VERSION 5.8 ;
BUSBITCHARS "[]" ;
DIVIDERCHAR "/" ;
UNITS
    DATABASE MICRONS 1000 ;
END UNITS

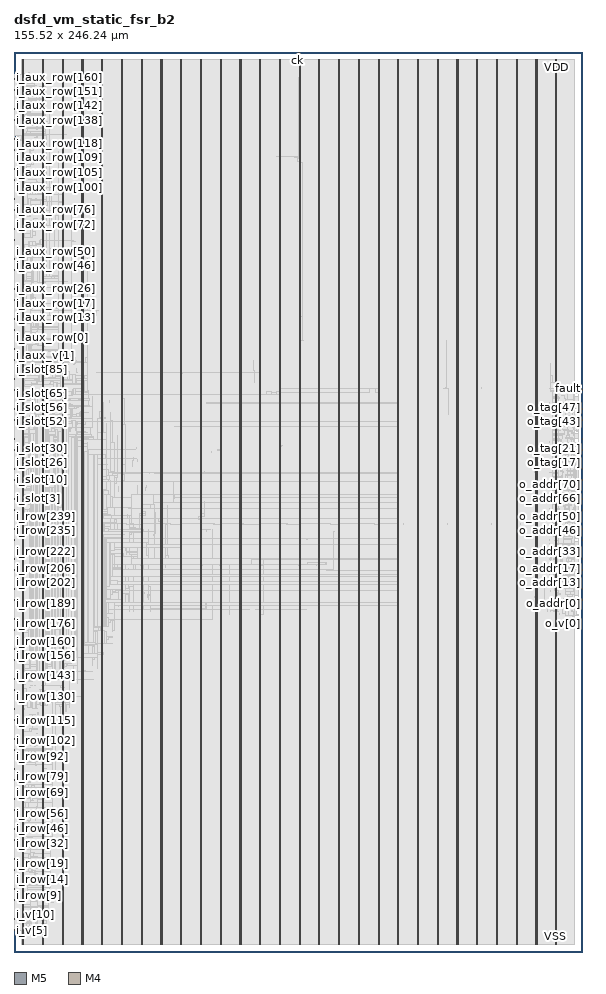
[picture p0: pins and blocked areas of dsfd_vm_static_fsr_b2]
MACRO dsfd_vm_static_fsr_b2
  FOREIGN dsfd_vm_static_fsr_b2 0 0 ;
  CLASS BLOCK ;
  SIZE 155.52 BY 246.24 ;
  PIN ck
    DIRECTION INPUT ;
    USE SIGNAL ;
    PORT
      LAYER M5 ;
        RECT  77.52 246.156 77.544 246.24 ;
    END
  END ck
  PIN fault
    DIRECTION OUTPUT ;
    USE SIGNAL ;
    PORT
      LAYER M4 ;
        RECT  155.436 154.176 155.52 154.2 ;
    END
  END fault
  PIN i_aux_row[0]
    DIRECTION INPUT ;
    USE SIGNAL ;
    PORT
      LAYER M4 ;
        RECT  0 168 0.084 168.024 ;
    END
  END i_aux_row[0]
  PIN i_aux_row[100]
    DIRECTION INPUT ;
    USE SIGNAL ;
    PORT
      LAYER M4 ;
        RECT  0 211.2 0.084 211.224 ;
    END
  END i_aux_row[100]
  PIN i_aux_row[101]
    DIRECTION INPUT ;
    USE SIGNAL ;
    PORT
      LAYER M4 ;
        RECT  0 211.632 0.084 211.656 ;
    END
  END i_aux_row[101]
  PIN i_aux_row[102]
    DIRECTION INPUT ;
    USE SIGNAL ;
    PORT
      LAYER M4 ;
        RECT  0 212.064 0.084 212.088 ;
    END
  END i_aux_row[102]
  PIN i_aux_row[103]
    DIRECTION INPUT ;
    USE SIGNAL ;
    PORT
      LAYER M4 ;
        RECT  0 212.496 0.084 212.52 ;
    END
  END i_aux_row[103]
  PIN i_aux_row[104]
    DIRECTION INPUT ;
    USE SIGNAL ;
    PORT
      LAYER M4 ;
        RECT  0 212.928 0.084 212.952 ;
    END
  END i_aux_row[104]
  PIN i_aux_row[105]
    DIRECTION INPUT ;
    USE SIGNAL ;
    PORT
      LAYER M4 ;
        RECT  0 213.36 0.084 213.384 ;
    END
  END i_aux_row[105]
  PIN i_aux_row[106]
    DIRECTION INPUT ;
    USE SIGNAL ;
    PORT
      LAYER M4 ;
        RECT  0 213.792 0.084 213.816 ;
    END
  END i_aux_row[106]
  PIN i_aux_row[107]
    DIRECTION INPUT ;
    USE SIGNAL ;
    PORT
      LAYER M4 ;
        RECT  0 214.224 0.084 214.248 ;
    END
  END i_aux_row[107]
  PIN i_aux_row[108]
    DIRECTION INPUT ;
    USE SIGNAL ;
    PORT
      LAYER M4 ;
        RECT  0 214.656 0.084 214.68 ;
    END
  END i_aux_row[108]
  PIN i_aux_row[109]
    DIRECTION INPUT ;
    USE SIGNAL ;
    PORT
      LAYER M4 ;
        RECT  0 215.088 0.084 215.112 ;
    END
  END i_aux_row[109]
  PIN i_aux_row[10]
    DIRECTION INPUT ;
    USE SIGNAL ;
    PORT
      LAYER M4 ;
        RECT  0 172.32 0.084 172.344 ;
    END
  END i_aux_row[10]
  PIN i_aux_row[110]
    DIRECTION INPUT ;
    USE SIGNAL ;
    PORT
      LAYER M4 ;
        RECT  0 215.52 0.084 215.544 ;
    END
  END i_aux_row[110]
  PIN i_aux_row[111]
    DIRECTION INPUT ;
    USE SIGNAL ;
    PORT
      LAYER M4 ;
        RECT  0 215.952 0.084 215.976 ;
    END
  END i_aux_row[111]
  PIN i_aux_row[112]
    DIRECTION INPUT ;
    USE SIGNAL ;
    PORT
      LAYER M4 ;
        RECT  0 216.384 0.084 216.408 ;
    END
  END i_aux_row[112]
  PIN i_aux_row[113]
    DIRECTION INPUT ;
    USE SIGNAL ;
    PORT
      LAYER M4 ;
        RECT  0 216.816 0.084 216.84 ;
    END
  END i_aux_row[113]
  PIN i_aux_row[114]
    DIRECTION INPUT ;
    USE SIGNAL ;
    PORT
      LAYER M4 ;
        RECT  0 217.248 0.084 217.272 ;
    END
  END i_aux_row[114]
  PIN i_aux_row[115]
    DIRECTION INPUT ;
    USE SIGNAL ;
    PORT
      LAYER M4 ;
        RECT  0 217.68 0.084 217.704 ;
    END
  END i_aux_row[115]
  PIN i_aux_row[116]
    DIRECTION INPUT ;
    USE SIGNAL ;
    PORT
      LAYER M4 ;
        RECT  0 218.112 0.084 218.136 ;
    END
  END i_aux_row[116]
  PIN i_aux_row[117]
    DIRECTION INPUT ;
    USE SIGNAL ;
    PORT
      LAYER M4 ;
        RECT  0 218.544 0.084 218.568 ;
    END
  END i_aux_row[117]
  PIN i_aux_row[118]
    DIRECTION INPUT ;
    USE SIGNAL ;
    PORT
      LAYER M4 ;
        RECT  0 218.976 0.084 219 ;
    END
  END i_aux_row[118]
  PIN i_aux_row[119]
    DIRECTION INPUT ;
    USE SIGNAL ;
    PORT
      LAYER M4 ;
        RECT  0 219.408 0.084 219.432 ;
    END
  END i_aux_row[119]
  PIN i_aux_row[11]
    DIRECTION INPUT ;
    USE SIGNAL ;
    PORT
      LAYER M4 ;
        RECT  0 172.752 0.084 172.776 ;
    END
  END i_aux_row[11]
  PIN i_aux_row[120]
    DIRECTION INPUT ;
    USE SIGNAL ;
    PORT
      LAYER M4 ;
        RECT  0 219.84 0.084 219.864 ;
    END
  END i_aux_row[120]
  PIN i_aux_row[121]
    DIRECTION INPUT ;
    USE SIGNAL ;
    PORT
      LAYER M4 ;
        RECT  0 220.272 0.084 220.296 ;
    END
  END i_aux_row[121]
  PIN i_aux_row[122]
    DIRECTION INPUT ;
    USE SIGNAL ;
    PORT
      LAYER M4 ;
        RECT  0 220.704 0.084 220.728 ;
    END
  END i_aux_row[122]
  PIN i_aux_row[123]
    DIRECTION INPUT ;
    USE SIGNAL ;
    PORT
      LAYER M4 ;
        RECT  0 221.136 0.084 221.16 ;
    END
  END i_aux_row[123]
  PIN i_aux_row[124]
    DIRECTION INPUT ;
    USE SIGNAL ;
    PORT
      LAYER M4 ;
        RECT  0 221.568 0.084 221.592 ;
    END
  END i_aux_row[124]
  PIN i_aux_row[125]
    DIRECTION INPUT ;
    USE SIGNAL ;
    PORT
      LAYER M4 ;
        RECT  0 222 0.084 222.024 ;
    END
  END i_aux_row[125]
  PIN i_aux_row[126]
    DIRECTION INPUT ;
    USE SIGNAL ;
    PORT
      LAYER M4 ;
        RECT  0 222.432 0.084 222.456 ;
    END
  END i_aux_row[126]
  PIN i_aux_row[127]
    DIRECTION INPUT ;
    USE SIGNAL ;
    PORT
      LAYER M4 ;
        RECT  0 222.864 0.084 222.888 ;
    END
  END i_aux_row[127]
  PIN i_aux_row[128]
    DIRECTION INPUT ;
    USE SIGNAL ;
    PORT
      LAYER M4 ;
        RECT  0 223.296 0.084 223.32 ;
    END
  END i_aux_row[128]
  PIN i_aux_row[129]
    DIRECTION INPUT ;
    USE SIGNAL ;
    PORT
      LAYER M4 ;
        RECT  0 223.728 0.084 223.752 ;
    END
  END i_aux_row[129]
  PIN i_aux_row[12]
    DIRECTION INPUT ;
    USE SIGNAL ;
    PORT
      LAYER M4 ;
        RECT  0 173.184 0.084 173.208 ;
    END
  END i_aux_row[12]
  PIN i_aux_row[130]
    DIRECTION INPUT ;
    USE SIGNAL ;
    PORT
      LAYER M4 ;
        RECT  0 224.16 0.084 224.184 ;
    END
  END i_aux_row[130]
  PIN i_aux_row[131]
    DIRECTION INPUT ;
    USE SIGNAL ;
    PORT
      LAYER M4 ;
        RECT  0 224.592 0.084 224.616 ;
    END
  END i_aux_row[131]
  PIN i_aux_row[132]
    DIRECTION INPUT ;
    USE SIGNAL ;
    PORT
      LAYER M4 ;
        RECT  0 225.024 0.084 225.048 ;
    END
  END i_aux_row[132]
  PIN i_aux_row[133]
    DIRECTION INPUT ;
    USE SIGNAL ;
    PORT
      LAYER M4 ;
        RECT  0 225.456 0.084 225.48 ;
    END
  END i_aux_row[133]
  PIN i_aux_row[134]
    DIRECTION INPUT ;
    USE SIGNAL ;
    PORT
      LAYER M4 ;
        RECT  0 225.888 0.084 225.912 ;
    END
  END i_aux_row[134]
  PIN i_aux_row[135]
    DIRECTION INPUT ;
    USE SIGNAL ;
    PORT
      LAYER M4 ;
        RECT  0 226.32 0.084 226.344 ;
    END
  END i_aux_row[135]
  PIN i_aux_row[136]
    DIRECTION INPUT ;
    USE SIGNAL ;
    PORT
      LAYER M4 ;
        RECT  0 226.752 0.084 226.776 ;
    END
  END i_aux_row[136]
  PIN i_aux_row[137]
    DIRECTION INPUT ;
    USE SIGNAL ;
    PORT
      LAYER M4 ;
        RECT  0 227.184 0.084 227.208 ;
    END
  END i_aux_row[137]
  PIN i_aux_row[138]
    DIRECTION INPUT ;
    USE SIGNAL ;
    PORT
      LAYER M4 ;
        RECT  0 227.616 0.084 227.64 ;
    END
  END i_aux_row[138]
  PIN i_aux_row[139]
    DIRECTION INPUT ;
    USE SIGNAL ;
    PORT
      LAYER M4 ;
        RECT  0 228.048 0.084 228.072 ;
    END
  END i_aux_row[139]
  PIN i_aux_row[13]
    DIRECTION INPUT ;
    USE SIGNAL ;
    PORT
      LAYER M4 ;
        RECT  0 173.616 0.084 173.64 ;
    END
  END i_aux_row[13]
  PIN i_aux_row[140]
    DIRECTION INPUT ;
    USE SIGNAL ;
    PORT
      LAYER M4 ;
        RECT  0 228.48 0.084 228.504 ;
    END
  END i_aux_row[140]
  PIN i_aux_row[141]
    DIRECTION INPUT ;
    USE SIGNAL ;
    PORT
      LAYER M4 ;
        RECT  0 228.912 0.084 228.936 ;
    END
  END i_aux_row[141]
  PIN i_aux_row[142]
    DIRECTION INPUT ;
    USE SIGNAL ;
    PORT
      LAYER M4 ;
        RECT  0 229.344 0.084 229.368 ;
    END
  END i_aux_row[142]
  PIN i_aux_row[143]
    DIRECTION INPUT ;
    USE SIGNAL ;
    PORT
      LAYER M4 ;
        RECT  0 229.776 0.084 229.8 ;
    END
  END i_aux_row[143]
  PIN i_aux_row[144]
    DIRECTION INPUT ;
    USE SIGNAL ;
    PORT
      LAYER M4 ;
        RECT  0 230.208 0.084 230.232 ;
    END
  END i_aux_row[144]
  PIN i_aux_row[145]
    DIRECTION INPUT ;
    USE SIGNAL ;
    PORT
      LAYER M4 ;
        RECT  0 230.64 0.084 230.664 ;
    END
  END i_aux_row[145]
  PIN i_aux_row[146]
    DIRECTION INPUT ;
    USE SIGNAL ;
    PORT
      LAYER M4 ;
        RECT  0 231.072 0.084 231.096 ;
    END
  END i_aux_row[146]
  PIN i_aux_row[147]
    DIRECTION INPUT ;
    USE SIGNAL ;
    PORT
      LAYER M4 ;
        RECT  0 231.504 0.084 231.528 ;
    END
  END i_aux_row[147]
  PIN i_aux_row[148]
    DIRECTION INPUT ;
    USE SIGNAL ;
    PORT
      LAYER M4 ;
        RECT  0 231.936 0.084 231.96 ;
    END
  END i_aux_row[148]
  PIN i_aux_row[149]
    DIRECTION INPUT ;
    USE SIGNAL ;
    PORT
      LAYER M4 ;
        RECT  0 232.368 0.084 232.392 ;
    END
  END i_aux_row[149]
  PIN i_aux_row[14]
    DIRECTION INPUT ;
    USE SIGNAL ;
    PORT
      LAYER M4 ;
        RECT  0 174.048 0.084 174.072 ;
    END
  END i_aux_row[14]
  PIN i_aux_row[150]
    DIRECTION INPUT ;
    USE SIGNAL ;
    PORT
      LAYER M4 ;
        RECT  0 232.8 0.084 232.824 ;
    END
  END i_aux_row[150]
  PIN i_aux_row[151]
    DIRECTION INPUT ;
    USE SIGNAL ;
    PORT
      LAYER M4 ;
        RECT  0 233.232 0.084 233.256 ;
    END
  END i_aux_row[151]
  PIN i_aux_row[152]
    DIRECTION INPUT ;
    USE SIGNAL ;
    PORT
      LAYER M4 ;
        RECT  0 233.664 0.084 233.688 ;
    END
  END i_aux_row[152]
  PIN i_aux_row[153]
    DIRECTION INPUT ;
    USE SIGNAL ;
    PORT
      LAYER M4 ;
        RECT  0 234.096 0.084 234.12 ;
    END
  END i_aux_row[153]
  PIN i_aux_row[154]
    DIRECTION INPUT ;
    USE SIGNAL ;
    PORT
      LAYER M4 ;
        RECT  0 234.528 0.084 234.552 ;
    END
  END i_aux_row[154]
  PIN i_aux_row[155]
    DIRECTION INPUT ;
    USE SIGNAL ;
    PORT
      LAYER M4 ;
        RECT  0 234.96 0.084 234.984 ;
    END
  END i_aux_row[155]
  PIN i_aux_row[156]
    DIRECTION INPUT ;
    USE SIGNAL ;
    PORT
      LAYER M4 ;
        RECT  0 235.392 0.084 235.416 ;
    END
  END i_aux_row[156]
  PIN i_aux_row[157]
    DIRECTION INPUT ;
    USE SIGNAL ;
    PORT
      LAYER M4 ;
        RECT  0 235.824 0.084 235.848 ;
    END
  END i_aux_row[157]
  PIN i_aux_row[158]
    DIRECTION INPUT ;
    USE SIGNAL ;
    PORT
      LAYER M4 ;
        RECT  0 236.256 0.084 236.28 ;
    END
  END i_aux_row[158]
  PIN i_aux_row[159]
    DIRECTION INPUT ;
    USE SIGNAL ;
    PORT
      LAYER M4 ;
        RECT  0 236.688 0.084 236.712 ;
    END
  END i_aux_row[159]
  PIN i_aux_row[15]
    DIRECTION INPUT ;
    USE SIGNAL ;
    PORT
      LAYER M4 ;
        RECT  0 174.48 0.084 174.504 ;
    END
  END i_aux_row[15]
  PIN i_aux_row[160]
    DIRECTION INPUT ;
    USE SIGNAL ;
    PORT
      LAYER M4 ;
        RECT  0 237.12 0.084 237.144 ;
    END
  END i_aux_row[160]
  PIN i_aux_row[161]
    DIRECTION INPUT ;
    USE SIGNAL ;
    PORT
      LAYER M4 ;
        RECT  0 237.552 0.084 237.576 ;
    END
  END i_aux_row[161]
  PIN i_aux_row[162]
    DIRECTION INPUT ;
    USE SIGNAL ;
    PORT
      LAYER M4 ;
        RECT  0 237.984 0.084 238.008 ;
    END
  END i_aux_row[162]
  PIN i_aux_row[163]
    DIRECTION INPUT ;
    USE SIGNAL ;
    PORT
      LAYER M4 ;
        RECT  0 238.416 0.084 238.44 ;
    END
  END i_aux_row[163]
  PIN i_aux_row[164]
    DIRECTION INPUT ;
    USE SIGNAL ;
    PORT
      LAYER M4 ;
        RECT  0 238.848 0.084 238.872 ;
    END
  END i_aux_row[164]
  PIN i_aux_row[165]
    DIRECTION INPUT ;
    USE SIGNAL ;
    PORT
      LAYER M4 ;
        RECT  0 239.28 0.084 239.304 ;
    END
  END i_aux_row[165]
  PIN i_aux_row[166]
    DIRECTION INPUT ;
    USE SIGNAL ;
    PORT
      LAYER M4 ;
        RECT  0 239.712 0.084 239.736 ;
    END
  END i_aux_row[166]
  PIN i_aux_row[167]
    DIRECTION INPUT ;
    USE SIGNAL ;
    PORT
      LAYER M4 ;
        RECT  0 240.144 0.084 240.168 ;
    END
  END i_aux_row[167]
  PIN i_aux_row[16]
    DIRECTION INPUT ;
    USE SIGNAL ;
    PORT
      LAYER M4 ;
        RECT  0 174.912 0.084 174.936 ;
    END
  END i_aux_row[16]
  PIN i_aux_row[17]
    DIRECTION INPUT ;
    USE SIGNAL ;
    PORT
      LAYER M4 ;
        RECT  0 175.344 0.084 175.368 ;
    END
  END i_aux_row[17]
  PIN i_aux_row[18]
    DIRECTION INPUT ;
    USE SIGNAL ;
    PORT
      LAYER M4 ;
        RECT  0 175.776 0.084 175.8 ;
    END
  END i_aux_row[18]
  PIN i_aux_row[19]
    DIRECTION INPUT ;
    USE SIGNAL ;
    PORT
      LAYER M4 ;
        RECT  0 176.208 0.084 176.232 ;
    END
  END i_aux_row[19]
  PIN i_aux_row[1]
    DIRECTION INPUT ;
    USE SIGNAL ;
    PORT
      LAYER M4 ;
        RECT  0 168.432 0.084 168.456 ;
    END
  END i_aux_row[1]
  PIN i_aux_row[20]
    DIRECTION INPUT ;
    USE SIGNAL ;
    PORT
      LAYER M4 ;
        RECT  0 176.64 0.084 176.664 ;
    END
  END i_aux_row[20]
  PIN i_aux_row[21]
    DIRECTION INPUT ;
    USE SIGNAL ;
    PORT
      LAYER M4 ;
        RECT  0 177.072 0.084 177.096 ;
    END
  END i_aux_row[21]
  PIN i_aux_row[22]
    DIRECTION INPUT ;
    USE SIGNAL ;
    PORT
      LAYER M4 ;
        RECT  0 177.504 0.084 177.528 ;
    END
  END i_aux_row[22]
  PIN i_aux_row[23]
    DIRECTION INPUT ;
    USE SIGNAL ;
    PORT
      LAYER M4 ;
        RECT  0 177.936 0.084 177.96 ;
    END
  END i_aux_row[23]
  PIN i_aux_row[24]
    DIRECTION INPUT ;
    USE SIGNAL ;
    PORT
      LAYER M4 ;
        RECT  0 178.368 0.084 178.392 ;
    END
  END i_aux_row[24]
  PIN i_aux_row[25]
    DIRECTION INPUT ;
    USE SIGNAL ;
    PORT
      LAYER M4 ;
        RECT  0 178.8 0.084 178.824 ;
    END
  END i_aux_row[25]
  PIN i_aux_row[26]
    DIRECTION INPUT ;
    USE SIGNAL ;
    PORT
      LAYER M4 ;
        RECT  0 179.232 0.084 179.256 ;
    END
  END i_aux_row[26]
  PIN i_aux_row[27]
    DIRECTION INPUT ;
    USE SIGNAL ;
    PORT
      LAYER M4 ;
        RECT  0 179.664 0.084 179.688 ;
    END
  END i_aux_row[27]
  PIN i_aux_row[28]
    DIRECTION INPUT ;
    USE SIGNAL ;
    PORT
      LAYER M4 ;
        RECT  0 180.096 0.084 180.12 ;
    END
  END i_aux_row[28]
  PIN i_aux_row[29]
    DIRECTION INPUT ;
    USE SIGNAL ;
    PORT
      LAYER M4 ;
        RECT  0 180.528 0.084 180.552 ;
    END
  END i_aux_row[29]
  PIN i_aux_row[2]
    DIRECTION INPUT ;
    USE SIGNAL ;
    PORT
      LAYER M4 ;
        RECT  0 168.864 0.084 168.888 ;
    END
  END i_aux_row[2]
  PIN i_aux_row[30]
    DIRECTION INPUT ;
    USE SIGNAL ;
    PORT
      LAYER M4 ;
        RECT  0 180.96 0.084 180.984 ;
    END
  END i_aux_row[30]
  PIN i_aux_row[31]
    DIRECTION INPUT ;
    USE SIGNAL ;
    PORT
      LAYER M4 ;
        RECT  0 181.392 0.084 181.416 ;
    END
  END i_aux_row[31]
  PIN i_aux_row[32]
    DIRECTION INPUT ;
    USE SIGNAL ;
    PORT
      LAYER M4 ;
        RECT  0 181.824 0.084 181.848 ;
    END
  END i_aux_row[32]
  PIN i_aux_row[33]
    DIRECTION INPUT ;
    USE SIGNAL ;
    PORT
      LAYER M4 ;
        RECT  0 182.256 0.084 182.28 ;
    END
  END i_aux_row[33]
  PIN i_aux_row[34]
    DIRECTION INPUT ;
    USE SIGNAL ;
    PORT
      LAYER M4 ;
        RECT  0 182.688 0.084 182.712 ;
    END
  END i_aux_row[34]
  PIN i_aux_row[35]
    DIRECTION INPUT ;
    USE SIGNAL ;
    PORT
      LAYER M4 ;
        RECT  0 183.12 0.084 183.144 ;
    END
  END i_aux_row[35]
  PIN i_aux_row[36]
    DIRECTION INPUT ;
    USE SIGNAL ;
    PORT
      LAYER M4 ;
        RECT  0 183.552 0.084 183.576 ;
    END
  END i_aux_row[36]
  PIN i_aux_row[37]
    DIRECTION INPUT ;
    USE SIGNAL ;
    PORT
      LAYER M4 ;
        RECT  0 183.984 0.084 184.008 ;
    END
  END i_aux_row[37]
  PIN i_aux_row[38]
    DIRECTION INPUT ;
    USE SIGNAL ;
    PORT
      LAYER M4 ;
        RECT  0 184.416 0.084 184.44 ;
    END
  END i_aux_row[38]
  PIN i_aux_row[39]
    DIRECTION INPUT ;
    USE SIGNAL ;
    PORT
      LAYER M4 ;
        RECT  0 184.848 0.084 184.872 ;
    END
  END i_aux_row[39]
  PIN i_aux_row[3]
    DIRECTION INPUT ;
    USE SIGNAL ;
    PORT
      LAYER M4 ;
        RECT  0 169.296 0.084 169.32 ;
    END
  END i_aux_row[3]
  PIN i_aux_row[40]
    DIRECTION INPUT ;
    USE SIGNAL ;
    PORT
      LAYER M4 ;
        RECT  0 185.28 0.084 185.304 ;
    END
  END i_aux_row[40]
  PIN i_aux_row[41]
    DIRECTION INPUT ;
    USE SIGNAL ;
    PORT
      LAYER M4 ;
        RECT  0 185.712 0.084 185.736 ;
    END
  END i_aux_row[41]
  PIN i_aux_row[42]
    DIRECTION INPUT ;
    USE SIGNAL ;
    PORT
      LAYER M4 ;
        RECT  0 186.144 0.084 186.168 ;
    END
  END i_aux_row[42]
  PIN i_aux_row[43]
    DIRECTION INPUT ;
    USE SIGNAL ;
    PORT
      LAYER M4 ;
        RECT  0 186.576 0.084 186.6 ;
    END
  END i_aux_row[43]
  PIN i_aux_row[44]
    DIRECTION INPUT ;
    USE SIGNAL ;
    PORT
      LAYER M4 ;
        RECT  0 187.008 0.084 187.032 ;
    END
  END i_aux_row[44]
  PIN i_aux_row[45]
    DIRECTION INPUT ;
    USE SIGNAL ;
    PORT
      LAYER M4 ;
        RECT  0 187.44 0.084 187.464 ;
    END
  END i_aux_row[45]
  PIN i_aux_row[46]
    DIRECTION INPUT ;
    USE SIGNAL ;
    PORT
      LAYER M4 ;
        RECT  0 187.872 0.084 187.896 ;
    END
  END i_aux_row[46]
  PIN i_aux_row[47]
    DIRECTION INPUT ;
    USE SIGNAL ;
    PORT
      LAYER M4 ;
        RECT  0 188.304 0.084 188.328 ;
    END
  END i_aux_row[47]
  PIN i_aux_row[48]
    DIRECTION INPUT ;
    USE SIGNAL ;
    PORT
      LAYER M4 ;
        RECT  0 188.736 0.084 188.76 ;
    END
  END i_aux_row[48]
  PIN i_aux_row[49]
    DIRECTION INPUT ;
    USE SIGNAL ;
    PORT
      LAYER M4 ;
        RECT  0 189.168 0.084 189.192 ;
    END
  END i_aux_row[49]
  PIN i_aux_row[4]
    DIRECTION INPUT ;
    USE SIGNAL ;
    PORT
      LAYER M4 ;
        RECT  0 169.728 0.084 169.752 ;
    END
  END i_aux_row[4]
  PIN i_aux_row[50]
    DIRECTION INPUT ;
    USE SIGNAL ;
    PORT
      LAYER M4 ;
        RECT  0 189.6 0.084 189.624 ;
    END
  END i_aux_row[50]
  PIN i_aux_row[51]
    DIRECTION INPUT ;
    USE SIGNAL ;
    PORT
      LAYER M4 ;
        RECT  0 190.032 0.084 190.056 ;
    END
  END i_aux_row[51]
  PIN i_aux_row[52]
    DIRECTION INPUT ;
    USE SIGNAL ;
    PORT
      LAYER M4 ;
        RECT  0 190.464 0.084 190.488 ;
    END
  END i_aux_row[52]
  PIN i_aux_row[53]
    DIRECTION INPUT ;
    USE SIGNAL ;
    PORT
      LAYER M4 ;
        RECT  0 190.896 0.084 190.92 ;
    END
  END i_aux_row[53]
  PIN i_aux_row[54]
    DIRECTION INPUT ;
    USE SIGNAL ;
    PORT
      LAYER M4 ;
        RECT  0 191.328 0.084 191.352 ;
    END
  END i_aux_row[54]
  PIN i_aux_row[55]
    DIRECTION INPUT ;
    USE SIGNAL ;
    PORT
      LAYER M4 ;
        RECT  0 191.76 0.084 191.784 ;
    END
  END i_aux_row[55]
  PIN i_aux_row[56]
    DIRECTION INPUT ;
    USE SIGNAL ;
    PORT
      LAYER M4 ;
        RECT  0 192.192 0.084 192.216 ;
    END
  END i_aux_row[56]
  PIN i_aux_row[57]
    DIRECTION INPUT ;
    USE SIGNAL ;
    PORT
      LAYER M4 ;
        RECT  0 192.624 0.084 192.648 ;
    END
  END i_aux_row[57]
  PIN i_aux_row[58]
    DIRECTION INPUT ;
    USE SIGNAL ;
    PORT
      LAYER M4 ;
        RECT  0 193.056 0.084 193.08 ;
    END
  END i_aux_row[58]
  PIN i_aux_row[59]
    DIRECTION INPUT ;
    USE SIGNAL ;
    PORT
      LAYER M4 ;
        RECT  0 193.488 0.084 193.512 ;
    END
  END i_aux_row[59]
  PIN i_aux_row[5]
    DIRECTION INPUT ;
    USE SIGNAL ;
    PORT
      LAYER M4 ;
        RECT  0 170.16 0.084 170.184 ;
    END
  END i_aux_row[5]
  PIN i_aux_row[60]
    DIRECTION INPUT ;
    USE SIGNAL ;
    PORT
      LAYER M4 ;
        RECT  0 193.92 0.084 193.944 ;
    END
  END i_aux_row[60]
  PIN i_aux_row[61]
    DIRECTION INPUT ;
    USE SIGNAL ;
    PORT
      LAYER M4 ;
        RECT  0 194.352 0.084 194.376 ;
    END
  END i_aux_row[61]
  PIN i_aux_row[62]
    DIRECTION INPUT ;
    USE SIGNAL ;
    PORT
      LAYER M4 ;
        RECT  0 194.784 0.084 194.808 ;
    END
  END i_aux_row[62]
  PIN i_aux_row[63]
    DIRECTION INPUT ;
    USE SIGNAL ;
    PORT
      LAYER M4 ;
        RECT  0 195.216 0.084 195.24 ;
    END
  END i_aux_row[63]
  PIN i_aux_row[64]
    DIRECTION INPUT ;
    USE SIGNAL ;
    PORT
      LAYER M4 ;
        RECT  0 195.648 0.084 195.672 ;
    END
  END i_aux_row[64]
  PIN i_aux_row[65]
    DIRECTION INPUT ;
    USE SIGNAL ;
    PORT
      LAYER M4 ;
        RECT  0 196.08 0.084 196.104 ;
    END
  END i_aux_row[65]
  PIN i_aux_row[66]
    DIRECTION INPUT ;
    USE SIGNAL ;
    PORT
      LAYER M4 ;
        RECT  0 196.512 0.084 196.536 ;
    END
  END i_aux_row[66]
  PIN i_aux_row[67]
    DIRECTION INPUT ;
    USE SIGNAL ;
    PORT
      LAYER M4 ;
        RECT  0 196.944 0.084 196.968 ;
    END
  END i_aux_row[67]
  PIN i_aux_row[68]
    DIRECTION INPUT ;
    USE SIGNAL ;
    PORT
      LAYER M4 ;
        RECT  0 197.376 0.084 197.4 ;
    END
  END i_aux_row[68]
  PIN i_aux_row[69]
    DIRECTION INPUT ;
    USE SIGNAL ;
    PORT
      LAYER M4 ;
        RECT  0 197.808 0.084 197.832 ;
    END
  END i_aux_row[69]
  PIN i_aux_row[6]
    DIRECTION INPUT ;
    USE SIGNAL ;
    PORT
      LAYER M4 ;
        RECT  0 170.592 0.084 170.616 ;
    END
  END i_aux_row[6]
  PIN i_aux_row[70]
    DIRECTION INPUT ;
    USE SIGNAL ;
    PORT
      LAYER M4 ;
        RECT  0 198.24 0.084 198.264 ;
    END
  END i_aux_row[70]
  PIN i_aux_row[71]
    DIRECTION INPUT ;
    USE SIGNAL ;
    PORT
      LAYER M4 ;
        RECT  0 198.672 0.084 198.696 ;
    END
  END i_aux_row[71]
  PIN i_aux_row[72]
    DIRECTION INPUT ;
    USE SIGNAL ;
    PORT
      LAYER M4 ;
        RECT  0 199.104 0.084 199.128 ;
    END
  END i_aux_row[72]
  PIN i_aux_row[73]
    DIRECTION INPUT ;
    USE SIGNAL ;
    PORT
      LAYER M4 ;
        RECT  0 199.536 0.084 199.56 ;
    END
  END i_aux_row[73]
  PIN i_aux_row[74]
    DIRECTION INPUT ;
    USE SIGNAL ;
    PORT
      LAYER M4 ;
        RECT  0 199.968 0.084 199.992 ;
    END
  END i_aux_row[74]
  PIN i_aux_row[75]
    DIRECTION INPUT ;
    USE SIGNAL ;
    PORT
      LAYER M4 ;
        RECT  0 200.4 0.084 200.424 ;
    END
  END i_aux_row[75]
  PIN i_aux_row[76]
    DIRECTION INPUT ;
    USE SIGNAL ;
    PORT
      LAYER M4 ;
        RECT  0 200.832 0.084 200.856 ;
    END
  END i_aux_row[76]
  PIN i_aux_row[77]
    DIRECTION INPUT ;
    USE SIGNAL ;
    PORT
      LAYER M4 ;
        RECT  0 201.264 0.084 201.288 ;
    END
  END i_aux_row[77]
  PIN i_aux_row[78]
    DIRECTION INPUT ;
    USE SIGNAL ;
    PORT
      LAYER M4 ;
        RECT  0 201.696 0.084 201.72 ;
    END
  END i_aux_row[78]
  PIN i_aux_row[79]
    DIRECTION INPUT ;
    USE SIGNAL ;
    PORT
      LAYER M4 ;
        RECT  0 202.128 0.084 202.152 ;
    END
  END i_aux_row[79]
  PIN i_aux_row[7]
    DIRECTION INPUT ;
    USE SIGNAL ;
    PORT
      LAYER M4 ;
        RECT  0 171.024 0.084 171.048 ;
    END
  END i_aux_row[7]
  PIN i_aux_row[80]
    DIRECTION INPUT ;
    USE SIGNAL ;
    PORT
      LAYER M4 ;
        RECT  0 202.56 0.084 202.584 ;
    END
  END i_aux_row[80]
  PIN i_aux_row[81]
    DIRECTION INPUT ;
    USE SIGNAL ;
    PORT
      LAYER M4 ;
        RECT  0 202.992 0.084 203.016 ;
    END
  END i_aux_row[81]
  PIN i_aux_row[82]
    DIRECTION INPUT ;
    USE SIGNAL ;
    PORT
      LAYER M4 ;
        RECT  0 203.424 0.084 203.448 ;
    END
  END i_aux_row[82]
  PIN i_aux_row[83]
    DIRECTION INPUT ;
    USE SIGNAL ;
    PORT
      LAYER M4 ;
        RECT  0 203.856 0.084 203.88 ;
    END
  END i_aux_row[83]
  PIN i_aux_row[84]
    DIRECTION INPUT ;
    USE SIGNAL ;
    PORT
      LAYER M4 ;
        RECT  0 204.288 0.084 204.312 ;
    END
  END i_aux_row[84]
  PIN i_aux_row[85]
    DIRECTION INPUT ;
    USE SIGNAL ;
    PORT
      LAYER M4 ;
        RECT  0 204.72 0.084 204.744 ;
    END
  END i_aux_row[85]
  PIN i_aux_row[86]
    DIRECTION INPUT ;
    USE SIGNAL ;
    PORT
      LAYER M4 ;
        RECT  0 205.152 0.084 205.176 ;
    END
  END i_aux_row[86]
  PIN i_aux_row[87]
    DIRECTION INPUT ;
    USE SIGNAL ;
    PORT
      LAYER M4 ;
        RECT  0 205.584 0.084 205.608 ;
    END
  END i_aux_row[87]
  PIN i_aux_row[88]
    DIRECTION INPUT ;
    USE SIGNAL ;
    PORT
      LAYER M4 ;
        RECT  0 206.016 0.084 206.04 ;
    END
  END i_aux_row[88]
  PIN i_aux_row[89]
    DIRECTION INPUT ;
    USE SIGNAL ;
    PORT
      LAYER M4 ;
        RECT  0 206.448 0.084 206.472 ;
    END
  END i_aux_row[89]
  PIN i_aux_row[8]
    DIRECTION INPUT ;
    USE SIGNAL ;
    PORT
      LAYER M4 ;
        RECT  0 171.456 0.084 171.48 ;
    END
  END i_aux_row[8]
  PIN i_aux_row[90]
    DIRECTION INPUT ;
    USE SIGNAL ;
    PORT
      LAYER M4 ;
        RECT  0 206.88 0.084 206.904 ;
    END
  END i_aux_row[90]
  PIN i_aux_row[91]
    DIRECTION INPUT ;
    USE SIGNAL ;
    PORT
      LAYER M4 ;
        RECT  0 207.312 0.084 207.336 ;
    END
  END i_aux_row[91]
  PIN i_aux_row[92]
    DIRECTION INPUT ;
    USE SIGNAL ;
    PORT
      LAYER M4 ;
        RECT  0 207.744 0.084 207.768 ;
    END
  END i_aux_row[92]
  PIN i_aux_row[93]
    DIRECTION INPUT ;
    USE SIGNAL ;
    PORT
      LAYER M4 ;
        RECT  0 208.176 0.084 208.2 ;
    END
  END i_aux_row[93]
  PIN i_aux_row[94]
    DIRECTION INPUT ;
    USE SIGNAL ;
    PORT
      LAYER M4 ;
        RECT  0 208.608 0.084 208.632 ;
    END
  END i_aux_row[94]
  PIN i_aux_row[95]
    DIRECTION INPUT ;
    USE SIGNAL ;
    PORT
      LAYER M4 ;
        RECT  0 209.04 0.084 209.064 ;
    END
  END i_aux_row[95]
  PIN i_aux_row[96]
    DIRECTION INPUT ;
    USE SIGNAL ;
    PORT
      LAYER M4 ;
        RECT  0 209.472 0.084 209.496 ;
    END
  END i_aux_row[96]
  PIN i_aux_row[97]
    DIRECTION INPUT ;
    USE SIGNAL ;
    PORT
      LAYER M4 ;
        RECT  0 209.904 0.084 209.928 ;
    END
  END i_aux_row[97]
  PIN i_aux_row[98]
    DIRECTION INPUT ;
    USE SIGNAL ;
    PORT
      LAYER M4 ;
        RECT  0 210.336 0.084 210.36 ;
    END
  END i_aux_row[98]
  PIN i_aux_row[99]
    DIRECTION INPUT ;
    USE SIGNAL ;
    PORT
      LAYER M4 ;
        RECT  0 210.768 0.084 210.792 ;
    END
  END i_aux_row[99]
  PIN i_aux_row[9]
    DIRECTION INPUT ;
    USE SIGNAL ;
    PORT
      LAYER M4 ;
        RECT  0 171.888 0.084 171.912 ;
    END
  END i_aux_row[9]
  PIN i_aux_v[0]
    DIRECTION INPUT ;
    USE SIGNAL ;
    PORT
      LAYER M4 ;
        RECT  0 162.816 0.084 162.84 ;
    END
  END i_aux_v[0]
  PIN i_aux_v[10]
    DIRECTION INPUT ;
    USE SIGNAL ;
    PORT
      LAYER M4 ;
        RECT  0 167.136 0.084 167.16 ;
    END
  END i_aux_v[10]
  PIN i_aux_v[11]
    DIRECTION INPUT ;
    USE SIGNAL ;
    PORT
      LAYER M4 ;
        RECT  0 167.568 0.084 167.592 ;
    END
  END i_aux_v[11]
  PIN i_aux_v[1]
    DIRECTION INPUT ;
    USE SIGNAL ;
    PORT
      LAYER M4 ;
        RECT  0 163.248 0.084 163.272 ;
    END
  END i_aux_v[1]
  PIN i_aux_v[2]
    DIRECTION INPUT ;
    USE SIGNAL ;
    PORT
      LAYER M4 ;
        RECT  0 163.68 0.084 163.704 ;
    END
  END i_aux_v[2]
  PIN i_aux_v[3]
    DIRECTION INPUT ;
    USE SIGNAL ;
    PORT
      LAYER M4 ;
        RECT  0 164.112 0.084 164.136 ;
    END
  END i_aux_v[3]
  PIN i_aux_v[4]
    DIRECTION INPUT ;
    USE SIGNAL ;
    PORT
      LAYER M4 ;
        RECT  0 164.544 0.084 164.568 ;
    END
  END i_aux_v[4]
  PIN i_aux_v[5]
    DIRECTION INPUT ;
    USE SIGNAL ;
    PORT
      LAYER M4 ;
        RECT  0 164.976 0.084 165 ;
    END
  END i_aux_v[5]
  PIN i_aux_v[6]
    DIRECTION INPUT ;
    USE SIGNAL ;
    PORT
      LAYER M4 ;
        RECT  0 165.408 0.084 165.432 ;
    END
  END i_aux_v[6]
  PIN i_aux_v[7]
    DIRECTION INPUT ;
    USE SIGNAL ;
    PORT
      LAYER M4 ;
        RECT  0 165.84 0.084 165.864 ;
    END
  END i_aux_v[7]
  PIN i_aux_v[8]
    DIRECTION INPUT ;
    USE SIGNAL ;
    PORT
      LAYER M4 ;
        RECT  0 166.272 0.084 166.296 ;
    END
  END i_aux_v[8]
  PIN i_aux_v[9]
    DIRECTION INPUT ;
    USE SIGNAL ;
    PORT
      LAYER M4 ;
        RECT  0 166.704 0.084 166.728 ;
    END
  END i_aux_v[9]
  PIN i_group[0]
    DIRECTION INPUT ;
    USE SIGNAL ;
    PORT
      LAYER M4 ;
        RECT  0 161.52 0.084 161.544 ;
    END
  END i_group[0]
  PIN i_group[1]
    DIRECTION INPUT ;
    USE SIGNAL ;
    PORT
      LAYER M4 ;
        RECT  0 161.952 0.084 161.976 ;
    END
  END i_group[1]
  PIN i_group[2]
    DIRECTION INPUT ;
    USE SIGNAL ;
    PORT
      LAYER M4 ;
        RECT  0 162.384 0.084 162.408 ;
    END
  END i_group[2]
  PIN i_row[0]
    DIRECTION INPUT ;
    USE SIGNAL ;
    PORT
      LAYER M4 ;
        RECT  0 13.776 0.084 13.8 ;
    END
  END i_row[0]
  PIN i_row[100]
    DIRECTION INPUT ;
    USE SIGNAL ;
    PORT
      LAYER M4 ;
        RECT  0 56.976 0.084 57 ;
    END
  END i_row[100]
  PIN i_row[101]
    DIRECTION INPUT ;
    USE SIGNAL ;
    PORT
      LAYER M4 ;
        RECT  0 57.408 0.084 57.432 ;
    END
  END i_row[101]
  PIN i_row[102]
    DIRECTION INPUT ;
    USE SIGNAL ;
    PORT
      LAYER M4 ;
        RECT  0 57.84 0.084 57.864 ;
    END
  END i_row[102]
  PIN i_row[103]
    DIRECTION INPUT ;
    USE SIGNAL ;
    PORT
      LAYER M4 ;
        RECT  0 58.272 0.084 58.296 ;
    END
  END i_row[103]
  PIN i_row[104]
    DIRECTION INPUT ;
    USE SIGNAL ;
    PORT
      LAYER M4 ;
        RECT  0 58.704 0.084 58.728 ;
    END
  END i_row[104]
  PIN i_row[105]
    DIRECTION INPUT ;
    USE SIGNAL ;
    PORT
      LAYER M4 ;
        RECT  0 59.136 0.084 59.16 ;
    END
  END i_row[105]
  PIN i_row[106]
    DIRECTION INPUT ;
    USE SIGNAL ;
    PORT
      LAYER M4 ;
        RECT  0 59.568 0.084 59.592 ;
    END
  END i_row[106]
  PIN i_row[107]
    DIRECTION INPUT ;
    USE SIGNAL ;
    PORT
      LAYER M4 ;
        RECT  0 60 0.084 60.024 ;
    END
  END i_row[107]
  PIN i_row[108]
    DIRECTION INPUT ;
    USE SIGNAL ;
    PORT
      LAYER M4 ;
        RECT  0 60.432 0.084 60.456 ;
    END
  END i_row[108]
  PIN i_row[109]
    DIRECTION INPUT ;
    USE SIGNAL ;
    PORT
      LAYER M4 ;
        RECT  0 60.864 0.084 60.888 ;
    END
  END i_row[109]
  PIN i_row[10]
    DIRECTION INPUT ;
    USE SIGNAL ;
    PORT
      LAYER M4 ;
        RECT  0 18.096 0.084 18.12 ;
    END
  END i_row[10]
  PIN i_row[110]
    DIRECTION INPUT ;
    USE SIGNAL ;
    PORT
      LAYER M4 ;
        RECT  0 61.296 0.084 61.32 ;
    END
  END i_row[110]
  PIN i_row[111]
    DIRECTION INPUT ;
    USE SIGNAL ;
    PORT
      LAYER M4 ;
        RECT  0 61.728 0.084 61.752 ;
    END
  END i_row[111]
  PIN i_row[112]
    DIRECTION INPUT ;
    USE SIGNAL ;
    PORT
      LAYER M4 ;
        RECT  0 62.16 0.084 62.184 ;
    END
  END i_row[112]
  PIN i_row[113]
    DIRECTION INPUT ;
    USE SIGNAL ;
    PORT
      LAYER M4 ;
        RECT  0 62.592 0.084 62.616 ;
    END
  END i_row[113]
  PIN i_row[114]
    DIRECTION INPUT ;
    USE SIGNAL ;
    PORT
      LAYER M4 ;
        RECT  0 63.024 0.084 63.048 ;
    END
  END i_row[114]
  PIN i_row[115]
    DIRECTION INPUT ;
    USE SIGNAL ;
    PORT
      LAYER M4 ;
        RECT  0 63.456 0.084 63.48 ;
    END
  END i_row[115]
  PIN i_row[116]
    DIRECTION INPUT ;
    USE SIGNAL ;
    PORT
      LAYER M4 ;
        RECT  0 63.888 0.084 63.912 ;
    END
  END i_row[116]
  PIN i_row[117]
    DIRECTION INPUT ;
    USE SIGNAL ;
    PORT
      LAYER M4 ;
        RECT  0 64.32 0.084 64.344 ;
    END
  END i_row[117]
  PIN i_row[118]
    DIRECTION INPUT ;
    USE SIGNAL ;
    PORT
      LAYER M4 ;
        RECT  0 64.752 0.084 64.776 ;
    END
  END i_row[118]
  PIN i_row[119]
    DIRECTION INPUT ;
    USE SIGNAL ;
    PORT
      LAYER M4 ;
        RECT  0 65.184 0.084 65.208 ;
    END
  END i_row[119]
  PIN i_row[11]
    DIRECTION INPUT ;
    USE SIGNAL ;
    PORT
      LAYER M4 ;
        RECT  0 18.528 0.084 18.552 ;
    END
  END i_row[11]
  PIN i_row[120]
    DIRECTION INPUT ;
    USE SIGNAL ;
    PORT
      LAYER M4 ;
        RECT  0 65.616 0.084 65.64 ;
    END
  END i_row[120]
  PIN i_row[121]
    DIRECTION INPUT ;
    USE SIGNAL ;
    PORT
      LAYER M4 ;
        RECT  0 66.048 0.084 66.072 ;
    END
  END i_row[121]
  PIN i_row[122]
    DIRECTION INPUT ;
    USE SIGNAL ;
    PORT
      LAYER M4 ;
        RECT  0 66.48 0.084 66.504 ;
    END
  END i_row[122]
  PIN i_row[123]
    DIRECTION INPUT ;
    USE SIGNAL ;
    PORT
      LAYER M4 ;
        RECT  0 66.912 0.084 66.936 ;
    END
  END i_row[123]
  PIN i_row[124]
    DIRECTION INPUT ;
    USE SIGNAL ;
    PORT
      LAYER M4 ;
        RECT  0 67.344 0.084 67.368 ;
    END
  END i_row[124]
  PIN i_row[125]
    DIRECTION INPUT ;
    USE SIGNAL ;
    PORT
      LAYER M4 ;
        RECT  0 67.776 0.084 67.8 ;
    END
  END i_row[125]
  PIN i_row[126]
    DIRECTION INPUT ;
    USE SIGNAL ;
    PORT
      LAYER M4 ;
        RECT  0 68.208 0.084 68.232 ;
    END
  END i_row[126]
  PIN i_row[127]
    DIRECTION INPUT ;
    USE SIGNAL ;
    PORT
      LAYER M4 ;
        RECT  0 68.64 0.084 68.664 ;
    END
  END i_row[127]
  PIN i_row[128]
    DIRECTION INPUT ;
    USE SIGNAL ;
    PORT
      LAYER M4 ;
        RECT  0 69.072 0.084 69.096 ;
    END
  END i_row[128]
  PIN i_row[129]
    DIRECTION INPUT ;
    USE SIGNAL ;
    PORT
      LAYER M4 ;
        RECT  0 69.504 0.084 69.528 ;
    END
  END i_row[129]
  PIN i_row[12]
    DIRECTION INPUT ;
    USE SIGNAL ;
    PORT
      LAYER M4 ;
        RECT  0 18.96 0.084 18.984 ;
    END
  END i_row[12]
  PIN i_row[130]
    DIRECTION INPUT ;
    USE SIGNAL ;
    PORT
      LAYER M4 ;
        RECT  0 69.936 0.084 69.96 ;
    END
  END i_row[130]
  PIN i_row[131]
    DIRECTION INPUT ;
    USE SIGNAL ;
    PORT
      LAYER M4 ;
        RECT  0 70.368 0.084 70.392 ;
    END
  END i_row[131]
  PIN i_row[132]
    DIRECTION INPUT ;
    USE SIGNAL ;
    PORT
      LAYER M4 ;
        RECT  0 70.8 0.084 70.824 ;
    END
  END i_row[132]
  PIN i_row[133]
    DIRECTION INPUT ;
    USE SIGNAL ;
    PORT
      LAYER M4 ;
        RECT  0 71.232 0.084 71.256 ;
    END
  END i_row[133]
  PIN i_row[134]
    DIRECTION INPUT ;
    USE SIGNAL ;
    PORT
      LAYER M4 ;
        RECT  0 71.664 0.084 71.688 ;
    END
  END i_row[134]
  PIN i_row[135]
    DIRECTION INPUT ;
    USE SIGNAL ;
    PORT
      LAYER M4 ;
        RECT  0 72.096 0.084 72.12 ;
    END
  END i_row[135]
  PIN i_row[136]
    DIRECTION INPUT ;
    USE SIGNAL ;
    PORT
      LAYER M4 ;
        RECT  0 72.528 0.084 72.552 ;
    END
  END i_row[136]
  PIN i_row[137]
    DIRECTION INPUT ;
    USE SIGNAL ;
    PORT
      LAYER M4 ;
        RECT  0 72.96 0.084 72.984 ;
    END
  END i_row[137]
  PIN i_row[138]
    DIRECTION INPUT ;
    USE SIGNAL ;
    PORT
      LAYER M4 ;
        RECT  0 73.392 0.084 73.416 ;
    END
  END i_row[138]
  PIN i_row[139]
    DIRECTION INPUT ;
    USE SIGNAL ;
    PORT
      LAYER M4 ;
        RECT  0 73.824 0.084 73.848 ;
    END
  END i_row[139]
  PIN i_row[13]
    DIRECTION INPUT ;
    USE SIGNAL ;
    PORT
      LAYER M4 ;
        RECT  0 19.392 0.084 19.416 ;
    END
  END i_row[13]
  PIN i_row[140]
    DIRECTION INPUT ;
    USE SIGNAL ;
    PORT
      LAYER M4 ;
        RECT  0 74.256 0.084 74.28 ;
    END
  END i_row[140]
  PIN i_row[141]
    DIRECTION INPUT ;
    USE SIGNAL ;
    PORT
      LAYER M4 ;
        RECT  0 74.688 0.084 74.712 ;
    END
  END i_row[141]
  PIN i_row[142]
    DIRECTION INPUT ;
    USE SIGNAL ;
    PORT
      LAYER M4 ;
        RECT  0 75.12 0.084 75.144 ;
    END
  END i_row[142]
  PIN i_row[143]
    DIRECTION INPUT ;
    USE SIGNAL ;
    PORT
      LAYER M4 ;
        RECT  0 75.552 0.084 75.576 ;
    END
  END i_row[143]
  PIN i_row[144]
    DIRECTION INPUT ;
    USE SIGNAL ;
    PORT
      LAYER M4 ;
        RECT  0 75.984 0.084 76.008 ;
    END
  END i_row[144]
  PIN i_row[145]
    DIRECTION INPUT ;
    USE SIGNAL ;
    PORT
      LAYER M4 ;
        RECT  0 76.416 0.084 76.44 ;
    END
  END i_row[145]
  PIN i_row[146]
    DIRECTION INPUT ;
    USE SIGNAL ;
    PORT
      LAYER M4 ;
        RECT  0 76.848 0.084 76.872 ;
    END
  END i_row[146]
  PIN i_row[147]
    DIRECTION INPUT ;
    USE SIGNAL ;
    PORT
      LAYER M4 ;
        RECT  0 77.28 0.084 77.304 ;
    END
  END i_row[147]
  PIN i_row[148]
    DIRECTION INPUT ;
    USE SIGNAL ;
    PORT
      LAYER M4 ;
        RECT  0 77.712 0.084 77.736 ;
    END
  END i_row[148]
  PIN i_row[149]
    DIRECTION INPUT ;
    USE SIGNAL ;
    PORT
      LAYER M4 ;
        RECT  0 78.144 0.084 78.168 ;
    END
  END i_row[149]
  PIN i_row[14]
    DIRECTION INPUT ;
    USE SIGNAL ;
    PORT
      LAYER M4 ;
        RECT  0 19.824 0.084 19.848 ;
    END
  END i_row[14]
  PIN i_row[150]
    DIRECTION INPUT ;
    USE SIGNAL ;
    PORT
      LAYER M4 ;
        RECT  0 78.576 0.084 78.6 ;
    END
  END i_row[150]
  PIN i_row[151]
    DIRECTION INPUT ;
    USE SIGNAL ;
    PORT
      LAYER M4 ;
        RECT  0 79.008 0.084 79.032 ;
    END
  END i_row[151]
  PIN i_row[152]
    DIRECTION INPUT ;
    USE SIGNAL ;
    PORT
      LAYER M4 ;
        RECT  0 79.44 0.084 79.464 ;
    END
  END i_row[152]
  PIN i_row[153]
    DIRECTION INPUT ;
    USE SIGNAL ;
    PORT
      LAYER M4 ;
        RECT  0 79.872 0.084 79.896 ;
    END
  END i_row[153]
  PIN i_row[154]
    DIRECTION INPUT ;
    USE SIGNAL ;
    PORT
      LAYER M4 ;
        RECT  0 80.304 0.084 80.328 ;
    END
  END i_row[154]
  PIN i_row[155]
    DIRECTION INPUT ;
    USE SIGNAL ;
    PORT
      LAYER M4 ;
        RECT  0 80.736 0.084 80.76 ;
    END
  END i_row[155]
  PIN i_row[156]
    DIRECTION INPUT ;
    USE SIGNAL ;
    PORT
      LAYER M4 ;
        RECT  0 81.168 0.084 81.192 ;
    END
  END i_row[156]
  PIN i_row[157]
    DIRECTION INPUT ;
    USE SIGNAL ;
    PORT
      LAYER M4 ;
        RECT  0 81.6 0.084 81.624 ;
    END
  END i_row[157]
  PIN i_row[158]
    DIRECTION INPUT ;
    USE SIGNAL ;
    PORT
      LAYER M4 ;
        RECT  0 82.032 0.084 82.056 ;
    END
  END i_row[158]
  PIN i_row[159]
    DIRECTION INPUT ;
    USE SIGNAL ;
    PORT
      LAYER M4 ;
        RECT  0 82.464 0.084 82.488 ;
    END
  END i_row[159]
  PIN i_row[15]
    DIRECTION INPUT ;
    USE SIGNAL ;
    PORT
      LAYER M4 ;
        RECT  0 20.256 0.084 20.28 ;
    END
  END i_row[15]
  PIN i_row[160]
    DIRECTION INPUT ;
    USE SIGNAL ;
    PORT
      LAYER M4 ;
        RECT  0 82.896 0.084 82.92 ;
    END
  END i_row[160]
  PIN i_row[161]
    DIRECTION INPUT ;
    USE SIGNAL ;
    PORT
      LAYER M4 ;
        RECT  0 83.328 0.084 83.352 ;
    END
  END i_row[161]
  PIN i_row[162]
    DIRECTION INPUT ;
    USE SIGNAL ;
    PORT
      LAYER M4 ;
        RECT  0 83.76 0.084 83.784 ;
    END
  END i_row[162]
  PIN i_row[163]
    DIRECTION INPUT ;
    USE SIGNAL ;
    PORT
      LAYER M4 ;
        RECT  0 84.192 0.084 84.216 ;
    END
  END i_row[163]
  PIN i_row[164]
    DIRECTION INPUT ;
    USE SIGNAL ;
    PORT
      LAYER M4 ;
        RECT  0 84.624 0.084 84.648 ;
    END
  END i_row[164]
  PIN i_row[165]
    DIRECTION INPUT ;
    USE SIGNAL ;
    PORT
      LAYER M4 ;
        RECT  0 85.056 0.084 85.08 ;
    END
  END i_row[165]
  PIN i_row[166]
    DIRECTION INPUT ;
    USE SIGNAL ;
    PORT
      LAYER M4 ;
        RECT  0 85.488 0.084 85.512 ;
    END
  END i_row[166]
  PIN i_row[167]
    DIRECTION INPUT ;
    USE SIGNAL ;
    PORT
      LAYER M4 ;
        RECT  0 85.92 0.084 85.944 ;
    END
  END i_row[167]
  PIN i_row[168]
    DIRECTION INPUT ;
    USE SIGNAL ;
    PORT
      LAYER M4 ;
        RECT  0 86.352 0.084 86.376 ;
    END
  END i_row[168]
  PIN i_row[169]
    DIRECTION INPUT ;
    USE SIGNAL ;
    PORT
      LAYER M4 ;
        RECT  0 86.784 0.084 86.808 ;
    END
  END i_row[169]
  PIN i_row[16]
    DIRECTION INPUT ;
    USE SIGNAL ;
    PORT
      LAYER M4 ;
        RECT  0 20.688 0.084 20.712 ;
    END
  END i_row[16]
  PIN i_row[170]
    DIRECTION INPUT ;
    USE SIGNAL ;
    PORT
      LAYER M4 ;
        RECT  0 87.216 0.084 87.24 ;
    END
  END i_row[170]
  PIN i_row[171]
    DIRECTION INPUT ;
    USE SIGNAL ;
    PORT
      LAYER M4 ;
        RECT  0 87.648 0.084 87.672 ;
    END
  END i_row[171]
  PIN i_row[172]
    DIRECTION INPUT ;
    USE SIGNAL ;
    PORT
      LAYER M4 ;
        RECT  0 88.08 0.084 88.104 ;
    END
  END i_row[172]
  PIN i_row[173]
    DIRECTION INPUT ;
    USE SIGNAL ;
    PORT
      LAYER M4 ;
        RECT  0 88.512 0.084 88.536 ;
    END
  END i_row[173]
  PIN i_row[174]
    DIRECTION INPUT ;
    USE SIGNAL ;
    PORT
      LAYER M4 ;
        RECT  0 88.944 0.084 88.968 ;
    END
  END i_row[174]
  PIN i_row[175]
    DIRECTION INPUT ;
    USE SIGNAL ;
    PORT
      LAYER M4 ;
        RECT  0 89.376 0.084 89.4 ;
    END
  END i_row[175]
  PIN i_row[176]
    DIRECTION INPUT ;
    USE SIGNAL ;
    PORT
      LAYER M4 ;
        RECT  0 89.808 0.084 89.832 ;
    END
  END i_row[176]
  PIN i_row[177]
    DIRECTION INPUT ;
    USE SIGNAL ;
    PORT
      LAYER M4 ;
        RECT  0 90.24 0.084 90.264 ;
    END
  END i_row[177]
  PIN i_row[178]
    DIRECTION INPUT ;
    USE SIGNAL ;
    PORT
      LAYER M4 ;
        RECT  0 90.672 0.084 90.696 ;
    END
  END i_row[178]
  PIN i_row[179]
    DIRECTION INPUT ;
    USE SIGNAL ;
    PORT
      LAYER M4 ;
        RECT  0 91.104 0.084 91.128 ;
    END
  END i_row[179]
  PIN i_row[17]
    DIRECTION INPUT ;
    USE SIGNAL ;
    PORT
      LAYER M4 ;
        RECT  0 21.12 0.084 21.144 ;
    END
  END i_row[17]
  PIN i_row[180]
    DIRECTION INPUT ;
    USE SIGNAL ;
    PORT
      LAYER M4 ;
        RECT  0 91.536 0.084 91.56 ;
    END
  END i_row[180]
  PIN i_row[181]
    DIRECTION INPUT ;
    USE SIGNAL ;
    PORT
      LAYER M4 ;
        RECT  0 91.968 0.084 91.992 ;
    END
  END i_row[181]
  PIN i_row[182]
    DIRECTION INPUT ;
    USE SIGNAL ;
    PORT
      LAYER M4 ;
        RECT  0 92.4 0.084 92.424 ;
    END
  END i_row[182]
  PIN i_row[183]
    DIRECTION INPUT ;
    USE SIGNAL ;
    PORT
      LAYER M4 ;
        RECT  0 92.832 0.084 92.856 ;
    END
  END i_row[183]
  PIN i_row[184]
    DIRECTION INPUT ;
    USE SIGNAL ;
    PORT
      LAYER M4 ;
        RECT  0 93.264 0.084 93.288 ;
    END
  END i_row[184]
  PIN i_row[185]
    DIRECTION INPUT ;
    USE SIGNAL ;
    PORT
      LAYER M4 ;
        RECT  0 93.696 0.084 93.72 ;
    END
  END i_row[185]
  PIN i_row[186]
    DIRECTION INPUT ;
    USE SIGNAL ;
    PORT
      LAYER M4 ;
        RECT  0 94.128 0.084 94.152 ;
    END
  END i_row[186]
  PIN i_row[187]
    DIRECTION INPUT ;
    USE SIGNAL ;
    PORT
      LAYER M4 ;
        RECT  0 94.56 0.084 94.584 ;
    END
  END i_row[187]
  PIN i_row[188]
    DIRECTION INPUT ;
    USE SIGNAL ;
    PORT
      LAYER M4 ;
        RECT  0 94.992 0.084 95.016 ;
    END
  END i_row[188]
  PIN i_row[189]
    DIRECTION INPUT ;
    USE SIGNAL ;
    PORT
      LAYER M4 ;
        RECT  0 95.424 0.084 95.448 ;
    END
  END i_row[189]
  PIN i_row[18]
    DIRECTION INPUT ;
    USE SIGNAL ;
    PORT
      LAYER M4 ;
        RECT  0 21.552 0.084 21.576 ;
    END
  END i_row[18]
  PIN i_row[190]
    DIRECTION INPUT ;
    USE SIGNAL ;
    PORT
      LAYER M4 ;
        RECT  0 95.856 0.084 95.88 ;
    END
  END i_row[190]
  PIN i_row[191]
    DIRECTION INPUT ;
    USE SIGNAL ;
    PORT
      LAYER M4 ;
        RECT  0 96.288 0.084 96.312 ;
    END
  END i_row[191]
  PIN i_row[192]
    DIRECTION INPUT ;
    USE SIGNAL ;
    PORT
      LAYER M4 ;
        RECT  0 96.72 0.084 96.744 ;
    END
  END i_row[192]
  PIN i_row[193]
    DIRECTION INPUT ;
    USE SIGNAL ;
    PORT
      LAYER M4 ;
        RECT  0 97.152 0.084 97.176 ;
    END
  END i_row[193]
  PIN i_row[194]
    DIRECTION INPUT ;
    USE SIGNAL ;
    PORT
      LAYER M4 ;
        RECT  0 97.584 0.084 97.608 ;
    END
  END i_row[194]
  PIN i_row[195]
    DIRECTION INPUT ;
    USE SIGNAL ;
    PORT
      LAYER M4 ;
        RECT  0 98.016 0.084 98.04 ;
    END
  END i_row[195]
  PIN i_row[196]
    DIRECTION INPUT ;
    USE SIGNAL ;
    PORT
      LAYER M4 ;
        RECT  0 98.448 0.084 98.472 ;
    END
  END i_row[196]
  PIN i_row[197]
    DIRECTION INPUT ;
    USE SIGNAL ;
    PORT
      LAYER M4 ;
        RECT  0 98.88 0.084 98.904 ;
    END
  END i_row[197]
  PIN i_row[198]
    DIRECTION INPUT ;
    USE SIGNAL ;
    PORT
      LAYER M4 ;
        RECT  0 99.312 0.084 99.336 ;
    END
  END i_row[198]
  PIN i_row[199]
    DIRECTION INPUT ;
    USE SIGNAL ;
    PORT
      LAYER M4 ;
        RECT  0 99.744 0.084 99.768 ;
    END
  END i_row[199]
  PIN i_row[19]
    DIRECTION INPUT ;
    USE SIGNAL ;
    PORT
      LAYER M4 ;
        RECT  0 21.984 0.084 22.008 ;
    END
  END i_row[19]
  PIN i_row[1]
    DIRECTION INPUT ;
    USE SIGNAL ;
    PORT
      LAYER M4 ;
        RECT  0 14.208 0.084 14.232 ;
    END
  END i_row[1]
  PIN i_row[200]
    DIRECTION INPUT ;
    USE SIGNAL ;
    PORT
      LAYER M4 ;
        RECT  0 100.176 0.084 100.2 ;
    END
  END i_row[200]
  PIN i_row[201]
    DIRECTION INPUT ;
    USE SIGNAL ;
    PORT
      LAYER M4 ;
        RECT  0 100.608 0.084 100.632 ;
    END
  END i_row[201]
  PIN i_row[202]
    DIRECTION INPUT ;
    USE SIGNAL ;
    PORT
      LAYER M4 ;
        RECT  0 101.04 0.084 101.064 ;
    END
  END i_row[202]
  PIN i_row[203]
    DIRECTION INPUT ;
    USE SIGNAL ;
    PORT
      LAYER M4 ;
        RECT  0 101.472 0.084 101.496 ;
    END
  END i_row[203]
  PIN i_row[204]
    DIRECTION INPUT ;
    USE SIGNAL ;
    PORT
      LAYER M4 ;
        RECT  0 101.904 0.084 101.928 ;
    END
  END i_row[204]
  PIN i_row[205]
    DIRECTION INPUT ;
    USE SIGNAL ;
    PORT
      LAYER M4 ;
        RECT  0 102.336 0.084 102.36 ;
    END
  END i_row[205]
  PIN i_row[206]
    DIRECTION INPUT ;
    USE SIGNAL ;
    PORT
      LAYER M4 ;
        RECT  0 102.768 0.084 102.792 ;
    END
  END i_row[206]
  PIN i_row[207]
    DIRECTION INPUT ;
    USE SIGNAL ;
    PORT
      LAYER M4 ;
        RECT  0 103.2 0.084 103.224 ;
    END
  END i_row[207]
  PIN i_row[208]
    DIRECTION INPUT ;
    USE SIGNAL ;
    PORT
      LAYER M4 ;
        RECT  0 103.632 0.084 103.656 ;
    END
  END i_row[208]
  PIN i_row[209]
    DIRECTION INPUT ;
    USE SIGNAL ;
    PORT
      LAYER M4 ;
        RECT  0 104.064 0.084 104.088 ;
    END
  END i_row[209]
  PIN i_row[20]
    DIRECTION INPUT ;
    USE SIGNAL ;
    PORT
      LAYER M4 ;
        RECT  0 22.416 0.084 22.44 ;
    END
  END i_row[20]
  PIN i_row[210]
    DIRECTION INPUT ;
    USE SIGNAL ;
    PORT
      LAYER M4 ;
        RECT  0 104.496 0.084 104.52 ;
    END
  END i_row[210]
  PIN i_row[211]
    DIRECTION INPUT ;
    USE SIGNAL ;
    PORT
      LAYER M4 ;
        RECT  0 104.928 0.084 104.952 ;
    END
  END i_row[211]
  PIN i_row[212]
    DIRECTION INPUT ;
    USE SIGNAL ;
    PORT
      LAYER M4 ;
        RECT  0 105.36 0.084 105.384 ;
    END
  END i_row[212]
  PIN i_row[213]
    DIRECTION INPUT ;
    USE SIGNAL ;
    PORT
      LAYER M4 ;
        RECT  0 105.792 0.084 105.816 ;
    END
  END i_row[213]
  PIN i_row[214]
    DIRECTION INPUT ;
    USE SIGNAL ;
    PORT
      LAYER M4 ;
        RECT  0 106.224 0.084 106.248 ;
    END
  END i_row[214]
  PIN i_row[215]
    DIRECTION INPUT ;
    USE SIGNAL ;
    PORT
      LAYER M4 ;
        RECT  0 106.656 0.084 106.68 ;
    END
  END i_row[215]
  PIN i_row[216]
    DIRECTION INPUT ;
    USE SIGNAL ;
    PORT
      LAYER M4 ;
        RECT  0 107.088 0.084 107.112 ;
    END
  END i_row[216]
  PIN i_row[217]
    DIRECTION INPUT ;
    USE SIGNAL ;
    PORT
      LAYER M4 ;
        RECT  0 107.52 0.084 107.544 ;
    END
  END i_row[217]
  PIN i_row[218]
    DIRECTION INPUT ;
    USE SIGNAL ;
    PORT
      LAYER M4 ;
        RECT  0 107.952 0.084 107.976 ;
    END
  END i_row[218]
  PIN i_row[219]
    DIRECTION INPUT ;
    USE SIGNAL ;
    PORT
      LAYER M4 ;
        RECT  0 108.384 0.084 108.408 ;
    END
  END i_row[219]
  PIN i_row[21]
    DIRECTION INPUT ;
    USE SIGNAL ;
    PORT
      LAYER M4 ;
        RECT  0 22.848 0.084 22.872 ;
    END
  END i_row[21]
  PIN i_row[220]
    DIRECTION INPUT ;
    USE SIGNAL ;
    PORT
      LAYER M4 ;
        RECT  0 108.816 0.084 108.84 ;
    END
  END i_row[220]
  PIN i_row[221]
    DIRECTION INPUT ;
    USE SIGNAL ;
    PORT
      LAYER M4 ;
        RECT  0 109.248 0.084 109.272 ;
    END
  END i_row[221]
  PIN i_row[222]
    DIRECTION INPUT ;
    USE SIGNAL ;
    PORT
      LAYER M4 ;
        RECT  0 109.68 0.084 109.704 ;
    END
  END i_row[222]
  PIN i_row[223]
    DIRECTION INPUT ;
    USE SIGNAL ;
    PORT
      LAYER M4 ;
        RECT  0 110.112 0.084 110.136 ;
    END
  END i_row[223]
  PIN i_row[224]
    DIRECTION INPUT ;
    USE SIGNAL ;
    PORT
      LAYER M4 ;
        RECT  0 110.544 0.084 110.568 ;
    END
  END i_row[224]
  PIN i_row[225]
    DIRECTION INPUT ;
    USE SIGNAL ;
    PORT
      LAYER M4 ;
        RECT  0 110.976 0.084 111 ;
    END
  END i_row[225]
  PIN i_row[226]
    DIRECTION INPUT ;
    USE SIGNAL ;
    PORT
      LAYER M4 ;
        RECT  0 111.408 0.084 111.432 ;
    END
  END i_row[226]
  PIN i_row[227]
    DIRECTION INPUT ;
    USE SIGNAL ;
    PORT
      LAYER M4 ;
        RECT  0 111.84 0.084 111.864 ;
    END
  END i_row[227]
  PIN i_row[228]
    DIRECTION INPUT ;
    USE SIGNAL ;
    PORT
      LAYER M4 ;
        RECT  0 112.272 0.084 112.296 ;
    END
  END i_row[228]
  PIN i_row[229]
    DIRECTION INPUT ;
    USE SIGNAL ;
    PORT
      LAYER M4 ;
        RECT  0 112.704 0.084 112.728 ;
    END
  END i_row[229]
  PIN i_row[22]
    DIRECTION INPUT ;
    USE SIGNAL ;
    PORT
      LAYER M4 ;
        RECT  0 23.28 0.084 23.304 ;
    END
  END i_row[22]
  PIN i_row[230]
    DIRECTION INPUT ;
    USE SIGNAL ;
    PORT
      LAYER M4 ;
        RECT  0 113.136 0.084 113.16 ;
    END
  END i_row[230]
  PIN i_row[231]
    DIRECTION INPUT ;
    USE SIGNAL ;
    PORT
      LAYER M4 ;
        RECT  0 113.568 0.084 113.592 ;
    END
  END i_row[231]
  PIN i_row[232]
    DIRECTION INPUT ;
    USE SIGNAL ;
    PORT
      LAYER M4 ;
        RECT  0 114 0.084 114.024 ;
    END
  END i_row[232]
  PIN i_row[233]
    DIRECTION INPUT ;
    USE SIGNAL ;
    PORT
      LAYER M4 ;
        RECT  0 114.432 0.084 114.456 ;
    END
  END i_row[233]
  PIN i_row[234]
    DIRECTION INPUT ;
    USE SIGNAL ;
    PORT
      LAYER M4 ;
        RECT  0 114.864 0.084 114.888 ;
    END
  END i_row[234]
  PIN i_row[235]
    DIRECTION INPUT ;
    USE SIGNAL ;
    PORT
      LAYER M4 ;
        RECT  0 115.296 0.084 115.32 ;
    END
  END i_row[235]
  PIN i_row[236]
    DIRECTION INPUT ;
    USE SIGNAL ;
    PORT
      LAYER M4 ;
        RECT  0 115.728 0.084 115.752 ;
    END
  END i_row[236]
  PIN i_row[237]
    DIRECTION INPUT ;
    USE SIGNAL ;
    PORT
      LAYER M4 ;
        RECT  0 116.16 0.084 116.184 ;
    END
  END i_row[237]
  PIN i_row[238]
    DIRECTION INPUT ;
    USE SIGNAL ;
    PORT
      LAYER M4 ;
        RECT  0 116.592 0.084 116.616 ;
    END
  END i_row[238]
  PIN i_row[239]
    DIRECTION INPUT ;
    USE SIGNAL ;
    PORT
      LAYER M4 ;
        RECT  0 117.024 0.084 117.048 ;
    END
  END i_row[239]
  PIN i_row[23]
    DIRECTION INPUT ;
    USE SIGNAL ;
    PORT
      LAYER M4 ;
        RECT  0 23.712 0.084 23.736 ;
    END
  END i_row[23]
  PIN i_row[240]
    DIRECTION INPUT ;
    USE SIGNAL ;
    PORT
      LAYER M4 ;
        RECT  0 117.456 0.084 117.48 ;
    END
  END i_row[240]
  PIN i_row[241]
    DIRECTION INPUT ;
    USE SIGNAL ;
    PORT
      LAYER M4 ;
        RECT  0 117.888 0.084 117.912 ;
    END
  END i_row[241]
  PIN i_row[242]
    DIRECTION INPUT ;
    USE SIGNAL ;
    PORT
      LAYER M4 ;
        RECT  0 118.32 0.084 118.344 ;
    END
  END i_row[242]
  PIN i_row[243]
    DIRECTION INPUT ;
    USE SIGNAL ;
    PORT
      LAYER M4 ;
        RECT  0 118.752 0.084 118.776 ;
    END
  END i_row[243]
  PIN i_row[244]
    DIRECTION INPUT ;
    USE SIGNAL ;
    PORT
      LAYER M4 ;
        RECT  0 119.184 0.084 119.208 ;
    END
  END i_row[244]
  PIN i_row[245]
    DIRECTION INPUT ;
    USE SIGNAL ;
    PORT
      LAYER M4 ;
        RECT  0 119.616 0.084 119.64 ;
    END
  END i_row[245]
  PIN i_row[246]
    DIRECTION INPUT ;
    USE SIGNAL ;
    PORT
      LAYER M4 ;
        RECT  0 120.048 0.084 120.072 ;
    END
  END i_row[246]
  PIN i_row[247]
    DIRECTION INPUT ;
    USE SIGNAL ;
    PORT
      LAYER M4 ;
        RECT  0 120.48 0.084 120.504 ;
    END
  END i_row[247]
  PIN i_row[248]
    DIRECTION INPUT ;
    USE SIGNAL ;
    PORT
      LAYER M4 ;
        RECT  0 120.912 0.084 120.936 ;
    END
  END i_row[248]
  PIN i_row[249]
    DIRECTION INPUT ;
    USE SIGNAL ;
    PORT
      LAYER M4 ;
        RECT  0 121.344 0.084 121.368 ;
    END
  END i_row[249]
  PIN i_row[24]
    DIRECTION INPUT ;
    USE SIGNAL ;
    PORT
      LAYER M4 ;
        RECT  0 24.144 0.084 24.168 ;
    END
  END i_row[24]
  PIN i_row[250]
    DIRECTION INPUT ;
    USE SIGNAL ;
    PORT
      LAYER M4 ;
        RECT  0 121.776 0.084 121.8 ;
    END
  END i_row[250]
  PIN i_row[251]
    DIRECTION INPUT ;
    USE SIGNAL ;
    PORT
      LAYER M4 ;
        RECT  0 122.208 0.084 122.232 ;
    END
  END i_row[251]
  PIN i_row[25]
    DIRECTION INPUT ;
    USE SIGNAL ;
    PORT
      LAYER M4 ;
        RECT  0 24.576 0.084 24.6 ;
    END
  END i_row[25]
  PIN i_row[26]
    DIRECTION INPUT ;
    USE SIGNAL ;
    PORT
      LAYER M4 ;
        RECT  0 25.008 0.084 25.032 ;
    END
  END i_row[26]
  PIN i_row[27]
    DIRECTION INPUT ;
    USE SIGNAL ;
    PORT
      LAYER M4 ;
        RECT  0 25.44 0.084 25.464 ;
    END
  END i_row[27]
  PIN i_row[28]
    DIRECTION INPUT ;
    USE SIGNAL ;
    PORT
      LAYER M4 ;
        RECT  0 25.872 0.084 25.896 ;
    END
  END i_row[28]
  PIN i_row[29]
    DIRECTION INPUT ;
    USE SIGNAL ;
    PORT
      LAYER M4 ;
        RECT  0 26.304 0.084 26.328 ;
    END
  END i_row[29]
  PIN i_row[2]
    DIRECTION INPUT ;
    USE SIGNAL ;
    PORT
      LAYER M4 ;
        RECT  0 14.64 0.084 14.664 ;
    END
  END i_row[2]
  PIN i_row[30]
    DIRECTION INPUT ;
    USE SIGNAL ;
    PORT
      LAYER M4 ;
        RECT  0 26.736 0.084 26.76 ;
    END
  END i_row[30]
  PIN i_row[31]
    DIRECTION INPUT ;
    USE SIGNAL ;
    PORT
      LAYER M4 ;
        RECT  0 27.168 0.084 27.192 ;
    END
  END i_row[31]
  PIN i_row[32]
    DIRECTION INPUT ;
    USE SIGNAL ;
    PORT
      LAYER M4 ;
        RECT  0 27.6 0.084 27.624 ;
    END
  END i_row[32]
  PIN i_row[33]
    DIRECTION INPUT ;
    USE SIGNAL ;
    PORT
      LAYER M4 ;
        RECT  0 28.032 0.084 28.056 ;
    END
  END i_row[33]
  PIN i_row[34]
    DIRECTION INPUT ;
    USE SIGNAL ;
    PORT
      LAYER M4 ;
        RECT  0 28.464 0.084 28.488 ;
    END
  END i_row[34]
  PIN i_row[35]
    DIRECTION INPUT ;
    USE SIGNAL ;
    PORT
      LAYER M4 ;
        RECT  0 28.896 0.084 28.92 ;
    END
  END i_row[35]
  PIN i_row[36]
    DIRECTION INPUT ;
    USE SIGNAL ;
    PORT
      LAYER M4 ;
        RECT  0 29.328 0.084 29.352 ;
    END
  END i_row[36]
  PIN i_row[37]
    DIRECTION INPUT ;
    USE SIGNAL ;
    PORT
      LAYER M4 ;
        RECT  0 29.76 0.084 29.784 ;
    END
  END i_row[37]
  PIN i_row[38]
    DIRECTION INPUT ;
    USE SIGNAL ;
    PORT
      LAYER M4 ;
        RECT  0 30.192 0.084 30.216 ;
    END
  END i_row[38]
  PIN i_row[39]
    DIRECTION INPUT ;
    USE SIGNAL ;
    PORT
      LAYER M4 ;
        RECT  0 30.624 0.084 30.648 ;
    END
  END i_row[39]
  PIN i_row[3]
    DIRECTION INPUT ;
    USE SIGNAL ;
    PORT
      LAYER M4 ;
        RECT  0 15.072 0.084 15.096 ;
    END
  END i_row[3]
  PIN i_row[40]
    DIRECTION INPUT ;
    USE SIGNAL ;
    PORT
      LAYER M4 ;
        RECT  0 31.056 0.084 31.08 ;
    END
  END i_row[40]
  PIN i_row[41]
    DIRECTION INPUT ;
    USE SIGNAL ;
    PORT
      LAYER M4 ;
        RECT  0 31.488 0.084 31.512 ;
    END
  END i_row[41]
  PIN i_row[42]
    DIRECTION INPUT ;
    USE SIGNAL ;
    PORT
      LAYER M4 ;
        RECT  0 31.92 0.084 31.944 ;
    END
  END i_row[42]
  PIN i_row[43]
    DIRECTION INPUT ;
    USE SIGNAL ;
    PORT
      LAYER M4 ;
        RECT  0 32.352 0.084 32.376 ;
    END
  END i_row[43]
  PIN i_row[44]
    DIRECTION INPUT ;
    USE SIGNAL ;
    PORT
      LAYER M4 ;
        RECT  0 32.784 0.084 32.808 ;
    END
  END i_row[44]
  PIN i_row[45]
    DIRECTION INPUT ;
    USE SIGNAL ;
    PORT
      LAYER M4 ;
        RECT  0 33.216 0.084 33.24 ;
    END
  END i_row[45]
  PIN i_row[46]
    DIRECTION INPUT ;
    USE SIGNAL ;
    PORT
      LAYER M4 ;
        RECT  0 33.648 0.084 33.672 ;
    END
  END i_row[46]
  PIN i_row[47]
    DIRECTION INPUT ;
    USE SIGNAL ;
    PORT
      LAYER M4 ;
        RECT  0 34.08 0.084 34.104 ;
    END
  END i_row[47]
  PIN i_row[48]
    DIRECTION INPUT ;
    USE SIGNAL ;
    PORT
      LAYER M4 ;
        RECT  0 34.512 0.084 34.536 ;
    END
  END i_row[48]
  PIN i_row[49]
    DIRECTION INPUT ;
    USE SIGNAL ;
    PORT
      LAYER M4 ;
        RECT  0 34.944 0.084 34.968 ;
    END
  END i_row[49]
  PIN i_row[4]
    DIRECTION INPUT ;
    USE SIGNAL ;
    PORT
      LAYER M4 ;
        RECT  0 15.504 0.084 15.528 ;
    END
  END i_row[4]
  PIN i_row[50]
    DIRECTION INPUT ;
    USE SIGNAL ;
    PORT
      LAYER M4 ;
        RECT  0 35.376 0.084 35.4 ;
    END
  END i_row[50]
  PIN i_row[51]
    DIRECTION INPUT ;
    USE SIGNAL ;
    PORT
      LAYER M4 ;
        RECT  0 35.808 0.084 35.832 ;
    END
  END i_row[51]
  PIN i_row[52]
    DIRECTION INPUT ;
    USE SIGNAL ;
    PORT
      LAYER M4 ;
        RECT  0 36.24 0.084 36.264 ;
    END
  END i_row[52]
  PIN i_row[53]
    DIRECTION INPUT ;
    USE SIGNAL ;
    PORT
      LAYER M4 ;
        RECT  0 36.672 0.084 36.696 ;
    END
  END i_row[53]
  PIN i_row[54]
    DIRECTION INPUT ;
    USE SIGNAL ;
    PORT
      LAYER M4 ;
        RECT  0 37.104 0.084 37.128 ;
    END
  END i_row[54]
  PIN i_row[55]
    DIRECTION INPUT ;
    USE SIGNAL ;
    PORT
      LAYER M4 ;
        RECT  0 37.536 0.084 37.56 ;
    END
  END i_row[55]
  PIN i_row[56]
    DIRECTION INPUT ;
    USE SIGNAL ;
    PORT
      LAYER M4 ;
        RECT  0 37.968 0.084 37.992 ;
    END
  END i_row[56]
  PIN i_row[57]
    DIRECTION INPUT ;
    USE SIGNAL ;
    PORT
      LAYER M4 ;
        RECT  0 38.4 0.084 38.424 ;
    END
  END i_row[57]
  PIN i_row[58]
    DIRECTION INPUT ;
    USE SIGNAL ;
    PORT
      LAYER M4 ;
        RECT  0 38.832 0.084 38.856 ;
    END
  END i_row[58]
  PIN i_row[59]
    DIRECTION INPUT ;
    USE SIGNAL ;
    PORT
      LAYER M4 ;
        RECT  0 39.264 0.084 39.288 ;
    END
  END i_row[59]
  PIN i_row[5]
    DIRECTION INPUT ;
    USE SIGNAL ;
    PORT
      LAYER M4 ;
        RECT  0 15.936 0.084 15.96 ;
    END
  END i_row[5]
  PIN i_row[60]
    DIRECTION INPUT ;
    USE SIGNAL ;
    PORT
      LAYER M4 ;
        RECT  0 39.696 0.084 39.72 ;
    END
  END i_row[60]
  PIN i_row[61]
    DIRECTION INPUT ;
    USE SIGNAL ;
    PORT
      LAYER M4 ;
        RECT  0 40.128 0.084 40.152 ;
    END
  END i_row[61]
  PIN i_row[62]
    DIRECTION INPUT ;
    USE SIGNAL ;
    PORT
      LAYER M4 ;
        RECT  0 40.56 0.084 40.584 ;
    END
  END i_row[62]
  PIN i_row[63]
    DIRECTION INPUT ;
    USE SIGNAL ;
    PORT
      LAYER M4 ;
        RECT  0 40.992 0.084 41.016 ;
    END
  END i_row[63]
  PIN i_row[64]
    DIRECTION INPUT ;
    USE SIGNAL ;
    PORT
      LAYER M4 ;
        RECT  0 41.424 0.084 41.448 ;
    END
  END i_row[64]
  PIN i_row[65]
    DIRECTION INPUT ;
    USE SIGNAL ;
    PORT
      LAYER M4 ;
        RECT  0 41.856 0.084 41.88 ;
    END
  END i_row[65]
  PIN i_row[66]
    DIRECTION INPUT ;
    USE SIGNAL ;
    PORT
      LAYER M4 ;
        RECT  0 42.288 0.084 42.312 ;
    END
  END i_row[66]
  PIN i_row[67]
    DIRECTION INPUT ;
    USE SIGNAL ;
    PORT
      LAYER M4 ;
        RECT  0 42.72 0.084 42.744 ;
    END
  END i_row[67]
  PIN i_row[68]
    DIRECTION INPUT ;
    USE SIGNAL ;
    PORT
      LAYER M4 ;
        RECT  0 43.152 0.084 43.176 ;
    END
  END i_row[68]
  PIN i_row[69]
    DIRECTION INPUT ;
    USE SIGNAL ;
    PORT
      LAYER M4 ;
        RECT  0 43.584 0.084 43.608 ;
    END
  END i_row[69]
  PIN i_row[6]
    DIRECTION INPUT ;
    USE SIGNAL ;
    PORT
      LAYER M4 ;
        RECT  0 16.368 0.084 16.392 ;
    END
  END i_row[6]
  PIN i_row[70]
    DIRECTION INPUT ;
    USE SIGNAL ;
    PORT
      LAYER M4 ;
        RECT  0 44.016 0.084 44.04 ;
    END
  END i_row[70]
  PIN i_row[71]
    DIRECTION INPUT ;
    USE SIGNAL ;
    PORT
      LAYER M4 ;
        RECT  0 44.448 0.084 44.472 ;
    END
  END i_row[71]
  PIN i_row[72]
    DIRECTION INPUT ;
    USE SIGNAL ;
    PORT
      LAYER M4 ;
        RECT  0 44.88 0.084 44.904 ;
    END
  END i_row[72]
  PIN i_row[73]
    DIRECTION INPUT ;
    USE SIGNAL ;
    PORT
      LAYER M4 ;
        RECT  0 45.312 0.084 45.336 ;
    END
  END i_row[73]
  PIN i_row[74]
    DIRECTION INPUT ;
    USE SIGNAL ;
    PORT
      LAYER M4 ;
        RECT  0 45.744 0.084 45.768 ;
    END
  END i_row[74]
  PIN i_row[75]
    DIRECTION INPUT ;
    USE SIGNAL ;
    PORT
      LAYER M4 ;
        RECT  0 46.176 0.084 46.2 ;
    END
  END i_row[75]
  PIN i_row[76]
    DIRECTION INPUT ;
    USE SIGNAL ;
    PORT
      LAYER M4 ;
        RECT  0 46.608 0.084 46.632 ;
    END
  END i_row[76]
  PIN i_row[77]
    DIRECTION INPUT ;
    USE SIGNAL ;
    PORT
      LAYER M4 ;
        RECT  0 47.04 0.084 47.064 ;
    END
  END i_row[77]
  PIN i_row[78]
    DIRECTION INPUT ;
    USE SIGNAL ;
    PORT
      LAYER M4 ;
        RECT  0 47.472 0.084 47.496 ;
    END
  END i_row[78]
  PIN i_row[79]
    DIRECTION INPUT ;
    USE SIGNAL ;
    PORT
      LAYER M4 ;
        RECT  0 47.904 0.084 47.928 ;
    END
  END i_row[79]
  PIN i_row[7]
    DIRECTION INPUT ;
    USE SIGNAL ;
    PORT
      LAYER M4 ;
        RECT  0 16.8 0.084 16.824 ;
    END
  END i_row[7]
  PIN i_row[80]
    DIRECTION INPUT ;
    USE SIGNAL ;
    PORT
      LAYER M4 ;
        RECT  0 48.336 0.084 48.36 ;
    END
  END i_row[80]
  PIN i_row[81]
    DIRECTION INPUT ;
    USE SIGNAL ;
    PORT
      LAYER M4 ;
        RECT  0 48.768 0.084 48.792 ;
    END
  END i_row[81]
  PIN i_row[82]
    DIRECTION INPUT ;
    USE SIGNAL ;
    PORT
      LAYER M4 ;
        RECT  0 49.2 0.084 49.224 ;
    END
  END i_row[82]
  PIN i_row[83]
    DIRECTION INPUT ;
    USE SIGNAL ;
    PORT
      LAYER M4 ;
        RECT  0 49.632 0.084 49.656 ;
    END
  END i_row[83]
  PIN i_row[84]
    DIRECTION INPUT ;
    USE SIGNAL ;
    PORT
      LAYER M4 ;
        RECT  0 50.064 0.084 50.088 ;
    END
  END i_row[84]
  PIN i_row[85]
    DIRECTION INPUT ;
    USE SIGNAL ;
    PORT
      LAYER M4 ;
        RECT  0 50.496 0.084 50.52 ;
    END
  END i_row[85]
  PIN i_row[86]
    DIRECTION INPUT ;
    USE SIGNAL ;
    PORT
      LAYER M4 ;
        RECT  0 50.928 0.084 50.952 ;
    END
  END i_row[86]
  PIN i_row[87]
    DIRECTION INPUT ;
    USE SIGNAL ;
    PORT
      LAYER M4 ;
        RECT  0 51.36 0.084 51.384 ;
    END
  END i_row[87]
  PIN i_row[88]
    DIRECTION INPUT ;
    USE SIGNAL ;
    PORT
      LAYER M4 ;
        RECT  0 51.792 0.084 51.816 ;
    END
  END i_row[88]
  PIN i_row[89]
    DIRECTION INPUT ;
    USE SIGNAL ;
    PORT
      LAYER M4 ;
        RECT  0 52.224 0.084 52.248 ;
    END
  END i_row[89]
  PIN i_row[8]
    DIRECTION INPUT ;
    USE SIGNAL ;
    PORT
      LAYER M4 ;
        RECT  0 17.232 0.084 17.256 ;
    END
  END i_row[8]
  PIN i_row[90]
    DIRECTION INPUT ;
    USE SIGNAL ;
    PORT
      LAYER M4 ;
        RECT  0 52.656 0.084 52.68 ;
    END
  END i_row[90]
  PIN i_row[91]
    DIRECTION INPUT ;
    USE SIGNAL ;
    PORT
      LAYER M4 ;
        RECT  0 53.088 0.084 53.112 ;
    END
  END i_row[91]
  PIN i_row[92]
    DIRECTION INPUT ;
    USE SIGNAL ;
    PORT
      LAYER M4 ;
        RECT  0 53.52 0.084 53.544 ;
    END
  END i_row[92]
  PIN i_row[93]
    DIRECTION INPUT ;
    USE SIGNAL ;
    PORT
      LAYER M4 ;
        RECT  0 53.952 0.084 53.976 ;
    END
  END i_row[93]
  PIN i_row[94]
    DIRECTION INPUT ;
    USE SIGNAL ;
    PORT
      LAYER M4 ;
        RECT  0 54.384 0.084 54.408 ;
    END
  END i_row[94]
  PIN i_row[95]
    DIRECTION INPUT ;
    USE SIGNAL ;
    PORT
      LAYER M4 ;
        RECT  0 54.816 0.084 54.84 ;
    END
  END i_row[95]
  PIN i_row[96]
    DIRECTION INPUT ;
    USE SIGNAL ;
    PORT
      LAYER M4 ;
        RECT  0 55.248 0.084 55.272 ;
    END
  END i_row[96]
  PIN i_row[97]
    DIRECTION INPUT ;
    USE SIGNAL ;
    PORT
      LAYER M4 ;
        RECT  0 55.68 0.084 55.704 ;
    END
  END i_row[97]
  PIN i_row[98]
    DIRECTION INPUT ;
    USE SIGNAL ;
    PORT
      LAYER M4 ;
        RECT  0 56.112 0.084 56.136 ;
    END
  END i_row[98]
  PIN i_row[99]
    DIRECTION INPUT ;
    USE SIGNAL ;
    PORT
      LAYER M4 ;
        RECT  0 56.544 0.084 56.568 ;
    END
  END i_row[99]
  PIN i_row[9]
    DIRECTION INPUT ;
    USE SIGNAL ;
    PORT
      LAYER M4 ;
        RECT  0 17.664 0.084 17.688 ;
    END
  END i_row[9]
  PIN i_slot[0]
    DIRECTION INPUT ;
    USE SIGNAL ;
    PORT
      LAYER M4 ;
        RECT  0 122.64 0.084 122.664 ;
    END
  END i_slot[0]
  PIN i_slot[10]
    DIRECTION INPUT ;
    USE SIGNAL ;
    PORT
      LAYER M4 ;
        RECT  0 126.96 0.084 126.984 ;
    END
  END i_slot[10]
  PIN i_slot[11]
    DIRECTION INPUT ;
    USE SIGNAL ;
    PORT
      LAYER M4 ;
        RECT  0 127.392 0.084 127.416 ;
    END
  END i_slot[11]
  PIN i_slot[12]
    DIRECTION INPUT ;
    USE SIGNAL ;
    PORT
      LAYER M4 ;
        RECT  0 127.824 0.084 127.848 ;
    END
  END i_slot[12]
  PIN i_slot[13]
    DIRECTION INPUT ;
    USE SIGNAL ;
    PORT
      LAYER M4 ;
        RECT  0 128.256 0.084 128.28 ;
    END
  END i_slot[13]
  PIN i_slot[14]
    DIRECTION INPUT ;
    USE SIGNAL ;
    PORT
      LAYER M4 ;
        RECT  0 128.688 0.084 128.712 ;
    END
  END i_slot[14]
  PIN i_slot[15]
    DIRECTION INPUT ;
    USE SIGNAL ;
    PORT
      LAYER M4 ;
        RECT  0 129.12 0.084 129.144 ;
    END
  END i_slot[15]
  PIN i_slot[16]
    DIRECTION INPUT ;
    USE SIGNAL ;
    PORT
      LAYER M4 ;
        RECT  0 129.552 0.084 129.576 ;
    END
  END i_slot[16]
  PIN i_slot[17]
    DIRECTION INPUT ;
    USE SIGNAL ;
    PORT
      LAYER M4 ;
        RECT  0 129.984 0.084 130.008 ;
    END
  END i_slot[17]
  PIN i_slot[18]
    DIRECTION INPUT ;
    USE SIGNAL ;
    PORT
      LAYER M4 ;
        RECT  0 130.416 0.084 130.44 ;
    END
  END i_slot[18]
  PIN i_slot[19]
    DIRECTION INPUT ;
    USE SIGNAL ;
    PORT
      LAYER M4 ;
        RECT  0 130.848 0.084 130.872 ;
    END
  END i_slot[19]
  PIN i_slot[1]
    DIRECTION INPUT ;
    USE SIGNAL ;
    PORT
      LAYER M4 ;
        RECT  0 123.072 0.084 123.096 ;
    END
  END i_slot[1]
  PIN i_slot[20]
    DIRECTION INPUT ;
    USE SIGNAL ;
    PORT
      LAYER M4 ;
        RECT  0 131.28 0.084 131.304 ;
    END
  END i_slot[20]
  PIN i_slot[21]
    DIRECTION INPUT ;
    USE SIGNAL ;
    PORT
      LAYER M4 ;
        RECT  0 131.712 0.084 131.736 ;
    END
  END i_slot[21]
  PIN i_slot[22]
    DIRECTION INPUT ;
    USE SIGNAL ;
    PORT
      LAYER M4 ;
        RECT  0 132.144 0.084 132.168 ;
    END
  END i_slot[22]
  PIN i_slot[23]
    DIRECTION INPUT ;
    USE SIGNAL ;
    PORT
      LAYER M4 ;
        RECT  0 132.576 0.084 132.6 ;
    END
  END i_slot[23]
  PIN i_slot[24]
    DIRECTION INPUT ;
    USE SIGNAL ;
    PORT
      LAYER M4 ;
        RECT  0 133.008 0.084 133.032 ;
    END
  END i_slot[24]
  PIN i_slot[25]
    DIRECTION INPUT ;
    USE SIGNAL ;
    PORT
      LAYER M4 ;
        RECT  0 133.44 0.084 133.464 ;
    END
  END i_slot[25]
  PIN i_slot[26]
    DIRECTION INPUT ;
    USE SIGNAL ;
    PORT
      LAYER M4 ;
        RECT  0 133.872 0.084 133.896 ;
    END
  END i_slot[26]
  PIN i_slot[27]
    DIRECTION INPUT ;
    USE SIGNAL ;
    PORT
      LAYER M4 ;
        RECT  0 134.304 0.084 134.328 ;
    END
  END i_slot[27]
  PIN i_slot[28]
    DIRECTION INPUT ;
    USE SIGNAL ;
    PORT
      LAYER M4 ;
        RECT  0 134.736 0.084 134.76 ;
    END
  END i_slot[28]
  PIN i_slot[29]
    DIRECTION INPUT ;
    USE SIGNAL ;
    PORT
      LAYER M4 ;
        RECT  0 135.168 0.084 135.192 ;
    END
  END i_slot[29]
  PIN i_slot[2]
    DIRECTION INPUT ;
    USE SIGNAL ;
    PORT
      LAYER M4 ;
        RECT  0 123.504 0.084 123.528 ;
    END
  END i_slot[2]
  PIN i_slot[30]
    DIRECTION INPUT ;
    USE SIGNAL ;
    PORT
      LAYER M4 ;
        RECT  0 135.6 0.084 135.624 ;
    END
  END i_slot[30]
  PIN i_slot[31]
    DIRECTION INPUT ;
    USE SIGNAL ;
    PORT
      LAYER M4 ;
        RECT  0 136.032 0.084 136.056 ;
    END
  END i_slot[31]
  PIN i_slot[32]
    DIRECTION INPUT ;
    USE SIGNAL ;
    PORT
      LAYER M4 ;
        RECT  0 136.464 0.084 136.488 ;
    END
  END i_slot[32]
  PIN i_slot[33]
    DIRECTION INPUT ;
    USE SIGNAL ;
    PORT
      LAYER M4 ;
        RECT  0 136.896 0.084 136.92 ;
    END
  END i_slot[33]
  PIN i_slot[34]
    DIRECTION INPUT ;
    USE SIGNAL ;
    PORT
      LAYER M4 ;
        RECT  0 137.328 0.084 137.352 ;
    END
  END i_slot[34]
  PIN i_slot[35]
    DIRECTION INPUT ;
    USE SIGNAL ;
    PORT
      LAYER M4 ;
        RECT  0 137.76 0.084 137.784 ;
    END
  END i_slot[35]
  PIN i_slot[36]
    DIRECTION INPUT ;
    USE SIGNAL ;
    PORT
      LAYER M4 ;
        RECT  0 138.192 0.084 138.216 ;
    END
  END i_slot[36]
  PIN i_slot[37]
    DIRECTION INPUT ;
    USE SIGNAL ;
    PORT
      LAYER M4 ;
        RECT  0 138.624 0.084 138.648 ;
    END
  END i_slot[37]
  PIN i_slot[38]
    DIRECTION INPUT ;
    USE SIGNAL ;
    PORT
      LAYER M4 ;
        RECT  0 139.056 0.084 139.08 ;
    END
  END i_slot[38]
  PIN i_slot[39]
    DIRECTION INPUT ;
    USE SIGNAL ;
    PORT
      LAYER M4 ;
        RECT  0 139.488 0.084 139.512 ;
    END
  END i_slot[39]
  PIN i_slot[3]
    DIRECTION INPUT ;
    USE SIGNAL ;
    PORT
      LAYER M4 ;
        RECT  0 123.936 0.084 123.96 ;
    END
  END i_slot[3]
  PIN i_slot[40]
    DIRECTION INPUT ;
    USE SIGNAL ;
    PORT
      LAYER M4 ;
        RECT  0 139.92 0.084 139.944 ;
    END
  END i_slot[40]
  PIN i_slot[41]
    DIRECTION INPUT ;
    USE SIGNAL ;
    PORT
      LAYER M4 ;
        RECT  0 140.352 0.084 140.376 ;
    END
  END i_slot[41]
  PIN i_slot[42]
    DIRECTION INPUT ;
    USE SIGNAL ;
    PORT
      LAYER M4 ;
        RECT  0 140.784 0.084 140.808 ;
    END
  END i_slot[42]
  PIN i_slot[43]
    DIRECTION INPUT ;
    USE SIGNAL ;
    PORT
      LAYER M4 ;
        RECT  0 141.216 0.084 141.24 ;
    END
  END i_slot[43]
  PIN i_slot[44]
    DIRECTION INPUT ;
    USE SIGNAL ;
    PORT
      LAYER M4 ;
        RECT  0 141.648 0.084 141.672 ;
    END
  END i_slot[44]
  PIN i_slot[45]
    DIRECTION INPUT ;
    USE SIGNAL ;
    PORT
      LAYER M4 ;
        RECT  0 142.08 0.084 142.104 ;
    END
  END i_slot[45]
  PIN i_slot[46]
    DIRECTION INPUT ;
    USE SIGNAL ;
    PORT
      LAYER M4 ;
        RECT  0 142.512 0.084 142.536 ;
    END
  END i_slot[46]
  PIN i_slot[47]
    DIRECTION INPUT ;
    USE SIGNAL ;
    PORT
      LAYER M4 ;
        RECT  0 142.944 0.084 142.968 ;
    END
  END i_slot[47]
  PIN i_slot[48]
    DIRECTION INPUT ;
    USE SIGNAL ;
    PORT
      LAYER M4 ;
        RECT  0 143.376 0.084 143.4 ;
    END
  END i_slot[48]
  PIN i_slot[49]
    DIRECTION INPUT ;
    USE SIGNAL ;
    PORT
      LAYER M4 ;
        RECT  0 143.808 0.084 143.832 ;
    END
  END i_slot[49]
  PIN i_slot[4]
    DIRECTION INPUT ;
    USE SIGNAL ;
    PORT
      LAYER M4 ;
        RECT  0 124.368 0.084 124.392 ;
    END
  END i_slot[4]
  PIN i_slot[50]
    DIRECTION INPUT ;
    USE SIGNAL ;
    PORT
      LAYER M4 ;
        RECT  0 144.24 0.084 144.264 ;
    END
  END i_slot[50]
  PIN i_slot[51]
    DIRECTION INPUT ;
    USE SIGNAL ;
    PORT
      LAYER M4 ;
        RECT  0 144.672 0.084 144.696 ;
    END
  END i_slot[51]
  PIN i_slot[52]
    DIRECTION INPUT ;
    USE SIGNAL ;
    PORT
      LAYER M4 ;
        RECT  0 145.104 0.084 145.128 ;
    END
  END i_slot[52]
  PIN i_slot[53]
    DIRECTION INPUT ;
    USE SIGNAL ;
    PORT
      LAYER M4 ;
        RECT  0 145.536 0.084 145.56 ;
    END
  END i_slot[53]
  PIN i_slot[54]
    DIRECTION INPUT ;
    USE SIGNAL ;
    PORT
      LAYER M4 ;
        RECT  0 145.968 0.084 145.992 ;
    END
  END i_slot[54]
  PIN i_slot[55]
    DIRECTION INPUT ;
    USE SIGNAL ;
    PORT
      LAYER M4 ;
        RECT  0 146.4 0.084 146.424 ;
    END
  END i_slot[55]
  PIN i_slot[56]
    DIRECTION INPUT ;
    USE SIGNAL ;
    PORT
      LAYER M4 ;
        RECT  0 146.832 0.084 146.856 ;
    END
  END i_slot[56]
  PIN i_slot[57]
    DIRECTION INPUT ;
    USE SIGNAL ;
    PORT
      LAYER M4 ;
        RECT  0 147.264 0.084 147.288 ;
    END
  END i_slot[57]
  PIN i_slot[58]
    DIRECTION INPUT ;
    USE SIGNAL ;
    PORT
      LAYER M4 ;
        RECT  0 147.696 0.084 147.72 ;
    END
  END i_slot[58]
  PIN i_slot[59]
    DIRECTION INPUT ;
    USE SIGNAL ;
    PORT
      LAYER M4 ;
        RECT  0 148.128 0.084 148.152 ;
    END
  END i_slot[59]
  PIN i_slot[5]
    DIRECTION INPUT ;
    USE SIGNAL ;
    PORT
      LAYER M4 ;
        RECT  0 124.8 0.084 124.824 ;
    END
  END i_slot[5]
  PIN i_slot[60]
    DIRECTION INPUT ;
    USE SIGNAL ;
    PORT
      LAYER M4 ;
        RECT  0 148.56 0.084 148.584 ;
    END
  END i_slot[60]
  PIN i_slot[61]
    DIRECTION INPUT ;
    USE SIGNAL ;
    PORT
      LAYER M4 ;
        RECT  0 148.992 0.084 149.016 ;
    END
  END i_slot[61]
  PIN i_slot[62]
    DIRECTION INPUT ;
    USE SIGNAL ;
    PORT
      LAYER M4 ;
        RECT  0 149.424 0.084 149.448 ;
    END
  END i_slot[62]
  PIN i_slot[63]
    DIRECTION INPUT ;
    USE SIGNAL ;
    PORT
      LAYER M4 ;
        RECT  0 149.856 0.084 149.88 ;
    END
  END i_slot[63]
  PIN i_slot[64]
    DIRECTION INPUT ;
    USE SIGNAL ;
    PORT
      LAYER M4 ;
        RECT  0 150.288 0.084 150.312 ;
    END
  END i_slot[64]
  PIN i_slot[65]
    DIRECTION INPUT ;
    USE SIGNAL ;
    PORT
      LAYER M4 ;
        RECT  0 150.72 0.084 150.744 ;
    END
  END i_slot[65]
  PIN i_slot[66]
    DIRECTION INPUT ;
    USE SIGNAL ;
    PORT
      LAYER M4 ;
        RECT  0 151.152 0.084 151.176 ;
    END
  END i_slot[66]
  PIN i_slot[67]
    DIRECTION INPUT ;
    USE SIGNAL ;
    PORT
      LAYER M4 ;
        RECT  0 151.584 0.084 151.608 ;
    END
  END i_slot[67]
  PIN i_slot[68]
    DIRECTION INPUT ;
    USE SIGNAL ;
    PORT
      LAYER M4 ;
        RECT  0 152.016 0.084 152.04 ;
    END
  END i_slot[68]
  PIN i_slot[69]
    DIRECTION INPUT ;
    USE SIGNAL ;
    PORT
      LAYER M4 ;
        RECT  0 152.448 0.084 152.472 ;
    END
  END i_slot[69]
  PIN i_slot[6]
    DIRECTION INPUT ;
    USE SIGNAL ;
    PORT
      LAYER M4 ;
        RECT  0 125.232 0.084 125.256 ;
    END
  END i_slot[6]
  PIN i_slot[70]
    DIRECTION INPUT ;
    USE SIGNAL ;
    PORT
      LAYER M4 ;
        RECT  0 152.88 0.084 152.904 ;
    END
  END i_slot[70]
  PIN i_slot[71]
    DIRECTION INPUT ;
    USE SIGNAL ;
    PORT
      LAYER M4 ;
        RECT  0 153.312 0.084 153.336 ;
    END
  END i_slot[71]
  PIN i_slot[72]
    DIRECTION INPUT ;
    USE SIGNAL ;
    PORT
      LAYER M4 ;
        RECT  0 153.744 0.084 153.768 ;
    END
  END i_slot[72]
  PIN i_slot[73]
    DIRECTION INPUT ;
    USE SIGNAL ;
    PORT
      LAYER M4 ;
        RECT  0 154.176 0.084 154.2 ;
    END
  END i_slot[73]
  PIN i_slot[74]
    DIRECTION INPUT ;
    USE SIGNAL ;
    PORT
      LAYER M4 ;
        RECT  0 154.608 0.084 154.632 ;
    END
  END i_slot[74]
  PIN i_slot[75]
    DIRECTION INPUT ;
    USE SIGNAL ;
    PORT
      LAYER M4 ;
        RECT  0 155.04 0.084 155.064 ;
    END
  END i_slot[75]
  PIN i_slot[76]
    DIRECTION INPUT ;
    USE SIGNAL ;
    PORT
      LAYER M4 ;
        RECT  0 155.472 0.084 155.496 ;
    END
  END i_slot[76]
  PIN i_slot[77]
    DIRECTION INPUT ;
    USE SIGNAL ;
    PORT
      LAYER M4 ;
        RECT  0 155.904 0.084 155.928 ;
    END
  END i_slot[77]
  PIN i_slot[78]
    DIRECTION INPUT ;
    USE SIGNAL ;
    PORT
      LAYER M4 ;
        RECT  0 156.336 0.084 156.36 ;
    END
  END i_slot[78]
  PIN i_slot[79]
    DIRECTION INPUT ;
    USE SIGNAL ;
    PORT
      LAYER M4 ;
        RECT  0 156.768 0.084 156.792 ;
    END
  END i_slot[79]
  PIN i_slot[7]
    DIRECTION INPUT ;
    USE SIGNAL ;
    PORT
      LAYER M4 ;
        RECT  0 125.664 0.084 125.688 ;
    END
  END i_slot[7]
  PIN i_slot[80]
    DIRECTION INPUT ;
    USE SIGNAL ;
    PORT
      LAYER M4 ;
        RECT  0 157.2 0.084 157.224 ;
    END
  END i_slot[80]
  PIN i_slot[81]
    DIRECTION INPUT ;
    USE SIGNAL ;
    PORT
      LAYER M4 ;
        RECT  0 157.632 0.084 157.656 ;
    END
  END i_slot[81]
  PIN i_slot[82]
    DIRECTION INPUT ;
    USE SIGNAL ;
    PORT
      LAYER M4 ;
        RECT  0 158.064 0.084 158.088 ;
    END
  END i_slot[82]
  PIN i_slot[83]
    DIRECTION INPUT ;
    USE SIGNAL ;
    PORT
      LAYER M4 ;
        RECT  0 158.496 0.084 158.52 ;
    END
  END i_slot[83]
  PIN i_slot[84]
    DIRECTION INPUT ;
    USE SIGNAL ;
    PORT
      LAYER M4 ;
        RECT  0 158.928 0.084 158.952 ;
    END
  END i_slot[84]
  PIN i_slot[85]
    DIRECTION INPUT ;
    USE SIGNAL ;
    PORT
      LAYER M4 ;
        RECT  0 159.36 0.084 159.384 ;
    END
  END i_slot[85]
  PIN i_slot[86]
    DIRECTION INPUT ;
    USE SIGNAL ;
    PORT
      LAYER M4 ;
        RECT  0 159.792 0.084 159.816 ;
    END
  END i_slot[86]
  PIN i_slot[87]
    DIRECTION INPUT ;
    USE SIGNAL ;
    PORT
      LAYER M4 ;
        RECT  0 160.224 0.084 160.248 ;
    END
  END i_slot[87]
  PIN i_slot[88]
    DIRECTION INPUT ;
    USE SIGNAL ;
    PORT
      LAYER M4 ;
        RECT  0 160.656 0.084 160.68 ;
    END
  END i_slot[88]
  PIN i_slot[89]
    DIRECTION INPUT ;
    USE SIGNAL ;
    PORT
      LAYER M4 ;
        RECT  0 161.088 0.084 161.112 ;
    END
  END i_slot[89]
  PIN i_slot[8]
    DIRECTION INPUT ;
    USE SIGNAL ;
    PORT
      LAYER M4 ;
        RECT  0 126.096 0.084 126.12 ;
    END
  END i_slot[8]
  PIN i_slot[9]
    DIRECTION INPUT ;
    USE SIGNAL ;
    PORT
      LAYER M4 ;
        RECT  0 126.528 0.084 126.552 ;
    END
  END i_slot[9]
  PIN i_v[0]
    DIRECTION INPUT ;
    USE SIGNAL ;
    PORT
      LAYER M4 ;
        RECT  0 6 0.084 6.024 ;
    END
  END i_v[0]
  PIN i_v[10]
    DIRECTION INPUT ;
    USE SIGNAL ;
    PORT
      LAYER M4 ;
        RECT  0 10.32 0.084 10.344 ;
    END
  END i_v[10]
  PIN i_v[11]
    DIRECTION INPUT ;
    USE SIGNAL ;
    PORT
      LAYER M4 ;
        RECT  0 10.752 0.084 10.776 ;
    END
  END i_v[11]
  PIN i_v[12]
    DIRECTION INPUT ;
    USE SIGNAL ;
    PORT
      LAYER M4 ;
        RECT  0 11.184 0.084 11.208 ;
    END
  END i_v[12]
  PIN i_v[13]
    DIRECTION INPUT ;
    USE SIGNAL ;
    PORT
      LAYER M4 ;
        RECT  0 11.616 0.084 11.64 ;
    END
  END i_v[13]
  PIN i_v[14]
    DIRECTION INPUT ;
    USE SIGNAL ;
    PORT
      LAYER M4 ;
        RECT  0 12.048 0.084 12.072 ;
    END
  END i_v[14]
  PIN i_v[15]
    DIRECTION INPUT ;
    USE SIGNAL ;
    PORT
      LAYER M4 ;
        RECT  0 12.48 0.084 12.504 ;
    END
  END i_v[15]
  PIN i_v[16]
    DIRECTION INPUT ;
    USE SIGNAL ;
    PORT
      LAYER M4 ;
        RECT  0 12.912 0.084 12.936 ;
    END
  END i_v[16]
  PIN i_v[17]
    DIRECTION INPUT ;
    USE SIGNAL ;
    PORT
      LAYER M4 ;
        RECT  0 13.344 0.084 13.368 ;
    END
  END i_v[17]
  PIN i_v[1]
    DIRECTION INPUT ;
    USE SIGNAL ;
    PORT
      LAYER M4 ;
        RECT  0 6.432 0.084 6.456 ;
    END
  END i_v[1]
  PIN i_v[2]
    DIRECTION INPUT ;
    USE SIGNAL ;
    PORT
      LAYER M4 ;
        RECT  0 6.864 0.084 6.888 ;
    END
  END i_v[2]
  PIN i_v[3]
    DIRECTION INPUT ;
    USE SIGNAL ;
    PORT
      LAYER M4 ;
        RECT  0 7.296 0.084 7.32 ;
    END
  END i_v[3]
  PIN i_v[4]
    DIRECTION INPUT ;
    USE SIGNAL ;
    PORT
      LAYER M4 ;
        RECT  0 7.728 0.084 7.752 ;
    END
  END i_v[4]
  PIN i_v[5]
    DIRECTION INPUT ;
    USE SIGNAL ;
    PORT
      LAYER M4 ;
        RECT  0 8.16 0.084 8.184 ;
    END
  END i_v[5]
  PIN i_v[6]
    DIRECTION INPUT ;
    USE SIGNAL ;
    PORT
      LAYER M4 ;
        RECT  0 8.592 0.084 8.616 ;
    END
  END i_v[6]
  PIN i_v[7]
    DIRECTION INPUT ;
    USE SIGNAL ;
    PORT
      LAYER M4 ;
        RECT  0 9.024 0.084 9.048 ;
    END
  END i_v[7]
  PIN i_v[8]
    DIRECTION INPUT ;
    USE SIGNAL ;
    PORT
      LAYER M4 ;
        RECT  0 9.456 0.084 9.48 ;
    END
  END i_v[8]
  PIN i_v[9]
    DIRECTION INPUT ;
    USE SIGNAL ;
    PORT
      LAYER M4 ;
        RECT  0 9.888 0.084 9.912 ;
    END
  END i_v[9]
  PIN o_addr[0]
    DIRECTION OUTPUT ;
    USE SIGNAL ;
    PORT
      LAYER M4 ;
        RECT  155.436 95.424 155.52 95.448 ;
    END
  END o_addr[0]
  PIN o_addr[10]
    DIRECTION OUTPUT ;
    USE SIGNAL ;
    PORT
      LAYER M4 ;
        RECT  155.436 99.744 155.52 99.768 ;
    END
  END o_addr[10]
  PIN o_addr[11]
    DIRECTION OUTPUT ;
    USE SIGNAL ;
    PORT
      LAYER M4 ;
        RECT  155.436 100.176 155.52 100.2 ;
    END
  END o_addr[11]
  PIN o_addr[12]
    DIRECTION OUTPUT ;
    USE SIGNAL ;
    PORT
      LAYER M4 ;
        RECT  155.436 100.608 155.52 100.632 ;
    END
  END o_addr[12]
  PIN o_addr[13]
    DIRECTION OUTPUT ;
    USE SIGNAL ;
    PORT
      LAYER M4 ;
        RECT  155.436 101.04 155.52 101.064 ;
    END
  END o_addr[13]
  PIN o_addr[14]
    DIRECTION OUTPUT ;
    USE SIGNAL ;
    PORT
      LAYER M4 ;
        RECT  155.436 101.472 155.52 101.496 ;
    END
  END o_addr[14]
  PIN o_addr[15]
    DIRECTION OUTPUT ;
    USE SIGNAL ;
    PORT
      LAYER M4 ;
        RECT  155.436 101.904 155.52 101.928 ;
    END
  END o_addr[15]
  PIN o_addr[16]
    DIRECTION OUTPUT ;
    USE SIGNAL ;
    PORT
      LAYER M4 ;
        RECT  155.436 102.336 155.52 102.36 ;
    END
  END o_addr[16]
  PIN o_addr[17]
    DIRECTION OUTPUT ;
    USE SIGNAL ;
    PORT
      LAYER M4 ;
        RECT  155.436 102.768 155.52 102.792 ;
    END
  END o_addr[17]
  PIN o_addr[18]
    DIRECTION OUTPUT ;
    USE SIGNAL ;
    PORT
      LAYER M4 ;
        RECT  155.436 103.2 155.52 103.224 ;
    END
  END o_addr[18]
  PIN o_addr[19]
    DIRECTION OUTPUT ;
    USE SIGNAL ;
    PORT
      LAYER M4 ;
        RECT  155.436 103.632 155.52 103.656 ;
    END
  END o_addr[19]
  PIN o_addr[1]
    DIRECTION OUTPUT ;
    USE SIGNAL ;
    PORT
      LAYER M4 ;
        RECT  155.436 95.856 155.52 95.88 ;
    END
  END o_addr[1]
  PIN o_addr[20]
    DIRECTION OUTPUT ;
    USE SIGNAL ;
    PORT
      LAYER M4 ;
        RECT  155.436 104.064 155.52 104.088 ;
    END
  END o_addr[20]
  PIN o_addr[21]
    DIRECTION OUTPUT ;
    USE SIGNAL ;
    PORT
      LAYER M4 ;
        RECT  155.436 104.496 155.52 104.52 ;
    END
  END o_addr[21]
  PIN o_addr[22]
    DIRECTION OUTPUT ;
    USE SIGNAL ;
    PORT
      LAYER M4 ;
        RECT  155.436 104.928 155.52 104.952 ;
    END
  END o_addr[22]
  PIN o_addr[23]
    DIRECTION OUTPUT ;
    USE SIGNAL ;
    PORT
      LAYER M4 ;
        RECT  155.436 105.36 155.52 105.384 ;
    END
  END o_addr[23]
  PIN o_addr[24]
    DIRECTION OUTPUT ;
    USE SIGNAL ;
    PORT
      LAYER M4 ;
        RECT  155.436 105.792 155.52 105.816 ;
    END
  END o_addr[24]
  PIN o_addr[25]
    DIRECTION OUTPUT ;
    USE SIGNAL ;
    PORT
      LAYER M4 ;
        RECT  155.436 106.224 155.52 106.248 ;
    END
  END o_addr[25]
  PIN o_addr[26]
    DIRECTION OUTPUT ;
    USE SIGNAL ;
    PORT
      LAYER M4 ;
        RECT  155.436 106.656 155.52 106.68 ;
    END
  END o_addr[26]
  PIN o_addr[27]
    DIRECTION OUTPUT ;
    USE SIGNAL ;
    PORT
      LAYER M4 ;
        RECT  155.436 107.088 155.52 107.112 ;
    END
  END o_addr[27]
  PIN o_addr[28]
    DIRECTION OUTPUT ;
    USE SIGNAL ;
    PORT
      LAYER M4 ;
        RECT  155.436 107.52 155.52 107.544 ;
    END
  END o_addr[28]
  PIN o_addr[29]
    DIRECTION OUTPUT ;
    USE SIGNAL ;
    PORT
      LAYER M4 ;
        RECT  155.436 107.952 155.52 107.976 ;
    END
  END o_addr[29]
  PIN o_addr[2]
    DIRECTION OUTPUT ;
    USE SIGNAL ;
    PORT
      LAYER M4 ;
        RECT  155.436 96.288 155.52 96.312 ;
    END
  END o_addr[2]
  PIN o_addr[30]
    DIRECTION OUTPUT ;
    USE SIGNAL ;
    PORT
      LAYER M4 ;
        RECT  155.436 108.384 155.52 108.408 ;
    END
  END o_addr[30]
  PIN o_addr[31]
    DIRECTION OUTPUT ;
    USE SIGNAL ;
    PORT
      LAYER M4 ;
        RECT  155.436 108.816 155.52 108.84 ;
    END
  END o_addr[31]
  PIN o_addr[32]
    DIRECTION OUTPUT ;
    USE SIGNAL ;
    PORT
      LAYER M4 ;
        RECT  155.436 109.248 155.52 109.272 ;
    END
  END o_addr[32]
  PIN o_addr[33]
    DIRECTION OUTPUT ;
    USE SIGNAL ;
    PORT
      LAYER M4 ;
        RECT  155.436 109.68 155.52 109.704 ;
    END
  END o_addr[33]
  PIN o_addr[34]
    DIRECTION OUTPUT ;
    USE SIGNAL ;
    PORT
      LAYER M4 ;
        RECT  155.436 110.112 155.52 110.136 ;
    END
  END o_addr[34]
  PIN o_addr[35]
    DIRECTION OUTPUT ;
    USE SIGNAL ;
    PORT
      LAYER M4 ;
        RECT  155.436 110.544 155.52 110.568 ;
    END
  END o_addr[35]
  PIN o_addr[36]
    DIRECTION OUTPUT ;
    USE SIGNAL ;
    PORT
      LAYER M4 ;
        RECT  155.436 110.976 155.52 111 ;
    END
  END o_addr[36]
  PIN o_addr[37]
    DIRECTION OUTPUT ;
    USE SIGNAL ;
    PORT
      LAYER M4 ;
        RECT  155.436 111.408 155.52 111.432 ;
    END
  END o_addr[37]
  PIN o_addr[38]
    DIRECTION OUTPUT ;
    USE SIGNAL ;
    PORT
      LAYER M4 ;
        RECT  155.436 111.84 155.52 111.864 ;
    END
  END o_addr[38]
  PIN o_addr[39]
    DIRECTION OUTPUT ;
    USE SIGNAL ;
    PORT
      LAYER M4 ;
        RECT  155.436 112.272 155.52 112.296 ;
    END
  END o_addr[39]
  PIN o_addr[3]
    DIRECTION OUTPUT ;
    USE SIGNAL ;
    PORT
      LAYER M4 ;
        RECT  155.436 96.72 155.52 96.744 ;
    END
  END o_addr[3]
  PIN o_addr[40]
    DIRECTION OUTPUT ;
    USE SIGNAL ;
    PORT
      LAYER M4 ;
        RECT  155.436 112.704 155.52 112.728 ;
    END
  END o_addr[40]
  PIN o_addr[41]
    DIRECTION OUTPUT ;
    USE SIGNAL ;
    PORT
      LAYER M4 ;
        RECT  155.436 113.136 155.52 113.16 ;
    END
  END o_addr[41]
  PIN o_addr[42]
    DIRECTION OUTPUT ;
    USE SIGNAL ;
    PORT
      LAYER M4 ;
        RECT  155.436 113.568 155.52 113.592 ;
    END
  END o_addr[42]
  PIN o_addr[43]
    DIRECTION OUTPUT ;
    USE SIGNAL ;
    PORT
      LAYER M4 ;
        RECT  155.436 114 155.52 114.024 ;
    END
  END o_addr[43]
  PIN o_addr[44]
    DIRECTION OUTPUT ;
    USE SIGNAL ;
    PORT
      LAYER M4 ;
        RECT  155.436 114.432 155.52 114.456 ;
    END
  END o_addr[44]
  PIN o_addr[45]
    DIRECTION OUTPUT ;
    USE SIGNAL ;
    PORT
      LAYER M4 ;
        RECT  155.436 114.864 155.52 114.888 ;
    END
  END o_addr[45]
  PIN o_addr[46]
    DIRECTION OUTPUT ;
    USE SIGNAL ;
    PORT
      LAYER M4 ;
        RECT  155.436 115.296 155.52 115.32 ;
    END
  END o_addr[46]
  PIN o_addr[47]
    DIRECTION OUTPUT ;
    USE SIGNAL ;
    PORT
      LAYER M4 ;
        RECT  155.436 115.728 155.52 115.752 ;
    END
  END o_addr[47]
  PIN o_addr[48]
    DIRECTION OUTPUT ;
    USE SIGNAL ;
    PORT
      LAYER M4 ;
        RECT  155.436 116.16 155.52 116.184 ;
    END
  END o_addr[48]
  PIN o_addr[49]
    DIRECTION OUTPUT ;
    USE SIGNAL ;
    PORT
      LAYER M4 ;
        RECT  155.436 116.592 155.52 116.616 ;
    END
  END o_addr[49]
  PIN o_addr[4]
    DIRECTION OUTPUT ;
    USE SIGNAL ;
    PORT
      LAYER M4 ;
        RECT  155.436 97.152 155.52 97.176 ;
    END
  END o_addr[4]
  PIN o_addr[50]
    DIRECTION OUTPUT ;
    USE SIGNAL ;
    PORT
      LAYER M4 ;
        RECT  155.436 117.024 155.52 117.048 ;
    END
  END o_addr[50]
  PIN o_addr[51]
    DIRECTION OUTPUT ;
    USE SIGNAL ;
    PORT
      LAYER M4 ;
        RECT  155.436 117.456 155.52 117.48 ;
    END
  END o_addr[51]
  PIN o_addr[52]
    DIRECTION OUTPUT ;
    USE SIGNAL ;
    PORT
      LAYER M4 ;
        RECT  155.436 117.888 155.52 117.912 ;
    END
  END o_addr[52]
  PIN o_addr[53]
    DIRECTION OUTPUT ;
    USE SIGNAL ;
    PORT
      LAYER M4 ;
        RECT  155.436 118.32 155.52 118.344 ;
    END
  END o_addr[53]
  PIN o_addr[54]
    DIRECTION OUTPUT ;
    USE SIGNAL ;
    PORT
      LAYER M4 ;
        RECT  155.436 118.752 155.52 118.776 ;
    END
  END o_addr[54]
  PIN o_addr[55]
    DIRECTION OUTPUT ;
    USE SIGNAL ;
    PORT
      LAYER M4 ;
        RECT  155.436 119.184 155.52 119.208 ;
    END
  END o_addr[55]
  PIN o_addr[56]
    DIRECTION OUTPUT ;
    USE SIGNAL ;
    PORT
      LAYER M4 ;
        RECT  155.436 119.616 155.52 119.64 ;
    END
  END o_addr[56]
  PIN o_addr[57]
    DIRECTION OUTPUT ;
    USE SIGNAL ;
    PORT
      LAYER M4 ;
        RECT  155.436 120.048 155.52 120.072 ;
    END
  END o_addr[57]
  PIN o_addr[58]
    DIRECTION OUTPUT ;
    USE SIGNAL ;
    PORT
      LAYER M4 ;
        RECT  155.436 120.48 155.52 120.504 ;
    END
  END o_addr[58]
  PIN o_addr[59]
    DIRECTION OUTPUT ;
    USE SIGNAL ;
    PORT
      LAYER M4 ;
        RECT  155.436 120.912 155.52 120.936 ;
    END
  END o_addr[59]
  PIN o_addr[5]
    DIRECTION OUTPUT ;
    USE SIGNAL ;
    PORT
      LAYER M4 ;
        RECT  155.436 97.584 155.52 97.608 ;
    END
  END o_addr[5]
  PIN o_addr[60]
    DIRECTION OUTPUT ;
    USE SIGNAL ;
    PORT
      LAYER M4 ;
        RECT  155.436 121.344 155.52 121.368 ;
    END
  END o_addr[60]
  PIN o_addr[61]
    DIRECTION OUTPUT ;
    USE SIGNAL ;
    PORT
      LAYER M4 ;
        RECT  155.436 121.776 155.52 121.8 ;
    END
  END o_addr[61]
  PIN o_addr[62]
    DIRECTION OUTPUT ;
    USE SIGNAL ;
    PORT
      LAYER M4 ;
        RECT  155.436 122.208 155.52 122.232 ;
    END
  END o_addr[62]
  PIN o_addr[63]
    DIRECTION OUTPUT ;
    USE SIGNAL ;
    PORT
      LAYER M4 ;
        RECT  155.436 122.64 155.52 122.664 ;
    END
  END o_addr[63]
  PIN o_addr[64]
    DIRECTION OUTPUT ;
    USE SIGNAL ;
    PORT
      LAYER M4 ;
        RECT  155.436 123.072 155.52 123.096 ;
    END
  END o_addr[64]
  PIN o_addr[65]
    DIRECTION OUTPUT ;
    USE SIGNAL ;
    PORT
      LAYER M4 ;
        RECT  155.436 123.504 155.52 123.528 ;
    END
  END o_addr[65]
  PIN o_addr[66]
    DIRECTION OUTPUT ;
    USE SIGNAL ;
    PORT
      LAYER M4 ;
        RECT  155.436 123.936 155.52 123.96 ;
    END
  END o_addr[66]
  PIN o_addr[67]
    DIRECTION OUTPUT ;
    USE SIGNAL ;
    PORT
      LAYER M4 ;
        RECT  155.436 124.368 155.52 124.392 ;
    END
  END o_addr[67]
  PIN o_addr[68]
    DIRECTION OUTPUT ;
    USE SIGNAL ;
    PORT
      LAYER M4 ;
        RECT  155.436 124.8 155.52 124.824 ;
    END
  END o_addr[68]
  PIN o_addr[69]
    DIRECTION OUTPUT ;
    USE SIGNAL ;
    PORT
      LAYER M4 ;
        RECT  155.436 125.232 155.52 125.256 ;
    END
  END o_addr[69]
  PIN o_addr[6]
    DIRECTION OUTPUT ;
    USE SIGNAL ;
    PORT
      LAYER M4 ;
        RECT  155.436 98.016 155.52 98.04 ;
    END
  END o_addr[6]
  PIN o_addr[70]
    DIRECTION OUTPUT ;
    USE SIGNAL ;
    PORT
      LAYER M4 ;
        RECT  155.436 125.664 155.52 125.688 ;
    END
  END o_addr[70]
  PIN o_addr[71]
    DIRECTION OUTPUT ;
    USE SIGNAL ;
    PORT
      LAYER M4 ;
        RECT  155.436 126.096 155.52 126.12 ;
    END
  END o_addr[71]
  PIN o_addr[7]
    DIRECTION OUTPUT ;
    USE SIGNAL ;
    PORT
      LAYER M4 ;
        RECT  155.436 98.448 155.52 98.472 ;
    END
  END o_addr[7]
  PIN o_addr[8]
    DIRECTION OUTPUT ;
    USE SIGNAL ;
    PORT
      LAYER M4 ;
        RECT  155.436 98.88 155.52 98.904 ;
    END
  END o_addr[8]
  PIN o_addr[9]
    DIRECTION OUTPUT ;
    USE SIGNAL ;
    PORT
      LAYER M4 ;
        RECT  155.436 99.312 155.52 99.336 ;
    END
  END o_addr[9]
  PIN o_tag[0]
    DIRECTION OUTPUT ;
    USE SIGNAL ;
    PORT
      LAYER M4 ;
        RECT  155.436 126.528 155.52 126.552 ;
    END
  END o_tag[0]
  PIN o_tag[10]
    DIRECTION OUTPUT ;
    USE SIGNAL ;
    PORT
      LAYER M4 ;
        RECT  155.436 130.848 155.52 130.872 ;
    END
  END o_tag[10]
  PIN o_tag[11]
    DIRECTION OUTPUT ;
    USE SIGNAL ;
    PORT
      LAYER M4 ;
        RECT  155.436 131.28 155.52 131.304 ;
    END
  END o_tag[11]
  PIN o_tag[12]
    DIRECTION OUTPUT ;
    USE SIGNAL ;
    PORT
      LAYER M4 ;
        RECT  155.436 131.712 155.52 131.736 ;
    END
  END o_tag[12]
  PIN o_tag[13]
    DIRECTION OUTPUT ;
    USE SIGNAL ;
    PORT
      LAYER M4 ;
        RECT  155.436 132.144 155.52 132.168 ;
    END
  END o_tag[13]
  PIN o_tag[14]
    DIRECTION OUTPUT ;
    USE SIGNAL ;
    PORT
      LAYER M4 ;
        RECT  155.436 132.576 155.52 132.6 ;
    END
  END o_tag[14]
  PIN o_tag[15]
    DIRECTION OUTPUT ;
    USE SIGNAL ;
    PORT
      LAYER M4 ;
        RECT  155.436 133.008 155.52 133.032 ;
    END
  END o_tag[15]
  PIN o_tag[16]
    DIRECTION OUTPUT ;
    USE SIGNAL ;
    PORT
      LAYER M4 ;
        RECT  155.436 133.44 155.52 133.464 ;
    END
  END o_tag[16]
  PIN o_tag[17]
    DIRECTION OUTPUT ;
    USE SIGNAL ;
    PORT
      LAYER M4 ;
        RECT  155.436 133.872 155.52 133.896 ;
    END
  END o_tag[17]
  PIN o_tag[18]
    DIRECTION OUTPUT ;
    USE SIGNAL ;
    PORT
      LAYER M4 ;
        RECT  155.436 134.304 155.52 134.328 ;
    END
  END o_tag[18]
  PIN o_tag[19]
    DIRECTION OUTPUT ;
    USE SIGNAL ;
    PORT
      LAYER M4 ;
        RECT  155.436 134.736 155.52 134.76 ;
    END
  END o_tag[19]
  PIN o_tag[1]
    DIRECTION OUTPUT ;
    USE SIGNAL ;
    PORT
      LAYER M4 ;
        RECT  155.436 126.96 155.52 126.984 ;
    END
  END o_tag[1]
  PIN o_tag[20]
    DIRECTION OUTPUT ;
    USE SIGNAL ;
    PORT
      LAYER M4 ;
        RECT  155.436 135.168 155.52 135.192 ;
    END
  END o_tag[20]
  PIN o_tag[21]
    DIRECTION OUTPUT ;
    USE SIGNAL ;
    PORT
      LAYER M4 ;
        RECT  155.436 135.6 155.52 135.624 ;
    END
  END o_tag[21]
  PIN o_tag[22]
    DIRECTION OUTPUT ;
    USE SIGNAL ;
    PORT
      LAYER M4 ;
        RECT  155.436 136.032 155.52 136.056 ;
    END
  END o_tag[22]
  PIN o_tag[23]
    DIRECTION OUTPUT ;
    USE SIGNAL ;
    PORT
      LAYER M4 ;
        RECT  155.436 136.464 155.52 136.488 ;
    END
  END o_tag[23]
  PIN o_tag[24]
    DIRECTION OUTPUT ;
    USE SIGNAL ;
    PORT
      LAYER M4 ;
        RECT  155.436 136.896 155.52 136.92 ;
    END
  END o_tag[24]
  PIN o_tag[25]
    DIRECTION OUTPUT ;
    USE SIGNAL ;
    PORT
      LAYER M4 ;
        RECT  155.436 137.328 155.52 137.352 ;
    END
  END o_tag[25]
  PIN o_tag[26]
    DIRECTION OUTPUT ;
    USE SIGNAL ;
    PORT
      LAYER M4 ;
        RECT  155.436 137.76 155.52 137.784 ;
    END
  END o_tag[26]
  PIN o_tag[27]
    DIRECTION OUTPUT ;
    USE SIGNAL ;
    PORT
      LAYER M4 ;
        RECT  155.436 138.192 155.52 138.216 ;
    END
  END o_tag[27]
  PIN o_tag[28]
    DIRECTION OUTPUT ;
    USE SIGNAL ;
    PORT
      LAYER M4 ;
        RECT  155.436 138.624 155.52 138.648 ;
    END
  END o_tag[28]
  PIN o_tag[29]
    DIRECTION OUTPUT ;
    USE SIGNAL ;
    PORT
      LAYER M4 ;
        RECT  155.436 139.056 155.52 139.08 ;
    END
  END o_tag[29]
  PIN o_tag[2]
    DIRECTION OUTPUT ;
    USE SIGNAL ;
    PORT
      LAYER M4 ;
        RECT  155.436 127.392 155.52 127.416 ;
    END
  END o_tag[2]
  PIN o_tag[30]
    DIRECTION OUTPUT ;
    USE SIGNAL ;
    PORT
      LAYER M4 ;
        RECT  155.436 139.488 155.52 139.512 ;
    END
  END o_tag[30]
  PIN o_tag[31]
    DIRECTION OUTPUT ;
    USE SIGNAL ;
    PORT
      LAYER M4 ;
        RECT  155.436 139.92 155.52 139.944 ;
    END
  END o_tag[31]
  PIN o_tag[32]
    DIRECTION OUTPUT ;
    USE SIGNAL ;
    PORT
      LAYER M4 ;
        RECT  155.436 140.352 155.52 140.376 ;
    END
  END o_tag[32]
  PIN o_tag[33]
    DIRECTION OUTPUT ;
    USE SIGNAL ;
    PORT
      LAYER M4 ;
        RECT  155.436 140.784 155.52 140.808 ;
    END
  END o_tag[33]
  PIN o_tag[34]
    DIRECTION OUTPUT ;
    USE SIGNAL ;
    PORT
      LAYER M4 ;
        RECT  155.436 141.216 155.52 141.24 ;
    END
  END o_tag[34]
  PIN o_tag[35]
    DIRECTION OUTPUT ;
    USE SIGNAL ;
    PORT
      LAYER M4 ;
        RECT  155.436 141.648 155.52 141.672 ;
    END
  END o_tag[35]
  PIN o_tag[36]
    DIRECTION OUTPUT ;
    USE SIGNAL ;
    PORT
      LAYER M4 ;
        RECT  155.436 142.08 155.52 142.104 ;
    END
  END o_tag[36]
  PIN o_tag[37]
    DIRECTION OUTPUT ;
    USE SIGNAL ;
    PORT
      LAYER M4 ;
        RECT  155.436 142.512 155.52 142.536 ;
    END
  END o_tag[37]
  PIN o_tag[38]
    DIRECTION OUTPUT ;
    USE SIGNAL ;
    PORT
      LAYER M4 ;
        RECT  155.436 142.944 155.52 142.968 ;
    END
  END o_tag[38]
  PIN o_tag[39]
    DIRECTION OUTPUT ;
    USE SIGNAL ;
    PORT
      LAYER M4 ;
        RECT  155.436 143.376 155.52 143.4 ;
    END
  END o_tag[39]
  PIN o_tag[3]
    DIRECTION OUTPUT ;
    USE SIGNAL ;
    PORT
      LAYER M4 ;
        RECT  155.436 127.824 155.52 127.848 ;
    END
  END o_tag[3]
  PIN o_tag[40]
    DIRECTION OUTPUT ;
    USE SIGNAL ;
    PORT
      LAYER M4 ;
        RECT  155.436 143.808 155.52 143.832 ;
    END
  END o_tag[40]
  PIN o_tag[41]
    DIRECTION OUTPUT ;
    USE SIGNAL ;
    PORT
      LAYER M4 ;
        RECT  155.436 144.24 155.52 144.264 ;
    END
  END o_tag[41]
  PIN o_tag[42]
    DIRECTION OUTPUT ;
    USE SIGNAL ;
    PORT
      LAYER M4 ;
        RECT  155.436 144.672 155.52 144.696 ;
    END
  END o_tag[42]
  PIN o_tag[43]
    DIRECTION OUTPUT ;
    USE SIGNAL ;
    PORT
      LAYER M4 ;
        RECT  155.436 145.104 155.52 145.128 ;
    END
  END o_tag[43]
  PIN o_tag[44]
    DIRECTION OUTPUT ;
    USE SIGNAL ;
    PORT
      LAYER M4 ;
        RECT  155.436 145.536 155.52 145.56 ;
    END
  END o_tag[44]
  PIN o_tag[45]
    DIRECTION OUTPUT ;
    USE SIGNAL ;
    PORT
      LAYER M4 ;
        RECT  155.436 145.968 155.52 145.992 ;
    END
  END o_tag[45]
  PIN o_tag[46]
    DIRECTION OUTPUT ;
    USE SIGNAL ;
    PORT
      LAYER M4 ;
        RECT  155.436 146.4 155.52 146.424 ;
    END
  END o_tag[46]
  PIN o_tag[47]
    DIRECTION OUTPUT ;
    USE SIGNAL ;
    PORT
      LAYER M4 ;
        RECT  155.436 146.832 155.52 146.856 ;
    END
  END o_tag[47]
  PIN o_tag[48]
    DIRECTION OUTPUT ;
    USE SIGNAL ;
    PORT
      LAYER M4 ;
        RECT  155.436 147.264 155.52 147.288 ;
    END
  END o_tag[48]
  PIN o_tag[49]
    DIRECTION OUTPUT ;
    USE SIGNAL ;
    PORT
      LAYER M4 ;
        RECT  155.436 147.696 155.52 147.72 ;
    END
  END o_tag[49]
  PIN o_tag[4]
    DIRECTION OUTPUT ;
    USE SIGNAL ;
    PORT
      LAYER M4 ;
        RECT  155.436 128.256 155.52 128.28 ;
    END
  END o_tag[4]
  PIN o_tag[50]
    DIRECTION OUTPUT ;
    USE SIGNAL ;
    PORT
      LAYER M4 ;
        RECT  155.436 148.128 155.52 148.152 ;
    END
  END o_tag[50]
  PIN o_tag[51]
    DIRECTION OUTPUT ;
    USE SIGNAL ;
    PORT
      LAYER M4 ;
        RECT  155.436 148.56 155.52 148.584 ;
    END
  END o_tag[51]
  PIN o_tag[52]
    DIRECTION OUTPUT ;
    USE SIGNAL ;
    PORT
      LAYER M4 ;
        RECT  155.436 148.992 155.52 149.016 ;
    END
  END o_tag[52]
  PIN o_tag[53]
    DIRECTION OUTPUT ;
    USE SIGNAL ;
    PORT
      LAYER M4 ;
        RECT  155.436 149.424 155.52 149.448 ;
    END
  END o_tag[53]
  PIN o_tag[54]
    DIRECTION OUTPUT ;
    USE SIGNAL ;
    PORT
      LAYER M4 ;
        RECT  155.436 149.856 155.52 149.88 ;
    END
  END o_tag[54]
  PIN o_tag[55]
    DIRECTION OUTPUT ;
    USE SIGNAL ;
    PORT
      LAYER M4 ;
        RECT  155.436 150.288 155.52 150.312 ;
    END
  END o_tag[55]
  PIN o_tag[56]
    DIRECTION OUTPUT ;
    USE SIGNAL ;
    PORT
      LAYER M4 ;
        RECT  155.436 150.72 155.52 150.744 ;
    END
  END o_tag[56]
  PIN o_tag[57]
    DIRECTION OUTPUT ;
    USE SIGNAL ;
    PORT
      LAYER M4 ;
        RECT  155.436 151.152 155.52 151.176 ;
    END
  END o_tag[57]
  PIN o_tag[58]
    DIRECTION OUTPUT ;
    USE SIGNAL ;
    PORT
      LAYER M4 ;
        RECT  155.436 151.584 155.52 151.608 ;
    END
  END o_tag[58]
  PIN o_tag[59]
    DIRECTION OUTPUT ;
    USE SIGNAL ;
    PORT
      LAYER M4 ;
        RECT  155.436 152.016 155.52 152.04 ;
    END
  END o_tag[59]
  PIN o_tag[5]
    DIRECTION OUTPUT ;
    USE SIGNAL ;
    PORT
      LAYER M4 ;
        RECT  155.436 128.688 155.52 128.712 ;
    END
  END o_tag[5]
  PIN o_tag[60]
    DIRECTION OUTPUT ;
    USE SIGNAL ;
    PORT
      LAYER M4 ;
        RECT  155.436 152.448 155.52 152.472 ;
    END
  END o_tag[60]
  PIN o_tag[61]
    DIRECTION OUTPUT ;
    USE SIGNAL ;
    PORT
      LAYER M4 ;
        RECT  155.436 152.88 155.52 152.904 ;
    END
  END o_tag[61]
  PIN o_tag[62]
    DIRECTION OUTPUT ;
    USE SIGNAL ;
    PORT
      LAYER M4 ;
        RECT  155.436 153.312 155.52 153.336 ;
    END
  END o_tag[62]
  PIN o_tag[63]
    DIRECTION OUTPUT ;
    USE SIGNAL ;
    PORT
      LAYER M4 ;
        RECT  155.436 153.744 155.52 153.768 ;
    END
  END o_tag[63]
  PIN o_tag[6]
    DIRECTION OUTPUT ;
    USE SIGNAL ;
    PORT
      LAYER M4 ;
        RECT  155.436 129.12 155.52 129.144 ;
    END
  END o_tag[6]
  PIN o_tag[7]
    DIRECTION OUTPUT ;
    USE SIGNAL ;
    PORT
      LAYER M4 ;
        RECT  155.436 129.552 155.52 129.576 ;
    END
  END o_tag[7]
  PIN o_tag[8]
    DIRECTION OUTPUT ;
    USE SIGNAL ;
    PORT
      LAYER M4 ;
        RECT  155.436 129.984 155.52 130.008 ;
    END
  END o_tag[8]
  PIN o_tag[9]
    DIRECTION OUTPUT ;
    USE SIGNAL ;
    PORT
      LAYER M4 ;
        RECT  155.436 130.416 155.52 130.44 ;
    END
  END o_tag[9]
  PIN o_v[0]
    DIRECTION OUTPUT ;
    USE SIGNAL ;
    PORT
      LAYER M4 ;
        RECT  155.436 91.968 155.52 91.992 ;
    END
  END o_v[0]
  PIN o_v[1]
    DIRECTION OUTPUT ;
    USE SIGNAL ;
    PORT
      LAYER M4 ;
        RECT  155.436 92.4 155.52 92.424 ;
    END
  END o_v[1]
  PIN o_v[2]
    DIRECTION OUTPUT ;
    USE SIGNAL ;
    PORT
      LAYER M4 ;
        RECT  155.436 92.832 155.52 92.856 ;
    END
  END o_v[2]
  PIN o_v[3]
    DIRECTION OUTPUT ;
    USE SIGNAL ;
    PORT
      LAYER M4 ;
        RECT  155.436 93.264 155.52 93.288 ;
    END
  END o_v[3]
  PIN o_v[4]
    DIRECTION OUTPUT ;
    USE SIGNAL ;
    PORT
      LAYER M4 ;
        RECT  155.436 93.696 155.52 93.72 ;
    END
  END o_v[4]
  PIN o_v[5]
    DIRECTION OUTPUT ;
    USE SIGNAL ;
    PORT
      LAYER M4 ;
        RECT  155.436 94.128 155.52 94.152 ;
    END
  END o_v[5]
  PIN o_v[6]
    DIRECTION OUTPUT ;
    USE SIGNAL ;
    PORT
      LAYER M4 ;
        RECT  155.436 94.56 155.52 94.584 ;
    END
  END o_v[6]
  PIN o_v[7]
    DIRECTION OUTPUT ;
    USE SIGNAL ;
    PORT
      LAYER M4 ;
        RECT  155.436 94.992 155.52 95.016 ;
    END
  END o_v[7]
  PIN rst_n
    DIRECTION INPUT ;
    USE SIGNAL ;
    PORT
      LAYER M5 ;
        RECT  77.952 246.156 77.976 246.24 ;
    END
  END rst_n
  PIN VDD
    DIRECTION INOUT ;
    USE POWER ;
    PORT
      LAYER M5 ;
        RECT  148.392 2.151 148.512 244.089 ;
        RECT  142.992 2.151 143.112 244.089 ;
        RECT  137.592 2.151 137.712 244.089 ;
        RECT  132.192 2.151 132.312 244.089 ;
        RECT  126.792 2.151 126.912 244.089 ;
        RECT  121.392 2.151 121.512 244.089 ;
        RECT  115.992 2.151 116.112 244.089 ;
        RECT  110.592 2.151 110.712 244.089 ;
        RECT  105.192 2.151 105.312 244.089 ;
        RECT  99.792 2.151 99.912 244.089 ;
        RECT  94.392 2.151 94.512 244.089 ;
        RECT  88.992 2.151 89.112 244.089 ;
        RECT  83.592 2.151 83.712 244.089 ;
        RECT  78.192 2.151 78.312 244.089 ;
        RECT  72.792 2.151 72.912 244.089 ;
        RECT  67.392 2.151 67.512 244.089 ;
        RECT  61.992 2.151 62.112 244.089 ;
        RECT  56.592 2.151 56.712 244.089 ;
        RECT  51.192 2.151 51.312 244.089 ;
        RECT  45.792 2.151 45.912 244.089 ;
        RECT  40.392 2.151 40.512 244.089 ;
        RECT  34.992 2.151 35.112 244.089 ;
        RECT  29.592 2.151 29.712 244.089 ;
        RECT  24.192 2.151 24.312 244.089 ;
        RECT  18.792 2.151 18.912 244.089 ;
        RECT  13.392 2.151 13.512 244.089 ;
        RECT  7.992 2.151 8.112 244.089 ;
        RECT  2.592 2.151 2.712 244.089 ;
    END
  END VDD
  PIN VSS
    DIRECTION INOUT ;
    USE GROUND ;
    PORT
      LAYER M5 ;
        RECT  148.2 2.137 148.32 244.103 ;
        RECT  142.8 2.137 142.92 244.103 ;
        RECT  137.4 2.137 137.52 244.103 ;
        RECT  132 2.137 132.12 244.103 ;
        RECT  126.6 2.137 126.72 244.103 ;
        RECT  121.2 2.137 121.32 244.103 ;
        RECT  115.8 2.137 115.92 244.103 ;
        RECT  110.4 2.137 110.52 244.103 ;
        RECT  105 2.137 105.12 244.103 ;
        RECT  99.6 2.137 99.72 244.103 ;
        RECT  94.2 2.137 94.32 244.103 ;
        RECT  88.8 2.137 88.92 244.103 ;
        RECT  83.4 2.137 83.52 244.103 ;
        RECT  78 2.137 78.12 244.103 ;
        RECT  72.6 2.137 72.72 244.103 ;
        RECT  67.2 2.137 67.32 244.103 ;
        RECT  61.8 2.137 61.92 244.103 ;
        RECT  56.4 2.137 56.52 244.103 ;
        RECT  51 2.137 51.12 244.103 ;
        RECT  45.6 2.137 45.72 244.103 ;
        RECT  40.2 2.137 40.32 244.103 ;
        RECT  34.8 2.137 34.92 244.103 ;
        RECT  29.4 2.137 29.52 244.103 ;
        RECT  24 2.137 24.12 244.103 ;
        RECT  18.6 2.137 18.72 244.103 ;
        RECT  13.2 2.137 13.32 244.103 ;
        RECT  7.8 2.137 7.92 244.103 ;
        RECT  2.4 2.137 2.52 244.103 ;
    END
  END VSS
  # OT_OBS_CLOSED layer=M5 d_um=1.536 added=87
  OBS
    LAYER RVTN ;
     RECT  2.16 2.16 153.36 2.295 ;
     RECT  2.16 2.565 153.36 2.835 ;
     RECT  2.16 3.105 153.36 3.375 ;
     RECT  2.16 3.645 153.36 3.915 ;
     RECT  2.16 4.185 153.36 4.455 ;
     RECT  2.16 4.725 153.36 4.995 ;
     RECT  2.16 5.265 153.36 5.535 ;
     RECT  2.16 5.805 153.36 6.075 ;
     RECT  2.16 6.345 153.36 6.615 ;
     RECT  2.16 6.885 153.36 7.155 ;
     RECT  2.16 7.425 153.36 7.695 ;
     RECT  2.16 7.965 153.36 8.235 ;
     RECT  2.16 8.505 153.36 8.775 ;
     RECT  2.16 9.045 153.36 9.315 ;
     RECT  2.16 9.585 153.36 9.855 ;
     RECT  2.16 10.125 153.36 10.395 ;
     RECT  2.16 10.665 153.36 10.935 ;
     RECT  2.16 11.205 153.36 11.475 ;
     RECT  2.16 11.745 153.36 12.015 ;
     RECT  2.16 12.285 153.36 12.555 ;
     RECT  2.16 12.825 153.36 13.095 ;
     RECT  2.16 13.365 153.36 13.635 ;
     RECT  2.16 13.905 153.36 14.175 ;
     RECT  2.16 14.445 153.36 14.715 ;
     RECT  2.16 14.985 153.36 15.255 ;
     RECT  2.16 15.525 153.36 15.795 ;
     RECT  2.16 16.065 153.36 16.335 ;
     RECT  2.16 16.605 153.36 16.875 ;
     RECT  2.16 17.145 153.36 17.415 ;
     RECT  2.16 17.685 153.36 17.955 ;
     RECT  2.16 18.225 153.36 18.495 ;
     RECT  2.16 18.765 153.36 19.035 ;
     RECT  2.16 19.305 153.36 19.575 ;
     RECT  2.16 19.845 153.36 20.115 ;
     RECT  2.16 20.385 153.36 20.655 ;
     RECT  2.16 20.925 153.36 21.195 ;
     RECT  2.16 21.465 153.36 21.735 ;
     RECT  2.16 22.005 153.36 22.275 ;
     RECT  2.16 22.545 153.36 22.815 ;
     RECT  2.16 23.085 153.36 23.355 ;
     RECT  2.16 23.625 153.36 23.895 ;
     RECT  2.16 24.165 153.36 24.435 ;
     RECT  2.16 24.705 153.36 24.975 ;
     RECT  2.16 25.245 153.36 25.515 ;
     RECT  2.16 25.785 153.36 26.055 ;
     RECT  2.16 26.325 153.36 26.595 ;
     RECT  2.16 26.865 153.36 27.135 ;
     RECT  2.16 27.405 153.36 27.675 ;
     RECT  2.16 27.945 153.36 28.215 ;
     RECT  2.16 28.485 153.36 28.755 ;
     RECT  2.16 29.025 153.36 29.295 ;
     RECT  2.16 29.565 153.36 29.835 ;
     RECT  2.16 30.105 153.36 30.375 ;
     RECT  2.16 30.645 153.36 30.915 ;
     RECT  2.16 31.185 153.36 31.455 ;
     RECT  2.16 31.725 153.36 31.995 ;
     RECT  2.16 32.265 153.36 32.535 ;
     RECT  2.16 32.805 153.36 33.075 ;
     RECT  2.16 33.345 153.36 33.615 ;
     RECT  2.16 33.885 153.36 34.155 ;
     RECT  2.16 34.425 153.36 34.695 ;
     RECT  2.16 34.965 153.36 35.235 ;
     RECT  2.16 35.505 153.36 35.775 ;
     RECT  2.16 36.045 153.36 36.315 ;
     RECT  2.16 36.585 153.36 36.855 ;
     RECT  2.16 37.125 153.36 37.395 ;
     RECT  2.16 37.665 153.36 37.935 ;
     RECT  2.16 38.205 153.36 38.475 ;
     RECT  2.16 38.745 153.36 39.015 ;
     RECT  2.16 39.285 153.36 39.555 ;
     RECT  2.16 39.825 153.36 40.095 ;
     RECT  2.16 40.365 153.36 40.635 ;
     RECT  2.16 40.905 153.36 41.175 ;
     RECT  2.16 41.445 153.36 41.715 ;
     RECT  2.16 41.985 153.36 42.255 ;
     RECT  2.16 42.525 153.36 42.795 ;
     RECT  2.16 43.065 153.36 43.335 ;
     RECT  2.16 43.605 153.36 43.875 ;
     RECT  2.16 44.145 153.36 44.415 ;
     RECT  2.16 44.685 153.36 44.955 ;
     RECT  2.16 45.225 153.36 45.495 ;
     RECT  2.16 45.765 153.36 46.035 ;
     RECT  2.16 46.305 153.36 46.575 ;
     RECT  2.16 46.845 153.36 47.115 ;
     RECT  2.16 47.385 153.36 47.655 ;
     RECT  2.16 47.925 153.36 48.195 ;
     RECT  2.16 48.465 153.36 48.735 ;
     RECT  2.16 49.005 153.36 49.275 ;
     RECT  2.16 49.545 153.36 49.815 ;
     RECT  2.16 50.085 153.36 50.355 ;
     RECT  2.16 50.625 153.36 50.895 ;
     RECT  2.16 51.165 153.36 51.435 ;
     RECT  2.16 51.705 153.36 51.975 ;
     RECT  2.16 52.245 153.36 52.515 ;
     RECT  2.16 52.785 153.36 53.055 ;
     RECT  2.16 53.325 153.36 53.595 ;
     RECT  2.16 53.865 153.36 54.135 ;
     RECT  2.16 54.405 153.36 54.675 ;
     RECT  2.16 54.945 153.36 55.215 ;
     RECT  2.16 55.485 153.36 55.755 ;
     RECT  2.16 56.025 153.36 56.295 ;
     RECT  2.16 56.565 153.36 56.835 ;
     RECT  2.16 57.105 153.36 57.375 ;
     RECT  2.16 57.645 153.36 57.915 ;
     RECT  2.16 58.185 153.36 58.455 ;
     RECT  2.16 58.725 153.36 58.995 ;
     RECT  2.16 59.265 153.36 59.535 ;
     RECT  2.16 59.805 153.36 60.075 ;
     RECT  2.16 60.345 153.36 60.615 ;
     RECT  2.16 60.885 153.36 61.155 ;
     RECT  2.16 61.425 153.36 61.695 ;
     RECT  2.16 61.965 153.36 62.235 ;
     RECT  2.16 62.505 153.36 62.775 ;
     RECT  2.16 63.045 153.36 63.315 ;
     RECT  2.16 63.585 153.36 63.855 ;
     RECT  2.16 64.125 153.36 64.395 ;
     RECT  2.16 64.665 153.36 64.935 ;
     RECT  2.16 65.205 153.36 65.475 ;
     RECT  2.16 65.745 153.36 66.015 ;
     RECT  2.16 66.285 153.36 66.555 ;
     RECT  2.16 66.825 153.36 67.095 ;
     RECT  2.16 67.365 153.36 67.635 ;
     RECT  2.16 67.905 153.36 68.175 ;
     RECT  2.16 68.445 153.36 68.715 ;
     RECT  2.16 68.985 153.36 69.255 ;
     RECT  2.16 69.525 153.36 69.795 ;
     RECT  2.16 70.065 153.36 70.335 ;
     RECT  2.16 70.605 153.36 70.875 ;
     RECT  2.16 71.145 153.36 71.415 ;
     RECT  2.16 71.685 153.36 71.955 ;
     RECT  2.16 72.225 153.36 72.495 ;
     RECT  2.16 72.765 153.36 73.035 ;
     RECT  2.16 73.305 153.36 73.575 ;
     RECT  2.16 73.845 153.36 74.115 ;
     RECT  2.16 74.385 153.36 74.655 ;
     RECT  2.16 74.925 153.36 75.195 ;
     RECT  2.16 75.465 153.36 75.735 ;
     RECT  2.16 76.005 153.36 76.275 ;
     RECT  2.16 76.545 153.36 76.815 ;
     RECT  2.16 77.085 153.36 77.355 ;
     RECT  2.16 77.625 153.36 77.895 ;
     RECT  2.16 78.165 153.36 78.435 ;
     RECT  2.16 78.705 153.36 78.975 ;
     RECT  2.16 79.245 153.36 79.515 ;
     RECT  2.16 79.785 153.36 80.055 ;
     RECT  2.16 80.325 153.36 80.595 ;
     RECT  2.16 80.865 153.36 81.135 ;
     RECT  2.16 81.405 153.36 81.675 ;
     RECT  2.16 81.945 153.36 82.215 ;
     RECT  2.16 82.485 153.36 82.755 ;
     RECT  2.16 83.025 153.36 83.295 ;
     RECT  2.16 83.565 153.36 83.835 ;
     RECT  2.16 84.105 153.36 84.375 ;
     RECT  2.16 84.645 153.36 84.915 ;
     RECT  2.16 85.185 153.36 85.455 ;
     RECT  2.16 85.725 153.36 85.995 ;
     RECT  2.16 86.265 153.36 86.535 ;
     RECT  2.16 86.805 153.36 87.075 ;
     RECT  2.16 87.345 153.36 87.615 ;
     RECT  2.16 87.885 153.36 88.155 ;
     RECT  2.16 88.425 153.36 88.695 ;
     RECT  2.16 88.965 153.36 89.235 ;
     RECT  2.16 89.505 153.36 89.775 ;
     RECT  2.16 90.045 153.36 90.315 ;
     RECT  2.16 90.585 153.36 90.855 ;
     RECT  2.16 91.125 153.36 91.395 ;
     RECT  2.16 91.665 153.36 91.935 ;
     RECT  2.16 92.205 153.36 92.475 ;
     RECT  2.16 92.745 153.36 93.015 ;
     RECT  2.16 93.285 153.36 93.555 ;
     RECT  2.16 93.825 153.36 94.095 ;
     RECT  2.16 94.365 153.36 94.635 ;
     RECT  2.16 94.905 153.36 95.175 ;
     RECT  2.16 95.445 153.36 95.715 ;
     RECT  2.16 95.985 153.36 96.255 ;
     RECT  2.16 96.525 153.36 96.795 ;
     RECT  2.16 97.065 153.36 97.335 ;
     RECT  2.16 97.605 153.36 97.875 ;
     RECT  2.16 98.145 153.36 98.415 ;
     RECT  2.16 98.685 153.36 98.955 ;
     RECT  2.16 99.225 153.36 99.495 ;
     RECT  2.16 99.765 153.36 100.035 ;
     RECT  2.16 100.305 153.36 100.575 ;
     RECT  2.16 100.845 153.36 101.115 ;
     RECT  2.16 101.385 153.36 101.655 ;
     RECT  2.16 101.925 153.36 102.195 ;
     RECT  2.16 102.465 153.36 102.735 ;
     RECT  2.16 103.005 153.36 103.275 ;
     RECT  2.16 103.545 153.36 103.815 ;
     RECT  2.16 104.085 153.36 104.355 ;
     RECT  2.16 104.625 153.36 104.895 ;
     RECT  2.16 105.165 153.36 105.435 ;
     RECT  2.16 105.705 153.36 105.975 ;
     RECT  2.16 106.245 153.36 106.515 ;
     RECT  2.16 106.785 153.36 107.055 ;
     RECT  2.16 107.325 153.36 107.595 ;
     RECT  2.16 107.865 153.36 108.135 ;
     RECT  2.16 108.405 153.36 108.675 ;
     RECT  2.16 108.945 153.36 109.215 ;
     RECT  2.16 109.485 153.36 109.755 ;
     RECT  2.16 110.025 153.36 110.295 ;
     RECT  2.16 110.565 153.36 110.835 ;
     RECT  2.16 111.105 153.36 111.375 ;
     RECT  2.16 111.645 153.36 111.915 ;
     RECT  2.16 112.185 153.36 112.455 ;
     RECT  2.16 112.725 153.36 112.995 ;
     RECT  2.16 113.265 153.36 113.535 ;
     RECT  2.16 113.805 153.36 114.075 ;
     RECT  2.16 114.345 153.36 114.615 ;
     RECT  2.16 114.885 153.36 115.155 ;
     RECT  2.16 115.425 153.36 115.695 ;
     RECT  2.16 115.965 153.36 116.235 ;
     RECT  2.16 116.505 153.36 116.775 ;
     RECT  2.16 117.045 153.36 117.315 ;
     RECT  2.16 117.585 153.36 117.855 ;
     RECT  2.16 118.125 153.36 118.395 ;
     RECT  2.16 118.665 153.36 118.935 ;
     RECT  2.16 119.205 153.36 119.475 ;
     RECT  2.16 119.745 153.36 120.015 ;
     RECT  2.16 120.285 153.36 120.555 ;
     RECT  2.16 120.825 153.36 121.095 ;
     RECT  2.16 121.365 153.36 121.635 ;
     RECT  2.16 121.905 153.36 122.175 ;
     RECT  2.16 122.445 153.36 122.715 ;
     RECT  2.16 122.985 153.36 123.255 ;
     RECT  2.16 123.525 153.36 123.795 ;
     RECT  2.16 124.065 153.36 124.335 ;
     RECT  2.16 124.605 153.36 124.875 ;
     RECT  2.16 125.145 153.36 125.415 ;
     RECT  2.16 125.685 153.36 125.955 ;
     RECT  2.16 126.225 153.36 126.495 ;
     RECT  2.16 126.765 153.36 127.035 ;
     RECT  2.16 127.305 153.36 127.575 ;
     RECT  2.16 127.845 153.36 128.115 ;
     RECT  2.16 128.385 153.36 128.655 ;
     RECT  2.16 128.925 153.36 129.195 ;
     RECT  2.16 129.465 153.36 129.735 ;
     RECT  2.16 130.005 153.36 130.275 ;
     RECT  2.16 130.545 153.36 130.815 ;
     RECT  2.16 131.085 153.36 131.355 ;
     RECT  2.16 131.625 153.36 131.895 ;
     RECT  2.16 132.165 153.36 132.435 ;
     RECT  2.16 132.705 153.36 132.975 ;
     RECT  2.16 133.245 153.36 133.515 ;
     RECT  2.16 133.785 153.36 134.055 ;
     RECT  2.16 134.325 153.36 134.595 ;
     RECT  2.16 134.865 153.36 135.135 ;
     RECT  2.16 135.405 153.36 135.675 ;
     RECT  2.16 135.945 153.36 136.215 ;
     RECT  2.16 136.485 153.36 136.755 ;
     RECT  2.16 137.025 153.36 137.295 ;
     RECT  2.16 137.565 153.36 137.835 ;
     RECT  2.16 138.105 153.36 138.375 ;
     RECT  2.16 138.645 153.36 138.915 ;
     RECT  2.16 139.185 153.36 139.455 ;
     RECT  2.16 139.725 153.36 139.995 ;
     RECT  2.16 140.265 153.36 140.535 ;
     RECT  2.16 140.805 153.36 141.075 ;
     RECT  2.16 141.345 153.36 141.615 ;
     RECT  2.16 141.885 153.36 142.155 ;
     RECT  2.16 142.425 153.36 142.695 ;
     RECT  2.16 142.965 153.36 143.235 ;
     RECT  2.16 143.505 153.36 143.775 ;
     RECT  2.16 144.045 153.36 144.315 ;
     RECT  2.16 144.585 153.36 144.855 ;
     RECT  2.16 145.125 153.36 145.395 ;
     RECT  2.16 145.665 153.36 145.935 ;
     RECT  2.16 146.205 153.36 146.475 ;
     RECT  2.16 146.745 153.36 147.015 ;
     RECT  2.16 147.285 153.36 147.555 ;
     RECT  2.16 147.825 153.36 148.095 ;
     RECT  2.16 148.365 153.36 148.635 ;
     RECT  2.16 148.905 153.36 149.175 ;
     RECT  2.16 149.445 153.36 149.715 ;
     RECT  2.16 149.985 153.36 150.255 ;
     RECT  2.16 150.525 153.36 150.795 ;
     RECT  2.16 151.065 153.36 151.335 ;
     RECT  2.16 151.605 153.36 151.875 ;
     RECT  2.16 152.145 153.36 152.415 ;
     RECT  2.16 152.685 153.36 152.955 ;
     RECT  2.16 153.225 153.36 153.495 ;
     RECT  2.16 153.765 153.36 154.035 ;
     RECT  2.16 154.305 153.36 154.575 ;
     RECT  2.16 154.845 153.36 155.115 ;
     RECT  2.16 155.385 153.36 155.655 ;
     RECT  2.16 155.925 153.36 156.195 ;
     RECT  2.16 156.465 153.36 156.735 ;
     RECT  2.16 157.005 153.36 157.275 ;
     RECT  2.16 157.545 153.36 157.815 ;
     RECT  2.16 158.085 153.36 158.355 ;
     RECT  2.16 158.625 153.36 158.895 ;
     RECT  2.16 159.165 153.36 159.435 ;
     RECT  2.16 159.705 153.36 159.975 ;
     RECT  2.16 160.245 153.36 160.515 ;
     RECT  2.16 160.785 153.36 161.055 ;
     RECT  2.16 161.325 153.36 161.595 ;
     RECT  2.16 161.865 153.36 162.135 ;
     RECT  2.16 162.405 153.36 162.675 ;
     RECT  2.16 162.945 153.36 163.215 ;
     RECT  2.16 163.485 153.36 163.755 ;
     RECT  2.16 164.025 153.36 164.295 ;
     RECT  2.16 164.565 153.36 164.835 ;
     RECT  2.16 165.105 153.36 165.375 ;
     RECT  2.16 165.645 153.36 165.915 ;
     RECT  2.16 166.185 153.36 166.455 ;
     RECT  2.16 166.725 153.36 166.995 ;
     RECT  2.16 167.265 153.36 167.535 ;
     RECT  2.16 167.805 153.36 168.075 ;
     RECT  2.16 168.345 153.36 168.615 ;
     RECT  2.16 168.885 153.36 169.155 ;
     RECT  2.16 169.425 153.36 169.695 ;
     RECT  2.16 169.965 153.36 170.235 ;
     RECT  2.16 170.505 153.36 170.775 ;
     RECT  2.16 171.045 153.36 171.315 ;
     RECT  2.16 171.585 153.36 171.855 ;
     RECT  2.16 172.125 153.36 172.395 ;
     RECT  2.16 172.665 153.36 172.935 ;
     RECT  2.16 173.205 153.36 173.475 ;
     RECT  2.16 173.745 153.36 174.015 ;
     RECT  2.16 174.285 153.36 174.555 ;
     RECT  2.16 174.825 153.36 175.095 ;
     RECT  2.16 175.365 153.36 175.635 ;
     RECT  2.16 175.905 153.36 176.175 ;
     RECT  2.16 176.445 153.36 176.715 ;
     RECT  2.16 176.985 153.36 177.255 ;
     RECT  2.16 177.525 153.36 177.795 ;
     RECT  2.16 178.065 153.36 178.335 ;
     RECT  2.16 178.605 153.36 178.875 ;
     RECT  2.16 179.145 153.36 179.415 ;
     RECT  2.16 179.685 153.36 179.955 ;
     RECT  2.16 180.225 153.36 180.495 ;
     RECT  2.16 180.765 153.36 181.035 ;
     RECT  2.16 181.305 153.36 181.575 ;
     RECT  2.16 181.845 153.36 182.115 ;
     RECT  2.16 182.385 153.36 182.655 ;
     RECT  2.16 182.925 153.36 183.195 ;
     RECT  2.16 183.465 153.36 183.735 ;
     RECT  2.16 184.005 153.36 184.275 ;
     RECT  2.16 184.545 153.36 184.815 ;
     RECT  2.16 185.085 153.36 185.355 ;
     RECT  2.16 185.625 153.36 185.895 ;
     RECT  2.16 186.165 153.36 186.435 ;
     RECT  2.16 186.705 153.36 186.975 ;
     RECT  2.16 187.245 153.36 187.515 ;
     RECT  2.16 187.785 153.36 188.055 ;
     RECT  2.16 188.325 153.36 188.595 ;
     RECT  2.16 188.865 153.36 189.135 ;
     RECT  2.16 189.405 153.36 189.675 ;
     RECT  2.16 189.945 153.36 190.215 ;
     RECT  2.16 190.485 153.36 190.755 ;
     RECT  2.16 191.025 153.36 191.295 ;
     RECT  2.16 191.565 153.36 191.835 ;
     RECT  2.16 192.105 153.36 192.375 ;
     RECT  2.16 192.645 153.36 192.915 ;
     RECT  2.16 193.185 153.36 193.455 ;
     RECT  2.16 193.725 153.36 193.995 ;
     RECT  2.16 194.265 153.36 194.535 ;
     RECT  2.16 194.805 153.36 195.075 ;
     RECT  2.16 195.345 153.36 195.615 ;
     RECT  2.16 195.885 153.36 196.155 ;
     RECT  2.16 196.425 153.36 196.695 ;
     RECT  2.16 196.965 153.36 197.235 ;
     RECT  2.16 197.505 153.36 197.775 ;
     RECT  2.16 198.045 153.36 198.315 ;
     RECT  2.16 198.585 153.36 198.855 ;
     RECT  2.16 199.125 153.36 199.395 ;
     RECT  2.16 199.665 153.36 199.935 ;
     RECT  2.16 200.205 153.36 200.475 ;
     RECT  2.16 200.745 153.36 201.015 ;
     RECT  2.16 201.285 153.36 201.555 ;
     RECT  2.16 201.825 153.36 202.095 ;
     RECT  2.16 202.365 153.36 202.635 ;
     RECT  2.16 202.905 153.36 203.175 ;
     RECT  2.16 203.445 153.36 203.715 ;
     RECT  2.16 203.985 153.36 204.255 ;
     RECT  2.16 204.525 153.36 204.795 ;
     RECT  2.16 205.065 153.36 205.335 ;
     RECT  2.16 205.605 153.36 205.875 ;
     RECT  2.16 206.145 153.36 206.415 ;
     RECT  2.16 206.685 153.36 206.955 ;
     RECT  2.16 207.225 153.36 207.495 ;
     RECT  2.16 207.765 153.36 208.035 ;
     RECT  2.16 208.305 153.36 208.575 ;
     RECT  2.16 208.845 153.36 209.115 ;
     RECT  2.16 209.385 153.36 209.655 ;
     RECT  2.16 209.925 153.36 210.195 ;
     RECT  2.16 210.465 153.36 210.735 ;
     RECT  2.16 211.005 153.36 211.275 ;
     RECT  2.16 211.545 153.36 211.815 ;
     RECT  2.16 212.085 153.36 212.355 ;
     RECT  2.16 212.625 153.36 212.895 ;
     RECT  2.16 213.165 153.36 213.435 ;
     RECT  2.16 213.705 153.36 213.975 ;
     RECT  2.16 214.245 153.36 214.515 ;
     RECT  2.16 214.785 153.36 215.055 ;
     RECT  2.16 215.325 153.36 215.595 ;
     RECT  2.16 215.865 153.36 216.135 ;
     RECT  2.16 216.405 153.36 216.675 ;
     RECT  2.16 216.945 153.36 217.215 ;
     RECT  2.16 217.485 153.36 217.755 ;
     RECT  2.16 218.025 153.36 218.295 ;
     RECT  2.16 218.565 153.36 218.835 ;
     RECT  2.16 219.105 153.36 219.375 ;
     RECT  2.16 219.645 153.36 219.915 ;
     RECT  2.16 220.185 153.36 220.455 ;
     RECT  2.16 220.725 153.36 220.995 ;
     RECT  2.16 221.265 153.36 221.535 ;
     RECT  2.16 221.805 153.36 222.075 ;
     RECT  2.16 222.345 153.36 222.615 ;
     RECT  2.16 222.885 153.36 223.155 ;
     RECT  2.16 223.425 153.36 223.695 ;
     RECT  2.16 223.965 153.36 224.235 ;
     RECT  2.16 224.505 153.36 224.775 ;
     RECT  2.16 225.045 153.36 225.315 ;
     RECT  2.16 225.585 153.36 225.855 ;
     RECT  2.16 226.125 153.36 226.395 ;
     RECT  2.16 226.665 153.36 226.935 ;
     RECT  2.16 227.205 153.36 227.475 ;
     RECT  2.16 227.745 153.36 228.015 ;
     RECT  2.16 228.285 153.36 228.555 ;
     RECT  2.16 228.825 153.36 229.095 ;
     RECT  2.16 229.365 153.36 229.635 ;
     RECT  2.16 229.905 153.36 230.175 ;
     RECT  2.16 230.445 153.36 230.715 ;
     RECT  2.16 230.985 153.36 231.255 ;
     RECT  2.16 231.525 153.36 231.795 ;
     RECT  2.16 232.065 153.36 232.335 ;
     RECT  2.16 232.605 153.36 232.875 ;
     RECT  2.16 233.145 153.36 233.415 ;
     RECT  2.16 233.685 153.36 233.955 ;
     RECT  2.16 234.225 153.36 234.495 ;
     RECT  2.16 234.765 153.36 235.035 ;
     RECT  2.16 235.305 153.36 235.575 ;
     RECT  2.16 235.845 153.36 236.115 ;
     RECT  2.16 236.385 153.36 236.655 ;
     RECT  2.16 236.925 153.36 237.195 ;
     RECT  2.16 237.465 153.36 237.735 ;
     RECT  2.16 238.005 153.36 238.275 ;
     RECT  2.16 238.545 153.36 238.815 ;
     RECT  2.16 239.085 153.36 239.355 ;
     RECT  2.16 239.625 153.36 239.895 ;
     RECT  2.16 240.165 153.36 240.435 ;
     RECT  2.16 240.705 153.36 240.975 ;
     RECT  2.16 241.245 153.36 241.515 ;
     RECT  2.16 241.785 153.36 242.055 ;
     RECT  2.16 242.325 153.36 242.595 ;
     RECT  2.16 242.865 153.36 243.135 ;
     RECT  2.16 243.405 153.36 243.675 ;
     RECT  2.16 243.945 153.36 244.08 ;
    LAYER RVTP ;
     RECT  2.16 2.295 153.36 2.565 ;
     RECT  2.16 2.835 153.36 3.105 ;
     RECT  2.16 3.375 153.36 3.645 ;
     RECT  2.16 3.915 153.36 4.185 ;
     RECT  2.16 4.455 153.36 4.725 ;
     RECT  2.16 4.995 153.36 5.265 ;
     RECT  2.16 5.535 153.36 5.805 ;
     RECT  2.16 6.075 153.36 6.345 ;
     RECT  2.16 6.615 153.36 6.885 ;
     RECT  2.16 7.155 153.36 7.425 ;
     RECT  2.16 7.695 153.36 7.965 ;
     RECT  2.16 8.235 153.36 8.505 ;
     RECT  2.16 8.775 153.36 9.045 ;
     RECT  2.16 9.315 153.36 9.585 ;
     RECT  2.16 9.855 153.36 10.125 ;
     RECT  2.16 10.395 153.36 10.665 ;
     RECT  2.16 10.935 153.36 11.205 ;
     RECT  2.16 11.475 153.36 11.745 ;
     RECT  2.16 12.015 153.36 12.285 ;
     RECT  2.16 12.555 153.36 12.825 ;
     RECT  2.16 13.095 153.36 13.365 ;
     RECT  2.16 13.635 153.36 13.905 ;
     RECT  2.16 14.175 153.36 14.445 ;
     RECT  2.16 14.715 153.36 14.985 ;
     RECT  2.16 15.255 153.36 15.525 ;
     RECT  2.16 15.795 153.36 16.065 ;
     RECT  2.16 16.335 153.36 16.605 ;
     RECT  2.16 16.875 153.36 17.145 ;
     RECT  2.16 17.415 153.36 17.685 ;
     RECT  2.16 17.955 153.36 18.225 ;
     RECT  2.16 18.495 153.36 18.765 ;
     RECT  2.16 19.035 153.36 19.305 ;
     RECT  2.16 19.575 153.36 19.845 ;
     RECT  2.16 20.115 153.36 20.385 ;
     RECT  2.16 20.655 153.36 20.925 ;
     RECT  2.16 21.195 153.36 21.465 ;
     RECT  2.16 21.735 153.36 22.005 ;
     RECT  2.16 22.275 153.36 22.545 ;
     RECT  2.16 22.815 153.36 23.085 ;
     RECT  2.16 23.355 153.36 23.625 ;
     RECT  2.16 23.895 153.36 24.165 ;
     RECT  2.16 24.435 153.36 24.705 ;
     RECT  2.16 24.975 153.36 25.245 ;
     RECT  2.16 25.515 153.36 25.785 ;
     RECT  2.16 26.055 153.36 26.325 ;
     RECT  2.16 26.595 153.36 26.865 ;
     RECT  2.16 27.135 153.36 27.405 ;
     RECT  2.16 27.675 153.36 27.945 ;
     RECT  2.16 28.215 153.36 28.485 ;
     RECT  2.16 28.755 153.36 29.025 ;
     RECT  2.16 29.295 153.36 29.565 ;
     RECT  2.16 29.835 153.36 30.105 ;
     RECT  2.16 30.375 153.36 30.645 ;
     RECT  2.16 30.915 153.36 31.185 ;
     RECT  2.16 31.455 153.36 31.725 ;
     RECT  2.16 31.995 153.36 32.265 ;
     RECT  2.16 32.535 153.36 32.805 ;
     RECT  2.16 33.075 153.36 33.345 ;
     RECT  2.16 33.615 153.36 33.885 ;
     RECT  2.16 34.155 153.36 34.425 ;
     RECT  2.16 34.695 153.36 34.965 ;
     RECT  2.16 35.235 153.36 35.505 ;
     RECT  2.16 35.775 153.36 36.045 ;
     RECT  2.16 36.315 153.36 36.585 ;
     RECT  2.16 36.855 153.36 37.125 ;
     RECT  2.16 37.395 153.36 37.665 ;
     RECT  2.16 37.935 153.36 38.205 ;
     RECT  2.16 38.475 153.36 38.745 ;
     RECT  2.16 39.015 153.36 39.285 ;
     RECT  2.16 39.555 153.36 39.825 ;
     RECT  2.16 40.095 153.36 40.365 ;
     RECT  2.16 40.635 153.36 40.905 ;
     RECT  2.16 41.175 153.36 41.445 ;
     RECT  2.16 41.715 153.36 41.985 ;
     RECT  2.16 42.255 153.36 42.525 ;
     RECT  2.16 42.795 153.36 43.065 ;
     RECT  2.16 43.335 153.36 43.605 ;
     RECT  2.16 43.875 153.36 44.145 ;
     RECT  2.16 44.415 153.36 44.685 ;
     RECT  2.16 44.955 153.36 45.225 ;
     RECT  2.16 45.495 153.36 45.765 ;
     RECT  2.16 46.035 153.36 46.305 ;
     RECT  2.16 46.575 153.36 46.845 ;
     RECT  2.16 47.115 153.36 47.385 ;
     RECT  2.16 47.655 153.36 47.925 ;
     RECT  2.16 48.195 153.36 48.465 ;
     RECT  2.16 48.735 153.36 49.005 ;
     RECT  2.16 49.275 153.36 49.545 ;
     RECT  2.16 49.815 153.36 50.085 ;
     RECT  2.16 50.355 153.36 50.625 ;
     RECT  2.16 50.895 153.36 51.165 ;
     RECT  2.16 51.435 153.36 51.705 ;
     RECT  2.16 51.975 153.36 52.245 ;
     RECT  2.16 52.515 153.36 52.785 ;
     RECT  2.16 53.055 153.36 53.325 ;
     RECT  2.16 53.595 153.36 53.865 ;
     RECT  2.16 54.135 153.36 54.405 ;
     RECT  2.16 54.675 153.36 54.945 ;
     RECT  2.16 55.215 153.36 55.485 ;
     RECT  2.16 55.755 153.36 56.025 ;
     RECT  2.16 56.295 153.36 56.565 ;
     RECT  2.16 56.835 153.36 57.105 ;
     RECT  2.16 57.375 153.36 57.645 ;
     RECT  2.16 57.915 153.36 58.185 ;
     RECT  2.16 58.455 153.36 58.725 ;
     RECT  2.16 58.995 153.36 59.265 ;
     RECT  2.16 59.535 153.36 59.805 ;
     RECT  2.16 60.075 153.36 60.345 ;
     RECT  2.16 60.615 153.36 60.885 ;
     RECT  2.16 61.155 153.36 61.425 ;
     RECT  2.16 61.695 153.36 61.965 ;
     RECT  2.16 62.235 153.36 62.505 ;
     RECT  2.16 62.775 153.36 63.045 ;
     RECT  2.16 63.315 153.36 63.585 ;
     RECT  2.16 63.855 153.36 64.125 ;
     RECT  2.16 64.395 153.36 64.665 ;
     RECT  2.16 64.935 153.36 65.205 ;
     RECT  2.16 65.475 153.36 65.745 ;
     RECT  2.16 66.015 153.36 66.285 ;
     RECT  2.16 66.555 153.36 66.825 ;
     RECT  2.16 67.095 153.36 67.365 ;
     RECT  2.16 67.635 153.36 67.905 ;
     RECT  2.16 68.175 153.36 68.445 ;
     RECT  2.16 68.715 153.36 68.985 ;
     RECT  2.16 69.255 153.36 69.525 ;
     RECT  2.16 69.795 153.36 70.065 ;
     RECT  2.16 70.335 153.36 70.605 ;
     RECT  2.16 70.875 153.36 71.145 ;
     RECT  2.16 71.415 153.36 71.685 ;
     RECT  2.16 71.955 153.36 72.225 ;
     RECT  2.16 72.495 153.36 72.765 ;
     RECT  2.16 73.035 153.36 73.305 ;
     RECT  2.16 73.575 153.36 73.845 ;
     RECT  2.16 74.115 153.36 74.385 ;
     RECT  2.16 74.655 153.36 74.925 ;
     RECT  2.16 75.195 153.36 75.465 ;
     RECT  2.16 75.735 153.36 76.005 ;
     RECT  2.16 76.275 153.36 76.545 ;
     RECT  2.16 76.815 153.36 77.085 ;
     RECT  2.16 77.355 153.36 77.625 ;
     RECT  2.16 77.895 153.36 78.165 ;
     RECT  2.16 78.435 153.36 78.705 ;
     RECT  2.16 78.975 153.36 79.245 ;
     RECT  2.16 79.515 153.36 79.785 ;
     RECT  2.16 80.055 153.36 80.325 ;
     RECT  2.16 80.595 153.36 80.865 ;
     RECT  2.16 81.135 153.36 81.405 ;
     RECT  2.16 81.675 153.36 81.945 ;
     RECT  2.16 82.215 153.36 82.485 ;
     RECT  2.16 82.755 153.36 83.025 ;
     RECT  2.16 83.295 153.36 83.565 ;
     RECT  2.16 83.835 153.36 84.105 ;
     RECT  2.16 84.375 153.36 84.645 ;
     RECT  2.16 84.915 153.36 85.185 ;
     RECT  2.16 85.455 153.36 85.725 ;
     RECT  2.16 85.995 153.36 86.265 ;
     RECT  2.16 86.535 153.36 86.805 ;
     RECT  2.16 87.075 153.36 87.345 ;
     RECT  2.16 87.615 153.36 87.885 ;
     RECT  2.16 88.155 153.36 88.425 ;
     RECT  2.16 88.695 153.36 88.965 ;
     RECT  2.16 89.235 153.36 89.505 ;
     RECT  2.16 89.775 153.36 90.045 ;
     RECT  2.16 90.315 153.36 90.585 ;
     RECT  2.16 90.855 153.36 91.125 ;
     RECT  2.16 91.395 153.36 91.665 ;
     RECT  2.16 91.935 153.36 92.205 ;
     RECT  2.16 92.475 153.36 92.745 ;
     RECT  2.16 93.015 153.36 93.285 ;
     RECT  2.16 93.555 153.36 93.825 ;
     RECT  2.16 94.095 153.36 94.365 ;
     RECT  2.16 94.635 153.36 94.905 ;
     RECT  2.16 95.175 153.36 95.445 ;
     RECT  2.16 95.715 153.36 95.985 ;
     RECT  2.16 96.255 153.36 96.525 ;
     RECT  2.16 96.795 153.36 97.065 ;
     RECT  2.16 97.335 153.36 97.605 ;
     RECT  2.16 97.875 153.36 98.145 ;
     RECT  2.16 98.415 153.36 98.685 ;
     RECT  2.16 98.955 153.36 99.225 ;
     RECT  2.16 99.495 153.36 99.765 ;
     RECT  2.16 100.035 153.36 100.305 ;
     RECT  2.16 100.575 153.36 100.845 ;
     RECT  2.16 101.115 153.36 101.385 ;
     RECT  2.16 101.655 153.36 101.925 ;
     RECT  2.16 102.195 153.36 102.465 ;
     RECT  2.16 102.735 153.36 103.005 ;
     RECT  2.16 103.275 153.36 103.545 ;
     RECT  2.16 103.815 153.36 104.085 ;
     RECT  2.16 104.355 153.36 104.625 ;
     RECT  2.16 104.895 153.36 105.165 ;
     RECT  2.16 105.435 153.36 105.705 ;
     RECT  2.16 105.975 153.36 106.245 ;
     RECT  2.16 106.515 153.36 106.785 ;
     RECT  2.16 107.055 153.36 107.325 ;
     RECT  2.16 107.595 153.36 107.865 ;
     RECT  2.16 108.135 153.36 108.405 ;
     RECT  2.16 108.675 153.36 108.945 ;
     RECT  2.16 109.215 153.36 109.485 ;
     RECT  2.16 109.755 153.36 110.025 ;
     RECT  2.16 110.295 153.36 110.565 ;
     RECT  2.16 110.835 153.36 111.105 ;
     RECT  2.16 111.375 153.36 111.645 ;
     RECT  2.16 111.915 153.36 112.185 ;
     RECT  2.16 112.455 153.36 112.725 ;
     RECT  2.16 112.995 153.36 113.265 ;
     RECT  2.16 113.535 153.36 113.805 ;
     RECT  2.16 114.075 153.36 114.345 ;
     RECT  2.16 114.615 153.36 114.885 ;
     RECT  2.16 115.155 153.36 115.425 ;
     RECT  2.16 115.695 153.36 115.965 ;
     RECT  2.16 116.235 153.36 116.505 ;
     RECT  2.16 116.775 153.36 117.045 ;
     RECT  2.16 117.315 153.36 117.585 ;
     RECT  2.16 117.855 153.36 118.125 ;
     RECT  2.16 118.395 153.36 118.665 ;
     RECT  2.16 118.935 153.36 119.205 ;
     RECT  2.16 119.475 153.36 119.745 ;
     RECT  2.16 120.015 153.36 120.285 ;
     RECT  2.16 120.555 153.36 120.825 ;
     RECT  2.16 121.095 153.36 121.365 ;
     RECT  2.16 121.635 153.36 121.905 ;
     RECT  2.16 122.175 153.36 122.445 ;
     RECT  2.16 122.715 153.36 122.985 ;
     RECT  2.16 123.255 153.36 123.525 ;
     RECT  2.16 123.795 153.36 124.065 ;
     RECT  2.16 124.335 153.36 124.605 ;
     RECT  2.16 124.875 153.36 125.145 ;
     RECT  2.16 125.415 153.36 125.685 ;
     RECT  2.16 125.955 153.36 126.225 ;
     RECT  2.16 126.495 153.36 126.765 ;
     RECT  2.16 127.035 153.36 127.305 ;
     RECT  2.16 127.575 153.36 127.845 ;
     RECT  2.16 128.115 153.36 128.385 ;
     RECT  2.16 128.655 153.36 128.925 ;
     RECT  2.16 129.195 153.36 129.465 ;
     RECT  2.16 129.735 153.36 130.005 ;
     RECT  2.16 130.275 153.36 130.545 ;
     RECT  2.16 130.815 153.36 131.085 ;
     RECT  2.16 131.355 153.36 131.625 ;
     RECT  2.16 131.895 153.36 132.165 ;
     RECT  2.16 132.435 153.36 132.705 ;
     RECT  2.16 132.975 153.36 133.245 ;
     RECT  2.16 133.515 153.36 133.785 ;
     RECT  2.16 134.055 153.36 134.325 ;
     RECT  2.16 134.595 153.36 134.865 ;
     RECT  2.16 135.135 153.36 135.405 ;
     RECT  2.16 135.675 153.36 135.945 ;
     RECT  2.16 136.215 153.36 136.485 ;
     RECT  2.16 136.755 153.36 137.025 ;
     RECT  2.16 137.295 153.36 137.565 ;
     RECT  2.16 137.835 153.36 138.105 ;
     RECT  2.16 138.375 153.36 138.645 ;
     RECT  2.16 138.915 153.36 139.185 ;
     RECT  2.16 139.455 153.36 139.725 ;
     RECT  2.16 139.995 153.36 140.265 ;
     RECT  2.16 140.535 153.36 140.805 ;
     RECT  2.16 141.075 153.36 141.345 ;
     RECT  2.16 141.615 153.36 141.885 ;
     RECT  2.16 142.155 153.36 142.425 ;
     RECT  2.16 142.695 153.36 142.965 ;
     RECT  2.16 143.235 153.36 143.505 ;
     RECT  2.16 143.775 153.36 144.045 ;
     RECT  2.16 144.315 153.36 144.585 ;
     RECT  2.16 144.855 153.36 145.125 ;
     RECT  2.16 145.395 153.36 145.665 ;
     RECT  2.16 145.935 153.36 146.205 ;
     RECT  2.16 146.475 153.36 146.745 ;
     RECT  2.16 147.015 153.36 147.285 ;
     RECT  2.16 147.555 153.36 147.825 ;
     RECT  2.16 148.095 153.36 148.365 ;
     RECT  2.16 148.635 153.36 148.905 ;
     RECT  2.16 149.175 153.36 149.445 ;
     RECT  2.16 149.715 153.36 149.985 ;
     RECT  2.16 150.255 153.36 150.525 ;
     RECT  2.16 150.795 153.36 151.065 ;
     RECT  2.16 151.335 153.36 151.605 ;
     RECT  2.16 151.875 153.36 152.145 ;
     RECT  2.16 152.415 153.36 152.685 ;
     RECT  2.16 152.955 153.36 153.225 ;
     RECT  2.16 153.495 153.36 153.765 ;
     RECT  2.16 154.035 153.36 154.305 ;
     RECT  2.16 154.575 153.36 154.845 ;
     RECT  2.16 155.115 153.36 155.385 ;
     RECT  2.16 155.655 153.36 155.925 ;
     RECT  2.16 156.195 153.36 156.465 ;
     RECT  2.16 156.735 153.36 157.005 ;
     RECT  2.16 157.275 153.36 157.545 ;
     RECT  2.16 157.815 153.36 158.085 ;
     RECT  2.16 158.355 153.36 158.625 ;
     RECT  2.16 158.895 153.36 159.165 ;
     RECT  2.16 159.435 153.36 159.705 ;
     RECT  2.16 159.975 153.36 160.245 ;
     RECT  2.16 160.515 153.36 160.785 ;
     RECT  2.16 161.055 153.36 161.325 ;
     RECT  2.16 161.595 153.36 161.865 ;
     RECT  2.16 162.135 153.36 162.405 ;
     RECT  2.16 162.675 153.36 162.945 ;
     RECT  2.16 163.215 153.36 163.485 ;
     RECT  2.16 163.755 153.36 164.025 ;
     RECT  2.16 164.295 153.36 164.565 ;
     RECT  2.16 164.835 153.36 165.105 ;
     RECT  2.16 165.375 153.36 165.645 ;
     RECT  2.16 165.915 153.36 166.185 ;
     RECT  2.16 166.455 153.36 166.725 ;
     RECT  2.16 166.995 153.36 167.265 ;
     RECT  2.16 167.535 153.36 167.805 ;
     RECT  2.16 168.075 153.36 168.345 ;
     RECT  2.16 168.615 153.36 168.885 ;
     RECT  2.16 169.155 153.36 169.425 ;
     RECT  2.16 169.695 153.36 169.965 ;
     RECT  2.16 170.235 153.36 170.505 ;
     RECT  2.16 170.775 153.36 171.045 ;
     RECT  2.16 171.315 153.36 171.585 ;
     RECT  2.16 171.855 153.36 172.125 ;
     RECT  2.16 172.395 153.36 172.665 ;
     RECT  2.16 172.935 153.36 173.205 ;
     RECT  2.16 173.475 153.36 173.745 ;
     RECT  2.16 174.015 153.36 174.285 ;
     RECT  2.16 174.555 153.36 174.825 ;
     RECT  2.16 175.095 153.36 175.365 ;
     RECT  2.16 175.635 153.36 175.905 ;
     RECT  2.16 176.175 153.36 176.445 ;
     RECT  2.16 176.715 153.36 176.985 ;
     RECT  2.16 177.255 153.36 177.525 ;
     RECT  2.16 177.795 153.36 178.065 ;
     RECT  2.16 178.335 153.36 178.605 ;
     RECT  2.16 178.875 153.36 179.145 ;
     RECT  2.16 179.415 153.36 179.685 ;
     RECT  2.16 179.955 153.36 180.225 ;
     RECT  2.16 180.495 153.36 180.765 ;
     RECT  2.16 181.035 153.36 181.305 ;
     RECT  2.16 181.575 153.36 181.845 ;
     RECT  2.16 182.115 153.36 182.385 ;
     RECT  2.16 182.655 153.36 182.925 ;
     RECT  2.16 183.195 153.36 183.465 ;
     RECT  2.16 183.735 153.36 184.005 ;
     RECT  2.16 184.275 153.36 184.545 ;
     RECT  2.16 184.815 153.36 185.085 ;
     RECT  2.16 185.355 153.36 185.625 ;
     RECT  2.16 185.895 153.36 186.165 ;
     RECT  2.16 186.435 153.36 186.705 ;
     RECT  2.16 186.975 153.36 187.245 ;
     RECT  2.16 187.515 153.36 187.785 ;
     RECT  2.16 188.055 153.36 188.325 ;
     RECT  2.16 188.595 153.36 188.865 ;
     RECT  2.16 189.135 153.36 189.405 ;
     RECT  2.16 189.675 153.36 189.945 ;
     RECT  2.16 190.215 153.36 190.485 ;
     RECT  2.16 190.755 153.36 191.025 ;
     RECT  2.16 191.295 153.36 191.565 ;
     RECT  2.16 191.835 153.36 192.105 ;
     RECT  2.16 192.375 153.36 192.645 ;
     RECT  2.16 192.915 153.36 193.185 ;
     RECT  2.16 193.455 153.36 193.725 ;
     RECT  2.16 193.995 153.36 194.265 ;
     RECT  2.16 194.535 153.36 194.805 ;
     RECT  2.16 195.075 153.36 195.345 ;
     RECT  2.16 195.615 153.36 195.885 ;
     RECT  2.16 196.155 153.36 196.425 ;
     RECT  2.16 196.695 153.36 196.965 ;
     RECT  2.16 197.235 153.36 197.505 ;
     RECT  2.16 197.775 153.36 198.045 ;
     RECT  2.16 198.315 153.36 198.585 ;
     RECT  2.16 198.855 153.36 199.125 ;
     RECT  2.16 199.395 153.36 199.665 ;
     RECT  2.16 199.935 153.36 200.205 ;
     RECT  2.16 200.475 153.36 200.745 ;
     RECT  2.16 201.015 153.36 201.285 ;
     RECT  2.16 201.555 153.36 201.825 ;
     RECT  2.16 202.095 153.36 202.365 ;
     RECT  2.16 202.635 153.36 202.905 ;
     RECT  2.16 203.175 153.36 203.445 ;
     RECT  2.16 203.715 153.36 203.985 ;
     RECT  2.16 204.255 153.36 204.525 ;
     RECT  2.16 204.795 153.36 205.065 ;
     RECT  2.16 205.335 153.36 205.605 ;
     RECT  2.16 205.875 153.36 206.145 ;
     RECT  2.16 206.415 153.36 206.685 ;
     RECT  2.16 206.955 153.36 207.225 ;
     RECT  2.16 207.495 153.36 207.765 ;
     RECT  2.16 208.035 153.36 208.305 ;
     RECT  2.16 208.575 153.36 208.845 ;
     RECT  2.16 209.115 153.36 209.385 ;
     RECT  2.16 209.655 153.36 209.925 ;
     RECT  2.16 210.195 153.36 210.465 ;
     RECT  2.16 210.735 153.36 211.005 ;
     RECT  2.16 211.275 153.36 211.545 ;
     RECT  2.16 211.815 153.36 212.085 ;
     RECT  2.16 212.355 153.36 212.625 ;
     RECT  2.16 212.895 153.36 213.165 ;
     RECT  2.16 213.435 153.36 213.705 ;
     RECT  2.16 213.975 153.36 214.245 ;
     RECT  2.16 214.515 153.36 214.785 ;
     RECT  2.16 215.055 153.36 215.325 ;
     RECT  2.16 215.595 153.36 215.865 ;
     RECT  2.16 216.135 153.36 216.405 ;
     RECT  2.16 216.675 153.36 216.945 ;
     RECT  2.16 217.215 153.36 217.485 ;
     RECT  2.16 217.755 153.36 218.025 ;
     RECT  2.16 218.295 153.36 218.565 ;
     RECT  2.16 218.835 153.36 219.105 ;
     RECT  2.16 219.375 153.36 219.645 ;
     RECT  2.16 219.915 153.36 220.185 ;
     RECT  2.16 220.455 153.36 220.725 ;
     RECT  2.16 220.995 153.36 221.265 ;
     RECT  2.16 221.535 153.36 221.805 ;
     RECT  2.16 222.075 153.36 222.345 ;
     RECT  2.16 222.615 153.36 222.885 ;
     RECT  2.16 223.155 153.36 223.425 ;
     RECT  2.16 223.695 153.36 223.965 ;
     RECT  2.16 224.235 153.36 224.505 ;
     RECT  2.16 224.775 153.36 225.045 ;
     RECT  2.16 225.315 153.36 225.585 ;
     RECT  2.16 225.855 153.36 226.125 ;
     RECT  2.16 226.395 153.36 226.665 ;
     RECT  2.16 226.935 153.36 227.205 ;
     RECT  2.16 227.475 153.36 227.745 ;
     RECT  2.16 228.015 153.36 228.285 ;
     RECT  2.16 228.555 153.36 228.825 ;
     RECT  2.16 229.095 153.36 229.365 ;
     RECT  2.16 229.635 153.36 229.905 ;
     RECT  2.16 230.175 153.36 230.445 ;
     RECT  2.16 230.715 153.36 230.985 ;
     RECT  2.16 231.255 153.36 231.525 ;
     RECT  2.16 231.795 153.36 232.065 ;
     RECT  2.16 232.335 153.36 232.605 ;
     RECT  2.16 232.875 153.36 233.145 ;
     RECT  2.16 233.415 153.36 233.685 ;
     RECT  2.16 233.955 153.36 234.225 ;
     RECT  2.16 234.495 153.36 234.765 ;
     RECT  2.16 235.035 153.36 235.305 ;
     RECT  2.16 235.575 153.36 235.845 ;
     RECT  2.16 236.115 153.36 236.385 ;
     RECT  2.16 236.655 153.36 236.925 ;
     RECT  2.16 237.195 153.36 237.465 ;
     RECT  2.16 237.735 153.36 238.005 ;
     RECT  2.16 238.275 153.36 238.545 ;
     RECT  2.16 238.815 153.36 239.085 ;
     RECT  2.16 239.355 153.36 239.625 ;
     RECT  2.16 239.895 153.36 240.165 ;
     RECT  2.16 240.435 153.36 240.705 ;
     RECT  2.16 240.975 153.36 241.245 ;
     RECT  2.16 241.515 153.36 241.785 ;
     RECT  2.16 242.055 153.36 242.325 ;
     RECT  2.16 242.595 153.36 242.865 ;
     RECT  2.16 243.135 153.36 243.405 ;
     RECT  2.16 243.675 153.36 243.945 ;
    LAYER M1 ;
     RECT  2.16 2.151 153.36 244.089 ;
    LAYER M2 ;
     RECT  0.103 88.902 0.283 88.92 ;
     RECT  0.103 126.468 0.355 126.486 ;
     RECT  0.103 170.982 0.391 171 ;
     RECT  0.103 85.464 0.463 85.482 ;
     RECT  0.355 126.468 0.463 126.558 ;
     RECT  0.355 130.131 0.463 130.149 ;
     RECT  0.391 170.586 0.463 171 ;
     RECT  0.355 172.908 0.463 172.926 ;
     RECT  0.463 130.05 0.491 130.149 ;
     RECT  0.463 172.836 0.491 172.926 ;
     RECT  0.391 117.126 0.499 117.144 ;
     RECT  0.463 63.981 0.535 63.999 ;
     RECT  0.491 130.05 0.535 130.068 ;
     RECT  0.491 172.836 0.535 172.854 ;
     RECT  0.463 197.901 0.535 197.919 ;
     RECT  0.463 62.712 0.563 62.73 ;
     RECT  0.535 63.828 0.563 63.999 ;
     RECT  0.463 126.468 0.563 126.639 ;
     RECT  0.535 129.942 0.563 130.068 ;
     RECT  0.463 170.514 0.563 171 ;
     RECT  0.535 172.674 0.563 172.854 ;
     RECT  0.463 186.408 0.563 187.119 ;
     RECT  0.463 194.391 0.563 194.409 ;
     RECT  0.535 197.712 0.563 197.919 ;
     RECT  0.319 100.818 0.823 100.836 ;
     RECT  0.103 145.872 0.823 145.89 ;
     RECT  0.823 145.134 1.003 145.89 ;
     RECT  0.499 91.17 1.039 91.188 ;
     RECT  0.103 140.742 1.075 140.76 ;
     RECT  0.103 109.998 1.111 110.016 ;
     RECT  0.103 222.282 1.111 222.84 ;
     RECT  1.003 77.436 1.147 77.454 ;
     RECT  1.075 80.946 1.147 80.964 ;
     RECT  0.823 100.818 1.147 101.142 ;
     RECT  0.895 173.988 1.147 174.006 ;
     RECT  1.147 77.094 1.175 77.454 ;
     RECT  1.147 80.946 1.175 81.162 ;
     RECT  1.147 173.988 1.175 174.114 ;
     RECT  0.535 119.52 1.471 119.538 ;
     RECT  0.859 137.268 1.507 137.286 ;
     RECT  1.039 90.936 1.543 91.188 ;
     RECT  0.427 92.106 1.543 92.124 ;
     RECT  0.931 148.302 1.543 148.32 ;
     RECT  1.471 119.52 1.579 119.844 ;
     RECT  1.175 77.094 1.615 77.112 ;
     RECT  1.075 135.882 1.615 135.9 ;
     RECT  0.895 142.236 1.615 142.254 ;
     RECT  0.103 181.782 1.615 181.8 ;
     RECT  0.283 88.902 1.651 89.532 ;
     RECT  0.499 117.126 1.651 117.882 ;
     RECT  0.563 186.912 1.687 186.93 ;
     RECT  1.543 103.014 2.011 103.032 ;
     RECT  1.039 111.582 2.011 111.672 ;
     RECT  0.499 112.536 2.011 112.554 ;
     RECT  1.003 209.466 2.047 209.484 ;
     RECT  1.651 88.236 2.083 89.532 ;
     RECT  2.011 111.006 2.083 111.708 ;
     RECT  1.111 109.458 2.119 110.016 ;
     RECT  0.563 172.674 2.119 172.692 ;
     RECT  1.175 174.096 2.119 174.114 ;
     RECT  1.175 81.144 2.155 81.162 ;
     RECT  2.011 102.546 2.155 103.032 ;
     RECT  1.651 117.126 2.155 118.116 ;
     RECT  0.103 135.072 2.155 135.09 ;
     RECT  1.543 148.302 2.155 148.392 ;
     RECT  0.103 17.658 2.16 17.676 ;
     RECT  0.103 22.788 2.16 22.806 ;
     RECT  0.535 26.1 2.16 26.118 ;
     RECT  0.499 44.424 2.16 44.442 ;
     RECT  1.687 55.8 2.16 55.818 ;
     RECT  0.103 58.662 2.16 58.68 ;
     RECT  0.563 63.828 2.16 63.846 ;
     RECT  1.615 76.554 2.16 77.112 ;
     RECT  2.155 80.64 2.16 81.162 ;
     RECT  0.895 83.646 2.16 83.664 ;
     RECT  0.463 85.464 2.16 85.824 ;
     RECT  2.083 88.236 2.16 89.766 ;
     RECT  1.543 90.936 2.16 92.124 ;
     RECT  1.471 96.03 2.16 96.048 ;
     RECT  1.147 100.818 2.16 101.412 ;
     RECT  2.155 102.546 2.16 103.374 ;
     RECT  0.103 104.868 2.16 104.886 ;
     RECT  2.119 108.756 2.16 110.016 ;
     RECT  2.083 110.916 2.16 111.708 ;
     RECT  2.011 112.536 2.16 112.914 ;
     RECT  0.355 116.316 2.16 116.334 ;
     RECT  2.155 117.126 2.16 118.764 ;
     RECT  1.579 119.52 2.16 120.078 ;
     RECT  0.563 126.468 2.16 126.594 ;
     RECT  0.563 129.942 2.16 129.96 ;
     RECT  0.859 132.948 2.16 132.966 ;
     RECT  2.155 134.496 2.16 135.09 ;
     RECT  1.615 135.882 2.16 136.044 ;
     RECT  1.507 137.07 2.16 137.286 ;
     RECT  1.075 140.58 2.16 140.76 ;
     RECT  1.615 141.66 2.16 142.254 ;
     RECT  1.003 144.9 2.16 145.89 ;
     RECT  2.155 148.176 2.16 148.392 ;
     RECT  1.147 149.922 2.16 149.94 ;
     RECT  1.975 152.226 2.16 152.244 ;
     RECT  2.119 162.144 2.16 162.162 ;
     RECT  1.507 163.296 2.16 163.314 ;
     RECT  0.967 164.916 2.16 164.934 ;
     RECT  0.103 167.472 2.16 167.49 ;
     RECT  0.859 168.426 2.16 168.444 ;
     RECT  0.563 170.586 2.16 171 ;
     RECT  2.119 172.206 2.16 172.692 ;
     RECT  2.119 174.096 2.16 174.582 ;
     RECT  0.103 176.112 2.16 176.13 ;
     RECT  0.427 177.336 2.16 177.354 ;
     RECT  1.579 178.416 2.16 178.434 ;
     RECT  2.047 180.576 2.16 180.594 ;
     RECT  1.615 181.386 2.16 181.8 ;
     RECT  0.463 183.546 2.16 183.564 ;
     RECT  1.039 185.328 2.16 185.346 ;
     RECT  1.687 186.516 2.16 186.93 ;
     RECT  1.651 192.726 2.16 192.744 ;
     RECT  0.563 197.712 2.16 197.73 ;
     RECT  2.155 204.066 2.16 204.084 ;
     RECT  0.463 208.584 2.16 208.602 ;
     RECT  2.047 209.466 2.16 209.88 ;
     RECT  0.103 212.022 2.16 212.04 ;
     RECT  0.499 214.596 2.16 214.614 ;
     RECT  0.103 217.152 2.16 217.17 ;
     RECT  0.535 219.654 2.16 219.672 ;
     RECT  1.111 222.282 2.16 223.524 ;
     RECT  0.103 227.988 2.16 228.006 ;
     RECT  1.075 229.41 2.16 229.428 ;
     RECT  0.103 238.752 2.16 238.77 ;
     RECT  2.16 2.151 153.36 244.089 ;
     RECT  153.36 113.166 153.527 115.884 ;
     RECT  153.36 116.676 153.599 137.484 ;
     RECT  153.599 124.236 153.887 137.484 ;
     RECT  153.36 154.476 153.887 155.034 ;
     RECT  153.36 91.98 153.923 94.59 ;
     RECT  153.36 142.596 153.923 145.854 ;
     RECT  153.887 154.818 154.139 155.034 ;
     RECT  153.36 105.336 154.427 108.864 ;
     RECT  153.527 113.166 154.427 114.264 ;
     RECT  153.36 148.806 154.427 152.064 ;
     RECT  153.923 91.98 154.463 92.43 ;
     RECT  153.923 93.726 154.463 94.59 ;
     RECT  153.36 95.346 154.463 96.624 ;
     RECT  153.36 97.506 154.463 100.764 ;
     RECT  153.36 101.556 154.463 104.544 ;
     RECT  154.427 105.336 154.463 105.354 ;
     RECT  154.427 106.146 154.463 108.864 ;
     RECT  153.36 110.196 154.463 112.374 ;
     RECT  154.427 113.436 154.463 114.264 ;
     RECT  153.527 115.056 154.463 115.884 ;
     RECT  153.599 116.676 154.463 123.48 ;
     RECT  153.887 124.236 154.463 125.064 ;
     RECT  153.887 125.928 154.463 137.484 ;
     RECT  153.36 138.276 154.463 139.518 ;
     RECT  153.36 140.436 154.463 141.804 ;
     RECT  153.923 142.596 154.463 145.044 ;
     RECT  153.923 145.836 154.463 145.854 ;
     RECT  153.36 146.646 154.463 148.014 ;
     RECT  154.427 148.806 154.463 151.254 ;
     RECT  154.427 152.046 154.463 152.064 ;
     RECT  153.36 152.856 154.463 153.414 ;
     RECT  154.139 155.016 154.463 155.034 ;
     RECT  154.463 99.738 154.499 99.756 ;
     RECT  154.463 108.756 154.499 108.774 ;
     RECT  154.463 117.396 154.499 117.414 ;
     RECT  154.463 125.928 154.499 125.946 ;
     RECT  154.463 129.366 154.499 129.96 ;
     RECT  154.463 147.6 154.499 147.618 ;
     RECT  154.463 149.796 154.499 149.814 ;
    LAYER M3 ;
     RECT  2.415 2.143 2.505 2.413 ;
     RECT  7.815 2.143 7.905 2.413 ;
     RECT  13.215 2.143 13.305 2.413 ;
     RECT  18.615 2.143 18.705 2.413 ;
     RECT  24.015 2.143 24.105 2.413 ;
     RECT  29.415 2.143 29.505 2.413 ;
     RECT  34.815 2.143 34.905 2.413 ;
     RECT  40.215 2.143 40.305 2.413 ;
     RECT  45.615 2.143 45.705 2.413 ;
     RECT  51.015 2.143 51.105 2.413 ;
     RECT  56.415 2.143 56.505 2.413 ;
     RECT  61.815 2.143 61.905 2.413 ;
     RECT  67.215 2.143 67.305 2.413 ;
     RECT  72.615 2.143 72.705 2.413 ;
     RECT  78.015 2.143 78.105 2.413 ;
     RECT  83.415 2.143 83.505 2.413 ;
     RECT  88.815 2.143 88.905 2.413 ;
     RECT  94.215 2.143 94.305 2.413 ;
     RECT  99.615 2.143 99.705 2.413 ;
     RECT  105.015 2.143 105.105 2.413 ;
     RECT  110.415 2.143 110.505 2.413 ;
     RECT  115.815 2.143 115.905 2.413 ;
     RECT  121.215 2.143 121.305 2.413 ;
     RECT  126.615 2.143 126.705 2.413 ;
     RECT  132.015 2.143 132.105 2.413 ;
     RECT  137.415 2.143 137.505 2.413 ;
     RECT  142.815 2.143 142.905 2.413 ;
     RECT  148.215 2.143 148.305 2.413 ;
     RECT  2.415 2.413 2.697 5.845 ;
     RECT  2.415 5.845 3.258 5.881 ;
     RECT  2.415 5.881 3.474 5.995 ;
     RECT  2.304 5.995 3.474 6.079 ;
     RECT  2.304 6.079 3.834 6.115 ;
     RECT  7.815 2.413 8.097 6.151 ;
     RECT  2.304 6.115 4.122 6.613 ;
     RECT  2.304 6.613 4.842 6.653 ;
     RECT  5.796 6.619 5.814 6.655 ;
     RECT  5.688 6.655 5.814 6.691 ;
     RECT  5.004 6.691 6.318 6.781 ;
     RECT  5.004 6.781 6.426 6.809 ;
     RECT  7.596 6.151 8.097 6.817 ;
     RECT  2.304 6.653 4.266 6.845 ;
     RECT  7.308 6.817 8.097 6.961 ;
     RECT  5.796 6.809 6.426 7.195 ;
     RECT  7.308 6.961 8.154 7.223 ;
     RECT  5.796 7.195 6.462 7.231 ;
     RECT  5.796 7.231 6.642 7.349 ;
     RECT  7.416 7.223 8.154 7.349 ;
     RECT  2.304 6.845 2.697 7.385 ;
     RECT  5.796 7.349 6.462 7.469 ;
     RECT  7.488 7.349 8.154 7.735 ;
     RECT  7.488 7.735 8.334 7.763 ;
     RECT  3.42 6.845 4.266 7.771 ;
     RECT  7.632 7.763 8.334 7.771 ;
     RECT  7.632 7.771 8.766 7.889 ;
     RECT  2.415 7.385 2.697 7.897 ;
     RECT  3.42 7.771 4.482 7.897 ;
     RECT  2.415 7.897 4.482 7.963 ;
     RECT  2.415 7.963 4.842 8.155 ;
     RECT  5.796 7.469 6.426 8.275 ;
     RECT  2.304 8.155 4.842 8.311 ;
     RECT  5.688 8.275 6.426 8.311 ;
     RECT  2.304 8.311 6.426 8.429 ;
     RECT  7.815 7.889 8.766 8.671 ;
     RECT  7.416 8.671 8.766 8.815 ;
     RECT  6.408 8.429 6.426 8.851 ;
     RECT  7.308 8.815 8.766 8.851 ;
     RECT  6.408 8.851 9.09 8.977 ;
     RECT  2.304 8.429 4.338 9.211 ;
     RECT  6.408 8.977 9.378 9.239 ;
     RECT  2.304 9.211 4.554 9.661 ;
     RECT  2.304 9.661 4.59 10.201 ;
     RECT  5.58 10.165 5.598 10.201 ;
     RECT  6.408 9.239 6.426 10.315 ;
     RECT  7.416 9.239 9.378 10.315 ;
     RECT  6.408 10.315 9.378 10.471 ;
     RECT  2.304 10.201 5.598 10.939 ;
     RECT  6.408 10.471 9.414 10.939 ;
     RECT  2.304 10.939 9.414 11.201 ;
     RECT  2.304 11.201 6.426 11.213 ;
     RECT  2.415 11.213 6.426 12.043 ;
     RECT  7.416 11.201 9.414 12.217 ;
     RECT  2.304 12.043 6.426 12.289 ;
     RECT  2.304 12.289 6.462 12.361 ;
     RECT  7.2 12.217 9.414 12.361 ;
     RECT  2.304 12.361 9.414 12.479 ;
     RECT  7.2 12.479 9.414 12.515 ;
     RECT  7.416 12.515 9.414 12.797 ;
     RECT  2.304 12.479 6.426 13.829 ;
     RECT  2.304 13.829 3.114 13.865 ;
     RECT  7.815 12.797 9.414 14.071 ;
     RECT  3.96 13.829 6.426 14.203 ;
     RECT  7.164 14.071 9.414 14.203 ;
     RECT  2.415 13.865 2.754 14.243 ;
     RECT  3.96 14.203 9.414 14.405 ;
     RECT  7.164 14.405 9.414 14.521 ;
     RECT  3.96 14.405 6.426 14.755 ;
     RECT  3.852 14.755 6.426 14.791 ;
     RECT  3.564 14.791 6.426 14.945 ;
     RECT  2.415 14.243 2.697 15.067 ;
     RECT  3.996 14.945 6.426 15.871 ;
     RECT  2.304 15.067 2.697 16.025 ;
     RECT  3.42 15.871 6.426 16.105 ;
     RECT  7.164 14.521 9.738 16.105 ;
     RECT  2.415 16.025 2.697 16.363 ;
     RECT  3.42 16.105 9.738 16.363 ;
     RECT  2.415 16.363 9.738 16.565 ;
     RECT  2.415 16.565 2.697 16.795 ;
     RECT  3.708 16.565 9.738 17.105 ;
     RECT  2.304 16.795 2.697 17.375 ;
     RECT  3.816 17.105 9.738 17.617 ;
     RECT  0.108 17.653 0.126 17.693 ;
     RECT  3.816 17.617 10.062 18.265 ;
     RECT  3.744 18.265 10.062 18.301 ;
     RECT  2.415 17.375 2.697 18.523 ;
     RECT  2.304 18.523 2.697 18.571 ;
     RECT  3.456 18.301 10.062 18.571 ;
     RECT  2.304 18.571 10.062 19.301 ;
     RECT  2.304 19.301 3.15 20.191 ;
     RECT  3.996 19.301 10.062 20.191 ;
     RECT  2.304 20.191 10.062 21.965 ;
     RECT  2.304 21.965 3.15 22.505 ;
     RECT  3.96 21.965 10.062 22.775 ;
     RECT  0.108 22.783 0.126 22.877 ;
     RECT  2.415 22.505 3.15 23.431 ;
     RECT  2.415 23.431 3.258 23.521 ;
     RECT  3.996 22.775 10.062 23.521 ;
     RECT  2.415 23.521 10.062 23.707 ;
     RECT  2.304 23.707 10.062 24.665 ;
     RECT  2.415 24.665 10.062 25.867 ;
     RECT  2.304 25.867 10.062 26.825 ;
     RECT  2.415 26.825 10.062 28.027 ;
     RECT  2.304 28.027 10.062 28.493 ;
     RECT  2.412 28.493 10.062 28.831 ;
     RECT  2.412 28.831 10.53 29.323 ;
     RECT  2.304 29.323 10.53 30.335 ;
     RECT  2.415 30.335 10.53 31.483 ;
     RECT  2.304 31.483 10.53 33.035 ;
     RECT  2.304 33.035 3.15 33.305 ;
     RECT  2.34 33.305 3.15 33.961 ;
     RECT  3.996 33.035 10.53 33.961 ;
     RECT  2.34 33.961 10.53 34.507 ;
     RECT  2.304 34.507 10.53 35.465 ;
     RECT  2.415 35.465 10.53 36.667 ;
     RECT  2.304 36.667 10.53 37.355 ;
     RECT  2.304 37.355 3.15 37.625 ;
     RECT  2.412 37.625 3.15 38.827 ;
     RECT  2.304 38.827 3.15 39.091 ;
     RECT  3.996 37.355 10.53 39.091 ;
     RECT  2.304 39.091 10.53 39.515 ;
     RECT  2.304 39.515 3.15 40.981 ;
     RECT  3.996 39.515 10.53 40.981 ;
     RECT  2.304 40.981 10.53 41.945 ;
     RECT  2.415 41.945 10.53 43.147 ;
     RECT  2.304 43.147 10.53 44.105 ;
     RECT  0.54 26.095 0.558 44.419 ;
     RECT  0.504 44.419 0.558 44.477 ;
     RECT  2.415 44.105 10.53 44.875 ;
     RECT  2.412 44.875 10.53 44.915 ;
     RECT  2.412 44.915 3.15 45.307 ;
     RECT  2.304 45.307 3.15 45.841 ;
     RECT  3.996 44.915 10.53 45.841 ;
     RECT  2.304 45.841 10.53 47.615 ;
     RECT  2.34 47.615 10.53 48.763 ;
     RECT  2.304 48.763 10.53 51.395 ;
     RECT  0.54 44.477 0.558 51.691 ;
     RECT  0.108 51.691 0.558 51.821 ;
     RECT  2.415 51.395 10.53 52.177 ;
     RECT  2.412 52.177 10.53 52.651 ;
     RECT  2.304 52.651 10.53 54.413 ;
     RECT  2.415 54.413 10.53 55.243 ;
     RECT  2.304 55.243 10.53 55.453 ;
     RECT  2.268 55.453 10.53 55.795 ;
     RECT  11.268 48.127 11.286 55.993 ;
     RECT  11.268 55.993 11.43 57.341 ;
     RECT  0.54 51.821 0.558 58.657 ;
     RECT  0.108 58.657 0.558 58.733 ;
     RECT  0.54 58.733 0.558 62.707 ;
     RECT  0.468 62.707 0.558 62.735 ;
     RECT  0.468 62.735 0.486 63.823 ;
     RECT  0.468 63.823 0.558 64.004 ;
     RECT  13.215 2.413 13.497 64.363 ;
     RECT  12.816 64.363 13.497 67.099 ;
     RECT  14.22 65.911 14.238 67.603 ;
     RECT  15.156 67.027 15.174 67.603 ;
     RECT  11.268 57.341 11.286 67.639 ;
     RECT  0.54 64.004 0.558 67.675 ;
     RECT  11.268 67.639 11.682 67.801 ;
     RECT  12.564 67.099 13.497 67.801 ;
     RECT  0.108 67.675 0.558 67.805 ;
     RECT  11.268 67.801 13.497 68.377 ;
     RECT  14.22 67.603 15.174 68.377 ;
     RECT  1.692 55.795 10.53 68.791 ;
     RECT  11.268 68.377 15.174 68.791 ;
     RECT  0.54 67.805 0.558 73.291 ;
     RECT  18.615 2.413 18.897 73.309 ;
     RECT  0.108 73.291 0.558 73.421 ;
     RECT  21.528 74.551 21.834 74.621 ;
     RECT  21.528 74.621 21.546 74.669 ;
     RECT  1.692 68.791 15.174 76.351 ;
     RECT  16.344 74.011 16.362 76.351 ;
     RECT  1.692 76.351 16.362 76.549 ;
     RECT  18.54 73.309 18.897 76.651 ;
     RECT  18.54 76.651 19.422 76.738 ;
     RECT  18.54 76.738 19.458 76.919 ;
     RECT  18.54 76.919 19.422 77.009 ;
     RECT  0.54 73.421 0.558 77.089 ;
     RECT  1.62 76.549 16.362 77.089 ;
     RECT  0.54 77.089 16.362 78.439 ;
     RECT  17.388 73.381 17.406 78.439 ;
     RECT  0.54 78.439 17.406 79.861 ;
     RECT  21.456 78.367 21.474 79.987 ;
     RECT  21.456 79.987 21.978 80.563 ;
     RECT  20.232 80.833 20.25 80.905 ;
     RECT  18.54 77.009 18.897 81.031 ;
     RECT  19.656 80.905 20.25 81.031 ;
     RECT  22.86 77.665 22.878 81.307 ;
     RECT  0.54 79.861 17.442 81.409 ;
     RECT  18.54 81.031 20.25 81.409 ;
     RECT  22.824 81.307 22.878 81.917 ;
     RECT  21.456 80.563 22.014 83.641 ;
     RECT  0.54 81.409 20.25 83.839 ;
     RECT  21.456 83.641 22.086 83.839 ;
     RECT  0.54 83.839 22.086 84.001 ;
     RECT  22.86 81.917 22.878 84.001 ;
     RECT  24.015 2.413 24.297 84.271 ;
     RECT  23.904 84.271 24.297 84.317 ;
     RECT  0.54 84.001 22.878 84.613 ;
     RECT  0.54 84.613 22.914 85.459 ;
     RECT  24.015 84.317 24.297 85.459 ;
     RECT  0.108 85.459 22.914 85.517 ;
     RECT  0.468 85.517 22.914 86.773 ;
     RECT  0.468 86.773 22.986 87.115 ;
     RECT  23.76 85.459 24.297 87.115 ;
     RECT  0.468 87.115 24.297 87.179 ;
     RECT  26.82 87.655 26.838 88.051 ;
     RECT  0.468 87.179 22.986 88.087 ;
     RECT  0.468 88.087 23.022 88.735 ;
     RECT  23.76 87.179 24.297 88.735 ;
     RECT  0.468 88.735 24.297 88.897 ;
     RECT  0.108 88.897 24.297 88.973 ;
     RECT  25.704 89.179 25.722 89.275 ;
     RECT  25.704 89.275 25.794 89.815 ;
     RECT  0.288 88.973 24.297 90.391 ;
     RECT  25.128 89.815 25.794 90.391 ;
     RECT  0.288 90.391 25.794 90.589 ;
     RECT  26.82 88.051 27.414 90.589 ;
     RECT  152.928 91.633 152.946 91.705 ;
     RECT  152.748 91.705 153.054 91.741 ;
     RECT  151.632 91.939 151.65 91.975 ;
     RECT  150.84 91.975 150.858 92.011 ;
     RECT  151.632 91.975 151.722 92.011 ;
     RECT  152.748 91.741 153.234 92.011 ;
     RECT  150.84 92.011 153.234 92.129 ;
     RECT  151.632 92.129 152.154 92.165 ;
     RECT  67.215 2.413 67.497 92.371 ;
     RECT  154.44 91.963 154.458 92.435 ;
     RECT  150.012 92.479 150.03 92.515 ;
     RECT  150.012 92.515 150.102 92.551 ;
     RECT  150.84 92.129 150.858 92.551 ;
     RECT  149.256 92.299 149.274 92.621 ;
     RECT  150.012 92.551 150.858 92.705 ;
     RECT  153 92.129 153.234 92.861 ;
     RECT  148.215 2.413 148.497 93.019 ;
     RECT  148.212 93.019 148.497 93.055 ;
     RECT  153 92.861 153.054 93.055 ;
     RECT  152.82 93.055 153.054 93.181 ;
     RECT  152.568 93.181 153.054 93.209 ;
     RECT  147.6 93.055 148.914 93.245 ;
     RECT  153.9 93.091 153.918 93.293 ;
     RECT  146.844 93.217 146.862 93.361 ;
     RECT  147.6 93.245 148.59 93.361 ;
     RECT  152.568 93.209 152.838 93.479 ;
     RECT  146.844 93.361 148.59 93.515 ;
     RECT  37.44 93.181 37.458 93.721 ;
     RECT  37.44 93.721 37.818 93.773 ;
     RECT  66.06 93.739 66.078 93.785 ;
     RECT  64.512 93.721 64.53 93.821 ;
     RECT  37.44 93.773 37.53 93.929 ;
     RECT  34.815 2.413 35.097 93.991 ;
     RECT  151.632 92.165 151.65 94.135 ;
     RECT  150.012 92.705 150.03 94.171 ;
     RECT  150.84 92.705 150.858 94.171 ;
     RECT  151.632 94.135 151.722 94.171 ;
     RECT  152.532 93.865 152.55 94.171 ;
     RECT  150.012 94.171 150.858 94.261 ;
     RECT  151.632 94.171 152.55 94.261 ;
     RECT  150.012 94.261 152.55 94.361 ;
     RECT  148.215 93.515 148.59 94.369 ;
     RECT  148.215 94.369 149.238 94.589 ;
     RECT  150.048 94.361 150.066 94.595 ;
     RECT  150.912 94.361 152.55 94.595 ;
     RECT  148.215 94.589 149.202 94.603 ;
     RECT  151.524 94.595 152.55 94.603 ;
     RECT  0.288 90.589 27.414 94.639 ;
     RECT  147.6 94.603 149.202 94.733 ;
     RECT  147.708 94.733 149.202 94.829 ;
     RECT  147.708 94.829 149.022 94.865 ;
     RECT  0.288 94.639 27.45 95.071 ;
     RECT  28.584 94.441 28.602 95.071 ;
     RECT  146.052 93.217 146.07 95.243 ;
     RECT  146.844 95.215 146.862 95.341 ;
     RECT  146.484 95.341 146.862 95.369 ;
     RECT  147.708 94.865 148.842 95.405 ;
     RECT  150.48 95.179 150.498 95.405 ;
     RECT  151.524 94.603 152.802 95.419 ;
     RECT  0.288 95.071 28.602 95.449 ;
     RECT  29.415 2.413 29.697 95.449 ;
     RECT  31.608 93.181 31.626 95.449 ;
     RECT  30.456 95.071 30.474 95.521 ;
     RECT  31.356 95.449 31.626 95.521 ;
     RECT  151.524 95.419 153.45 95.521 ;
     RECT  146.484 95.369 146.502 95.549 ;
     RECT  151.416 95.521 153.45 95.639 ;
     RECT  30.456 95.521 31.626 95.675 ;
     RECT  149.904 95.683 149.922 95.945 ;
     RECT  152.316 95.639 153.45 95.945 ;
     RECT  147.78 95.405 148.842 96.061 ;
     RECT  151.416 95.639 151.578 96.061 ;
     RECT  152.568 95.945 153.45 96.089 ;
     RECT  151.38 96.061 151.578 96.179 ;
     RECT  147.78 96.061 148.914 96.223 ;
     RECT  150.408 96.295 150.426 96.331 ;
     RECT  0.288 95.449 29.697 96.449 ;
     RECT  147.78 96.223 149.346 96.629 ;
     RECT  148.176 96.629 149.346 96.653 ;
     RECT  150.408 96.331 150.642 96.719 ;
     RECT  150.408 96.719 150.426 96.755 ;
     RECT  142.815 2.413 143.097 96.961 ;
     RECT  152.568 96.089 153.054 96.989 ;
     RECT  147.24 96.997 147.258 97.037 ;
     RECT  36.684 96.529 36.702 97.105 ;
     RECT  142.524 96.961 143.097 97.133 ;
     RECT  151.524 96.179 151.578 97.141 ;
     RECT  148.176 96.653 148.806 97.295 ;
     RECT  151.344 97.141 151.578 97.375 ;
     RECT  152.568 96.989 152.874 97.375 ;
     RECT  36.468 97.105 36.702 97.411 ;
     RECT  37.44 93.929 37.458 97.411 ;
     RECT  151.344 97.375 152.874 97.681 ;
     RECT  148.215 97.295 148.806 97.723 ;
     RECT  149.616 97.681 149.634 97.723 ;
     RECT  150.876 97.681 152.874 97.757 ;
     RECT  150.948 97.757 152.874 97.771 ;
     RECT  36.468 97.411 37.458 97.799 ;
     RECT  148.215 97.723 149.634 97.799 ;
     RECT  150.948 97.771 153.018 97.799 ;
     RECT  153 97.799 153.018 97.871 ;
     RECT  30.456 95.675 30.474 97.915 ;
     RECT  31.248 95.675 31.626 97.915 ;
     RECT  148.215 97.799 149.454 97.949 ;
     RECT  34.815 93.991 35.514 97.951 ;
     RECT  29.415 96.449 29.697 98.221 ;
     RECT  30.456 97.915 31.626 98.221 ;
     RECT  148.215 97.949 149.022 98.221 ;
     RECT  148.068 98.221 149.022 98.285 ;
     RECT  0.288 96.449 28.602 98.347 ;
     RECT  148.14 98.285 149.022 98.375 ;
     RECT  0.108 98.347 28.602 98.477 ;
     RECT  34.815 97.951 35.694 98.483 ;
     RECT  150.948 97.799 152.262 98.581 ;
     RECT  150.948 98.581 152.586 98.635 ;
     RECT  150.84 98.635 152.586 98.725 ;
     RECT  146.88 98.635 146.898 98.851 ;
     RECT  146.808 98.851 146.898 98.879 ;
     RECT  29.415 98.221 31.626 98.915 ;
     RECT  146.808 98.879 146.826 98.951 ;
     RECT  0.288 98.477 28.602 99.019 ;
     RECT  29.415 98.915 29.697 99.019 ;
     RECT  148.14 98.375 148.986 99.031 ;
     RECT  30.456 98.915 31.626 99.419 ;
     RECT  147.816 99.031 148.986 99.419 ;
     RECT  154.44 93.691 154.458 99.419 ;
     RECT  147.816 99.419 148.806 99.463 ;
     RECT  150.84 98.725 153.018 99.571 ;
     RECT  150.696 99.571 153.018 99.697 ;
     RECT  154.476 99.733 154.494 99.773 ;
     RECT  150.048 99.697 153.018 99.805 ;
     RECT  36.828 97.799 37.458 99.959 ;
     RECT  150.048 99.805 153.054 99.959 ;
     RECT  150.048 99.959 151.542 99.995 ;
     RECT  36.828 99.959 36.846 100.075 ;
     RECT  31.32 99.419 31.626 100.111 ;
     RECT  32.76 93.217 32.778 100.111 ;
     RECT  147.78 99.463 148.806 100.201 ;
     RECT  150.48 99.995 151.542 100.499 ;
     RECT  147.78 100.201 149.382 100.535 ;
     RECT  150.876 100.499 151.542 100.921 ;
     RECT  152.388 99.959 153.054 100.921 ;
     RECT  150.876 100.921 153.054 101.039 ;
     RECT  145.044 94.843 145.062 101.219 ;
     RECT  147.78 100.535 148.806 101.281 ;
     RECT  150.876 101.039 153.018 101.281 ;
     RECT  147.78 101.281 149.418 101.425 ;
     RECT  150.48 101.281 153.018 101.425 ;
     RECT  147.78 101.425 153.018 101.453 ;
     RECT  154.44 100.171 154.458 101.467 ;
     RECT  147.78 101.453 148.806 101.579 ;
     RECT  149.58 101.453 153.018 101.615 ;
     RECT  150.804 101.615 153.018 101.687 ;
     RECT  147.78 101.579 148.662 101.741 ;
     RECT  150.984 101.687 153.018 101.759 ;
     RECT  154.404 101.467 154.458 101.849 ;
     RECT  149.58 101.615 149.598 101.885 ;
     RECT  146.484 101.731 146.502 101.957 ;
     RECT  152.568 101.759 153.018 102.191 ;
     RECT  147.78 101.741 148.497 102.631 ;
     RECT  147.78 102.631 149.202 102.701 ;
     RECT  0.288 99.019 29.697 102.749 ;
     RECT  150.984 101.759 151.614 102.811 ;
     RECT  152.532 102.505 152.55 102.811 ;
     RECT  147.78 102.701 149.022 102.845 ;
     RECT  149.976 102.811 152.55 102.965 ;
     RECT  150.984 102.965 152.55 103.045 ;
     RECT  147.78 102.845 148.497 103.171 ;
     RECT  31.32 100.111 32.778 103.199 ;
     RECT  150.984 103.045 153.054 103.199 ;
     RECT  147.672 103.171 148.497 103.351 ;
     RECT  149.976 102.965 150.21 103.351 ;
     RECT  146.484 103.207 146.502 103.469 ;
     RECT  149.94 103.351 150.21 103.505 ;
     RECT  147.528 103.351 148.497 103.517 ;
     RECT  147.78 103.517 148.497 103.723 ;
     RECT  150.192 103.505 150.21 103.775 ;
     RECT  0.324 102.749 29.697 103.891 ;
     RECT  30.456 99.419 30.474 103.891 ;
     RECT  32.76 103.199 32.778 103.915 ;
     RECT  0.324 103.891 30.474 103.949 ;
     RECT  150.984 103.199 152.874 104.045 ;
     RECT  31.32 103.199 31.626 104.189 ;
     RECT  110.415 2.413 110.697 104.245 ;
     RECT  88.815 2.413 89.097 104.251 ;
     RECT  99.615 2.413 99.897 104.251 ;
     RECT  121.215 2.413 121.497 104.251 ;
     RECT  132.015 2.413 132.297 104.251 ;
     RECT  142.815 97.133 143.097 104.251 ;
     RECT  147.78 103.723 148.77 104.251 ;
     RECT  150.984 104.045 152.802 104.251 ;
     RECT  150.444 104.251 152.802 104.279 ;
     RECT  110.304 104.245 110.697 104.285 ;
     RECT  88.704 104.251 89.097 104.288 ;
     RECT  99.504 104.251 99.897 104.288 ;
     RECT  121.104 104.251 121.497 104.288 ;
     RECT  131.904 104.251 132.297 104.288 ;
     RECT  142.704 104.251 143.097 104.288 ;
     RECT  150.444 104.279 152.262 104.315 ;
     RECT  39.348 104.011 39.366 104.585 ;
     RECT  40.215 2.413 40.497 104.701 ;
     RECT  0.324 103.949 29.697 104.863 ;
     RECT  147.78 104.251 149.202 104.875 ;
     RECT  147.636 104.875 149.202 104.909 ;
     RECT  0.108 104.863 29.697 104.957 ;
     RECT  31.32 104.189 31.338 104.999 ;
     RECT  146.16 104.971 146.178 105.061 ;
     RECT  150.84 104.315 152.262 105.061 ;
     RECT  146.016 105.061 146.178 105.089 ;
     RECT  146.016 105.089 146.034 105.101 ;
     RECT  147.636 104.909 149.058 105.101 ;
     RECT  150.84 105.061 152.586 105.125 ;
     RECT  0.324 104.957 29.697 105.161 ;
     RECT  148.215 105.101 149.058 105.269 ;
     RECT  154.44 101.849 154.458 105.355 ;
     RECT  148.215 105.269 148.986 105.395 ;
     RECT  150.876 105.125 152.586 105.601 ;
     RECT  154.404 105.355 154.458 105.629 ;
     RECT  34.815 98.483 35.514 105.871 ;
     RECT  45.615 2.413 45.897 105.871 ;
     RECT  51.015 2.413 51.297 105.871 ;
     RECT  56.415 2.413 56.697 105.871 ;
     RECT  67.215 92.371 68.13 105.871 ;
     RECT  78.015 2.413 78.297 105.871 ;
     RECT  34.704 105.871 35.514 105.917 ;
     RECT  45.504 105.871 45.897 105.917 ;
     RECT  56.304 105.871 56.697 105.917 ;
     RECT  67.104 105.871 68.13 105.917 ;
     RECT  77.904 105.871 78.297 105.917 ;
     RECT  51.015 105.871 51.57 105.965 ;
     RECT  82.656 105.883 82.674 106.013 ;
     RECT  52.668 105.979 52.686 106.016 ;
     RECT  150.876 105.601 152.874 106.051 ;
     RECT  150.876 106.051 153.018 106.205 ;
     RECT  0.324 105.161 27.45 106.219 ;
     RECT  0.108 106.219 27.45 106.285 ;
     RECT  28.26 105.161 29.697 106.285 ;
     RECT  59.04 92.245 59.058 106.313 ;
     RECT  41.544 105.133 41.562 106.321 ;
     RECT  0.108 106.285 29.697 106.349 ;
     RECT  148.215 105.395 148.497 106.363 ;
     RECT  150.876 106.205 152.622 106.397 ;
     RECT  85.464 106.363 85.482 106.439 ;
     RECT  85.068 106.507 85.086 106.547 ;
     RECT  150.048 106.363 150.066 106.555 ;
     RECT  151.164 106.397 152.622 106.583 ;
     RECT  148.215 106.363 148.842 106.619 ;
     RECT  34.815 105.917 35.514 106.709 ;
     RECT  36.756 100.075 36.846 106.709 ;
     RECT  151.164 106.583 152.586 106.745 ;
     RECT  32.76 103.915 33.354 106.825 ;
     RECT  149.904 106.555 150.066 106.861 ;
     RECT  30.456 103.949 30.474 106.979 ;
     RECT  149.58 106.861 150.066 107.015 ;
     RECT  64.944 106.795 64.962 107.285 ;
     RECT  146.772 107.221 146.79 107.329 ;
     RECT  152.568 106.745 152.586 107.365 ;
     RECT  146.484 107.329 146.79 107.401 ;
     RECT  148.215 106.619 148.662 107.401 ;
     RECT  149.652 107.015 150.066 107.519 ;
     RECT  151.164 106.745 151.758 107.549 ;
     RECT  147.708 107.401 148.662 107.555 ;
     RECT  150.048 107.519 150.066 107.555 ;
     RECT  146.484 107.401 146.934 107.627 ;
     RECT  41.544 106.321 41.886 107.635 ;
     RECT  151.56 107.549 151.758 107.635 ;
     RECT  152.568 107.365 153.018 107.635 ;
     RECT  146.52 107.627 146.934 107.699 ;
     RECT  67.215 105.917 68.13 107.789 ;
     RECT  30.888 107.761 30.906 107.861 ;
     RECT  146.916 107.699 146.934 107.861 ;
     RECT  151.56 107.635 153.018 107.861 ;
     RECT  148.068 107.555 148.662 107.995 ;
     RECT  30.636 107.905 30.798 108.059 ;
     RECT  30.78 108.059 30.798 108.167 ;
     RECT  0.324 106.349 29.697 108.211 ;
     RECT  32.76 106.825 33.894 108.235 ;
     RECT  148.068 107.995 148.842 108.317 ;
     RECT  150.3 108.211 150.534 108.329 ;
     RECT  148.068 108.317 148.77 108.365 ;
     RECT  150.3 108.329 150.318 108.365 ;
     RECT  151.56 107.861 152.946 108.365 ;
     RECT  36.756 106.709 36.774 108.571 ;
     RECT  41.544 107.635 42.282 108.599 ;
     RECT  151.56 108.365 152.154 108.599 ;
     RECT  152.928 108.365 152.946 108.599 ;
     RECT  32.184 108.235 33.894 108.715 ;
     RECT  154.44 105.629 154.458 108.751 ;
     RECT  154.44 108.751 154.494 108.869 ;
     RECT  0.324 108.211 30.006 108.977 ;
     RECT  154.476 108.869 154.494 109.277 ;
     RECT  30.852 108.877 30.87 109.291 ;
     RECT  31.608 108.715 33.894 109.291 ;
     RECT  142.815 104.288 143.097 109.291 ;
     RECT  148.068 108.365 148.497 109.291 ;
     RECT  146.448 109.285 146.466 109.325 ;
     RECT  151.596 108.599 152.154 109.381 ;
     RECT  153.036 108.715 153.054 109.381 ;
     RECT  150.84 109.291 150.858 109.387 ;
     RECT  142.524 109.291 143.097 109.409 ;
     RECT  149.688 108.481 149.706 109.409 ;
     RECT  147.384 109.291 148.497 109.445 ;
     RECT  150.696 109.387 150.858 109.445 ;
     RECT  148.068 109.445 148.497 109.561 ;
     RECT  30.852 109.291 33.894 109.679 ;
     RECT  148.068 109.561 148.986 109.679 ;
     RECT  30.852 109.679 30.87 109.795 ;
     RECT  151.596 109.381 153.054 109.831 ;
     RECT  148.068 109.679 148.806 109.853 ;
     RECT  151.164 109.831 153.054 109.949 ;
     RECT  151.596 109.949 153.054 109.985 ;
     RECT  0.324 108.977 29.697 109.993 ;
     RECT  152.352 109.985 153.054 110.107 ;
     RECT  0.108 109.993 29.697 110.141 ;
     RECT  30.42 109.795 30.87 110.219 ;
     RECT  152.352 110.107 153.63 110.291 ;
     RECT  30.492 110.219 30.87 110.327 ;
     RECT  149.76 109.831 149.778 110.371 ;
     RECT  152.496 110.291 153.63 110.399 ;
     RECT  148.068 109.853 148.626 110.429 ;
     RECT  154.44 109.675 154.458 110.461 ;
     RECT  149.544 110.371 149.958 110.489 ;
     RECT  149.544 110.489 149.562 110.525 ;
     RECT  153.9 110.461 154.458 110.573 ;
     RECT  31.608 109.679 33.894 110.641 ;
     RECT  34.815 106.709 35.097 110.641 ;
     RECT  45.615 105.917 45.897 110.731 ;
     RECT  146.16 110.641 146.178 110.731 ;
     RECT  30.852 110.327 30.87 110.759 ;
     RECT  46.764 110.641 46.782 110.759 ;
     RECT  146.016 110.731 146.502 110.768 ;
     RECT  45.432 110.731 45.897 110.795 ;
     RECT  31.608 110.641 35.097 110.839 ;
     RECT  148.068 110.429 148.497 110.875 ;
     RECT  151.596 109.985 151.614 110.911 ;
     RECT  147.348 110.875 148.497 111.065 ;
     RECT  146.484 110.768 146.502 111.181 ;
     RECT  150.948 110.911 151.614 111.181 ;
     RECT  152.496 110.399 153.018 111.181 ;
     RECT  150.732 111.181 153.018 111.259 ;
     RECT  150.588 111.259 153.018 111.271 ;
     RECT  36.18 108.571 36.774 111.307 ;
     RECT  31.356 110.839 35.097 111.335 ;
     RECT  36.18 111.307 36.918 111.371 ;
     RECT  146.484 111.181 146.574 111.371 ;
     RECT  0.324 110.141 29.697 111.403 ;
     RECT  148.068 111.065 148.497 111.451 ;
     RECT  150.192 111.271 153.018 111.451 ;
     RECT  0.324 111.403 29.79 111.581 ;
     RECT  148.068 111.451 149.058 111.64 ;
     RECT  149.976 111.451 153.018 111.64 ;
     RECT  146.484 111.371 146.502 111.677 ;
     RECT  148.068 111.64 153.018 111.677 ;
     RECT  149.976 111.677 153.018 111.685 ;
     RECT  148.068 111.677 149.202 111.725 ;
     RECT  149.976 111.685 153.054 111.839 ;
     RECT  149.976 111.839 152.442 111.875 ;
     RECT  31.608 111.335 35.097 111.947 ;
     RECT  0.324 111.581 29.697 111.965 ;
     RECT  36.18 111.371 36.774 112.157 ;
     RECT  35.82 112.261 35.838 112.379 ;
     RECT  148.068 111.725 148.986 112.495 ;
     RECT  147.924 112.495 148.986 112.531 ;
     RECT  147.924 112.531 149.058 112.649 ;
     RECT  150.3 111.875 152.442 112.801 ;
     RECT  146.484 112.621 146.502 112.829 ;
     RECT  150.3 112.801 152.586 113.071 ;
     RECT  154.44 110.573 154.458 113.131 ;
     RECT  80.172 112.843 80.19 113.161 ;
     RECT  80.172 113.161 80.478 113.189 ;
     RECT  154.404 113.131 154.458 113.189 ;
     RECT  80.46 113.189 80.478 113.213 ;
     RECT  148.068 112.649 149.058 113.575 ;
     RECT  147.564 113.575 149.058 113.611 ;
     RECT  150.3 113.071 152.874 113.611 ;
     RECT  147.564 113.611 152.874 113.729 ;
     RECT  147.564 113.729 149.238 113.765 ;
     RECT  150.48 113.729 152.874 113.801 ;
     RECT  150.696 113.801 152.874 113.845 ;
     RECT  147.564 113.765 148.986 113.971 ;
     RECT  146.916 113.971 148.986 113.999 ;
     RECT  38.556 107.797 38.574 114.079 ;
     RECT  0.36 111.965 29.697 114.151 ;
     RECT  0.36 114.151 30.222 114.269 ;
     RECT  146.916 113.999 147.078 114.269 ;
     RECT  38.268 114.079 38.574 114.305 ;
     RECT  146.916 114.269 146.934 114.305 ;
     RECT  150.696 113.845 153.018 114.305 ;
     RECT  31.608 111.947 31.626 114.313 ;
     RECT  38.556 114.305 38.574 114.421 ;
     RECT  147.852 113.999 148.986 114.575 ;
     RECT  31.608 114.313 32.022 114.691 ;
     RECT  32.76 111.947 35.097 114.691 ;
     RECT  148.068 114.575 148.986 114.809 ;
     RECT  150.948 114.305 153.018 114.859 ;
     RECT  87.408 104.539 87.426 114.961 ;
     RECT  150.948 114.859 153.522 114.989 ;
     RECT  0.36 114.269 29.697 115.079 ;
     RECT  86.652 114.961 86.67 115.079 ;
     RECT  87.408 114.961 87.75 115.079 ;
     RECT  87.408 115.079 87.426 115.115 ;
     RECT  149.76 114.961 149.778 115.115 ;
     RECT  150.948 114.989 153.018 115.115 ;
     RECT  148.068 114.809 148.554 115.133 ;
     RECT  38.556 114.421 38.61 115.147 ;
     RECT  0.36 115.079 28.206 115.229 ;
     RECT  149.652 115.231 149.67 115.385 ;
     RECT  51.015 105.965 51.297 115.591 ;
     RECT  147.312 115.087 147.33 115.591 ;
     RECT  36.756 112.157 36.774 115.619 ;
     RECT  52.56 115.147 52.578 115.619 ;
     RECT  54.396 91.051 54.414 115.619 ;
     RECT  31.608 114.691 35.097 115.627 ;
     RECT  38.52 115.147 38.61 115.663 ;
     RECT  31.608 115.627 35.298 115.664 ;
     RECT  146.052 115.627 146.07 115.664 ;
     RECT  150.948 115.115 152.262 115.691 ;
     RECT  50.94 115.591 51.297 115.709 ;
     RECT  31.608 115.664 35.19 115.889 ;
     RECT  147.06 115.591 147.33 115.925 ;
     RECT  147.312 115.925 147.33 115.969 ;
     RECT  148.068 115.133 148.497 115.969 ;
     RECT  31.608 115.889 33.354 116.033 ;
     RECT  153 115.115 153.018 116.041 ;
     RECT  150.948 115.691 151.83 116.167 ;
     RECT  0.36 115.229 26.298 116.339 ;
     RECT  150.804 116.167 151.83 116.429 ;
     RECT  150.804 116.429 151.758 116.465 ;
     RECT  152.568 116.041 153.018 116.465 ;
     RECT  149.328 116.509 149.346 116.581 ;
     RECT  152.856 116.465 153.018 116.581 ;
     RECT  154.44 113.189 154.458 116.587 ;
     RECT  150.804 116.465 151.542 116.671 ;
     RECT  147.312 115.969 148.497 116.683 ;
     RECT  149.328 116.581 149.958 116.683 ;
     RECT  147.312 116.683 149.958 116.735 ;
     RECT  152.856 116.581 153.054 116.735 ;
     RECT  41.544 108.599 41.886 116.969 ;
     RECT  154.404 116.587 154.458 116.969 ;
     RECT  149.904 116.735 149.958 117.005 ;
     RECT  150.732 116.671 151.542 117.005 ;
     RECT  61.815 2.413 62.097 117.019 ;
     RECT  0.432 116.339 26.298 117.121 ;
     RECT  30.78 117.019 30.798 117.149 ;
     RECT  31.608 116.033 32.778 117.149 ;
     RECT  42.768 117.019 42.786 117.149 ;
     RECT  54.72 117.019 54.738 117.149 ;
     RECT  61.815 117.019 62.73 117.149 ;
     RECT  74.664 117.019 74.682 117.149 ;
     RECT  86.652 117.019 86.67 117.149 ;
     RECT  98.604 117.019 98.622 117.149 ;
     RECT  106.596 117.019 106.614 117.149 ;
     RECT  118.584 117.019 118.602 117.149 ;
     RECT  130.536 117.019 130.554 117.149 ;
     RECT  138.528 117.019 138.546 117.149 ;
     RECT  27.36 115.229 28.206 117.239 ;
     RECT  147.312 116.735 148.734 117.239 ;
     RECT  41.652 116.969 41.886 117.275 ;
     RECT  146.484 117.115 146.502 117.293 ;
     RECT  152.856 116.735 152.874 117.355 ;
     RECT  150.804 117.005 151.542 117.391 ;
     RECT  152.784 117.355 152.874 117.391 ;
     RECT  154.44 116.969 154.458 117.391 ;
     RECT  154.44 117.391 154.494 117.485 ;
     RECT  149.904 117.005 149.922 117.545 ;
     RECT  150.804 117.391 152.874 117.625 ;
     RECT  40.215 104.701 40.554 117.661 ;
     RECT  150.804 117.625 153.054 117.779 ;
     RECT  150.804 117.779 153.018 118.201 ;
     RECT  27.36 117.239 28.026 118.229 ;
     RECT  51.015 115.709 51.297 118.291 ;
     RECT  150.66 118.201 153.018 118.319 ;
     RECT  150.66 118.319 152.406 118.355 ;
     RECT  147.312 117.239 148.497 118.555 ;
     RECT  147.312 118.555 148.734 118.603 ;
     RECT  39.492 117.661 40.554 118.697 ;
     RECT  0.396 117.121 26.298 118.843 ;
     RECT  27.36 118.229 27.378 118.843 ;
     RECT  150.66 118.355 152.37 118.867 ;
     RECT  150.48 118.867 152.37 119.011 ;
     RECT  147.312 118.603 148.878 119.039 ;
     RECT  50.4 118.291 51.297 119.101 ;
     RECT  149.94 119.011 152.37 119.101 ;
     RECT  50.4 119.101 52.002 119.129 ;
     RECT  148.068 119.039 148.878 119.129 ;
     RECT  149.94 119.101 152.874 119.129 ;
     RECT  148.068 119.129 148.662 119.399 ;
     RECT  148.068 119.399 148.554 119.435 ;
     RECT  31.608 117.149 32.274 119.467 ;
     RECT  0.396 118.843 27.378 119.501 ;
     RECT  31.032 119.467 32.274 119.543 ;
     RECT  34.236 115.889 35.19 119.551 ;
     RECT  0.396 119.501 26.298 119.579 ;
     RECT  31.032 119.543 31.05 119.579 ;
     RECT  40.215 118.697 40.554 119.579 ;
     RECT  150.48 119.129 152.874 119.641 ;
     RECT  32.148 119.543 32.274 119.693 ;
     RECT  34.236 119.551 35.91 119.849 ;
     RECT  149.4 119.707 149.562 119.939 ;
     RECT  0.396 119.579 25.686 119.947 ;
     RECT  51.015 119.129 52.002 119.975 ;
     RECT  147.312 119.039 147.33 120.091 ;
     RECT  148.068 119.435 148.497 120.091 ;
     RECT  38.412 115.663 38.61 120.119 ;
     RECT  150.48 119.641 152.91 120.209 ;
     RECT  150.48 120.209 152.01 120.217 ;
     RECT  150.3 120.217 152.01 120.245 ;
     RECT  147.312 120.091 148.497 120.269 ;
     RECT  149.4 119.939 149.418 120.269 ;
     RECT  152.784 120.209 152.91 120.325 ;
     RECT  152.784 120.325 153.054 120.479 ;
     RECT  150.3 120.245 151.938 120.515 ;
     RECT  148.068 120.269 148.497 120.523 ;
     RECT  34.815 119.849 35.91 120.551 ;
     RECT  0.108 119.947 25.686 120.605 ;
     RECT  152.784 120.479 152.982 121.019 ;
     RECT  152.964 121.019 152.982 121.055 ;
     RECT  148.068 120.523 148.554 121.171 ;
     RECT  150.516 120.515 151.938 121.171 ;
     RECT  31.356 121.261 31.374 121.288 ;
     RECT  32.256 119.693 32.274 121.288 ;
     RECT  146.484 120.901 146.502 121.289 ;
     RECT  150.516 121.171 152.082 121.289 ;
     RECT  31.356 121.288 32.274 121.325 ;
     RECT  57.636 121.288 57.654 121.325 ;
     RECT  148.068 121.171 149.238 121.325 ;
     RECT  147.312 120.269 147.33 121.435 ;
     RECT  34.815 120.551 35.19 121.531 ;
     RECT  153.036 121.405 153.054 121.559 ;
     RECT  31.356 121.325 31.374 121.595 ;
     RECT  34.704 121.531 35.19 121.703 ;
     RECT  34.704 121.703 35.097 121.711 ;
     RECT  147.24 121.435 147.33 121.853 ;
     RECT  151.596 121.289 152.082 121.945 ;
     RECT  150.516 121.289 150.822 121.963 ;
     RECT  34.632 121.711 35.097 122.009 ;
     RECT  150.336 121.963 150.822 122.099 ;
     RECT  151.596 121.945 152.118 122.215 ;
     RECT  150.804 122.099 150.822 122.251 ;
     RECT  151.596 122.215 152.514 122.251 ;
     RECT  41.868 117.275 41.886 122.279 ;
     RECT  150.804 122.251 152.514 122.369 ;
     RECT  38.412 120.119 38.43 122.377 ;
     RECT  147.312 121.853 147.33 122.377 ;
     RECT  148.068 121.325 148.986 122.377 ;
     RECT  38.196 122.377 38.43 122.405 ;
     RECT  150.804 122.369 151.614 122.405 ;
     RECT  38.196 122.405 38.214 122.477 ;
     RECT  147.312 122.377 148.986 122.521 ;
     RECT  27.36 119.501 27.378 122.611 ;
     RECT  27.36 122.611 27.45 122.639 ;
     RECT  147.312 122.521 149.67 122.639 ;
     RECT  147.312 122.639 149.526 122.675 ;
     RECT  152.46 122.369 152.514 122.755 ;
     RECT  152.46 122.755 152.586 122.791 ;
     RECT  152.46 122.791 152.802 123.025 ;
     RECT  152.46 123.025 153.054 123.067 ;
     RECT  52.236 120.055 52.254 123.179 ;
     RECT  150.804 122.405 150.822 123.187 ;
     RECT  150.624 123.187 150.822 123.331 ;
     RECT  151.596 122.405 151.614 123.331 ;
     RECT  152.46 123.067 153.594 123.331 ;
     RECT  37.44 121.675 37.458 123.485 ;
     RECT  150.624 123.331 153.594 123.557 ;
     RECT  147.312 122.675 148.986 123.835 ;
     RECT  32.256 121.325 32.274 123.863 ;
     RECT  150.624 123.557 153.054 123.989 ;
     RECT  43.488 123.979 43.506 124.025 ;
     RECT  27.432 122.639 27.45 124.123 ;
     RECT  147.312 123.835 149.526 124.123 ;
     RECT  150.624 123.989 152.802 124.123 ;
     RECT  43.812 124.141 43.83 124.253 ;
     RECT  147.312 124.123 152.802 124.253 ;
     RECT  33.084 123.871 33.102 124.295 ;
     RECT  150.084 124.253 152.802 124.295 ;
     RECT  77.184 124.501 77.202 124.555 ;
     RECT  76.968 124.555 77.202 124.601 ;
     RECT  76.86 124.645 76.878 124.685 ;
     RECT  146.52 124.363 146.538 124.795 ;
     RECT  146.376 124.795 146.538 124.799 ;
     RECT  146.376 124.799 146.394 124.835 ;
     RECT  0.396 120.605 25.686 124.879 ;
     RECT  151.596 124.295 152.802 124.951 ;
     RECT  150.084 124.295 150.498 125.041 ;
     RECT  154.44 117.485 154.458 125.069 ;
     RECT  150.048 125.041 150.498 125.185 ;
     RECT  151.596 124.951 152.946 125.185 ;
     RECT  149.868 125.185 150.498 125.221 ;
     RECT  151.596 125.185 153.018 125.221 ;
     RECT  153.864 125.221 153.918 125.261 ;
     RECT  149.868 125.221 153.018 125.339 ;
     RECT  152.496 125.339 153.018 125.375 ;
     RECT  27.36 124.123 27.45 125.491 ;
     RECT  147.312 124.253 148.986 125.761 ;
     RECT  149.868 125.339 151.614 125.761 ;
     RECT  153.9 125.261 153.918 125.923 ;
     RECT  152.568 125.375 153.018 125.995 ;
     RECT  153.9 125.923 154.494 126.125 ;
     RECT  152.568 125.995 153.054 126.149 ;
     RECT  0.396 124.879 25.758 126.221 ;
     RECT  153.9 126.125 154.458 126.221 ;
     RECT  147.312 125.761 151.614 126.229 ;
     RECT  28.476 126.031 28.494 126.265 ;
     RECT  147.312 126.229 151.65 126.265 ;
     RECT  152.568 126.149 153.018 126.265 ;
     RECT  28.476 126.265 28.53 126.329 ;
     RECT  147.312 126.265 153.018 126.419 ;
     RECT  0.396 126.221 25.254 126.463 ;
     RECT  27.36 125.491 27.558 126.535 ;
     RECT  0.108 126.463 25.254 126.557 ;
     RECT  147.312 126.419 150.75 126.557 ;
     RECT  155.412 126.523 155.43 126.653 ;
     RECT  147.312 126.557 149.958 126.689 ;
     RECT  149.724 126.689 149.742 126.869 ;
     RECT  151.524 126.419 153.018 126.959 ;
     RECT  36 126.229 36.018 126.995 ;
     RECT  150.732 126.557 150.75 126.995 ;
     RECT  151.524 126.959 152.586 126.995 ;
     RECT  151.524 126.995 152.442 127.229 ;
     RECT  28.512 126.329 28.53 127.265 ;
     RECT  36.252 127.111 36.27 127.499 ;
     RECT  151.524 127.229 152.19 127.499 ;
     RECT  147.312 126.689 148.497 127.627 ;
     RECT  151.524 127.499 151.902 127.651 ;
     RECT  147.312 127.627 148.626 127.679 ;
     RECT  142.815 109.409 143.097 127.741 ;
     RECT  33.876 124.411 33.894 127.769 ;
     RECT  151.128 127.651 151.902 127.769 ;
     RECT  146.16 127.675 146.178 127.805 ;
     RECT  150.3 127.651 150.318 127.805 ;
     RECT  142.524 127.741 143.097 127.913 ;
     RECT  147.312 127.679 148.497 127.921 ;
     RECT  147.096 127.921 148.497 128.075 ;
     RECT  151.524 127.769 151.902 128.219 ;
     RECT  27.36 126.535 27.63 128.281 ;
     RECT  43.524 125.221 43.542 128.579 ;
     RECT  153 128.011 153.018 128.579 ;
     RECT  150.48 128.011 150.498 128.587 ;
     RECT  151.524 128.219 151.65 128.731 ;
     RECT  151.488 128.731 151.65 129.001 ;
     RECT  152.892 128.965 152.946 129.001 ;
     RECT  29.415 115.079 29.697 129.091 ;
     RECT  149.976 128.587 150.498 129.091 ;
     RECT  147.312 128.075 148.497 129.115 ;
     RECT  26.496 125.179 26.514 129.119 ;
     RECT  154.44 126.221 154.458 129.149 ;
     RECT  149.868 129.091 150.498 129.235 ;
     RECT  151.488 129.001 152.946 129.235 ;
     RECT  149.868 129.235 152.946 129.389 ;
     RECT  149.868 129.389 151.578 129.425 ;
     RECT  152.316 129.389 152.946 129.425 ;
     RECT  152.568 129.425 152.946 129.505 ;
     RECT  27.36 128.281 27.918 129.703 ;
     RECT  147.312 129.115 148.986 129.811 ;
     RECT  149.868 129.425 149.994 129.811 ;
     RECT  147.312 129.811 149.994 129.965 ;
     RECT  154.476 129.361 154.494 130.013 ;
     RECT  0.36 126.557 25.254 130.154 ;
     RECT  26.208 129.397 26.226 130.199 ;
     RECT  0.396 130.154 25.254 130.219 ;
     RECT  152.568 129.505 153.018 130.315 ;
     RECT  149.904 129.965 149.994 130.351 ;
     RECT  151.02 129.425 151.542 130.351 ;
     RECT  152.568 130.315 153.054 130.351 ;
     RECT  26.316 130.351 26.334 130.459 ;
     RECT  27.36 129.703 28.206 130.459 ;
     RECT  149.904 130.351 150.066 130.469 ;
     RECT  151.02 130.351 153.054 130.469 ;
     RECT  149.976 130.469 150.066 130.577 ;
     RECT  151.02 130.469 153.018 130.739 ;
     RECT  29.415 129.091 30.294 130.775 ;
     RECT  151.02 130.739 152.154 130.775 ;
     RECT  147.312 129.965 148.878 130.891 ;
     RECT  34.815 122.009 35.097 130.987 ;
     RECT  38.412 130.981 38.43 131.021 ;
     RECT  147.312 130.891 148.914 131.045 ;
     RECT  34.776 130.987 35.097 131.117 ;
     RECT  37.044 131.053 37.062 131.117 ;
     RECT  146.484 131.083 146.502 131.131 ;
     RECT  147.312 131.045 148.878 131.131 ;
     RECT  150.048 130.577 150.066 131.275 ;
     RECT  26.316 130.459 28.206 131.279 ;
     RECT  146.484 131.131 148.878 131.279 ;
     RECT  146.484 131.279 146.502 131.315 ;
     RECT  142.815 127.913 143.097 131.323 ;
     RECT  52.164 131.251 52.182 131.351 ;
     RECT  150.048 131.275 150.282 131.431 ;
     RECT  151.524 130.775 152.154 131.521 ;
     RECT  153 130.739 153.018 131.521 ;
     RECT  142.524 131.323 143.097 131.549 ;
     RECT  149.652 131.431 150.282 131.549 ;
     RECT  26.316 131.279 27.378 131.585 ;
     RECT  151.524 131.521 153.018 131.621 ;
     RECT  149.652 131.549 150.102 131.657 ;
     RECT  151.524 131.621 152.154 131.701 ;
     RECT  151.164 131.701 152.154 131.855 ;
     RECT  153 131.621 153.018 132.089 ;
     RECT  147.312 131.279 148.878 132.235 ;
     RECT  149.652 131.657 150.066 132.235 ;
     RECT  147.312 132.235 150.066 132.511 ;
     RECT  147.312 132.511 150.606 132.629 ;
     RECT  147.312 132.629 150.318 132.665 ;
     RECT  147.312 132.665 150.102 132.871 ;
     RECT  151.524 131.855 152.154 133.169 ;
     RECT  147.276 132.871 150.102 133.205 ;
     RECT  29.415 130.775 29.697 133.321 ;
     RECT  30.528 130.891 30.546 133.321 ;
     RECT  149.616 133.205 150.102 133.439 ;
     RECT  28.188 131.279 28.206 133.591 ;
     RECT  150.048 133.439 150.102 133.591 ;
     RECT  151.524 133.169 151.542 133.591 ;
     RECT  153 133.015 153.018 133.591 ;
     RECT  150.048 133.591 150.606 133.709 ;
     RECT  28.188 133.591 28.242 133.745 ;
     RECT  152.316 133.591 153.018 133.745 ;
     RECT  147.276 133.205 148.878 133.951 ;
     RECT  151.38 133.591 151.542 134.131 ;
     RECT  153 133.745 153.018 134.365 ;
     RECT  151.38 134.131 152.154 134.401 ;
     RECT  146.484 134.329 146.502 134.429 ;
     RECT  32.472 132.781 32.49 134.491 ;
     RECT  151.272 134.401 152.154 134.491 ;
     RECT  153 134.365 153.054 134.491 ;
     RECT  147.276 133.951 148.914 134.519 ;
     RECT  151.272 134.491 153.054 134.519 ;
     RECT  32.472 134.491 32.742 134.555 ;
     RECT  150.048 133.709 150.282 134.555 ;
     RECT  150.048 134.555 150.102 134.671 ;
     RECT  33.804 134.329 33.822 134.789 ;
     RECT  149.868 134.671 150.102 134.789 ;
     RECT  149.868 134.789 150.066 134.825 ;
     RECT  0.396 130.219 25.362 135.067 ;
     RECT  33.552 134.905 33.57 135.101 ;
     RECT  0.108 135.067 25.362 135.197 ;
     RECT  32.724 134.555 32.742 135.329 ;
     RECT  151.524 134.519 151.542 135.445 ;
     RECT  152.388 134.519 152.982 135.445 ;
     RECT  150.84 135.445 151.542 135.481 ;
     RECT  152.388 135.445 153.018 135.481 ;
     RECT  150.84 135.481 153.018 135.599 ;
     RECT  150.84 135.599 151.83 135.635 ;
     RECT  150.048 134.825 150.066 135.835 ;
     RECT  147.276 134.519 148.878 135.985 ;
     RECT  149.832 135.835 150.066 135.985 ;
     RECT  147.276 135.985 150.066 136.021 ;
     RECT  150.84 135.635 151.794 136.021 ;
     RECT  152.568 135.599 152.946 136.139 ;
     RECT  147.276 136.021 151.794 136.175 ;
     RECT  147.276 136.175 149.13 136.211 ;
     RECT  150.048 136.175 151.794 136.517 ;
     RECT  150.876 136.517 151.794 136.561 ;
     RECT  152.568 136.139 152.874 136.561 ;
     RECT  54.036 136.795 54.054 136.949 ;
     RECT  150.876 136.561 152.874 136.949 ;
     RECT  150.912 136.949 152.874 137.065 ;
     RECT  55.584 137.101 55.602 137.357 ;
     RECT  150.048 136.517 150.066 137.371 ;
     RECT  149.904 137.371 150.066 137.489 ;
     RECT  33.084 137.461 33.102 137.501 ;
     RECT  150.912 137.065 153.018 137.795 ;
     RECT  149.904 137.489 149.922 137.939 ;
     RECT  33.552 137.641 33.57 138.065 ;
     RECT  151.236 137.795 153.018 138.065 ;
     RECT  72.615 2.413 72.897 138.181 ;
     RECT  154.44 130.351 154.458 138.187 ;
     RECT  72.615 138.181 73.314 138.509 ;
     RECT  154.404 138.187 154.458 138.569 ;
     RECT  151.524 138.065 153.018 138.605 ;
     RECT  151.524 138.605 152.946 138.811 ;
     RECT  151.02 138.811 152.946 138.875 ;
     RECT  149.76 139.261 150.498 139.379 ;
     RECT  151.524 138.875 152.946 139.415 ;
     RECT  26.46 131.585 27.378 139.487 ;
     RECT  152.568 139.415 152.946 139.495 ;
     RECT  146.484 139.531 146.502 139.649 ;
     RECT  149.76 139.379 149.814 139.801 ;
     RECT  147.276 136.211 148.878 140.071 ;
     RECT  149.652 139.801 149.814 140.071 ;
     RECT  0.396 135.197 25.362 140.225 ;
     RECT  147.276 140.071 149.814 140.225 ;
     RECT  152.568 139.495 153.018 140.305 ;
     RECT  152.424 140.305 153.018 140.341 ;
     RECT  154.44 138.569 154.458 140.347 ;
     RECT  147.276 140.225 149.166 140.459 ;
     RECT  152.352 140.341 153.018 140.495 ;
     RECT  149.976 140.575 149.994 140.611 ;
     RECT  151.524 139.415 151.542 140.611 ;
     RECT  152.352 140.495 152.73 140.611 ;
     RECT  154.404 140.347 154.458 140.729 ;
     RECT  0.396 140.225 21.654 140.737 ;
     RECT  150.948 140.611 152.73 140.765 ;
     RECT  151.272 140.765 152.73 140.801 ;
     RECT  0.108 140.737 21.654 140.813 ;
     RECT  0.396 140.813 21.654 141.107 ;
     RECT  28.188 133.745 28.206 141.179 ;
     RECT  151.272 140.801 152.082 141.269 ;
     RECT  147.276 140.459 149.094 141.421 ;
     RECT  149.976 140.611 150.102 141.421 ;
     RECT  147.276 141.421 150.102 141.499 ;
     RECT  151.524 141.269 152.082 141.539 ;
     RECT  0.396 141.107 21.186 141.647 ;
     RECT  153 141.241 153.018 141.781 ;
     RECT  147.276 141.499 150.642 141.809 ;
     RECT  147.276 141.809 149.346 141.845 ;
     RECT  152.568 141.781 153.018 141.925 ;
     RECT  152.568 141.925 153.054 142.079 ;
     RECT  150.552 141.809 150.642 142.231 ;
     RECT  22.716 140.225 25.362 142.259 ;
     RECT  151.524 141.539 151.83 142.465 ;
     RECT  152.568 142.079 152.874 142.465 ;
     RECT  151.524 142.465 152.874 142.501 ;
     RECT  154.44 140.729 154.458 142.507 ;
     RECT  147.276 141.845 149.094 142.603 ;
     RECT  151.488 142.501 152.874 142.619 ;
     RECT  147.276 142.603 149.526 142.655 ;
     RECT  152.856 142.619 152.874 142.655 ;
     RECT  153.9 142.507 154.458 142.727 ;
     RECT  150.552 142.231 150.714 142.771 ;
     RECT  151.488 142.619 151.722 142.771 ;
     RECT  150.444 142.771 151.722 142.889 ;
     RECT  150.444 142.889 150.462 142.925 ;
     RECT  151.488 142.889 151.542 142.925 ;
     RECT  147.276 142.655 148.95 143.069 ;
     RECT  153.036 143.005 153.054 143.159 ;
     RECT  150.048 143.041 150.066 143.195 ;
     RECT  0.396 141.647 20.862 143.437 ;
     RECT  152.928 143.437 152.946 143.581 ;
     RECT  151.524 142.925 151.542 143.671 ;
     RECT  150.804 143.671 151.542 143.707 ;
     RECT  150.624 143.707 151.542 143.744 ;
     RECT  150.804 143.744 151.542 143.789 ;
     RECT  151.056 143.789 151.542 143.851 ;
     RECT  152.856 143.581 152.946 144.085 ;
     RECT  151.056 143.851 151.83 144.121 ;
     RECT  147.276 143.069 148.842 144.211 ;
     RECT  151.056 144.121 152.046 144.211 ;
     RECT  152.856 144.085 153.054 144.211 ;
     RECT  149.868 143.401 149.886 144.235 ;
     RECT  151.056 144.211 153.054 144.239 ;
     RECT  147.276 144.211 148.95 144.269 ;
     RECT  29.415 133.321 30.546 144.275 ;
     RECT  146.484 144.247 146.502 144.419 ;
     RECT  151.056 144.239 153.018 144.509 ;
     RECT  151.164 144.509 153.018 144.581 ;
     RECT  149.868 144.235 149.922 144.661 ;
     RECT  25.344 142.259 25.362 144.689 ;
     RECT  149.868 144.661 150.066 144.779 ;
     RECT  151.164 144.581 152.802 144.851 ;
     RECT  29.415 144.275 30.33 145.048 ;
     RECT  28.8 145.048 30.33 145.085 ;
     RECT  147.276 144.269 148.842 145.201 ;
     RECT  154.44 142.727 154.458 145.201 ;
     RECT  152.352 144.851 152.802 145.327 ;
     RECT  147.276 145.201 149.562 145.355 ;
     RECT  151.164 144.851 151.542 145.471 ;
     RECT  152.352 145.327 153.09 145.471 ;
     RECT  153.9 145.201 154.458 145.471 ;
     RECT  26.46 139.487 27.054 145.499 ;
     RECT  152.352 145.471 154.458 145.565 ;
     RECT  150.804 145.471 151.542 145.669 ;
     RECT  152.352 145.565 153.234 145.669 ;
     RECT  150.804 145.669 153.234 145.741 ;
     RECT  22.716 142.259 24.57 145.831 ;
     RECT  22.716 145.831 25.11 145.859 ;
     RECT  0.396 143.437 21.366 145.867 ;
     RECT  150.48 145.741 153.234 145.939 ;
     RECT  149.904 145.939 153.234 145.967 ;
     RECT  0.108 145.867 21.366 145.997 ;
     RECT  150.84 145.967 153.234 145.997 ;
     RECT  23.292 145.859 25.11 146.201 ;
     RECT  149.904 145.967 149.922 146.209 ;
     RECT  147.276 145.355 148.842 146.245 ;
     RECT  146.484 146.173 146.502 146.273 ;
     RECT  150.84 145.997 153.09 146.399 ;
     RECT  150.84 146.399 153.018 146.435 ;
     RECT  149.832 146.209 149.922 146.479 ;
     RECT  149.724 146.479 149.922 146.507 ;
     RECT  150.912 146.435 153.018 146.741 ;
     RECT  147.276 146.245 148.878 147.091 ;
     RECT  149.724 146.507 149.814 147.091 ;
     RECT  147.276 147.091 149.814 147.245 ;
     RECT  26.46 145.499 26.478 147.479 ;
     RECT  150.912 146.741 152.802 147.515 ;
     RECT  151.128 147.515 152.802 147.523 ;
     RECT  151.128 147.523 152.874 147.595 ;
     RECT  154.44 145.565 154.458 147.595 ;
     RECT  154.44 147.595 154.494 147.691 ;
     RECT  154.404 147.691 154.494 147.749 ;
     RECT  23.292 146.201 24.57 147.785 ;
     RECT  23.904 147.785 24.57 148.019 ;
     RECT  147.276 147.245 148.878 148.019 ;
     RECT  154.44 147.749 154.494 148.157 ;
     RECT  149.976 147.721 149.994 148.171 ;
     RECT  149.976 148.171 150.39 148.219 ;
     RECT  25.596 148.441 25.614 148.559 ;
     RECT  151.128 147.595 153.054 148.559 ;
     RECT  149.832 148.219 150.39 148.595 ;
     RECT  147.276 148.019 148.806 148.829 ;
     RECT  149.832 148.595 150.102 148.829 ;
     RECT  0.396 145.997 21.366 149.135 ;
     RECT  149.904 148.829 150.102 149.135 ;
     RECT  146.484 149.107 146.502 149.279 ;
     RECT  154.44 148.157 154.458 149.419 ;
     RECT  151.524 148.559 153.054 149.521 ;
     RECT  0.396 149.135 20.61 149.639 ;
     RECT  147.276 148.829 148.662 149.647 ;
     RECT  149.904 149.135 149.922 149.647 ;
     RECT  153.9 149.419 154.458 149.747 ;
     RECT  154.44 149.747 154.458 149.791 ;
     RECT  147.276 149.647 149.922 149.909 ;
     RECT  147.276 149.909 149.382 150.215 ;
     RECT  154.44 149.791 154.494 150.317 ;
     RECT  150.84 149.521 153.054 150.331 ;
     RECT  146.484 150.061 146.502 150.359 ;
     RECT  24.015 148.019 24.57 150.449 ;
     RECT  150.444 150.331 153.054 150.449 ;
     RECT  0.396 149.639 20.502 150.835 ;
     RECT  26.244 150.421 26.262 151.025 ;
     RECT  150.804 150.449 153.018 151.295 ;
     RECT  0.396 150.835 20.538 151.331 ;
     RECT  147.276 150.215 149.094 151.411 ;
     RECT  29.415 145.085 30.33 151.439 ;
     RECT  150.696 151.303 150.786 151.439 ;
     RECT  147.276 151.411 149.274 151.799 ;
     RECT  147.276 151.799 149.13 151.835 ;
     RECT  154.44 150.317 154.458 151.951 ;
     RECT  21.348 149.135 21.366 151.979 ;
     RECT  154.404 151.951 154.458 152.045 ;
     RECT  147.276 151.835 148.878 152.069 ;
     RECT  150.696 151.439 150.714 152.069 ;
     RECT  147.276 152.069 148.698 152.105 ;
     RECT  149.904 152.149 150.534 152.189 ;
     RECT  149.904 152.189 149.922 152.375 ;
     RECT  154.44 152.045 154.458 152.875 ;
     RECT  151.524 151.295 153.018 152.915 ;
     RECT  0.396 151.331 20.502 152.951 ;
     RECT  151.524 152.915 152.946 153.031 ;
     RECT  99.615 104.288 99.897 153.157 ;
     RECT  97.344 153.121 97.362 153.197 ;
     RECT  98.892 153.157 99.897 153.197 ;
     RECT  0.396 152.951 20.466 153.221 ;
     RECT  72.615 138.509 72.897 153.301 ;
     RECT  147.276 152.105 148.59 153.301 ;
     RECT  149.508 153.229 149.526 153.301 ;
     RECT  70.344 153.163 70.362 153.341 ;
     RECT  71.892 153.301 72.897 153.341 ;
     RECT  146.736 153.301 148.59 153.391 ;
     RECT  149.508 153.301 149.67 153.391 ;
     RECT  153.864 152.875 154.458 153.419 ;
     RECT  146.736 153.391 149.67 153.491 ;
     RECT  20.016 153.221 20.466 153.527 ;
     RECT  151.344 153.031 152.946 153.571 ;
     RECT  149.544 153.491 149.67 153.581 ;
     RECT  146.736 153.491 148.626 153.599 ;
     RECT  146.736 153.599 148.554 153.689 ;
     RECT  149.544 153.581 149.562 153.725 ;
     RECT  118.764 146.983 118.782 153.805 ;
     RECT  150.624 153.571 152.946 153.883 ;
     RECT  118.764 153.805 118.89 154.111 ;
     RECT  146.736 153.689 148.497 154.111 ;
     RECT  153.864 153.419 154.134 154.171 ;
     RECT  117.756 154.075 117.774 154.201 ;
     RECT  150.552 153.883 152.946 154.229 ;
     RECT  117.612 154.201 117.774 154.253 ;
     RECT  118.548 154.111 118.962 154.265 ;
     RECT  146.484 154.111 148.497 154.265 ;
     RECT  117.756 154.253 117.774 154.273 ;
     RECT  117.756 154.273 118.278 154.301 ;
     RECT  150.696 154.229 152.946 154.301 ;
     RECT  127.872 154.237 127.89 154.373 ;
     RECT  118.188 154.301 118.278 154.499 ;
     RECT  151.092 154.301 151.11 154.499 ;
     RECT  151.884 154.301 152.946 154.499 ;
     RECT  153.864 154.171 154.458 154.499 ;
     RECT  151.884 154.499 151.902 154.535 ;
     RECT  152.748 154.499 152.946 154.571 ;
     RECT  154.116 154.499 154.458 154.841 ;
     RECT  152.784 154.571 152.946 154.913 ;
     RECT  154.44 154.841 154.458 155.039 ;
     RECT  153 154.921 153.018 155.075 ;
     RECT  0.396 153.221 19.17 155.155 ;
     RECT  0.396 155.155 19.206 155.309 ;
     RECT  146.736 154.265 148.497 155.921 ;
     RECT  0.396 155.309 19.17 156.271 ;
     RECT  20.016 153.527 20.214 156.271 ;
     RECT  0.396 156.271 20.214 156.929 ;
     RECT  146.736 155.921 147.294 157.739 ;
     RECT  0.396 156.929 19.17 157.747 ;
     RECT  20.196 156.929 20.214 157.747 ;
     RECT  45.615 110.795 45.897 158.395 ;
     RECT  51.015 119.975 51.297 158.395 ;
     RECT  56.415 105.917 56.697 158.395 ;
     RECT  61.815 117.149 62.097 158.395 ;
     RECT  61.815 158.395 62.19 158.443 ;
     RECT  67.215 107.789 67.497 158.443 ;
     RECT  40.215 119.579 40.497 158.521 ;
     RECT  69.084 158.491 69.102 158.549 ;
     RECT  40.215 158.521 40.662 158.573 ;
     RECT  42.732 158.443 42.858 158.573 ;
     RECT  45.615 158.395 45.99 158.573 ;
     RECT  46.728 158.443 46.746 158.573 ;
     RECT  51.015 158.395 51.39 158.573 ;
     RECT  54.72 158.443 54.738 158.573 ;
     RECT  56.415 158.395 56.79 158.573 ;
     RECT  58.68 158.443 58.698 158.573 ;
     RECT  61.815 158.443 62.73 158.573 ;
     RECT  66.708 158.443 67.497 158.635 ;
     RECT  66.708 158.635 67.554 158.669 ;
     RECT  40.215 158.573 40.554 158.729 ;
     RECT  67.215 158.669 67.554 158.729 ;
     RECT  65.88 155.893 65.898 159.089 ;
     RECT  146.736 157.739 146.754 160.979 ;
     RECT  0.396 157.747 20.214 161.357 ;
     RECT  0.396 161.357 18.897 161.519 ;
     RECT  18.108 161.519 18.897 161.591 ;
     RECT  0.396 161.519 17.226 161.825 ;
     RECT  65.628 159.205 65.646 161.825 ;
     RECT  0.396 161.825 17.046 161.861 ;
     RECT  0.396 161.861 16.83 162.095 ;
     RECT  19.656 161.357 20.214 162.743 ;
     RECT  0.396 162.095 16.794 162.779 ;
     RECT  0.396 162.779 16.686 162.869 ;
     RECT  0.396 162.869 16.254 164.633 ;
     RECT  0.396 164.633 14.418 164.759 ;
     RECT  0.396 164.759 14.094 164.939 ;
     RECT  15.408 164.633 15.678 164.939 ;
     RECT  118.26 154.499 118.278 167.297 ;
     RECT  78.015 105.917 78.297 167.341 ;
     RECT  79.2 167.269 79.218 167.341 ;
     RECT  78.015 167.341 79.218 167.369 ;
     RECT  0.396 164.939 12.186 167.467 ;
     RECT  0.108 167.467 12.186 167.597 ;
     RECT  0.396 167.597 12.186 170.443 ;
     RECT  0.36 170.443 12.186 170.977 ;
     RECT  0.108 170.977 12.186 171.053 ;
     RECT  0.36 171.053 12.186 172.931 ;
     RECT  78.015 167.369 78.966 173.939 ;
     RECT  21.096 174.085 21.114 174.091 ;
     RECT  21.096 174.091 21.402 174.209 ;
     RECT  21.096 174.209 21.114 174.221 ;
     RECT  13.215 164.939 13.497 175.432 ;
     RECT  13.104 175.432 13.497 175.469 ;
     RECT  22.644 175.003 22.662 175.531 ;
     RECT  22.644 175.531 22.986 175.559 ;
     RECT  22.968 175.559 22.986 175.568 ;
     RECT  0.432 172.931 12.186 176.107 ;
     RECT  0.108 176.107 12.186 176.237 ;
     RECT  0.432 176.237 12.186 177.359 ;
     RECT  0.468 177.359 12.186 181.777 ;
     RECT  0.108 181.777 12.186 181.853 ;
     RECT  0.468 181.853 12.186 183.569 ;
     RECT  0.504 183.569 12.186 184.199 ;
     RECT  0.504 184.199 10.278 184.739 ;
     RECT  9.684 184.739 10.278 184.939 ;
     RECT  11.196 184.199 12.186 184.939 ;
     RECT  0.504 184.739 8.946 186.398 ;
     RECT  0.468 186.398 8.946 187.124 ;
     RECT  20.196 162.743 20.214 189.869 ;
     RECT  9.684 184.939 12.186 192.479 ;
     RECT  0.504 187.124 8.946 192.749 ;
     RECT  0.504 192.749 1.134 194.378 ;
     RECT  15.66 164.939 15.678 194.395 ;
     RECT  15.66 194.395 16.29 194.701 ;
     RECT  15.156 194.701 16.29 194.729 ;
     RECT  15.156 194.729 15.678 194.765 ;
     RECT  0.468 194.378 1.134 197.924 ;
     RECT  9.684 192.479 11.214 198.379 ;
     RECT  12.096 192.479 12.186 198.379 ;
     RECT  9.684 198.379 12.186 198.689 ;
     RECT  9.684 198.689 10.53 198.779 ;
     RECT  11.376 198.689 12.186 199.769 ;
     RECT  11.376 199.769 12.114 201.479 ;
     RECT  15.66 194.765 15.678 203.639 ;
     RECT  2.16 192.749 8.946 204.089 ;
     RECT  12.096 201.479 12.114 205.195 ;
     RECT  13.215 175.469 13.497 205.195 ;
     RECT  12.096 205.195 13.497 205.231 ;
     RECT  11.7 205.231 13.497 205.259 ;
     RECT  11.7 205.259 12.114 205.277 ;
     RECT  2.268 204.089 8.946 205.799 ;
     RECT  0.504 197.924 1.134 208.579 ;
     RECT  0.468 208.579 1.134 208.637 ;
     RECT  2.268 205.799 8.766 209.857 ;
     RECT  2.052 209.857 8.766 209.933 ;
     RECT  9.684 198.779 10.278 211.199 ;
     RECT  0.504 208.637 1.134 212.017 ;
     RECT  0.108 212.017 1.134 212.093 ;
     RECT  10.44 212.059 10.458 212.279 ;
     RECT  9.684 211.199 9.702 212.431 ;
     RECT  0.504 212.093 1.134 214.619 ;
     RECT  78.015 173.939 78.894 216.059 ;
     RECT  78.015 216.059 78.498 216.175 ;
     RECT  77.616 216.175 78.498 216.329 ;
     RECT  77.616 216.329 78.39 217.139 ;
     RECT  0.54 214.619 1.134 217.147 ;
     RECT  77.616 217.139 78.354 217.147 ;
     RECT  0.108 217.147 1.134 217.277 ;
     RECT  77.58 217.147 78.354 217.291 ;
     RECT  76.968 217.291 78.354 217.319 ;
     RECT  76.968 217.319 78.297 217.417 ;
     RECT  76.824 217.417 78.297 217.469 ;
     RECT  2.268 209.933 8.766 217.589 ;
     RECT  77.292 217.469 78.297 217.715 ;
     RECT  2.304 217.589 8.766 218.573 ;
     RECT  12.096 205.277 12.114 219.029 ;
     RECT  0.54 217.277 1.134 219.677 ;
     RECT  2.415 218.573 8.766 219.835 ;
     RECT  2.412 219.835 8.766 220.267 ;
     RECT  2.304 220.267 8.766 222.035 ;
     RECT  0.108 222.277 0.126 222.893 ;
     RECT  9.684 212.431 9.774 223.079 ;
     RECT  2.415 222.035 8.766 223.291 ;
     RECT  2.304 223.291 8.766 223.385 ;
     RECT  1.08 219.677 1.134 223.529 ;
     RECT  2.412 223.385 8.766 223.691 ;
     RECT  2.412 223.691 8.622 223.763 ;
     RECT  2.415 223.763 8.622 223.925 ;
     RECT  3.492 223.925 8.622 224.465 ;
     RECT  2.415 223.925 2.697 224.587 ;
     RECT  2.304 224.587 2.697 225.355 ;
     RECT  3.6 224.465 8.622 225.355 ;
     RECT  2.304 225.355 8.622 225.545 ;
     RECT  9.756 223.079 9.774 225.739 ;
     RECT  9.504 225.739 9.774 226.165 ;
     RECT  2.415 225.545 8.622 226.315 ;
     RECT  9.36 226.165 9.774 226.589 ;
     RECT  2.304 226.315 8.622 227.213 ;
     RECT  2.412 227.213 8.622 227.705 ;
     RECT  0.108 227.983 0.126 228.077 ;
     RECT  2.415 227.705 2.697 228.475 ;
     RECT  2.415 228.475 2.79 228.865 ;
     RECT  3.6 227.705 8.622 228.901 ;
     RECT  2.304 228.865 2.79 228.941 ;
     RECT  2.415 228.941 2.79 229.171 ;
     RECT  3.564 228.901 8.622 229.171 ;
     RECT  2.415 229.171 8.622 229.289 ;
     RECT  1.08 223.529 1.098 229.433 ;
     RECT  9.756 226.589 9.774 230.135 ;
     RECT  2.415 229.289 2.697 230.203 ;
     RECT  3.564 229.289 8.622 230.587 ;
     RECT  2.304 230.203 2.697 230.755 ;
     RECT  3.456 230.587 8.622 230.755 ;
     RECT  2.304 230.755 8.622 231.179 ;
     RECT  2.304 231.179 6.318 231.215 ;
     RECT  2.304 231.215 2.826 231.533 ;
     RECT  7.056 231.179 8.622 231.719 ;
     RECT  77.832 217.715 78.297 231.827 ;
     RECT  3.852 231.215 6.318 231.989 ;
     RECT  3.852 231.989 6.282 232.219 ;
     RECT  2.304 231.533 2.697 232.403 ;
     RECT  2.415 232.403 2.697 232.411 ;
     RECT  3.456 232.219 6.282 232.411 ;
     RECT  2.415 232.411 6.282 233.105 ;
     RECT  3.96 233.105 6.282 233.131 ;
     RECT  7.092 231.719 8.622 233.131 ;
     RECT  2.415 233.105 2.697 233.227 ;
     RECT  3.96 233.131 8.622 233.609 ;
     RECT  3.96 233.609 6.282 233.951 ;
     RECT  3.96 233.951 4.23 234.031 ;
     RECT  2.304 233.227 2.697 234.265 ;
     RECT  3.744 234.031 4.23 234.265 ;
     RECT  5.04 233.951 6.282 234.419 ;
     RECT  2.304 234.265 4.23 234.455 ;
     RECT  3.42 234.455 4.23 234.689 ;
     RECT  5.04 234.419 6.138 234.689 ;
     RECT  3.528 234.689 4.23 234.769 ;
     RECT  3.528 234.769 4.302 234.805 ;
     RECT  5.04 234.689 5.814 234.805 ;
     RECT  3.528 234.805 5.814 235.265 ;
     RECT  3.528 235.265 5.706 235.499 ;
     RECT  3.528 235.499 5.562 235.571 ;
     RECT  2.304 234.455 2.697 235.651 ;
     RECT  3.528 235.571 4.266 235.651 ;
     RECT  2.304 235.651 4.266 235.769 ;
     RECT  2.304 235.769 2.697 236.345 ;
     RECT  3.564 235.769 4.266 236.461 ;
     RECT  5.184 235.571 5.562 236.461 ;
     RECT  3.564 236.461 5.562 236.731 ;
     RECT  7.092 233.609 8.622 236.849 ;
     RECT  3.528 236.731 5.562 237.001 ;
     RECT  3.528 237.001 6.21 237.119 ;
     RECT  2.412 236.345 2.697 237.541 ;
     RECT  3.528 237.119 5.49 237.541 ;
     RECT  2.412 237.541 5.49 237.547 ;
     RECT  2.304 237.547 5.49 237.659 ;
     RECT  3.564 237.659 4.698 237.695 ;
     RECT  5.472 237.659 5.49 237.929 ;
     RECT  2.304 237.659 2.79 238.013 ;
     RECT  6.264 238.123 6.282 238.171 ;
     RECT  3.852 237.695 4.698 238.235 ;
     RECT  6.228 238.171 6.282 238.243 ;
     RECT  5.688 238.243 6.282 238.469 ;
     RECT  2.304 238.013 2.697 238.505 ;
     RECT  3.996 238.235 4.698 238.585 ;
     RECT  7.815 236.849 8.622 238.739 ;
     RECT  3.996 238.585 4.806 238.843 ;
     RECT  0.108 238.747 0.126 238.877 ;
     RECT  6.192 238.469 6.282 238.891 ;
     RECT  3.996 238.843 5.058 239.009 ;
     RECT  6.192 238.891 6.966 239.009 ;
     RECT  4.464 239.009 4.662 239.045 ;
     RECT  77.94 231.827 78.297 239.117 ;
     RECT  2.415 238.505 2.697 239.125 ;
     RECT  2.415 239.125 3.078 239.161 ;
     RECT  77.976 239.117 78.297 239.165 ;
     RECT  2.415 239.161 3.222 239.275 ;
     RECT  6.192 239.009 6.246 239.279 ;
     RECT  4.536 239.045 4.662 239.315 ;
     RECT  6.228 239.279 6.246 239.791 ;
     RECT  2.304 239.275 3.222 239.855 ;
     RECT  6.228 239.791 6.966 239.885 ;
     RECT  2.415 239.855 3.222 239.971 ;
     RECT  2.415 239.971 3.294 240.061 ;
     RECT  6.228 239.885 6.246 240.089 ;
     RECT  4.536 239.315 4.626 240.161 ;
     RECT  2.415 240.061 3.546 240.359 ;
     RECT  4.896 240.241 4.914 240.359 ;
     RECT  2.415 240.359 3.006 240.395 ;
     RECT  3.96 240.475 4.122 240.629 ;
     RECT  3.96 240.629 3.978 240.665 ;
     RECT  78.015 239.165 78.297 242.779 ;
     RECT  78.012 242.779 78.297 242.825 ;
     RECT  2.415 240.395 2.697 243.827 ;
     RECT  7.815 238.739 8.097 243.827 ;
     RECT  13.215 205.259 13.497 243.827 ;
     RECT  18.615 161.591 18.897 243.827 ;
     RECT  24.015 150.449 24.297 243.827 ;
     RECT  29.415 151.439 29.697 243.827 ;
     RECT  34.815 131.117 35.097 243.827 ;
     RECT  40.215 158.729 40.497 243.827 ;
     RECT  45.615 158.573 45.897 243.827 ;
     RECT  51.015 158.573 51.297 243.827 ;
     RECT  56.415 158.573 56.697 243.827 ;
     RECT  61.815 158.573 62.097 243.827 ;
     RECT  67.215 158.729 67.497 243.827 ;
     RECT  72.615 153.341 72.897 243.827 ;
     RECT  78.015 242.825 78.297 243.827 ;
     RECT  83.415 2.413 83.697 243.827 ;
     RECT  88.815 104.288 89.097 243.827 ;
     RECT  94.215 2.413 94.497 243.827 ;
     RECT  99.615 153.197 99.897 243.827 ;
     RECT  105.015 2.413 105.297 243.827 ;
     RECT  110.415 104.285 110.697 243.827 ;
     RECT  115.815 2.413 116.097 243.827 ;
     RECT  121.215 104.288 121.497 243.827 ;
     RECT  126.615 2.413 126.897 243.827 ;
     RECT  132.015 104.288 132.297 243.827 ;
     RECT  137.415 2.413 137.697 243.827 ;
     RECT  142.815 131.549 143.097 243.827 ;
     RECT  148.215 155.921 148.497 243.827 ;
     RECT  2.415 243.827 2.505 244.097 ;
     RECT  7.815 243.827 7.905 244.097 ;
     RECT  13.215 243.827 13.305 244.097 ;
     RECT  18.615 243.827 18.705 244.097 ;
     RECT  24.015 243.827 24.105 244.097 ;
     RECT  29.415 243.827 29.505 244.097 ;
     RECT  34.815 243.827 34.905 244.097 ;
     RECT  40.215 243.827 40.305 244.097 ;
     RECT  45.615 243.827 45.705 244.097 ;
     RECT  51.015 243.827 51.105 244.097 ;
     RECT  56.415 243.827 56.505 244.097 ;
     RECT  61.815 243.827 61.905 244.097 ;
     RECT  67.215 243.827 67.305 244.097 ;
     RECT  72.615 243.827 72.705 244.097 ;
     RECT  78.015 243.827 78.105 244.097 ;
     RECT  83.415 243.827 83.505 244.097 ;
     RECT  88.815 243.827 88.905 244.097 ;
     RECT  94.215 243.827 94.305 244.097 ;
     RECT  99.615 243.827 99.705 244.097 ;
     RECT  105.015 243.827 105.105 244.097 ;
     RECT  110.415 243.827 110.505 244.097 ;
     RECT  115.815 243.827 115.905 244.097 ;
     RECT  121.215 243.827 121.305 244.097 ;
     RECT  126.615 243.827 126.705 244.097 ;
     RECT  132.015 243.827 132.105 244.097 ;
     RECT  137.415 243.827 137.505 244.097 ;
     RECT  142.815 243.827 142.905 244.097 ;
     RECT  148.215 243.827 148.305 244.097 ;
    LAYER M4 ;
     RECT  0.06 6 0.137 240.168 ;
     RECT  0.137 6 2.408 222.024 ;
     RECT  0.137 223.296 2.408 240.168 ;
     RECT  2.408 2.148 2.512 244.092 ;
     RECT  2.512 2.418 2.704 243.822 ;
     RECT  2.704 41.424 2.765 43.608 ;
     RECT  2.704 66.48 2.765 66.504 ;
     RECT  2.704 74.688 2.765 74.712 ;
     RECT  2.704 76.848 2.765 78.744 ;
     RECT  2.704 149.856 2.765 150.312 ;
     RECT  2.704 154.8 2.765 156.792 ;
     RECT  2.704 200.4 2.765 201.192 ;
     RECT  2.704 202.56 2.765 203.544 ;
     RECT  2.704 225.696 2.765 225.912 ;
     RECT  2.704 34.08 2.801 35.928 ;
     RECT  2.765 41.424 2.801 42.696 ;
     RECT  2.704 67.536 2.801 68.952 ;
     RECT  2.704 128.784 2.801 132.168 ;
     RECT  2.704 134.928 2.801 140.76 ;
     RECT  2.704 228.48 2.801 228.504 ;
     RECT  2.704 230.592 2.801 232.824 ;
     RECT  2.704 237.984 2.801 240.168 ;
     RECT  2.704 116.688 2.819 121.32 ;
     RECT  2.704 30.624 2.837 30.648 ;
     RECT  2.801 34.944 2.837 35.928 ;
     RECT  2.704 168.72 2.837 172.008 ;
     RECT  2.704 183.696 2.837 187.8 ;
     RECT  2.704 192.624 2.837 193.608 ;
     RECT  2.801 230.592 2.837 232.248 ;
     RECT  2.801 238.896 2.837 240.168 ;
     RECT  2.837 231.984 2.867 232.248 ;
     RECT  2.765 203.472 2.873 203.544 ;
     RECT  2.704 210 2.873 211.512 ;
     RECT  2.704 189.264 2.909 191.544 ;
     RECT  2.704 195.456 2.909 196.68 ;
     RECT  2.704 213.6 2.909 215.544 ;
     RECT  2.704 219.408 2.909 221.304 ;
     RECT  2.909 195.504 2.915 196.68 ;
     RECT  2.873 203.52 2.915 203.544 ;
     RECT  2.873 211.488 2.945 211.512 ;
     RECT  2.704 176.16 3.011 177.24 ;
     RECT  2.704 16.368 3.017 16.392 ;
     RECT  2.704 51.696 3.017 51.912 ;
     RECT  2.704 157.872 3.107 158.376 ;
     RECT  2.704 160.416 3.107 160.728 ;
     RECT  2.704 73.296 3.125 73.32 ;
     RECT  2.704 6.24 3.305 6.648 ;
     RECT  2.704 9.12 3.305 9.144 ;
     RECT  2.909 213.6 3.305 215.496 ;
     RECT  2.704 7.92 3.34 7.944 ;
     RECT  2.837 183.696 3.347 185.928 ;
     RECT  2.704 126.576 3.395 127.272 ;
     RECT  2.704 182.352 3.413 182.568 ;
     RECT  2.704 123.168 3.436 125.112 ;
     RECT  2.801 128.784 3.443 131.928 ;
     RECT  2.704 70.656 3.491 72.12 ;
     RECT  2.704 161.76 3.491 166.488 ;
     RECT  2.704 178.272 3.491 180.696 ;
     RECT  2.765 149.856 3.557 149.88 ;
     RECT  3.436 123.168 3.587 124.488 ;
     RECT  2.909 189.264 3.601 190.92 ;
     RECT  2.704 204.624 3.629 208.488 ;
     RECT  2.819 116.688 3.697 121.176 ;
     RECT  2.837 168.72 3.733 168.744 ;
     RECT  2.704 148.032 3.781 148.296 ;
     RECT  2.801 67.536 3.805 68.808 ;
     RECT  2.704 218.256 3.829 218.28 ;
     RECT  3.587 123.168 3.836 124.392 ;
     RECT  2.801 139.536 3.841 140.76 ;
     RECT  2.704 141.888 3.841 141.912 ;
     RECT  3.011 176.16 3.841 176.76 ;
     RECT  2.704 216.624 3.841 216.648 ;
     RECT  3.829 217.728 3.841 218.28 ;
     RECT  3.836 54.48 3.877 54.504 ;
     RECT  2.704 151.536 3.877 152.808 ;
     RECT  2.837 192.672 3.877 193.608 ;
     RECT  3.877 192.672 3.913 193.944 ;
     RECT  3.877 54.48 3.923 55.128 ;
     RECT  2.837 35.904 3.925 35.928 ;
     RECT  2.837 186.96 3.925 187.8 ;
     RECT  3.805 229.536 3.925 229.56 ;
     RECT  2.837 230.592 3.925 230.616 ;
     RECT  3.443 129.024 3.949 131.928 ;
     RECT  3.491 161.76 3.971 166.296 ;
     RECT  3.925 228.72 3.971 230.904 ;
     RECT  2.704 25.152 3.973 25.176 ;
     RECT  2.801 134.928 3.973 138.552 ;
     RECT  3.841 139.536 3.973 141.912 ;
     RECT  2.704 142.944 3.973 146.184 ;
     RECT  3.913 203.424 3.973 203.448 ;
     RECT  3.629 204.624 3.973 206.088 ;
     RECT  3.913 235.392 3.973 235.416 ;
     RECT  3.973 25.152 4.019 26.76 ;
     RECT  3.973 203.424 4.019 206.088 ;
     RECT  3.973 235.392 4.019 235.992 ;
     RECT  2.704 86.016 4.021 87.288 ;
     RECT  3.107 158.304 4.021 158.376 ;
     RECT  2.704 159.36 4.021 159.384 ;
     RECT  3.949 23.904 4.033 23.928 ;
     RECT  4.021 158.304 4.057 159.384 ;
     RECT  3.107 160.416 4.057 160.44 ;
     RECT  3.925 34.176 4.061 34.2 ;
     RECT  2.765 225.696 4.061 225.72 ;
     RECT  3.305 213.6 4.065 213.624 ;
     RECT  3.877 73.92 4.069 73.944 ;
     RECT  3.347 183.696 4.069 183.72 ;
     RECT  3.836 123.12 4.093 124.392 ;
     RECT  3.971 161.856 4.115 166.296 ;
     RECT  3.913 192.672 4.117 194.424 ;
     RECT  4.065 213.168 4.163 213.624 ;
     RECT  3.925 35.664 4.169 35.928 ;
     RECT  3.491 70.656 4.169 70.68 ;
     RECT  3.973 134.928 4.169 146.184 ;
     RECT  4.115 161.856 4.169 163.032 ;
     RECT  4.169 142.944 4.201 146.184 ;
     RECT  4.117 192.048 4.205 194.424 ;
     RECT  4.069 73.92 4.237 74.568 ;
     RECT  3.601 190.128 4.241 190.92 ;
     RECT  3.841 216.624 4.261 218.28 ;
     RECT  2.704 133.392 4.268 133.416 ;
     RECT  3.971 228.72 4.277 228.744 ;
     RECT  4.019 235.968 4.277 235.992 ;
     RECT  4.261 216.624 4.307 218.904 ;
     RECT  2.765 77.472 4.309 78.744 ;
     RECT  2.704 80.112 4.309 84.984 ;
     RECT  2.704 89.28 4.309 115.32 ;
     RECT  3.697 116.304 4.309 121.176 ;
     RECT  4.169 134.928 4.309 141.912 ;
     RECT  2.765 201.168 4.317 201.192 ;
     RECT  2.704 60.384 4.345 60.408 ;
     RECT  4.307 218.88 4.345 218.904 ;
     RECT  2.909 220.128 4.345 221.304 ;
     RECT  4.268 133.296 4.355 133.416 ;
     RECT  3.781 148.032 4.381 148.44 ;
     RECT  4.057 158.304 4.381 160.44 ;
     RECT  4.345 218.88 4.385 221.736 ;
     RECT  2.704 13.056 4.405 14.52 ;
     RECT  4.169 35.904 4.405 35.928 ;
     RECT  3.841 176.112 4.405 176.76 ;
     RECT  4.345 49.2 4.412 49.224 ;
     RECT  2.704 174.48 4.412 174.504 ;
     RECT  4.405 176.112 4.412 177.288 ;
     RECT  2.704 223.968 4.412 223.992 ;
     RECT  4.355 133.344 4.417 133.416 ;
     RECT  4.309 134.544 4.417 141.912 ;
     RECT  4.317 201.168 4.421 201.816 ;
     RECT  4.019 204.336 4.421 206.088 ;
     RECT  4.345 17.088 4.451 17.112 ;
     RECT  4.405 35.904 4.451 37.176 ;
     RECT  4.405 18.384 4.453 18.504 ;
     RECT  3.949 46.512 4.453 46.536 ;
     RECT  4.412 48.432 4.453 49.224 ;
     RECT  4.309 77.472 4.453 84.984 ;
     RECT  4.021 86.016 4.453 88.248 ;
     RECT  4.309 89.28 4.453 121.416 ;
     RECT  4.093 122.496 4.453 124.392 ;
     RECT  4.412 174.48 4.453 177.288 ;
     RECT  3.491 178.368 4.453 180.696 ;
     RECT  3.413 182.544 4.453 182.568 ;
     RECT  2.704 28.464 4.46 28.488 ;
     RECT  3.395 126.768 4.46 127.272 ;
     RECT  2.704 173.328 4.481 173.352 ;
     RECT  4.019 25.68 4.489 26.76 ;
     RECT  4.46 27.744 4.489 28.488 ;
     RECT  3.877 40.992 4.489 41.016 ;
     RECT  2.801 42.144 4.489 42.696 ;
     RECT  4.46 126.432 4.489 127.272 ;
     RECT  4.453 18.384 4.493 18.84 ;
     RECT  4.489 25.68 4.493 28.488 ;
     RECT  4.115 164.064 4.493 166.296 ;
     RECT  4.412 223.968 4.493 224.568 ;
     RECT  4.453 46.512 4.499 49.224 ;
     RECT  4.453 77.472 4.499 88.248 ;
     RECT  4.453 174.432 4.499 177.288 ;
     RECT  4.493 224.544 4.499 224.568 ;
     RECT  3.949 129.024 4.501 132.264 ;
     RECT  4.345 198.768 4.501 198.792 ;
     RECT  4.497 56.448 4.508 56.472 ;
     RECT  3.769 57.6 4.508 57.624 ;
     RECT  2.837 238.896 4.511 239.88 ;
     RECT  4.489 40.992 4.525 42.696 ;
     RECT  3.805 67.008 4.525 68.808 ;
     RECT  2.837 169.872 4.525 172.008 ;
     RECT  2.915 195.552 4.525 196.68 ;
     RECT  4.501 197.76 4.525 198.792 ;
     RECT  4.525 40.992 4.529 42.792 ;
     RECT  4.261 72.336 4.529 72.36 ;
     RECT  3.971 229.824 4.529 229.848 ;
     RECT  4.453 225.744 4.537 225.768 ;
     RECT  4.405 12.528 4.547 14.856 ;
     RECT  4.493 18.48 4.547 18.84 ;
     RECT  4.493 26.208 4.547 28.488 ;
     RECT  4.405 34.8 4.547 34.824 ;
     RECT  4.451 36.624 4.547 37.176 ;
     RECT  4.499 46.512 4.547 47.496 ;
     RECT  2.704 11.136 4.549 11.16 ;
     RECT  4.547 12.528 4.549 14.52 ;
     RECT  4.453 89.28 4.549 124.392 ;
     RECT  2.867 232.128 4.559 232.248 ;
     RECT  4.508 56.448 4.565 57.624 ;
     RECT  4.381 158.304 4.565 160.728 ;
     RECT  4.481 173.28 4.565 173.352 ;
     RECT  4.499 77.472 4.593 78.744 ;
     RECT  4.549 11.136 4.595 14.52 ;
     RECT  4.237 73.92 4.595 75.384 ;
     RECT  3.733 168 4.597 168.744 ;
     RECT  4.525 169.872 4.597 172.152 ;
     RECT  3.925 186.96 4.597 188.28 ;
     RECT  2.873 210 4.604 210.456 ;
     RECT  4.597 186.96 4.633 188.424 ;
     RECT  4.241 190.128 4.633 190.2 ;
     RECT  4.501 76.368 4.637 76.392 ;
     RECT  3.305 215.04 4.637 215.496 ;
     RECT  4.597 167.52 4.643 172.152 ;
     RECT  3.629 207.264 4.645 208.488 ;
     RECT  4.604 209.808 4.645 210.456 ;
     RECT  4.499 79.968 4.669 88.248 ;
     RECT  4.549 89.28 4.669 124.584 ;
     RECT  4.565 158.304 4.669 159.384 ;
     RECT  4.421 205.536 4.673 206.088 ;
     RECT  4.565 56.448 4.691 57.144 ;
     RECT  4.549 70.704 4.691 70.776 ;
     RECT  4.453 178.368 4.691 182.568 ;
     RECT  3.877 151.536 4.693 153.768 ;
     RECT  2.765 154.8 4.693 155.352 ;
     RECT  4.421 201.792 4.705 201.816 ;
     RECT  4.237 202.944 4.705 202.968 ;
     RECT  4.637 215.472 4.705 215.496 ;
     RECT  4.307 216.624 4.705 217.752 ;
     RECT  4.643 169.008 4.709 172.152 ;
     RECT  4.549 44.976 4.741 45 ;
     RECT  4.489 125.808 4.741 127.272 ;
     RECT  4.501 128.256 4.741 132.264 ;
     RECT  4.381 148.032 4.741 149.016 ;
     RECT  4.693 151.536 4.741 155.352 ;
     RECT  4.691 181.632 4.741 182.568 ;
     RECT  4.069 183.552 4.741 183.72 ;
     RECT  3.347 184.704 4.741 185.928 ;
     RECT  4.595 73.92 4.745 74.664 ;
     RECT  4.705 201.792 4.745 202.968 ;
     RECT  4.705 215.472 4.745 217.752 ;
     RECT  4.745 215.472 4.781 216.648 ;
     RECT  4.741 181.632 4.787 185.928 ;
     RECT  4.547 28.416 4.789 28.488 ;
     RECT  4.748 29.904 4.789 29.928 ;
     RECT  4.525 67.008 4.789 68.856 ;
     RECT  4.595 11.136 4.813 12.552 ;
     RECT  4.547 18.816 4.817 18.84 ;
     RECT  4.345 60.384 4.817 61.032 ;
     RECT  4.565 173.328 4.817 173.352 ;
     RECT  4.559 232.128 4.817 232.776 ;
     RECT  4.741 151.536 4.828 155.88 ;
     RECT  4.828 151.536 4.835 155.64 ;
     RECT  3.305 6.624 4.837 6.648 ;
     RECT  4.813 7.968 4.837 7.992 ;
     RECT  4.813 10.848 4.837 12.552 ;
     RECT  4.201 21.648 4.837 21.672 ;
     RECT  2.704 227.376 4.837 227.4 ;
     RECT  4.741 44.928 4.847 45 ;
     RECT  4.837 226.848 4.849 227.4 ;
     RECT  4.837 10.512 4.853 12.552 ;
     RECT  4.493 164.592 4.853 166.296 ;
     RECT  4.499 175.536 4.853 177.288 ;
     RECT  4.789 67.008 4.876 69.528 ;
     RECT  4.853 176.736 4.883 177.288 ;
     RECT  3.923 54.72 4.885 55.128 ;
     RECT  4.787 183.12 4.885 185.928 ;
     RECT  4.633 186.96 4.885 190.2 ;
     RECT  4.709 169.008 4.889 169.368 ;
     RECT  4.709 170.4 4.889 172.152 ;
     RECT  4.837 6.624 4.897 7.992 ;
     RECT  4.853 10.512 4.897 10.872 ;
     RECT  4.897 6.624 4.917 7.464 ;
     RECT  4.741 148.032 4.921 149.496 ;
     RECT  4.849 226.032 4.924 227.4 ;
     RECT  4.837 21.648 4.925 22.488 ;
     RECT  4.844 223.344 4.931 223.368 ;
     RECT  4.817 232.752 4.931 232.776 ;
     RECT  4.499 174.432 4.933 174.504 ;
     RECT  3.769 31.392 4.94 31.416 ;
     RECT  4.789 28.416 4.961 29.928 ;
     RECT  4.525 195.552 4.961 198.792 ;
     RECT  4.597 72.912 4.979 72.936 ;
     RECT  4.673 205.536 4.979 205.896 ;
     RECT  4.205 192.048 4.981 192.072 ;
     RECT  4.924 227.376 4.993 227.4 ;
     RECT  4.961 195.552 4.997 197.208 ;
     RECT  4.94 31.296 5.027 31.416 ;
     RECT  4.885 183.12 5.027 190.2 ;
     RECT  4.817 61.008 5.029 61.032 ;
     RECT  4.417 63.264 5.029 63.288 ;
     RECT  4.129 64.944 5.029 64.968 ;
     RECT  4.921 148.032 5.029 150.168 ;
     RECT  4.835 151.536 5.029 153.72 ;
     RECT  4.883 177.264 5.029 177.288 ;
     RECT  4.691 178.368 5.029 180.456 ;
     RECT  5.027 31.392 5.033 31.416 ;
     RECT  4.993 227.376 5.033 228.024 ;
     RECT  4.205 193.248 5.041 194.424 ;
     RECT  4.981 191.184 5.068 192.072 ;
     RECT  5.029 61.008 5.075 63.288 ;
     RECT  4.745 74.112 5.075 74.616 ;
     RECT  4.693 76.656 5.075 76.776 ;
     RECT  4.876 67.008 5.101 68.952 ;
     RECT  4.169 162.384 5.101 163.032 ;
     RECT  5.075 61.008 5.116 62.424 ;
     RECT  5.027 183.12 5.123 188.424 ;
     RECT  5.029 64.368 5.141 64.968 ;
     RECT  4.669 79.968 5.173 124.632 ;
     RECT  4.529 41.376 5.177 42.792 ;
     RECT  4.853 164.592 5.177 164.808 ;
     RECT  4.853 165.984 5.177 166.296 ;
     RECT  4.645 207.264 5.177 210.456 ;
     RECT  4.835 155.328 5.213 155.64 ;
     RECT  5.173 79.968 5.221 124.776 ;
     RECT  4.741 125.808 5.221 132.264 ;
     RECT  4.961 28.416 5.249 28.488 ;
     RECT  5.177 41.376 5.249 41.4 ;
     RECT  5.116 62.4 5.249 62.424 ;
     RECT  4.643 167.52 5.249 168.024 ;
     RECT  5.101 162.384 5.267 163.608 ;
     RECT  4.201 142.944 5.281 146.664 ;
     RECT  4.385 219.408 5.315 220.152 ;
     RECT  5.029 177.264 5.321 180.456 ;
     RECT  4.993 20.448 5.324 20.472 ;
     RECT  5.221 79.968 5.353 132.264 ;
     RECT  4.417 133.344 5.353 141.912 ;
     RECT  4.547 36.624 5.42 36.648 ;
     RECT  4.345 200.016 5.425 200.04 ;
     RECT  5.353 79.968 5.461 141.912 ;
     RECT  4.889 171.024 5.461 172.152 ;
     RECT  4.547 26.208 5.465 27.336 ;
     RECT  5.075 74.544 5.465 74.616 ;
     RECT  5.123 183.12 5.465 186.36 ;
     RECT  5.425 200.016 5.465 200.616 ;
     RECT  4.781 215.472 5.465 216.216 ;
     RECT  4.163 213.168 5.497 213.336 ;
     RECT  5.324 19.68 5.507 20.472 ;
     RECT  5.465 27.312 5.507 27.336 ;
     RECT  4.847 44.928 5.507 45.672 ;
     RECT  4.897 10.512 5.509 10.824 ;
     RECT  5.281 142.944 5.533 147.048 ;
     RECT  5.029 148.032 5.533 153.72 ;
     RECT  5.497 212.64 5.537 213.768 ;
     RECT  5.068 192.048 5.569 192.072 ;
     RECT  4.889 169.296 5.603 169.368 ;
     RECT  4.691 56.448 5.605 57.048 ;
     RECT  5.267 162.384 5.605 163.56 ;
     RECT  4.525 23.76 5.633 23.784 ;
     RECT  4.993 234.816 5.677 234.84 ;
     RECT  5.569 192.048 5.699 192.12 ;
     RECT  5.507 19.92 5.701 20.472 ;
     RECT  4.925 21.648 5.701 22.2 ;
     RECT  5.633 23.76 5.701 24.504 ;
     RECT  4.885 54.144 5.701 55.128 ;
     RECT  5.701 19.92 5.747 22.2 ;
     RECT  5.701 53.952 5.747 55.272 ;
     RECT  5.461 79.824 5.747 141.912 ;
     RECT  5.747 53.952 5.749 53.976 ;
     RECT  5.747 134.688 5.749 141.912 ;
     RECT  5.533 142.944 5.749 153.72 ;
     RECT  5.605 72.96 5.753 72.984 ;
     RECT  5.605 162.048 5.753 163.56 ;
     RECT  5.42 36.432 5.785 36.648 ;
     RECT  5.177 166.272 5.785 166.296 ;
     RECT  5.749 52.992 5.789 53.976 ;
     RECT  5.041 193.248 5.789 194.328 ;
     RECT  4.997 196.08 5.789 197.208 ;
     RECT  5.537 213.744 5.789 213.768 ;
     RECT  3.971 230.88 5.789 230.904 ;
     RECT  5.756 34.752 5.797 34.776 ;
     RECT  3.017 51.888 5.797 51.912 ;
     RECT  5.789 52.992 5.797 53.016 ;
     RECT  5.747 20.976 5.825 21.528 ;
     RECT  5.785 35.904 5.825 36.648 ;
     RECT  5.677 234.144 5.825 234.84 ;
     RECT  5.797 34.752 5.843 34.92 ;
     RECT  5.797 50.976 5.843 53.016 ;
     RECT  4.345 39.072 5.857 39.096 ;
     RECT  4.691 70.704 5.861 70.728 ;
     RECT  5.749 134.688 5.861 153.72 ;
     RECT  5.603 169.344 5.861 169.368 ;
     RECT  5.321 177.264 5.861 179.016 ;
     RECT  5.825 35.904 5.869 35.928 ;
     RECT  5.843 52.08 5.884 53.016 ;
     RECT  4.595 13.92 5.897 14.52 ;
     RECT  5.141 64.944 5.897 64.968 ;
     RECT  5.177 207.264 5.897 209.112 ;
     RECT  5.465 74.592 5.929 74.616 ;
     RECT  4.787 181.632 5.929 181.656 ;
     RECT  5.507 44.928 5.933 45 ;
     RECT  5.101 66.672 5.933 68.952 ;
     RECT  4.669 157.728 5.933 159.384 ;
     RECT  4.547 47.472 5.941 47.496 ;
     RECT  5.747 19.92 5.969 19.944 ;
     RECT  5.861 178.992 5.969 179.016 ;
     RECT  5.9 17.568 5.987 17.592 ;
     RECT  5.861 148.128 5.989 153.72 ;
     RECT  4.979 205.536 5.996 205.56 ;
     RECT  5.461 171.024 6.001 172.344 ;
     RECT  5.941 47.472 6.005 47.88 ;
     RECT  5.605 56.352 6.005 57.048 ;
     RECT  4.565 160.416 6.005 160.728 ;
     RECT  5.789 197.184 6.005 197.208 ;
     RECT  5.857 38.736 6.029 39.096 ;
     RECT  5.933 44.928 6.035 44.952 ;
     RECT  5.701 23.328 6.037 24.504 ;
     RECT  5.177 210.432 6.037 210.456 ;
     RECT  4.093 211.44 6.037 211.464 ;
     RECT  4.961 29.904 6.041 29.928 ;
     RECT  5.797 33.408 6.041 33.432 ;
     RECT  4.499 49.2 6.041 49.224 ;
     RECT  5.843 50.976 6.041 51 ;
     RECT  4.745 202.272 6.044 202.872 ;
     RECT  4.421 204.336 6.044 204.456 ;
     RECT  6.029 38.736 6.073 39.336 ;
     RECT  5.989 43.872 6.076 43.896 ;
     RECT  4.885 16.56 6.077 16.584 ;
     RECT  6.005 56.4 6.077 57.048 ;
     RECT  5.933 66.672 6.077 68.808 ;
     RECT  5.123 187.776 6.077 188.424 ;
     RECT  6.037 210.432 6.077 211.464 ;
     RECT  6.073 38.736 6.083 39.912 ;
     RECT  5.996 205.536 6.083 206.28 ;
     RECT  4.917 7.44 6.092 7.464 ;
     RECT  6.001 170.976 6.109 172.344 ;
     RECT  4.933 173.856 6.109 174.504 ;
     RECT  6.083 39.312 6.113 39.912 ;
     RECT  5.789 193.248 6.113 193.944 ;
     RECT  4.745 217.728 6.113 217.752 ;
     RECT  5.929 181.632 6.131 181.848 ;
     RECT  6.044 202.272 6.131 204.456 ;
     RECT  5.075 76.752 6.133 76.776 ;
     RECT  4.593 78 6.133 78.744 ;
     RECT  5.213 155.616 6.133 155.64 ;
     RECT  5.569 156.72 6.133 156.744 ;
     RECT  6.131 202.272 6.149 202.872 ;
     RECT  4.385 221.28 6.149 221.736 ;
     RECT  6.092 7.44 6.179 8.376 ;
     RECT  4.961 198.768 6.181 198.792 ;
     RECT  5.861 134.688 6.221 147.048 ;
     RECT  5.537 212.64 6.221 212.664 ;
     RECT  6.037 23.328 6.227 24.84 ;
     RECT  4.511 238.272 6.229 239.88 ;
     RECT  5.033 228 6.253 228.024 ;
     RECT  6.073 62.736 6.257 62.76 ;
     RECT  6.109 170.976 6.275 174.504 ;
     RECT  6.037 237.072 6.275 237.096 ;
     RECT  6.181 197.952 6.277 198.792 ;
     RECT  6.133 76.752 6.284 78.744 ;
     RECT  5.747 79.824 6.284 133.608 ;
     RECT  5.497 222.816 6.284 222.84 ;
     RECT  4.924 226.032 6.284 226.056 ;
     RECT  5.897 14.208 6.293 14.52 ;
     RECT  5.315 219.984 6.293 220.152 ;
     RECT  6.229 238.128 6.316 239.88 ;
     RECT  6.227 23.328 6.323 23.352 ;
     RECT  6.227 24.816 6.323 24.84 ;
     RECT  6.133 155.616 6.325 156.744 ;
     RECT  6.109 169.824 6.325 169.848 ;
     RECT  6.275 170.976 6.325 172.728 ;
     RECT  6.284 225.12 6.325 226.056 ;
     RECT  6.253 227.184 6.325 228.024 ;
     RECT  5.177 42.768 6.329 42.792 ;
     RECT  6.245 59.808 6.329 59.832 ;
     RECT  5.116 61.008 6.364 61.032 ;
     RECT  6.277 197.952 6.364 199.224 ;
     RECT  5.747 55.248 6.365 55.272 ;
     RECT  6.284 222.816 6.365 223.368 ;
     RECT  5.177 164.592 6.369 164.616 ;
     RECT  6.325 169.824 6.371 172.728 ;
     RECT  6.365 223.344 6.371 223.368 ;
     RECT  6.325 225.12 6.371 228.024 ;
     RECT  6.113 39.888 6.38 39.912 ;
     RECT  5.825 21.504 6.401 21.528 ;
     RECT  5.897 207.264 6.401 208.632 ;
     RECT  5.753 162.48 6.419 163.56 ;
     RECT  6.38 39.888 6.421 40.728 ;
     RECT  5.785 166.272 6.421 166.488 ;
     RECT  6.284 76.752 6.428 133.608 ;
     RECT  5.509 10.512 6.433 10.536 ;
     RECT  4.853 12.528 6.433 12.552 ;
     RECT  6.077 66.672 6.437 66.696 ;
     RECT  5.699 192.048 6.437 192.072 ;
     RECT  5.465 200.592 6.437 200.616 ;
     RECT  6.421 39.888 6.467 41.64 ;
     RECT  6.433 10.32 6.473 10.536 ;
     RECT  6.325 155.52 6.473 156.744 ;
     RECT  5.101 233.136 6.473 233.16 ;
     RECT  5.929 74.592 6.476 74.952 ;
     RECT  6.428 76.56 6.476 133.608 ;
     RECT  5.249 167.52 6.476 167.544 ;
     RECT  6.373 32.448 6.509 32.472 ;
     RECT  6.221 134.688 6.509 144.936 ;
     RECT  5.989 148.128 6.515 153.816 ;
     RECT  6.433 12.336 6.517 12.552 ;
     RECT  6.505 65.04 6.517 65.064 ;
     RECT  5.465 216.192 6.541 216.216 ;
     RECT  5.465 26.208 6.545 26.232 ;
     RECT  5.884 52.992 6.545 53.016 ;
     RECT  6.509 134.688 6.545 144.792 ;
     RECT  6.515 148.128 6.545 148.632 ;
     RECT  6.077 210.432 6.545 210.936 ;
     RECT  6.517 12.336 6.563 12.792 ;
     RECT  6.476 167.52 6.563 168.024 ;
     RECT  5.465 183.408 6.565 186.36 ;
     RECT  6.293 14.208 6.609 14.232 ;
     RECT  6.517 65.04 6.617 65.544 ;
     RECT  6.541 30.72 6.625 30.744 ;
     RECT  6.473 156.192 6.649 156.744 ;
     RECT  5.933 157.728 6.649 157.752 ;
     RECT  6.131 181.632 6.653 181.656 ;
     RECT  6.293 219.984 6.653 220.008 ;
     RECT  6.421 165.888 6.661 166.488 ;
     RECT  6.563 167.52 6.661 167.832 ;
     RECT  6.545 148.128 6.689 148.488 ;
     RECT  5.861 177.264 6.689 177.288 ;
     RECT  6.541 216.192 6.689 216.888 ;
     RECT  6.397 37.632 6.749 37.656 ;
     RECT  6.371 170.304 6.755 172.728 ;
     RECT  6.577 62.784 6.761 62.808 ;
     RECT  6.221 146.112 6.797 147.048 ;
     RECT  6.755 170.304 6.803 172.344 ;
     RECT  6.749 37.632 6.833 38.184 ;
     RECT  6.617 65.52 6.833 65.544 ;
     RECT  6.689 148.128 6.833 148.392 ;
     RECT  6.005 160.416 6.865 160.44 ;
     RECT  6.565 183.12 6.865 186.36 ;
     RECT  5.027 190.128 6.865 190.2 ;
     RECT  6.401 208.608 6.865 208.632 ;
     RECT  6.649 156.192 6.901 157.752 ;
     RECT  6.113 193.584 6.997 193.944 ;
     RECT  5.249 28.464 7.052 28.488 ;
     RECT  6.077 67.776 7.081 68.808 ;
     RECT  6.476 74.592 7.081 133.608 ;
     RECT  6.997 193.584 7.117 194.76 ;
     RECT  7.081 67.776 7.141 68.952 ;
     RECT  6.369 164.592 7.153 164.808 ;
     RECT  6.131 204.288 7.189 204.456 ;
     RECT  6.083 205.536 7.189 205.56 ;
     RECT  6.524 213.696 7.189 213.72 ;
     RECT  6.149 202.368 7.217 202.872 ;
     RECT  6.901 70.464 7.261 70.488 ;
     RECT  7.093 71.856 7.261 71.88 ;
     RECT  6.275 174.192 7.369 174.504 ;
     RECT  4.853 175.536 7.369 175.56 ;
     RECT  6.433 212.112 7.369 212.28 ;
     RECT  7.189 213.696 7.369 213.768 ;
     RECT  6.797 146.16 7.405 147.048 ;
     RECT  5.321 180.432 7.469 180.456 ;
     RECT  6.515 149.952 7.477 153.816 ;
     RECT  7.052 28.416 7.573 28.488 ;
     RECT  6.901 156.192 7.585 158.52 ;
     RECT  6.419 162.48 7.585 162.936 ;
     RECT  7.573 28.416 7.621 28.968 ;
     RECT  6.179 7.44 7.669 7.464 ;
     RECT  7.513 72.912 7.669 72.936 ;
     RECT  7.081 74.352 7.669 133.608 ;
     RECT  7.585 162.24 7.669 162.936 ;
     RECT  7.141 67.536 7.693 68.952 ;
     RECT  7.669 72.912 7.729 133.608 ;
     RECT  6.545 134.688 7.729 144.312 ;
     RECT  7.477 149.76 7.729 153.816 ;
     RECT  7.669 7.248 7.808 7.464 ;
     RECT  6.469 8.976 7.808 9 ;
     RECT  6.473 10.32 7.808 10.344 ;
     RECT  6.563 12.528 7.808 12.792 ;
     RECT  7.621 28.416 7.808 29.064 ;
     RECT  5.843 34.896 7.808 34.92 ;
     RECT  6.833 37.632 7.808 37.656 ;
     RECT  6.467 41.616 7.808 41.64 ;
     RECT  7.621 44.352 7.808 44.376 ;
     RECT  6.005 47.856 7.808 47.88 ;
     RECT  6.077 56.4 7.808 56.424 ;
     RECT  6.973 63.264 7.808 63.288 ;
     RECT  7.693 67.536 7.808 69.048 ;
     RECT  7.261 70.464 7.808 71.88 ;
     RECT  7.729 72.912 7.808 144.312 ;
     RECT  7.405 146.16 7.808 147.096 ;
     RECT  6.833 148.224 7.808 148.392 ;
     RECT  7.729 149.76 7.808 154.104 ;
     RECT  7.585 156.192 7.808 159.096 ;
     RECT  6.865 160.272 7.808 160.44 ;
     RECT  7.669 162.24 7.808 162.984 ;
     RECT  7.153 164.256 7.808 164.808 ;
     RECT  6.661 165.888 7.808 167.832 ;
     RECT  6.803 171.216 7.808 172.344 ;
     RECT  7.369 174.192 7.808 175.56 ;
     RECT  7.297 178.416 7.808 178.44 ;
     RECT  7.469 180.144 7.808 180.456 ;
     RECT  6.865 183.12 7.808 186.408 ;
     RECT  6.077 187.776 7.808 188.28 ;
     RECT  6.865 190.128 7.808 190.44 ;
     RECT  7.117 193.584 7.808 194.952 ;
     RECT  6.364 197.952 7.808 198.792 ;
     RECT  7.513 200.64 7.808 200.664 ;
     RECT  7.217 201.792 7.808 202.872 ;
     RECT  7.189 204.288 7.808 205.56 ;
     RECT  6.401 207.264 7.808 207.48 ;
     RECT  6.865 208.608 7.808 209.064 ;
     RECT  6.545 210.432 7.808 210.648 ;
     RECT  7.369 212.112 7.808 213.768 ;
     RECT  6.689 216.864 7.808 216.888 ;
     RECT  6.149 221.28 7.808 221.304 ;
     RECT  7.765 223.632 7.808 223.656 ;
     RECT  6.371 226.32 7.808 228.024 ;
     RECT  7.297 230.88 7.808 230.904 ;
     RECT  7.397 231.984 7.808 232.008 ;
     RECT  5.825 234.144 7.808 234.168 ;
     RECT  6.316 238.896 7.808 239.88 ;
     RECT  7.808 2.148 7.912 244.092 ;
     RECT  7.912 2.418 8.104 243.822 ;
     RECT  8.104 216.864 8.245 217.224 ;
     RECT  8.104 162.912 8.273 163.704 ;
     RECT  8.104 226.32 8.291 228.024 ;
     RECT  8.104 184.848 8.381 184.872 ;
     RECT  8.104 165.552 8.387 165.576 ;
     RECT  8.104 151.296 8.417 154.104 ;
     RECT  8.104 67.536 8.461 71.448 ;
     RECT  8.461 67.536 8.483 69.576 ;
     RECT  8.104 166.944 8.525 167.832 ;
     RECT  8.104 183.12 8.525 183.432 ;
     RECT  8.104 213.168 8.579 213.192 ;
     RECT  8.104 237.12 8.627 237.144 ;
     RECT  8.245 216.864 8.675 216.888 ;
     RECT  8.291 227.184 8.723 228.024 ;
     RECT  8.461 70.608 8.741 71.448 ;
     RECT  8.104 72.912 8.741 147.096 ;
     RECT  8.104 50.112 8.771 50.136 ;
     RECT  8.741 74.112 8.771 147.096 ;
     RECT  8.104 212.112 8.771 212.136 ;
     RECT  8.741 70.656 8.921 71.448 ;
     RECT  8.921 70.752 8.993 71.448 ;
     RECT  8.273 163.68 8.993 163.704 ;
     RECT  8.771 74.112 9.065 145.08 ;
     RECT  8.993 70.752 9.101 71.208 ;
     RECT  8.483 67.536 9.137 68.712 ;
     RECT  9.065 74.112 9.137 78.696 ;
     RECT  8.104 159.6 9.137 160.296 ;
     RECT  8.104 11.328 9.155 11.352 ;
     RECT  8.104 204.288 9.155 205.272 ;
     RECT  8.417 151.968 9.169 154.104 ;
     RECT  8.104 157.536 9.169 158.136 ;
     RECT  8.104 148.32 9.181 149.688 ;
     RECT  9.137 74.112 9.209 77.16 ;
     RECT  8.525 167.712 9.209 167.832 ;
     RECT  9.137 160.272 9.251 160.296 ;
     RECT  9.169 157.536 9.277 158.376 ;
     RECT  9.137 67.584 9.281 68.712 ;
     RECT  8.723 227.184 9.299 227.208 ;
     RECT  9.277 157.44 9.313 158.376 ;
     RECT  9.065 79.68 9.317 145.08 ;
     RECT  9.169 151.968 9.317 154.152 ;
     RECT  9.281 68.064 9.353 68.568 ;
     RECT  8.771 146.16 9.353 147.096 ;
     RECT  9.353 68.064 9.388 68.472 ;
     RECT  8.104 32.352 9.395 32.376 ;
     RECT  8.104 234.144 9.395 234.168 ;
     RECT  9.313 157.296 9.413 158.376 ;
     RECT  9.181 148.608 9.457 149.688 ;
     RECT  9.101 71.184 9.461 71.208 ;
     RECT  8.104 64.416 9.491 64.44 ;
     RECT  9.457 148.608 9.497 150.6 ;
     RECT  9.413 157.296 9.497 158.472 ;
     RECT  9.317 151.968 9.533 154.056 ;
     RECT  9.353 146.16 9.539 147 ;
     RECT  9.493 225.744 9.577 225.768 ;
     RECT  8.104 186.384 9.731 186.408 ;
     RECT  8.104 174.192 9.779 175.464 ;
     RECT  9.313 164.208 9.781 164.232 ;
     RECT  9.781 164.208 9.785 164.712 ;
     RECT  9.317 79.68 9.821 141.432 ;
     RECT  8.104 44.352 9.875 44.376 ;
     RECT  9.781 155.328 9.889 155.544 ;
     RECT  9.785 164.256 9.893 164.712 ;
     RECT  9.889 155.328 9.925 155.688 ;
     RECT  9.779 175.44 9.961 175.464 ;
     RECT  9.497 149.712 9.965 150.6 ;
     RECT  9.385 165.84 9.971 165.864 ;
     RECT  9.209 74.592 10.109 77.16 ;
     RECT  9.965 149.712 10.109 149.736 ;
     RECT  10.109 74.592 10.145 75 ;
     RECT  9.388 68.352 10.217 68.472 ;
     RECT  9.317 142.464 10.217 145.08 ;
     RECT  10.217 68.352 10.259 68.376 ;
     RECT  10.109 75.984 10.289 77.16 ;
     RECT  9.137 78.24 10.357 78.696 ;
     RECT  9.821 79.68 10.357 127.128 ;
     RECT  10.217 142.464 10.361 143.832 ;
     RECT  10.289 76.752 10.429 77.16 ;
     RECT  10.357 78.24 10.429 127.128 ;
     RECT  10.213 159.984 10.433 160.008 ;
     RECT  9.497 157.296 10.501 158.136 ;
     RECT  10.429 212.064 10.547 212.088 ;
     RECT  8.104 202.848 10.595 202.872 ;
     RECT  10.501 148.8 10.613 148.824 ;
     RECT  9.539 146.4 10.645 147 ;
     RECT  10.645 146.4 10.717 147.336 ;
     RECT  9.533 152.448 10.717 153.768 ;
     RECT  9.893 164.256 10.721 164.52 ;
     RECT  9.925 155.328 10.787 156.168 ;
     RECT  9.133 13.632 10.883 13.656 ;
     RECT  9.821 128.112 10.901 141.432 ;
     RECT  10.213 162.192 10.901 162.216 ;
     RECT  8.104 197.952 10.931 198.792 ;
     RECT  10.717 151.872 10.933 153.768 ;
     RECT  10.787 155.328 10.933 155.688 ;
     RECT  10.361 142.464 11.009 143.256 ;
     RECT  10.717 146.4 11.045 147.384 ;
     RECT  10.429 76.752 11.077 127.128 ;
     RECT  10.901 128.112 11.077 139.992 ;
     RECT  10.931 198.384 11.123 198.792 ;
     RECT  10.901 141.12 11.185 141.432 ;
     RECT  11.185 141.12 11.221 141.48 ;
     RECT  11.009 142.464 11.221 142.92 ;
     RECT  10.217 144.912 11.257 145.08 ;
     RECT  11.045 146.4 11.257 147 ;
     RECT  10.501 157.296 11.369 158.616 ;
     RECT  11.077 76.752 11.377 139.992 ;
     RECT  9.961 175.44 11.411 175.56 ;
     RECT  11.369 157.296 11.441 157.8 ;
     RECT  11.257 144.912 11.473 147 ;
     RECT  11.149 150.768 11.477 150.792 ;
     RECT  10.933 151.872 11.549 155.688 ;
     RECT  8.104 209.04 11.699 209.064 ;
     RECT  9.155 205.248 11.729 205.272 ;
     RECT  11.473 144.72 11.765 147 ;
     RECT  11.221 148.944 11.765 149.736 ;
     RECT  11.765 148.944 11.833 148.968 ;
     RECT  11.549 152.448 11.837 155.688 ;
     RECT  11.377 89.424 11.905 139.992 ;
     RECT  11.221 141.12 11.905 142.92 ;
     RECT  11.905 89.424 11.981 142.92 ;
     RECT  11.473 164.208 12.053 164.232 ;
     RECT  11.981 89.424 12.089 142.488 ;
     RECT  10.501 184.944 12.131 184.968 ;
     RECT  11.941 159.648 12.157 159.672 ;
     RECT  11.123 198.384 12.179 198.408 ;
     RECT  11.833 148.8 12.193 148.968 ;
     RECT  12.265 161.568 12.301 161.592 ;
     RECT  11.765 146.4 12.337 147 ;
     RECT  12.157 159.648 12.445 160.584 ;
     RECT  12.301 161.568 12.445 162.168 ;
     RECT  11.377 76.752 12.469 88.344 ;
     RECT  12.121 150.912 12.589 150.936 ;
     RECT  12.481 156.432 12.589 156.456 ;
     RECT  11.441 157.488 12.589 157.8 ;
     RECT  12.589 156.432 12.661 157.8 ;
     RECT  12.445 159.648 12.757 162.168 ;
     RECT  12.337 146.4 12.769 147.336 ;
     RECT  8.741 72.912 12.805 72.936 ;
     RECT  11.837 152.448 12.805 155.448 ;
     RECT  12.661 156.432 12.805 158.424 ;
     RECT  12.469 76.752 12.841 88.44 ;
     RECT  12.089 89.424 12.841 120.6 ;
     RECT  12.089 121.584 12.949 142.488 ;
     RECT  12.157 143.568 12.949 143.592 ;
     RECT  12.949 121.584 13.093 143.688 ;
     RECT  11.765 144.72 13.093 145.368 ;
     RECT  12.769 146.4 13.093 147.528 ;
     RECT  11.401 57.312 13.208 57.336 ;
     RECT  12.553 69.792 13.208 69.816 ;
     RECT  12.805 72.432 13.208 72.936 ;
     RECT  10.145 74.592 13.208 74.616 ;
     RECT  12.841 76.752 13.208 120.6 ;
     RECT  13.093 121.584 13.208 147.528 ;
     RECT  12.193 148.56 13.208 148.968 ;
     RECT  12.589 150.72 13.208 151.128 ;
     RECT  12.805 152.448 13.208 158.424 ;
     RECT  12.757 159.6 13.208 162.168 ;
     RECT  9.209 167.712 13.208 167.736 ;
     RECT  9.779 174.192 13.208 174.216 ;
     RECT  11.411 175.44 13.208 175.464 ;
     RECT  8.525 183.408 13.208 183.432 ;
     RECT  8.104 194.736 13.208 194.76 ;
     RECT  12.805 205.2 13.208 205.224 ;
     RECT  8.104 207.264 13.208 207.288 ;
     RECT  8.104 223.632 13.208 223.656 ;
     RECT  13.208 2.148 13.312 244.092 ;
     RECT  13.312 2.418 13.504 243.822 ;
     RECT  13.504 150.72 13.619 153.768 ;
     RECT  13.504 80.544 13.66 143.448 ;
     RECT  13.504 154.848 13.673 155.592 ;
     RECT  13.504 72.432 13.715 72.456 ;
     RECT  13.504 144.72 13.781 147.336 ;
     RECT  13.619 150.72 13.781 153.384 ;
     RECT  13.504 77.904 13.889 78.936 ;
     RECT  13.504 159.648 14.105 160.728 ;
     RECT  14.105 160.512 14.141 160.728 ;
     RECT  13.781 144.72 14.213 147 ;
     RECT  13.889 78.144 14.285 78.936 ;
     RECT  13.504 223.632 14.291 223.656 ;
     RECT  13.781 151.296 14.393 153.384 ;
     RECT  13.66 80.592 14.465 143.448 ;
     RECT  13.504 183.408 14.531 183.432 ;
     RECT  13.504 156.672 14.533 157.944 ;
     RECT  14.285 78.432 14.645 78.936 ;
     RECT  13.504 164.448 14.681 164.472 ;
     RECT  13.673 155.424 14.753 155.592 ;
     RECT  14.753 155.52 14.789 155.592 ;
     RECT  14.465 83.808 14.825 143.448 ;
     RECT  13.504 161.856 14.857 162.12 ;
     RECT  14.857 161.856 14.933 162.408 ;
     RECT  14.825 83.808 15.005 141.432 ;
     RECT  13.504 148.704 15.005 149.736 ;
     RECT  14.933 162.048 15.037 162.408 ;
     RECT  14.141 160.704 15.041 160.728 ;
     RECT  14.825 142.464 15.145 143.448 ;
     RECT  15.005 149.712 15.181 149.736 ;
     RECT  13.504 194.736 15.185 194.76 ;
     RECT  14.533 156.672 15.257 158.904 ;
     RECT  15.037 162.048 15.257 162.456 ;
     RECT  14.393 151.296 15.401 151.32 ;
     RECT  15.145 142.464 15.443 143.496 ;
     RECT  14.213 146.16 15.469 147 ;
     RECT  15.005 148.704 15.469 148.728 ;
     RECT  15.181 149.712 15.509 150.072 ;
     RECT  15.005 83.808 15.635 141.144 ;
     RECT  14.645 78.912 15.683 78.936 ;
     RECT  15.469 146.16 15.689 148.728 ;
     RECT  14.393 152.352 15.721 153.384 ;
     RECT  15.443 143.232 15.793 143.496 ;
     RECT  14.465 80.592 15.829 82.392 ;
     RECT  15.793 143.232 15.833 143.592 ;
     RECT  14.213 144.72 15.865 145.08 ;
     RECT  13.504 57.312 15.875 57.336 ;
     RECT  15.721 152.16 15.925 153.384 ;
     RECT  15.257 156.672 15.925 157.944 ;
     RECT  15.833 143.424 15.937 143.592 ;
     RECT  15.865 144.72 15.937 145.32 ;
     RECT  15.257 162.048 15.941 162.408 ;
     RECT  15.925 152.16 15.971 153.864 ;
     RECT  14.789 155.568 15.973 155.592 ;
     RECT  15.925 156.624 15.973 157.944 ;
     RECT  15.509 149.712 16.013 149.736 ;
     RECT  15.973 155.568 16.013 157.944 ;
     RECT  15.689 146.4 16.085 148.728 ;
     RECT  15.829 80.592 16.157 82.584 ;
     RECT  15.941 162.384 16.157 162.408 ;
     RECT  13.504 167.712 16.307 167.736 ;
     RECT  15.971 152.448 16.369 153.864 ;
     RECT  16.297 160.8 16.441 160.824 ;
     RECT  15.635 83.808 16.453 140.904 ;
     RECT  16.441 160.8 16.625 161.352 ;
     RECT  16.085 148.704 16.657 148.728 ;
     RECT  16.657 148.704 16.661 149.208 ;
     RECT  16.369 152.448 16.697 154.296 ;
     RECT  16.013 155.568 16.697 157.896 ;
     RECT  16.261 194.4 16.739 194.424 ;
     RECT  16.453 83.616 16.765 140.904 ;
     RECT  16.625 160.992 16.805 161.352 ;
     RECT  15.937 143.424 16.837 145.32 ;
     RECT  16.697 155.568 16.841 156.696 ;
     RECT  16.765 83.472 16.873 140.904 ;
     RECT  16.805 160.992 16.877 161.256 ;
     RECT  16.837 142.704 16.949 145.32 ;
     RECT  16.877 161.232 16.985 161.256 ;
     RECT  16.873 83.472 17.053 141.384 ;
     RECT  16.949 142.704 17.053 145.08 ;
     RECT  16.085 146.4 17.053 147.192 ;
     RECT  17.053 83.472 17.057 145.08 ;
     RECT  16.661 148.8 17.057 149.208 ;
     RECT  16.157 80.592 17.161 82.392 ;
     RECT  17.057 83.472 17.161 142.488 ;
     RECT  17.125 159.12 17.161 159.624 ;
     RECT  16.841 155.568 17.165 156.648 ;
     RECT  17.161 80.592 17.201 142.488 ;
     RECT  17.161 158.496 17.209 159.624 ;
     RECT  17.209 159.6 17.212 159.624 ;
     RECT  17.057 144.24 17.237 145.08 ;
     RECT  17.201 141.84 17.273 142.488 ;
     RECT  17.209 158.496 17.309 158.52 ;
     RECT  17.201 80.592 17.345 140.808 ;
     RECT  17.057 148.896 17.597 149.208 ;
     RECT  17.053 146.4 18.025 147.288 ;
     RECT  17.629 151.056 18.097 151.08 ;
     RECT  18.025 146.4 18.205 147.576 ;
     RECT  18.097 151.056 18.277 151.368 ;
     RECT  16.697 154.272 18.421 154.296 ;
     RECT  17.165 155.568 18.421 155.592 ;
     RECT  13.504 69.792 18.608 69.816 ;
     RECT  13.504 74.592 18.608 74.616 ;
     RECT  13.504 76.752 18.608 76.776 ;
     RECT  17.345 80.592 18.608 138.312 ;
     RECT  17.345 139.968 18.608 140.808 ;
     RECT  17.273 142.08 18.608 142.488 ;
     RECT  17.237 144.528 18.608 145.08 ;
     RECT  18.205 146.4 18.608 147.864 ;
     RECT  17.597 149.184 18.608 149.208 ;
     RECT  18.277 151.056 18.608 151.416 ;
     RECT  16.697 152.448 18.608 153.288 ;
     RECT  18.421 154.272 18.608 155.592 ;
     RECT  13.504 174.192 18.608 174.216 ;
     RECT  13.504 175.536 18.608 175.56 ;
     RECT  18.608 2.148 18.712 244.092 ;
     RECT  18.712 2.418 18.904 243.822 ;
     RECT  18.904 140.208 18.965 140.808 ;
     RECT  18.904 155.04 19.109 155.064 ;
     RECT  18.904 151.056 19.145 151.08 ;
     RECT  18.904 84.432 19.325 136.968 ;
     RECT  18.904 76.656 19.469 76.776 ;
     RECT  18.904 147.504 19.469 147.576 ;
     RECT  18.904 144.24 19.505 145.08 ;
     RECT  18.904 142.08 19.541 142.488 ;
     RECT  18.965 140.448 19.649 140.808 ;
     RECT  19.505 144.528 19.685 145.08 ;
     RECT  19.649 140.448 19.715 140.76 ;
     RECT  18.904 138.288 20.005 139.176 ;
     RECT  19.541 142.08 20.009 142.2 ;
     RECT  19.325 84.576 20.041 136.968 ;
     RECT  20.041 84.576 20.053 137.016 ;
     RECT  20.005 138.288 20.053 139.368 ;
     RECT  20.009 142.176 20.081 142.2 ;
     RECT  20.053 84.576 20.147 139.368 ;
     RECT  20.147 139.104 20.243 139.368 ;
     RECT  19.715 140.544 20.261 140.76 ;
     RECT  20.147 84.576 20.369 137.496 ;
     RECT  19.469 147.552 20.369 147.576 ;
     RECT  20.261 140.592 20.441 140.76 ;
     RECT  20.441 140.592 20.513 140.616 ;
     RECT  18.904 174.192 21.085 174.216 ;
     RECT  21.085 174.096 21.125 174.216 ;
     RECT  18.904 74.592 21.517 74.616 ;
     RECT  19.469 76.656 21.587 76.68 ;
     RECT  21.517 74.592 21.601 74.664 ;
     RECT  20.369 84.576 21.737 136.2 ;
     RECT  21.601 74.592 21.845 74.616 ;
     RECT  21.737 88.896 22.061 136.2 ;
     RECT  21.737 84.576 22.201 87.816 ;
     RECT  21.125 174.096 22.453 174.12 ;
     RECT  18.904 175.536 22.453 175.56 ;
     RECT  22.453 174.096 22.499 175.56 ;
     RECT  22.499 175.008 22.673 175.56 ;
     RECT  18.904 80.496 22.813 81.768 ;
     RECT  22.813 80.496 22.835 81.912 ;
     RECT  22.201 84.288 22.849 87.816 ;
     RECT  22.835 81.312 22.853 81.912 ;
     RECT  22.061 89.136 22.931 136.2 ;
     RECT  22.673 175.536 22.997 175.56 ;
     RECT  22.853 81.408 24.008 81.912 ;
     RECT  22.849 84.288 24.008 87.912 ;
     RECT  22.931 89.136 24.008 133.512 ;
     RECT  22.931 135.072 24.008 136.2 ;
     RECT  20.369 137.472 24.008 137.496 ;
     RECT  19.685 145.056 24.008 145.08 ;
     RECT  18.904 152.448 24.008 152.472 ;
     RECT  22.453 158.544 24.008 158.568 ;
     RECT  24.008 2.148 24.112 244.092 ;
     RECT  24.112 2.418 24.304 243.822 ;
     RECT  24.304 81.408 24.419 81.912 ;
     RECT  24.304 89.184 24.437 114.12 ;
     RECT  24.304 118.608 24.467 119.496 ;
     RECT  24.304 121.152 24.545 126.216 ;
     RECT  24.419 81.408 24.563 81.432 ;
     RECT  24.304 115.152 24.617 117.576 ;
     RECT  24.304 84.288 24.659 87.912 ;
     RECT  24.437 89.184 24.707 113.544 ;
     RECT  24.617 115.152 24.797 117.528 ;
     RECT  24.707 89.184 25.139 113.496 ;
     RECT  24.304 135.072 25.139 136.008 ;
     RECT  24.304 133.44 25.187 133.512 ;
     RECT  25.139 96.816 25.235 113.496 ;
     RECT  25.235 96.816 25.273 112.152 ;
     RECT  25.139 89.184 25.283 95.496 ;
     RECT  24.545 121.152 25.283 125.208 ;
     RECT  24.659 84.288 25.331 87.576 ;
     RECT  24.304 130.224 25.373 131.88 ;
     RECT  25.331 85.392 25.379 87.576 ;
     RECT  25.379 87.552 25.427 87.576 ;
     RECT  25.187 133.488 25.715 133.512 ;
     RECT  25.283 89.184 25.733 91.608 ;
     RECT  25.733 89.28 25.763 91.608 ;
     RECT  25.373 130.464 25.763 131.88 ;
     RECT  25.283 92.688 25.769 95.496 ;
     RECT  24.545 126.192 25.769 126.216 ;
     RECT  25.763 89.28 25.805 89.304 ;
     RECT  24.304 128.592 25.811 129.144 ;
     RECT  25.379 85.392 25.859 86.28 ;
     RECT  24.797 115.152 25.859 115.944 ;
     RECT  25.763 90.288 25.907 91.608 ;
     RECT  25.273 100.08 26.243 112.152 ;
     RECT  25.907 90.288 26.291 91.08 ;
     RECT  26.243 100.56 26.291 112.152 ;
     RECT  25.273 96.816 26.387 99.048 ;
     RECT  26.291 100.56 26.435 108.744 ;
     RECT  26.291 90.912 26.483 91.08 ;
     RECT  25.283 121.536 26.525 125.208 ;
     RECT  24.467 118.608 26.773 119.448 ;
     RECT  25.769 92.688 26.813 92.712 ;
     RECT  25.331 84.288 26.819 84.312 ;
     RECT  26.435 102.672 26.849 108.744 ;
     RECT  25.859 85.92 26.867 86.28 ;
     RECT  26.387 97.68 26.915 99.048 ;
     RECT  26.525 121.536 26.915 124.68 ;
     RECT  26.867 85.92 26.963 85.944 ;
     RECT  25.763 130.464 27.065 131.304 ;
     RECT  25.769 93.744 27.389 95.496 ;
     RECT  26.849 105.888 27.425 108.744 ;
     RECT  26.291 109.728 27.497 112.152 ;
     RECT  27.497 109.728 27.569 109.752 ;
     RECT  26.915 98.64 27.677 99.048 ;
     RECT  24.797 117.12 27.965 117.528 ;
     RECT  26.435 100.56 28.289 101.592 ;
     RECT  26.483 91.056 29.408 91.08 ;
     RECT  27.389 93.744 29.408 93.768 ;
     RECT  27.389 94.848 29.408 95.496 ;
     RECT  27.677 98.928 29.408 99.048 ;
     RECT  28.289 100.56 29.408 101.4 ;
     RECT  26.849 102.672 29.408 104.568 ;
     RECT  27.425 105.888 29.408 108.264 ;
     RECT  27.497 110.736 29.408 112.152 ;
     RECT  25.235 113.184 29.408 113.496 ;
     RECT  25.859 115.152 29.408 115.656 ;
     RECT  27.965 117.12 29.408 117.144 ;
     RECT  26.773 118.608 29.408 119.496 ;
     RECT  26.915 121.536 29.408 124.392 ;
     RECT  25.811 128.592 29.408 128.616 ;
     RECT  27.065 130.992 29.408 131.304 ;
     RECT  25.139 135.072 29.408 135.096 ;
     RECT  24.304 137.472 29.408 137.496 ;
     RECT  24.304 145.056 29.408 145.08 ;
     RECT  24.304 152.448 29.408 152.472 ;
     RECT  24.304 158.544 29.408 158.568 ;
     RECT  29.408 2.148 29.512 244.092 ;
     RECT  29.512 2.418 29.704 243.822 ;
     RECT  29.704 117.12 30.769 117.144 ;
     RECT  30.769 117.024 30.809 117.144 ;
     RECT  29.704 118.608 31.061 119.496 ;
     RECT  29.704 121.536 32.029 124.392 ;
     RECT  32.029 121.296 32.149 124.392 ;
     RECT  29.704 105.888 32.213 108.264 ;
     RECT  32.137 119.664 32.221 119.688 ;
     RECT  29.704 137.472 33.113 137.496 ;
     RECT  29.704 135.072 33.581 135.096 ;
     RECT  29.704 91.056 34.808 91.08 ;
     RECT  29.704 93.744 34.808 93.768 ;
     RECT  29.704 94.848 34.808 95.496 ;
     RECT  29.704 98.928 34.808 98.952 ;
     RECT  29.704 100.56 34.808 101.4 ;
     RECT  29.704 102.672 34.808 104.568 ;
     RECT  32.213 105.888 34.808 107.544 ;
     RECT  29.704 110.736 34.808 112.152 ;
     RECT  29.704 113.184 34.808 113.208 ;
     RECT  29.704 115.152 34.808 115.656 ;
     RECT  30.809 117.024 34.808 117.048 ;
     RECT  31.061 118.608 34.808 118.632 ;
     RECT  32.149 121.296 34.808 125.112 ;
     RECT  29.704 128.592 34.808 128.616 ;
     RECT  29.704 130.992 34.808 131.304 ;
     RECT  29.704 145.104 34.808 145.128 ;
     RECT  29.704 152.448 34.808 152.472 ;
     RECT  29.704 158.544 34.808 158.568 ;
     RECT  34.808 2.148 34.912 244.092 ;
     RECT  34.912 2.418 35.104 243.822 ;
     RECT  35.104 115.152 35.309 115.656 ;
     RECT  35.104 110.736 36.209 112.152 ;
     RECT  35.104 131.088 37.073 131.304 ;
     RECT  35.104 93.744 37.501 93.768 ;
     RECT  37.501 93.744 37.829 93.864 ;
     RECT  35.104 122.448 38.225 125.112 ;
     RECT  37.073 131.136 38.401 131.304 ;
     RECT  35.309 115.152 38.549 115.176 ;
     RECT  35.104 91.056 40.208 91.08 ;
     RECT  37.829 93.84 40.208 93.864 ;
     RECT  35.104 94.848 40.208 95.496 ;
     RECT  35.104 98.928 40.208 98.952 ;
     RECT  35.104 100.56 40.208 101.4 ;
     RECT  35.104 102.672 40.208 104.568 ;
     RECT  35.104 105.888 40.208 107.544 ;
     RECT  36.209 110.736 40.208 111.576 ;
     RECT  35.104 113.184 40.208 113.208 ;
     RECT  35.104 117.12 40.208 117.144 ;
     RECT  35.104 118.608 40.208 118.632 ;
     RECT  35.104 121.296 40.208 121.32 ;
     RECT  38.225 123.024 40.208 125.112 ;
     RECT  35.104 128.592 40.208 128.616 ;
     RECT  38.401 130.992 40.208 131.304 ;
     RECT  35.104 145.104 40.208 145.128 ;
     RECT  35.104 152.448 40.208 152.472 ;
     RECT  35.104 158.544 40.208 158.568 ;
     RECT  40.208 2.148 40.312 244.092 ;
     RECT  40.312 2.418 40.504 243.822 ;
     RECT  40.504 158.544 42.721 158.568 ;
     RECT  40.504 117.12 42.757 117.144 ;
     RECT  42.757 117.024 42.797 117.144 ;
     RECT  42.721 158.448 42.869 158.568 ;
     RECT  40.504 123.024 43.517 125.112 ;
     RECT  43.517 124.224 43.885 125.112 ;
     RECT  40.504 91.056 45.608 91.08 ;
     RECT  40.504 93.84 45.608 93.864 ;
     RECT  40.504 94.848 45.608 95.496 ;
     RECT  40.504 98.928 45.608 98.952 ;
     RECT  40.504 100.56 45.608 101.4 ;
     RECT  40.504 102.672 45.608 103.272 ;
     RECT  40.504 104.544 45.608 104.568 ;
     RECT  40.504 105.888 45.608 107.544 ;
     RECT  40.504 110.736 45.608 111.576 ;
     RECT  40.504 113.184 45.608 113.208 ;
     RECT  42.797 117.024 45.608 117.048 ;
     RECT  40.504 118.608 45.608 118.632 ;
     RECT  40.504 121.296 45.608 121.32 ;
     RECT  43.517 123.024 45.608 123.048 ;
     RECT  43.885 124.368 45.608 125.112 ;
     RECT  40.504 128.592 45.608 128.616 ;
     RECT  40.504 130.992 45.608 131.304 ;
     RECT  43.813 143.76 45.608 143.784 ;
     RECT  40.504 145.104 45.608 145.128 ;
     RECT  40.504 152.448 45.608 152.472 ;
     RECT  42.869 158.544 45.608 158.568 ;
     RECT  45.608 2.148 45.712 244.092 ;
     RECT  45.712 2.418 45.904 243.822 ;
     RECT  45.904 158.448 46.787 158.568 ;
     RECT  46.787 158.544 50.677 158.568 ;
     RECT  45.904 91.056 51.008 91.08 ;
     RECT  45.904 93.84 51.008 93.864 ;
     RECT  45.904 94.848 51.008 95.496 ;
     RECT  45.904 98.928 51.008 98.952 ;
     RECT  45.904 100.56 51.008 101.4 ;
     RECT  45.904 102.672 51.008 103.272 ;
     RECT  45.904 104.544 51.008 104.568 ;
     RECT  45.904 105.888 51.008 107.544 ;
     RECT  45.904 111.552 51.008 111.576 ;
     RECT  45.904 113.184 51.008 113.208 ;
     RECT  50.929 115.68 51.008 115.704 ;
     RECT  45.904 117.12 51.008 117.144 ;
     RECT  45.904 118.608 51.008 118.632 ;
     RECT  45.904 121.296 51.008 121.32 ;
     RECT  45.904 123.024 51.008 123.048 ;
     RECT  45.904 124.368 51.008 125.112 ;
     RECT  45.904 128.592 51.008 128.616 ;
     RECT  45.904 130.992 51.008 131.304 ;
     RECT  45.904 143.76 51.008 143.784 ;
     RECT  45.904 145.104 51.008 145.128 ;
     RECT  45.904 152.448 51.008 152.472 ;
     RECT  50.677 158.448 51.008 158.568 ;
     RECT  51.008 2.148 51.112 244.092 ;
     RECT  51.112 2.418 51.304 243.822 ;
     RECT  51.304 93.84 52.453 93.864 ;
     RECT  51.304 94.848 52.453 95.496 ;
     RECT  51.304 115.68 52.549 115.704 ;
     RECT  52.549 115.152 52.633 115.704 ;
     RECT  52.453 93.84 52.645 95.496 ;
     RECT  52.645 93.792 52.691 95.496 ;
     RECT  52.633 115.68 53.843 115.704 ;
     RECT  54.025 136.8 54.109 136.824 ;
     RECT  51.304 91.056 54.425 91.08 ;
     RECT  51.304 158.544 54.613 158.568 ;
     RECT  51.304 117.12 54.709 117.144 ;
     RECT  54.709 117.024 54.749 117.144 ;
     RECT  54.613 158.448 54.749 158.568 ;
     RECT  52.691 93.792 56.408 93.816 ;
     RECT  52.691 94.848 56.408 95.496 ;
     RECT  51.304 98.928 56.408 98.952 ;
     RECT  51.304 100.56 56.408 101.4 ;
     RECT  51.304 102.672 56.408 103.272 ;
     RECT  51.304 104.544 56.408 104.568 ;
     RECT  51.304 105.888 56.408 107.544 ;
     RECT  51.304 111.552 56.408 111.576 ;
     RECT  51.304 113.184 56.408 113.208 ;
     RECT  54.749 117.024 56.408 117.048 ;
     RECT  51.304 118.608 56.408 118.632 ;
     RECT  51.304 121.296 56.408 121.32 ;
     RECT  51.304 123.024 56.408 123.048 ;
     RECT  51.304 124.368 56.408 125.112 ;
     RECT  51.304 128.592 56.408 128.616 ;
     RECT  51.304 130.992 56.408 131.304 ;
     RECT  55.573 137.328 56.408 137.352 ;
     RECT  51.304 143.76 56.408 143.784 ;
     RECT  51.304 145.104 56.408 145.128 ;
     RECT  52.693 150.192 56.408 150.216 ;
     RECT  51.304 152.448 56.408 152.472 ;
     RECT  54.749 158.544 56.408 158.568 ;
     RECT  56.408 2.148 56.512 244.092 ;
     RECT  56.512 2.418 56.704 243.822 ;
     RECT  56.704 158.544 58.669 158.568 ;
     RECT  58.669 158.448 58.773 158.568 ;
     RECT  56.704 93.792 61.808 93.816 ;
     RECT  56.704 94.848 61.808 95.496 ;
     RECT  56.704 98.928 61.808 98.952 ;
     RECT  56.704 100.56 61.808 101.4 ;
     RECT  56.704 102.672 61.808 103.272 ;
     RECT  56.704 104.544 61.808 104.568 ;
     RECT  56.704 105.888 61.808 107.544 ;
     RECT  56.704 111.552 61.808 111.576 ;
     RECT  56.704 113.184 61.808 113.208 ;
     RECT  56.704 117.12 61.808 117.144 ;
     RECT  56.704 118.608 61.808 118.632 ;
     RECT  56.704 121.296 61.808 121.32 ;
     RECT  56.704 123.024 61.808 123.048 ;
     RECT  56.704 124.368 61.808 125.112 ;
     RECT  56.704 128.592 61.808 128.616 ;
     RECT  56.704 130.992 61.808 131.304 ;
     RECT  56.704 143.76 61.808 143.784 ;
     RECT  56.704 145.104 61.808 145.128 ;
     RECT  56.704 150.192 61.808 150.216 ;
     RECT  56.704 152.448 61.808 152.472 ;
     RECT  58.773 158.544 61.808 158.568 ;
     RECT  61.808 2.148 61.912 244.092 ;
     RECT  61.912 2.418 62.104 243.822 ;
     RECT  62.104 117.024 62.741 117.144 ;
     RECT  62.104 158.448 62.741 158.568 ;
     RECT  62.104 93.792 64.541 93.816 ;
     RECT  62.104 105.888 64.973 107.544 ;
     RECT  62.741 158.544 66.661 158.568 ;
     RECT  66.661 158.448 66.697 158.568 ;
     RECT  66.049 93.744 67.208 93.768 ;
     RECT  62.104 94.848 67.208 95.496 ;
     RECT  62.104 98.928 67.208 98.952 ;
     RECT  62.104 100.56 67.208 101.4 ;
     RECT  62.104 102.672 67.208 103.272 ;
     RECT  62.104 104.544 67.208 104.568 ;
     RECT  64.973 105.888 67.208 105.912 ;
     RECT  64.973 107.52 67.208 107.544 ;
     RECT  62.104 111.552 67.208 111.576 ;
     RECT  62.104 113.184 67.208 113.208 ;
     RECT  62.741 117.024 67.208 117.048 ;
     RECT  62.104 118.608 67.208 118.632 ;
     RECT  62.104 121.296 67.208 121.32 ;
     RECT  62.104 123.024 67.208 123.048 ;
     RECT  62.104 124.368 67.208 125.112 ;
     RECT  62.104 128.592 67.208 128.616 ;
     RECT  62.104 130.992 67.208 131.304 ;
     RECT  62.104 143.76 67.208 143.784 ;
     RECT  62.104 145.104 67.208 145.128 ;
     RECT  62.104 150.192 67.208 150.216 ;
     RECT  62.104 152.448 67.208 152.472 ;
     RECT  66.697 158.448 67.208 158.664 ;
     RECT  67.208 2.148 67.312 244.092 ;
     RECT  67.312 2.418 67.504 243.822 ;
     RECT  67.504 158.64 67.565 158.664 ;
     RECT  67.504 152.448 69.109 152.472 ;
     RECT  69.073 158.496 69.157 158.52 ;
     RECT  69.109 152.448 70.373 153.336 ;
     RECT  70.373 152.448 71.852 153.192 ;
     RECT  67.504 93.744 72.608 93.768 ;
     RECT  67.504 94.848 72.608 95.496 ;
     RECT  67.504 98.928 72.608 98.952 ;
     RECT  67.504 100.56 72.608 101.4 ;
     RECT  67.504 102.672 72.608 103.272 ;
     RECT  67.504 104.544 72.608 104.568 ;
     RECT  67.504 105.888 72.608 105.912 ;
     RECT  67.504 107.52 72.608 107.544 ;
     RECT  67.504 111.552 72.608 111.576 ;
     RECT  67.504 113.184 72.608 113.208 ;
     RECT  67.504 117.12 72.608 117.144 ;
     RECT  67.504 118.608 72.608 118.632 ;
     RECT  67.504 121.296 72.608 121.32 ;
     RECT  67.504 123.024 72.608 123.048 ;
     RECT  67.504 124.368 72.608 125.112 ;
     RECT  67.504 128.592 72.608 128.616 ;
     RECT  67.504 130.992 72.608 131.304 ;
     RECT  67.504 143.76 72.608 143.784 ;
     RECT  67.504 145.104 72.608 145.128 ;
     RECT  67.504 150.192 72.608 150.216 ;
     RECT  71.852 152.448 72.608 153.336 ;
     RECT  71.893 217.68 72.608 217.704 ;
     RECT  72.608 2.148 72.712 244.092 ;
     RECT  72.712 2.418 72.904 243.822 ;
     RECT  72.904 138.48 73.369 138.504 ;
     RECT  72.904 117.12 74.653 117.144 ;
     RECT  74.653 117.024 74.693 117.144 ;
     RECT  72.904 217.68 76.813 217.704 ;
     RECT  77.845 242.784 77.893 242.808 ;
     RECT  77.845 246.096 77.987 246.12 ;
     RECT  72.904 93.744 78.008 93.768 ;
     RECT  72.904 94.848 78.008 95.496 ;
     RECT  72.904 98.928 78.008 98.952 ;
     RECT  72.904 100.56 78.008 101.4 ;
     RECT  72.904 102.672 78.008 103.272 ;
     RECT  72.904 104.544 78.008 104.568 ;
     RECT  72.904 105.888 78.008 105.912 ;
     RECT  72.904 107.52 78.008 107.544 ;
     RECT  72.904 111.552 78.008 111.576 ;
     RECT  72.904 113.184 78.008 113.208 ;
     RECT  74.693 117.024 78.008 117.048 ;
     RECT  72.904 118.608 78.008 118.632 ;
     RECT  72.904 121.296 78.008 121.32 ;
     RECT  72.904 123.024 78.008 123.048 ;
     RECT  72.904 124.368 78.008 125.112 ;
     RECT  72.904 128.592 78.008 128.616 ;
     RECT  72.904 130.992 78.008 131.304 ;
     RECT  72.904 143.76 78.008 143.784 ;
     RECT  72.904 145.104 78.008 145.128 ;
     RECT  72.904 150.192 78.008 150.216 ;
     RECT  72.904 153.168 78.008 154.104 ;
     RECT  76.813 217.44 78.008 217.704 ;
     RECT  77.893 239.136 78.008 239.16 ;
     RECT  77.893 242.544 78.008 242.808 ;
     RECT  78.008 2.148 78.112 244.092 ;
     RECT  78.112 2.418 78.304 243.822 ;
     RECT  78.304 105.888 80.053 105.912 ;
     RECT  78.304 93.744 80.099 93.768 ;
     RECT  78.304 113.184 80.161 113.208 ;
     RECT  80.053 105.888 80.197 106.056 ;
     RECT  80.161 112.848 80.245 113.208 ;
     RECT  78.304 94.848 83.408 95.496 ;
     RECT  78.304 98.928 83.408 98.952 ;
     RECT  78.304 100.56 83.408 101.4 ;
     RECT  78.304 102.672 83.408 103.272 ;
     RECT  78.304 104.544 83.408 104.568 ;
     RECT  80.197 105.888 83.408 106.536 ;
     RECT  78.304 107.52 83.408 107.544 ;
     RECT  78.304 111.552 83.408 111.576 ;
     RECT  80.245 113.184 83.408 113.208 ;
     RECT  78.304 117.12 83.408 117.144 ;
     RECT  78.304 118.608 83.408 118.632 ;
     RECT  78.304 121.296 83.408 121.32 ;
     RECT  78.304 123.024 83.408 123.048 ;
     RECT  78.304 124.368 83.408 125.112 ;
     RECT  78.304 128.592 83.408 128.616 ;
     RECT  78.304 130.992 83.408 131.304 ;
     RECT  78.304 143.76 83.408 143.784 ;
     RECT  78.304 145.104 83.408 145.128 ;
     RECT  78.304 150.192 83.408 150.216 ;
     RECT  78.304 153.168 83.408 154.104 ;
     RECT  83.408 2.148 83.512 244.092 ;
     RECT  83.512 2.418 83.704 243.822 ;
     RECT  83.704 105.984 85.097 106.536 ;
     RECT  83.704 104.544 85.477 104.568 ;
     RECT  85.097 105.984 85.523 106.392 ;
     RECT  83.704 117.12 86.641 117.144 ;
     RECT  86.641 117.024 86.681 117.144 ;
     RECT  85.477 104.256 87.437 104.568 ;
     RECT  83.704 94.848 88.808 95.496 ;
     RECT  83.704 98.928 88.808 98.952 ;
     RECT  83.704 100.56 88.808 101.4 ;
     RECT  83.704 102.672 88.808 103.272 ;
     RECT  87.437 104.256 88.808 104.28 ;
     RECT  83.704 107.52 88.808 107.544 ;
     RECT  83.704 111.552 88.808 111.576 ;
     RECT  83.704 113.184 88.808 113.208 ;
     RECT  86.681 117.024 88.808 117.048 ;
     RECT  83.704 118.608 88.808 118.632 ;
     RECT  83.704 121.296 88.808 121.32 ;
     RECT  83.704 123.024 88.808 123.048 ;
     RECT  83.704 124.368 88.808 125.112 ;
     RECT  83.704 128.592 88.808 128.616 ;
     RECT  83.704 130.992 88.808 131.304 ;
     RECT  83.704 143.76 88.808 143.784 ;
     RECT  83.704 145.104 88.808 145.128 ;
     RECT  83.704 150.192 88.808 150.216 ;
     RECT  83.704 153.168 88.808 154.104 ;
     RECT  88.808 2.148 88.912 244.092 ;
     RECT  88.912 2.418 89.104 243.822 ;
     RECT  89.104 94.848 94.208 95.496 ;
     RECT  89.104 98.928 94.208 98.952 ;
     RECT  89.104 100.56 94.208 101.4 ;
     RECT  89.104 102.672 94.208 103.272 ;
     RECT  89.104 104.256 94.208 104.28 ;
     RECT  89.104 107.52 94.208 107.544 ;
     RECT  89.104 111.552 94.208 111.576 ;
     RECT  89.104 113.184 94.208 113.208 ;
     RECT  89.104 117.12 94.208 117.144 ;
     RECT  89.104 118.608 94.208 118.632 ;
     RECT  89.104 121.296 94.208 121.32 ;
     RECT  89.104 123.024 94.208 123.048 ;
     RECT  89.104 124.368 94.208 125.112 ;
     RECT  89.104 128.592 94.208 128.616 ;
     RECT  89.104 130.992 94.208 131.304 ;
     RECT  89.104 143.76 94.208 143.784 ;
     RECT  89.104 145.104 94.208 145.128 ;
     RECT  89.104 150.192 94.208 150.216 ;
     RECT  89.104 153.168 94.208 154.104 ;
     RECT  94.208 2.148 94.312 244.092 ;
     RECT  94.312 2.418 94.504 243.822 ;
     RECT  94.504 153.168 97.373 154.104 ;
     RECT  94.504 117.12 98.593 117.144 ;
     RECT  98.593 117.024 98.633 117.144 ;
     RECT  97.373 154.08 98.881 154.104 ;
     RECT  94.504 94.848 99.608 95.496 ;
     RECT  94.504 98.928 99.608 98.952 ;
     RECT  94.504 100.56 99.608 101.4 ;
     RECT  94.504 102.672 99.608 103.272 ;
     RECT  94.504 104.256 99.608 104.28 ;
     RECT  94.504 107.52 99.608 107.544 ;
     RECT  94.504 111.552 99.608 111.576 ;
     RECT  94.504 113.184 99.608 113.208 ;
     RECT  98.633 117.024 99.608 117.048 ;
     RECT  94.504 118.608 99.608 118.632 ;
     RECT  94.504 121.296 99.608 121.32 ;
     RECT  94.504 123.024 99.608 123.048 ;
     RECT  94.504 124.368 99.608 125.112 ;
     RECT  94.504 128.592 99.608 128.616 ;
     RECT  94.504 130.992 99.608 131.304 ;
     RECT  94.504 143.76 99.608 143.784 ;
     RECT  94.504 145.104 99.608 145.128 ;
     RECT  94.504 150.192 99.608 150.216 ;
     RECT  98.881 153.168 99.608 154.104 ;
     RECT  99.608 2.148 99.712 244.092 ;
     RECT  99.712 2.418 99.904 243.822 ;
     RECT  99.904 94.848 105.008 95.496 ;
     RECT  99.904 98.928 105.008 98.952 ;
     RECT  99.904 100.56 105.008 101.4 ;
     RECT  99.904 102.672 105.008 103.272 ;
     RECT  99.904 104.256 105.008 104.28 ;
     RECT  99.904 107.52 105.008 107.544 ;
     RECT  99.904 111.552 105.008 111.576 ;
     RECT  99.904 113.184 105.008 113.208 ;
     RECT  99.904 117.12 105.008 117.144 ;
     RECT  99.904 118.608 105.008 118.632 ;
     RECT  99.904 121.296 105.008 121.32 ;
     RECT  99.904 123.024 105.008 123.048 ;
     RECT  99.904 124.368 105.008 125.112 ;
     RECT  99.904 128.592 105.008 128.616 ;
     RECT  99.904 130.992 105.008 131.304 ;
     RECT  99.904 143.76 105.008 143.784 ;
     RECT  99.904 145.104 105.008 145.128 ;
     RECT  99.904 150.192 105.008 150.216 ;
     RECT  99.904 153.168 105.008 154.104 ;
     RECT  105.008 2.148 105.112 244.092 ;
     RECT  105.112 2.418 105.304 243.822 ;
     RECT  105.304 117.12 106.585 117.144 ;
     RECT  106.585 117.024 106.625 117.144 ;
     RECT  105.304 94.848 110.408 95.496 ;
     RECT  105.304 98.928 110.408 98.952 ;
     RECT  105.304 100.56 110.408 101.4 ;
     RECT  105.304 102.672 110.408 103.272 ;
     RECT  105.304 104.256 110.408 104.28 ;
     RECT  105.304 107.52 110.408 107.544 ;
     RECT  105.304 111.552 110.408 111.576 ;
     RECT  105.304 113.184 110.408 113.208 ;
     RECT  106.625 117.024 110.408 117.048 ;
     RECT  105.304 118.608 110.408 118.632 ;
     RECT  105.304 121.296 110.408 121.32 ;
     RECT  105.304 123.024 110.408 123.048 ;
     RECT  105.304 124.368 110.408 125.112 ;
     RECT  105.304 128.592 110.408 128.616 ;
     RECT  105.304 130.992 110.408 131.304 ;
     RECT  105.304 143.76 110.408 143.784 ;
     RECT  105.304 145.104 110.408 145.128 ;
     RECT  105.304 150.192 110.408 150.216 ;
     RECT  105.304 153.168 110.408 154.104 ;
     RECT  110.408 2.148 110.512 244.092 ;
     RECT  110.512 2.418 110.704 243.822 ;
     RECT  110.704 94.848 115.808 95.496 ;
     RECT  110.704 98.928 115.808 98.952 ;
     RECT  110.704 100.56 115.808 101.4 ;
     RECT  110.704 102.672 115.808 103.272 ;
     RECT  110.704 104.256 115.808 104.28 ;
     RECT  110.704 107.52 115.808 107.544 ;
     RECT  110.704 111.552 115.808 111.576 ;
     RECT  110.704 113.184 115.808 113.208 ;
     RECT  110.704 117.12 115.808 117.144 ;
     RECT  110.704 118.608 115.808 118.632 ;
     RECT  110.704 121.296 115.808 121.32 ;
     RECT  110.704 123.024 115.808 123.048 ;
     RECT  110.704 124.368 115.808 125.112 ;
     RECT  110.704 128.592 115.808 128.616 ;
     RECT  110.704 130.992 115.808 131.304 ;
     RECT  110.704 143.76 115.808 143.784 ;
     RECT  110.704 145.104 115.808 145.128 ;
     RECT  110.704 150.192 115.808 150.216 ;
     RECT  110.704 153.168 115.808 154.104 ;
     RECT  115.808 2.148 115.912 244.092 ;
     RECT  115.912 2.418 116.104 243.822 ;
     RECT  116.104 153.168 117.601 154.104 ;
     RECT  117.601 153.168 117.745 154.248 ;
     RECT  117.745 153.168 117.785 154.296 ;
     RECT  116.104 117.12 118.573 117.144 ;
     RECT  118.573 117.024 118.613 117.144 ;
     RECT  116.104 94.848 121.208 95.496 ;
     RECT  116.104 98.928 121.208 98.952 ;
     RECT  116.104 100.56 121.208 101.4 ;
     RECT  116.104 102.672 121.208 103.272 ;
     RECT  116.104 104.256 121.208 104.28 ;
     RECT  116.104 107.52 121.208 107.544 ;
     RECT  116.104 111.552 121.208 111.576 ;
     RECT  116.104 113.184 121.208 113.208 ;
     RECT  118.613 117.024 121.208 117.048 ;
     RECT  116.104 118.608 121.208 118.632 ;
     RECT  116.104 121.296 121.208 121.32 ;
     RECT  116.104 123.024 121.208 123.048 ;
     RECT  116.104 124.368 121.208 125.112 ;
     RECT  116.104 128.592 121.208 128.616 ;
     RECT  116.104 130.992 121.208 131.304 ;
     RECT  116.104 143.76 121.208 143.784 ;
     RECT  116.104 145.104 121.208 145.128 ;
     RECT  116.104 150.192 121.208 150.216 ;
     RECT  117.785 153.168 121.208 153.192 ;
     RECT  117.785 154.224 121.208 154.296 ;
     RECT  121.208 2.148 121.312 244.092 ;
     RECT  121.312 2.418 121.504 243.822 ;
     RECT  121.504 94.848 126.608 95.496 ;
     RECT  121.504 98.928 126.608 98.952 ;
     RECT  121.504 100.56 126.608 101.4 ;
     RECT  121.504 102.672 126.608 103.272 ;
     RECT  121.504 104.256 126.608 104.28 ;
     RECT  121.504 107.52 126.608 107.544 ;
     RECT  121.504 111.552 126.608 111.576 ;
     RECT  121.504 113.184 126.608 113.208 ;
     RECT  121.504 117.12 126.608 117.144 ;
     RECT  121.504 118.608 126.608 118.632 ;
     RECT  121.504 121.296 126.608 121.32 ;
     RECT  121.504 123.024 126.608 123.048 ;
     RECT  121.504 124.368 126.608 125.112 ;
     RECT  121.504 128.592 126.608 128.616 ;
     RECT  121.504 130.992 126.608 131.304 ;
     RECT  121.504 143.76 126.608 143.784 ;
     RECT  121.504 145.104 126.608 145.128 ;
     RECT  121.504 150.192 126.608 150.216 ;
     RECT  121.504 153.168 126.608 153.192 ;
     RECT  121.504 154.224 126.608 154.296 ;
     RECT  126.608 2.148 126.712 244.092 ;
     RECT  126.712 2.418 126.904 243.822 ;
     RECT  126.904 117.12 130.525 117.144 ;
     RECT  130.525 117.024 130.565 117.144 ;
     RECT  126.904 94.848 132.008 95.496 ;
     RECT  126.904 98.928 132.008 98.952 ;
     RECT  126.904 100.56 132.008 101.4 ;
     RECT  126.904 102.672 132.008 103.272 ;
     RECT  126.904 104.256 132.008 104.28 ;
     RECT  126.904 107.52 132.008 107.544 ;
     RECT  126.904 111.552 132.008 111.576 ;
     RECT  126.904 113.184 132.008 113.208 ;
     RECT  130.565 117.024 132.008 117.048 ;
     RECT  126.904 118.608 132.008 118.632 ;
     RECT  126.904 121.296 132.008 121.32 ;
     RECT  126.904 123.024 132.008 123.048 ;
     RECT  126.904 124.368 132.008 125.112 ;
     RECT  126.904 128.592 132.008 128.616 ;
     RECT  126.904 130.992 132.008 131.304 ;
     RECT  126.904 143.76 132.008 143.784 ;
     RECT  126.904 145.104 132.008 145.128 ;
     RECT  126.904 150.192 132.008 150.216 ;
     RECT  126.904 153.168 132.008 153.192 ;
     RECT  126.904 154.224 132.008 154.296 ;
     RECT  132.008 2.148 132.112 244.092 ;
     RECT  132.112 2.418 132.304 243.822 ;
     RECT  132.304 94.848 137.408 95.496 ;
     RECT  132.304 98.928 137.408 98.952 ;
     RECT  132.304 100.56 137.408 101.4 ;
     RECT  132.304 102.672 137.408 103.272 ;
     RECT  132.304 104.256 137.408 104.28 ;
     RECT  132.304 107.52 137.408 107.544 ;
     RECT  132.304 111.552 137.408 111.576 ;
     RECT  132.304 113.184 137.408 113.208 ;
     RECT  132.304 117.12 137.408 117.144 ;
     RECT  132.304 118.608 137.408 118.632 ;
     RECT  132.304 121.296 137.408 121.32 ;
     RECT  132.304 123.024 137.408 123.048 ;
     RECT  132.304 124.368 137.408 125.112 ;
     RECT  132.304 128.592 137.408 128.616 ;
     RECT  132.304 130.992 137.408 131.304 ;
     RECT  132.304 143.76 137.408 143.784 ;
     RECT  132.304 145.104 137.408 145.128 ;
     RECT  132.304 150.192 137.408 150.216 ;
     RECT  132.304 153.168 137.408 153.192 ;
     RECT  132.304 154.224 137.408 154.296 ;
     RECT  137.408 2.148 137.512 244.092 ;
     RECT  137.512 2.418 137.704 243.822 ;
     RECT  137.704 117.024 138.557 117.144 ;
     RECT  137.704 94.848 142.808 95.496 ;
     RECT  137.704 98.928 142.808 98.952 ;
     RECT  137.704 100.56 142.808 101.4 ;
     RECT  137.704 102.672 142.808 103.272 ;
     RECT  137.704 104.256 142.808 104.28 ;
     RECT  137.704 107.52 142.808 107.544 ;
     RECT  137.704 111.552 142.808 111.576 ;
     RECT  137.704 113.184 142.808 113.208 ;
     RECT  138.557 117.024 142.808 117.048 ;
     RECT  137.704 118.608 142.808 118.632 ;
     RECT  137.704 121.296 142.808 121.32 ;
     RECT  137.704 123.024 142.808 123.048 ;
     RECT  137.704 124.368 142.808 125.112 ;
     RECT  137.704 128.592 142.808 128.616 ;
     RECT  137.704 130.992 142.808 131.304 ;
     RECT  137.704 143.76 142.808 143.784 ;
     RECT  137.704 145.104 142.808 145.128 ;
     RECT  137.704 150.192 142.808 150.216 ;
     RECT  137.704 153.168 142.808 153.192 ;
     RECT  137.704 154.224 142.808 154.296 ;
     RECT  142.808 2.148 142.912 244.092 ;
     RECT  142.912 2.418 143.104 243.822 ;
     RECT  143.104 94.848 145.073 95.496 ;
     RECT  143.104 104.256 146.005 104.28 ;
     RECT  143.104 111.552 146.005 111.576 ;
     RECT  145.073 95.472 146.041 95.496 ;
     RECT  143.104 124.368 146.149 125.112 ;
     RECT  143.104 128.592 146.149 128.616 ;
     RECT  146.149 127.68 146.233 128.616 ;
     RECT  146.005 110.736 146.473 111.576 ;
     RECT  143.104 117.12 146.473 117.144 ;
     RECT  146.396 109.296 146.483 109.32 ;
     RECT  146.473 110.736 146.513 111.672 ;
     RECT  146.149 124.368 146.549 125.928 ;
     RECT  143.104 107.52 146.761 107.544 ;
     RECT  143.104 98.928 146.869 98.952 ;
     RECT  146.041 95.184 147.109 95.496 ;
     RECT  143.104 121.296 147.229 121.32 ;
     RECT  147.229 121.296 147.308 121.848 ;
     RECT  143.104 123.024 147.308 123.048 ;
     RECT  147.308 134.928 147.337 134.952 ;
     RECT  143.104 150.192 147.337 150.216 ;
     RECT  147.337 134.64 147.349 134.952 ;
     RECT  147.337 136.224 147.349 136.248 ;
     RECT  146.041 115.632 147.409 115.656 ;
     RECT  146.473 117.12 147.409 117.288 ;
     RECT  146.513 110.832 147.493 111.672 ;
     RECT  143.104 113.184 147.493 113.208 ;
     RECT  143.104 102.672 147.517 103.272 ;
     RECT  146.005 104.256 147.517 105.096 ;
     RECT  143.104 118.608 147.517 118.632 ;
     RECT  143.104 143.76 147.517 143.784 ;
     RECT  143.104 145.104 147.517 145.128 ;
     RECT  147.493 110.832 147.553 113.208 ;
     RECT  147.409 115.632 147.589 117.288 ;
     RECT  147.337 133.152 147.637 133.176 ;
     RECT  146.869 98.64 148.028 98.952 ;
     RECT  147.229 97.008 148.069 97.032 ;
     RECT  148.028 98.256 148.069 98.952 ;
     RECT  147.337 150.192 148.201 150.456 ;
     RECT  147.541 93.072 148.208 93.096 ;
     RECT  147.109 94.56 148.208 95.496 ;
     RECT  148.069 97.008 148.208 98.952 ;
     RECT  143.104 100.56 148.208 101.4 ;
     RECT  147.517 102.672 148.208 105.096 ;
     RECT  146.761 107.28 148.208 107.544 ;
     RECT  147.553 110.832 148.208 113.976 ;
     RECT  147.589 115.104 148.208 117.288 ;
     RECT  147.517 118.608 148.208 119.016 ;
     RECT  147.697 120.24 148.208 120.264 ;
     RECT  147.308 121.296 148.208 123.048 ;
     RECT  146.549 125.088 148.208 125.928 ;
     RECT  146.233 128.592 148.208 128.616 ;
     RECT  143.104 130.992 148.208 131.304 ;
     RECT  147.637 132.72 148.208 133.176 ;
     RECT  147.349 134.544 148.208 134.952 ;
     RECT  147.349 136.224 148.208 136.344 ;
     RECT  147.733 138.336 148.208 138.36 ;
     RECT  147.841 141.264 148.208 141.288 ;
     RECT  147.517 143.76 148.208 145.128 ;
     RECT  147.625 148.32 148.208 148.344 ;
     RECT  148.201 150.192 148.208 150.552 ;
     RECT  143.104 153.168 148.208 153.192 ;
     RECT  143.104 154.224 148.208 154.296 ;
     RECT  148.208 2.148 148.312 244.092 ;
     RECT  148.312 2.418 148.504 243.822 ;
     RECT  148.504 115.104 148.565 117.288 ;
     RECT  148.504 138.336 148.643 145.272 ;
     RECT  148.504 147.984 148.709 148.344 ;
     RECT  148.504 121.296 148.739 121.32 ;
     RECT  148.504 118.56 148.78 120.264 ;
     RECT  148.504 100.56 148.781 104.904 ;
     RECT  148.643 138.336 148.781 145.128 ;
     RECT  148.504 109.824 148.787 112.392 ;
     RECT  148.565 115.632 148.787 117.288 ;
     RECT  148.504 127.632 148.787 129.672 ;
     RECT  148.781 138.336 148.787 144.264 ;
     RECT  148.504 149.856 148.787 151.656 ;
     RECT  148.78 118.56 148.789 118.632 ;
     RECT  148.504 94.56 148.817 95.496 ;
     RECT  148.787 111.648 148.825 112.392 ;
     RECT  148.787 109.824 148.828 109.848 ;
     RECT  148.781 100.8 148.835 104.904 ;
     RECT  148.504 106.368 148.835 108.312 ;
     RECT  148.835 107.52 148.853 108.312 ;
     RECT  148.853 107.52 148.876 108.024 ;
     RECT  148.789 118.608 148.889 118.632 ;
     RECT  148.787 140.208 148.925 144.264 ;
     RECT  148.925 140.592 148.961 144.264 ;
     RECT  148.504 98.928 148.997 98.952 ;
     RECT  148.835 100.8 149.075 102.84 ;
     RECT  148.504 153.168 149.075 154.296 ;
     RECT  149.075 102.672 149.097 102.84 ;
     RECT  148.787 149.856 149.105 151.032 ;
     RECT  148.961 140.592 149.149 142.632 ;
     RECT  149.149 140.592 149.171 141.528 ;
     RECT  149.097 102.672 149.213 102.696 ;
     RECT  148.835 104.256 149.213 104.904 ;
     RECT  148.787 116.256 149.213 117.288 ;
     RECT  149.075 100.8 149.249 101.448 ;
     RECT  148.817 94.56 149.267 95.208 ;
     RECT  148.504 131.28 149.267 132.888 ;
     RECT  148.504 92.304 149.308 92.616 ;
     RECT  148.825 111.648 149.357 111.72 ;
     RECT  148.504 96.624 149.363 96.648 ;
     RECT  148.504 134.208 149.363 134.664 ;
     RECT  149.267 131.28 149.393 132.744 ;
     RECT  149.105 149.856 149.393 149.976 ;
     RECT  149.249 100.8 149.429 101.4 ;
     RECT  148.78 119.712 149.429 120.264 ;
     RECT  149.393 149.856 149.429 149.88 ;
     RECT  148.504 97.728 149.465 97.944 ;
     RECT  148.504 124.224 149.677 125.928 ;
     RECT  148.504 136.128 149.681 136.152 ;
     RECT  149.677 124.224 149.785 126.456 ;
     RECT  148.504 146.928 149.785 146.952 ;
     RECT  149.785 146.928 149.786 147 ;
     RECT  148.709 148.224 149.821 148.248 ;
     RECT  149.393 131.28 149.852 132.264 ;
     RECT  149.821 148.224 149.861 148.824 ;
     RECT  149.852 130.416 149.939 132.264 ;
     RECT  149.785 124.224 149.987 126.6 ;
     RECT  149.171 140.592 150.005 140.76 ;
     RECT  149.987 124.224 150.073 125.112 ;
     RECT  150.073 124.128 150.077 125.112 ;
     RECT  149.939 131.28 150.083 132.264 ;
     RECT  150.077 124.128 150.113 124.248 ;
     RECT  148.787 128.592 150.113 129.144 ;
     RECT  149.861 148.8 150.113 148.824 ;
     RECT  150.083 131.28 150.124 131.64 ;
     RECT  149.149 142.608 150.133 142.632 ;
     RECT  148.961 143.76 150.133 144.264 ;
     RECT  150.133 142.464 150.179 142.632 ;
     RECT  150.133 143.712 150.179 144.264 ;
     RECT  149.357 111.696 150.289 111.72 ;
     RECT  150.124 131.28 150.293 131.304 ;
     RECT  149.987 126.432 150.419 126.552 ;
     RECT  150.325 121.968 150.421 121.992 ;
     RECT  150.421 121.248 150.467 121.992 ;
     RECT  150.289 113.376 150.469 113.4 ;
     RECT  149.213 104.256 150.473 104.28 ;
     RECT  149.429 119.712 150.509 119.736 ;
     RECT  150.289 111.696 150.515 112.248 ;
     RECT  150.469 113.376 150.515 114.024 ;
     RECT  150.469 128.256 150.553 128.28 ;
     RECT  149.075 153.36 150.563 154.296 ;
     RECT  150.515 111.696 150.572 111.72 ;
     RECT  150.005 140.736 150.572 140.76 ;
     RECT  150.179 142.464 150.572 142.488 ;
     RECT  150.419 126.528 150.573 126.552 ;
     RECT  150.572 140.736 150.581 142.488 ;
     RECT  150.563 153.888 150.581 154.296 ;
     RECT  150.505 152.16 150.589 152.184 ;
     RECT  150.572 111.264 150.617 111.72 ;
     RECT  150.113 124.128 150.653 124.152 ;
     RECT  150.179 143.712 150.653 143.784 ;
     RECT  150.617 111.264 150.659 111.288 ;
     RECT  150.581 140.736 150.659 141.528 ;
     RECT  150.613 109.392 150.725 109.416 ;
     RECT  150.515 114 150.725 114.024 ;
     RECT  150.581 154.272 150.725 154.296 ;
     RECT  149.429 100.8 150.821 100.824 ;
     RECT  149.465 97.728 150.829 97.752 ;
     RECT  150.812 99.168 150.829 99.192 ;
     RECT  149.213 116.256 150.833 116.28 ;
     RECT  149.213 117.264 150.833 117.288 ;
     RECT  150.653 143.76 150.833 143.784 ;
     RECT  150.469 95.184 150.851 95.208 ;
     RECT  149.893 137.376 150.853 137.928 ;
     RECT  149.308 92.304 150.869 92.328 ;
     RECT  150.805 94.176 150.892 94.2 ;
     RECT  150.829 97.728 150.899 99.192 ;
     RECT  150.853 136.896 150.899 137.928 ;
     RECT  150.821 100.32 150.905 100.824 ;
     RECT  148.835 106.368 150.905 106.392 ;
     RECT  150.467 121.248 150.905 121.272 ;
     RECT  149.821 135.84 150.933 135.864 ;
     RECT  150.853 119.664 150.94 119.688 ;
     RECT  150.899 136.896 150.94 136.92 ;
     RECT  149.786 146.976 150.941 147 ;
     RECT  150.899 97.728 150.947 98.664 ;
     RECT  150.899 137.904 150.997 137.928 ;
     RECT  150.997 137.904 151.043 138.84 ;
     RECT  150.659 140.736 151.043 140.76 ;
     RECT  150.937 149.856 151.043 149.88 ;
     RECT  150.517 150.864 151.043 150.888 ;
     RECT  150.905 100.8 151.049 100.824 ;
     RECT  151.043 138.816 151.084 138.84 ;
     RECT  148.876 107.52 151.193 107.544 ;
     RECT  153.205 92.832 153.889 92.856 ;
     RECT  153.601 110.112 153.889 110.136 ;
     RECT  153.853 125.232 153.889 125.256 ;
     RECT  153.205 145.968 153.889 145.992 ;
     RECT  153.853 152.88 154.105 152.904 ;
     RECT  154.105 152.88 154.393 153.768 ;
     RECT  153.889 92.832 154.429 93.288 ;
     RECT  153.421 95.424 154.429 95.448 ;
     RECT  154.393 101.472 154.429 101.496 ;
     RECT  154.393 105.36 154.429 105.384 ;
     RECT  153.889 110.112 154.429 110.568 ;
     RECT  154.393 113.136 154.429 113.16 ;
     RECT  153.493 114.864 154.429 114.888 ;
     RECT  154.393 116.592 154.429 116.616 ;
     RECT  153.565 123.072 154.429 123.096 ;
     RECT  153.889 125.232 154.429 125.688 ;
     RECT  154.393 138.192 154.429 138.216 ;
     RECT  154.393 140.352 154.429 140.376 ;
     RECT  153.889 142.512 154.429 142.536 ;
     RECT  153.889 145.536 154.429 145.992 ;
     RECT  154.393 147.696 154.429 147.72 ;
     RECT  153.889 149.424 154.429 149.448 ;
     RECT  154.393 152.016 154.429 153.768 ;
     RECT  154.429 91.968 154.465 129.144 ;
     RECT  154.429 130.416 154.465 154.2 ;
     RECT  154.465 91.968 155.484 154.2 ;
    LAYER M5 ;
     RECT  2.4 2.137 2.52 2.151 ;
     RECT  7.8 2.137 7.92 2.151 ;
     RECT  13.2 2.137 13.32 2.151 ;
     RECT  18.6 2.137 18.72 2.151 ;
     RECT  24 2.137 24.12 2.151 ;
     RECT  29.4 2.137 29.52 2.151 ;
     RECT  34.8 2.137 34.92 2.151 ;
     RECT  40.2 2.137 40.32 2.151 ;
     RECT  45.6 2.137 45.72 2.151 ;
     RECT  51 2.137 51.12 2.151 ;
     RECT  56.4 2.137 56.52 2.151 ;
     RECT  61.8 2.137 61.92 2.151 ;
     RECT  67.2 2.137 67.32 2.151 ;
     RECT  72.6 2.137 72.72 2.151 ;
     RECT  78 2.137 78.12 2.151 ;
     RECT  83.4 2.137 83.52 2.151 ;
     RECT  88.8 2.137 88.92 2.151 ;
     RECT  94.2 2.137 94.32 2.151 ;
     RECT  99.6 2.137 99.72 2.151 ;
     RECT  105 2.137 105.12 2.151 ;
     RECT  110.4 2.137 110.52 2.151 ;
     RECT  115.8 2.137 115.92 2.151 ;
     RECT  121.2 2.137 121.32 2.151 ;
     RECT  126.6 2.137 126.72 2.151 ;
     RECT  132 2.137 132.12 2.151 ;
     RECT  137.4 2.137 137.52 2.151 ;
     RECT  142.8 2.137 142.92 2.151 ;
     RECT  148.2 2.137 148.32 2.151 ;
     RECT  2.4 2.151 2.712 6.229 ;
     RECT  7.8 2.151 8.112 7.237 ;
     RECT  7.68 7.237 8.112 7.429 ;
     RECT  4.848 6.613 4.872 8.003 ;
     RECT  6.864 7.429 8.112 8.341 ;
     RECT  2.4 6.229 3.288 9.155 ;
     RECT  6.144 8.341 8.112 10.355 ;
     RECT  4.848 10.501 4.872 10.789 ;
     RECT  6.144 10.355 6.168 10.789 ;
     RECT  4.848 10.789 6.168 11.749 ;
     RECT  4.56 11.749 6.168 12.325 ;
     RECT  4.56 12.325 6.552 12.517 ;
     RECT  4.416 12.517 6.552 14.243 ;
     RECT  1.056 13.909 1.08 14.485 ;
     RECT  4.416 14.243 6.168 14.867 ;
     RECT  4.512 14.867 6.168 17.077 ;
     RECT  4.416 17.077 6.168 18.515 ;
     RECT  4.416 18.515 4.44 19.669 ;
     RECT  5.472 18.515 6.168 19.669 ;
     RECT  4.416 19.669 6.168 23.317 ;
     RECT  4.416 23.317 6.312 23.893 ;
     RECT  3.984 23.893 6.312 26.243 ;
     RECT  3.984 26.243 6.216 26.771 ;
     RECT  4.32 26.771 6.216 28.405 ;
     RECT  7.68 10.355 8.112 28.405 ;
     RECT  9.12 11.317 9.144 32.341 ;
     RECT  4.32 28.405 8.112 34.165 ;
     RECT  3.936 34.165 8.112 35.939 ;
     RECT  4.32 35.939 8.112 42.133 ;
     RECT  9.12 32.341 9.384 44.341 ;
     RECT  3.696 42.133 8.112 50.101 ;
     RECT  9.12 44.341 9.864 50.101 ;
     RECT  1.056 14.485 1.128 67.717 ;
     RECT  2.4 9.155 2.712 67.717 ;
     RECT  1.056 67.717 2.712 68.197 ;
     RECT  3.696 50.101 9.864 68.197 ;
     RECT  1.056 68.197 9.864 68.341 ;
     RECT  10.848 13.621 10.872 68.341 ;
     RECT  18.6 2.151 18.912 69.781 ;
     RECT  13.2 2.151 13.512 72.421 ;
     RECT  13.2 72.421 13.704 72.901 ;
     RECT  21.552 74.629 21.576 76.645 ;
     RECT  21.36 76.645 21.576 76.691 ;
     RECT  12.384 72.901 13.704 78.133 ;
     RECT  1.056 68.341 10.872 78.373 ;
     RECT  0.432 78.373 10.872 78.565 ;
     RECT  12.384 78.133 13.848 78.565 ;
     RECT  15.84 57.301 15.864 78.901 ;
     RECT  24 2.151 24.312 81.397 ;
     RECT  0.432 78.565 13.848 81.973 ;
     RECT  18 69.781 18.912 83.509 ;
     RECT  15.648 78.901 15.864 83.605 ;
     RECT  17.184 83.509 18.912 83.605 ;
     RECT  24 81.397 24.552 84.565 ;
     RECT  15.648 83.605 18.912 84.901 ;
     RECT  15.648 84.901 19.224 84.995 ;
     RECT  24 84.565 25.32 85.381 ;
     RECT  26.784 84.277 26.808 85.381 ;
     RECT  15.744 84.995 19.224 85.717 ;
     RECT  24 85.381 26.808 85.909 ;
     RECT  21.36 76.691 21.384 86.053 ;
     RECT  15.744 85.717 19.704 86.341 ;
     RECT  15.456 86.341 19.704 86.389 ;
     RECT  0.432 81.973 14.184 86.629 ;
     RECT  15.456 86.389 20.04 86.629 ;
     RECT  21.36 86.053 21.48 86.629 ;
     RECT  22.8 80.485 22.824 86.629 ;
     RECT  0.432 86.629 20.04 86.725 ;
     RECT  21.264 86.629 21.48 86.725 ;
     RECT  0.432 86.725 21.48 86.821 ;
     RECT  22.8 86.629 22.92 86.821 ;
     RECT  22.752 86.821 22.92 87.589 ;
     RECT  24 85.909 26.952 87.589 ;
     RECT  0.432 86.821 21.624 88.309 ;
     RECT  0.432 88.309 21.672 89.221 ;
     RECT  22.752 87.589 26.952 89.221 ;
     RECT  0.432 89.221 26.952 91.381 ;
     RECT  148.2 2.151 148.512 92.581 ;
     RECT  148.2 92.581 149.256 93.061 ;
     RECT  52.656 93.781 52.68 93.829 ;
     RECT  52.464 93.829 52.68 94.067 ;
     RECT  147.552 93.061 149.256 94.549 ;
     RECT  0.384 91.381 26.952 94.933 ;
     RECT  147.12 94.549 149.256 95.219 ;
     RECT  150.816 94.165 150.84 95.219 ;
     RECT  148.2 95.219 148.512 96.613 ;
     RECT  148.2 96.613 149.352 96.997 ;
     RECT  148.08 96.997 149.352 97.763 ;
     RECT  148.08 97.763 148.776 98.675 ;
     RECT  150.912 97.717 150.936 98.675 ;
     RECT  150.864 99.157 150.888 100.355 ;
     RECT  148.2 98.675 148.776 101.413 ;
     RECT  148.2 101.413 149.064 102.851 ;
     RECT  0.336 94.933 26.952 103.141 ;
     RECT  148.2 102.851 148.824 104.915 ;
     RECT  52.56 94.067 52.584 105.973 ;
     RECT  80.064 93.733 80.088 106.021 ;
     RECT  80.064 106.021 80.232 106.067 ;
     RECT  85.488 104.245 85.512 106.403 ;
     RECT  148.2 104.915 148.512 107.269 ;
     RECT  148.2 107.269 148.824 108.035 ;
     RECT  148.2 108.035 148.512 109.813 ;
     RECT  146.448 109.285 146.472 110.771 ;
     RECT  150.624 109.381 150.648 111.299 ;
     RECT  0.336 103.141 27.144 111.443 ;
     RECT  148.2 109.813 148.776 112.213 ;
     RECT  150.48 111.685 150.504 112.259 ;
     RECT  147.504 112.213 148.776 112.403 ;
     RECT  80.208 106.067 80.232 112.883 ;
     RECT  147.504 112.403 148.512 113.173 ;
     RECT  150.48 113.365 150.504 114.035 ;
     RECT  0.336 111.443 26.904 114.371 ;
     RECT  52.56 105.973 52.728 115.187 ;
     RECT  147.264 113.173 148.512 115.621 ;
     RECT  147.264 115.621 148.776 118.595 ;
     RECT  0.384 114.371 26.904 119.459 ;
     RECT  147.264 118.595 148.728 120.275 ;
     RECT  0.384 119.459 25.896 121.139 ;
     RECT  150.864 119.653 150.888 121.237 ;
     RECT  150.432 121.237 150.888 121.283 ;
     RECT  147.264 120.275 148.512 121.285 ;
     RECT  147.264 121.285 148.728 121.475 ;
     RECT  150.432 121.283 150.456 122.003 ;
     RECT  0.432 121.139 25.896 122.435 ;
     RECT  53.808 115.669 53.832 124.549 ;
     RECT  53.808 124.549 54.072 124.595 ;
     RECT  78 2.151 78.312 124.645 ;
     RECT  26.88 119.459 26.904 124.691 ;
     RECT  147.36 121.475 148.728 124.789 ;
     RECT  32.16 119.653 32.184 125.123 ;
     RECT  146.4 124.789 148.728 125.797 ;
     RECT  146.4 125.797 149.256 125.893 ;
     RECT  146.16 125.893 149.256 125.939 ;
     RECT  147.36 125.939 149.256 125.941 ;
     RECT  147.36 125.941 149.976 126.421 ;
     RECT  147.36 126.421 150.408 126.517 ;
     RECT  147.36 126.517 150.504 126.611 ;
     RECT  154.464 126.517 154.488 126.659 ;
     RECT  146.16 125.939 146.184 127.715 ;
     RECT  150.48 126.611 150.504 128.291 ;
     RECT  147.36 126.611 149.256 129.109 ;
     RECT  0.432 122.435 25.8 129.155 ;
     RECT  0.432 129.155 25.752 129.491 ;
     RECT  147.36 129.109 149.928 131.605 ;
     RECT  0.48 129.491 25.752 131.891 ;
     RECT  147.36 131.605 150.072 132.275 ;
     RECT  0.48 131.891 25.704 133.523 ;
     RECT  0.48 133.523 25.128 133.715 ;
     RECT  0.48 133.715 20.856 133.763 ;
     RECT  0.48 133.763 20.76 134.675 ;
     RECT  0.48 134.675 20.232 134.723 ;
     RECT  0.48 134.723 18.912 134.819 ;
     RECT  22.128 133.715 25.128 134.819 ;
     RECT  21.6 135.013 21.624 135.203 ;
     RECT  22.848 134.819 25.128 135.347 ;
     RECT  0.48 134.819 17.592 135.395 ;
     RECT  0.528 135.395 17.592 135.539 ;
     RECT  23.232 135.347 25.128 135.923 ;
     RECT  24 135.923 25.128 136.019 ;
     RECT  147.36 132.275 149.352 136.163 ;
     RECT  54.048 124.595 54.072 136.835 ;
     RECT  56.4 2.151 56.712 137.317 ;
     RECT  150.864 135.829 150.888 137.411 ;
     RECT  20.064 134.723 20.232 137.507 ;
     RECT  0.528 135.539 17.4 137.795 ;
     RECT  72.6 2.151 72.912 138.469 ;
     RECT  18.6 134.819 18.912 139.093 ;
     RECT  20.112 137.507 20.232 139.093 ;
     RECT  18.6 139.093 20.232 139.379 ;
     RECT  0.528 137.795 16.92 140.197 ;
     RECT  18.6 139.379 19.704 140.483 ;
     RECT  151.008 137.893 151.032 140.725 ;
     RECT  150.624 140.725 151.032 140.771 ;
     RECT  0.528 140.197 17.112 140.819 ;
     RECT  0.528 140.819 16.92 141.395 ;
     RECT  147.36 136.163 149.16 141.539 ;
     RECT  150.624 140.771 150.648 141.539 ;
     RECT  18.6 140.483 19.272 142.115 ;
     RECT  0.528 141.395 16.728 142.499 ;
     RECT  43.824 124.213 43.848 143.795 ;
     RECT  150.144 142.453 150.168 144.275 ;
     RECT  0.528 142.499 15.144 144.947 ;
     RECT  147.36 141.539 149.112 149.891 ;
     RECT  52.704 115.187 52.728 150.227 ;
     RECT  151.008 149.845 151.032 150.853 ;
     RECT  150.528 150.853 151.032 150.899 ;
     RECT  16.176 142.499 16.728 152.149 ;
     RECT  72.6 138.469 73.32 152.437 ;
     RECT  147.36 149.891 149.064 153.203 ;
     RECT  150.528 150.899 150.552 153.923 ;
     RECT  71.904 152.437 73.32 154.115 ;
     RECT  147.36 153.203 148.512 154.259 ;
     RECT  15.936 152.149 16.728 157.955 ;
     RECT  45.6 2.151 45.912 158.437 ;
     RECT  51 2.151 51.312 158.437 ;
     RECT  55.584 137.317 56.712 158.437 ;
     RECT  67.2 2.151 67.512 158.437 ;
     RECT  69.12 153.301 69.144 158.531 ;
     RECT  45.6 158.437 46.776 158.579 ;
     RECT  50.688 158.437 51.312 158.579 ;
     RECT  54.624 158.437 56.712 158.579 ;
     RECT  58.704 158.437 58.728 158.579 ;
     RECT  66.672 158.437 67.512 158.579 ;
     RECT  16.272 157.955 16.728 159.109 ;
     RECT  16.272 159.109 17.16 159.635 ;
     RECT  16.272 159.635 16.728 167.747 ;
     RECT  22.464 158.533 22.488 175.043 ;
     RECT  0.528 144.947 14.52 179.651 ;
     RECT  1.68 179.651 14.52 183.443 ;
     RECT  1.68 183.443 14.28 186.371 ;
     RECT  6.912 186.371 14.28 186.419 ;
     RECT  6.912 186.419 9.528 190.451 ;
     RECT  1.68 186.371 5.688 192.131 ;
     RECT  16.704 167.747 16.728 194.435 ;
     RECT  7.152 190.451 9.528 194.725 ;
     RECT  10.512 186.419 14.28 198.803 ;
     RECT  7.008 194.725 9.528 199.189 ;
     RECT  6.288 199.189 9.528 200.627 ;
     RECT  7.008 200.627 9.528 202.403 ;
     RECT  10.512 198.803 10.584 202.883 ;
     RECT  6.096 203.749 6.12 204.371 ;
     RECT  7.296 202.403 9.528 205.333 ;
     RECT  11.664 198.803 14.28 207.299 ;
     RECT  6.048 206.245 6.072 207.445 ;
     RECT  7.2 205.333 9.528 207.445 ;
     RECT  6.048 207.445 9.528 207.491 ;
     RECT  1.68 192.131 5.064 208.643 ;
     RECT  11.664 207.299 11.688 209.075 ;
     RECT  1.68 208.643 4.68 209.843 ;
     RECT  1.68 209.843 4.632 210.467 ;
     RECT  6.816 207.491 9.528 210.659 ;
     RECT  10.512 202.883 10.536 212.099 ;
     RECT  2.304 210.467 4.632 213.301 ;
     RECT  7.2 210.659 9.528 213.685 ;
     RECT  0.528 179.651 0.552 214.213 ;
     RECT  0.144 214.213 0.552 214.499 ;
     RECT  0.528 214.499 0.552 215.075 ;
     RECT  2.304 213.301 4.92 216.707 ;
     RECT  71.904 154.115 72.912 217.715 ;
     RECT  2.304 216.707 3.864 217.763 ;
     RECT  4.896 216.707 4.92 218.245 ;
     RECT  4.272 218.245 4.92 218.915 ;
     RECT  4.896 218.915 4.92 219.397 ;
     RECT  4.896 219.397 5.304 220.019 ;
     RECT  6.576 213.685 9.528 223.333 ;
     RECT  13.2 207.299 14.28 223.667 ;
     RECT  4.896 220.019 4.92 224.533 ;
     RECT  4.464 224.533 4.92 225.779 ;
     RECT  6.336 223.333 9.528 225.779 ;
     RECT  6.336 225.779 9.384 226.355 ;
     RECT  4.896 225.779 4.92 226.837 ;
     RECT  6.576 226.355 9.384 226.883 ;
     RECT  4.848 226.837 4.92 227.365 ;
     RECT  7.344 226.883 9.384 230.915 ;
     RECT  2.304 217.763 2.952 232.019 ;
     RECT  7.44 230.915 9.384 232.019 ;
     RECT  3.936 227.365 4.92 232.259 ;
     RECT  4.608 232.259 4.92 232.787 ;
     RECT  7.8 232.019 9.384 234.179 ;
     RECT  4.608 232.787 4.632 235.381 ;
     RECT  3.984 235.381 4.632 236.003 ;
     RECT  7.8 234.179 8.616 237.155 ;
     RECT  6.24 237.061 6.264 238.163 ;
     RECT  4.608 236.003 4.632 238.261 ;
     RECT  4.56 238.261 4.632 238.883 ;
     RECT  4.56 238.883 4.584 239.795 ;
     RECT  2.4 232.019 2.952 239.891 ;
     RECT  2.4 239.891 2.712 244.089 ;
     RECT  7.8 237.155 8.112 244.089 ;
     RECT  13.2 223.667 13.512 244.089 ;
     RECT  18.6 142.115 18.912 244.089 ;
     RECT  24 136.019 24.312 244.089 ;
     RECT  29.4 2.151 29.712 244.089 ;
     RECT  34.8 2.151 35.112 244.089 ;
     RECT  40.2 2.151 40.512 244.089 ;
     RECT  45.6 158.579 45.912 244.089 ;
     RECT  51 158.579 51.312 244.089 ;
     RECT  56.4 158.579 56.712 244.089 ;
     RECT  61.8 2.151 62.112 244.089 ;
     RECT  67.2 158.579 67.512 244.089 ;
     RECT  72.6 217.715 72.912 244.089 ;
     RECT  77.52 124.645 78.312 244.089 ;
     RECT  83.4 2.151 83.712 244.089 ;
     RECT  88.8 2.151 89.112 244.089 ;
     RECT  94.2 2.151 94.512 244.089 ;
     RECT  99.6 2.151 99.912 244.089 ;
     RECT  105 2.151 105.312 244.089 ;
     RECT  110.4 2.151 110.712 244.089 ;
     RECT  115.8 2.151 116.112 244.089 ;
     RECT  121.2 2.151 121.512 244.089 ;
     RECT  126.6 2.151 126.912 244.089 ;
     RECT  132 2.151 132.312 244.089 ;
     RECT  137.4 2.151 137.712 244.089 ;
     RECT  142.8 2.151 143.112 244.089 ;
     RECT  148.2 154.259 148.512 244.089 ;
     RECT  2.4 244.089 2.52 244.103 ;
     RECT  7.8 244.089 7.92 244.103 ;
     RECT  13.2 244.089 13.32 244.103 ;
     RECT  18.6 244.089 18.72 244.103 ;
     RECT  24 244.089 24.12 244.103 ;
     RECT  29.4 244.089 29.52 244.103 ;
     RECT  34.8 244.089 34.92 244.103 ;
     RECT  40.2 244.089 40.32 244.103 ;
     RECT  45.6 244.089 45.72 244.103 ;
     RECT  51 244.089 51.12 244.103 ;
     RECT  56.4 244.089 56.52 244.103 ;
     RECT  61.8 244.089 61.92 244.103 ;
     RECT  67.2 244.089 67.32 244.103 ;
     RECT  72.6 244.089 72.72 244.103 ;
     RECT  77.52 244.089 78.12 244.103 ;
     RECT  83.4 244.089 83.52 244.103 ;
     RECT  88.8 244.089 88.92 244.103 ;
     RECT  94.2 244.089 94.32 244.103 ;
     RECT  99.6 244.089 99.72 244.103 ;
     RECT  105 244.089 105.12 244.103 ;
     RECT  110.4 244.089 110.52 244.103 ;
     RECT  115.8 244.089 115.92 244.103 ;
     RECT  121.2 244.089 121.32 244.103 ;
     RECT  126.6 244.089 126.72 244.103 ;
     RECT  132 244.089 132.12 244.103 ;
     RECT  137.4 244.089 137.52 244.103 ;
     RECT  142.8 244.089 142.92 244.103 ;
     RECT  148.2 244.089 148.32 244.103 ;
     RECT  77.52 244.103 77.88 246.085 ;
     RECT  77.52 246.085 77.976 246.224 ;
     RECT  6.168 10.355 7.68 12.325 ;
     RECT  4.872 10.501 6.144 10.789 ;
     RECT  8.112 11.317 9.12 50.101 ;
     RECT  6.552 12.325 7.68 14.243 ;
     RECT  1.08 13.909 2.4 14.485 ;
     RECT  6.168 14.243 7.68 23.317 ;
     RECT  1.128 14.485 2.4 67.717 ;
     RECT  4.44 18.515 5.472 19.669 ;
     RECT  6.312 23.317 7.68 26.243 ;
     RECT  2.712 23.893 3.984 26.771 ;
     RECT  6.216 26.243 7.68 28.405 ;
     RECT  9.384 32.341 10.848 44.341 ;
     RECT  2.712 34.165 3.936 35.939 ;
     RECT  2.712 42.133 3.696 68.197 ;
     RECT  9.864 44.341 10.848 68.341 ;
     RECT  10.872 72.901 12.384 78.565 ;
     RECT  21.384 80.485 22.8 86.053 ;
     RECT  22.824 80.485 24 86.629 ;
     RECT  14.184 81.973 15.648 84.995 ;
     RECT  15.864 83.509 17.184 83.605 ;
     RECT  25.32 84.565 26.784 85.381 ;
     RECT  14.184 84.995 15.744 86.341 ;
     RECT  21.48 86.053 22.8 86.821 ;
     RECT  14.184 86.341 15.456 86.629 ;
     RECT  20.04 86.389 21.36 86.629 ;
     RECT  20.04 86.629 21.264 86.725 ;
     RECT  22.92 86.629 24 87.589 ;
     RECT  21.624 86.821 22.752 88.309 ;
     RECT  21.672 88.309 22.752 89.221 ;
     RECT  51.312 93.781 52.656 93.829 ;
     RECT  51.312 93.829 52.464 94.067 ;
     RECT  51.312 94.067 52.56 115.187 ;
     RECT  148.512 95.219 149.256 96.613 ;
     RECT  150.48 112.259 150.504 113.365 ;
     RECT  51.312 115.187 52.704 150.227 ;
     RECT  52.728 115.669 53.808 124.595 ;
     RECT  25.896 119.459 26.88 122.435 ;
     RECT  148.512 120.275 148.728 121.285 ;
     RECT  25.8 122.435 26.88 124.691 ;
     RECT  52.728 124.595 54.048 136.835 ;
     RECT  146.184 125.939 147.36 127.715 ;
     RECT  149.256 126.611 150.48 128.291 ;
     RECT  149.256 128.291 149.928 129.109 ;
     RECT  20.856 133.715 22.128 133.763 ;
     RECT  20.76 133.763 22.128 134.675 ;
     RECT  20.232 134.675 22.128 134.819 ;
     RECT  18.912 134.723 20.064 137.507 ;
     RECT  17.592 134.819 18.6 135.539 ;
     RECT  20.232 134.819 22.848 135.013 ;
     RECT  20.232 135.013 21.6 135.203 ;
     RECT  21.624 135.013 22.848 135.203 ;
     RECT  17.4 135.539 18.6 137.795 ;
     RECT  149.352 135.829 150.864 136.163 ;
     RECT  18.912 137.507 20.112 139.093 ;
     RECT  17.112 140.197 18.6 140.819 ;
     RECT  149.16 140.725 150.624 141.539 ;
     RECT  149.112 141.539 150.168 142.453 ;
     RECT  149.112 142.453 150.144 144.275 ;
     RECT  15.144 142.499 16.176 144.947 ;
     RECT  149.064 149.891 149.112 150.853 ;
     RECT  149.064 150.853 150.528 153.203 ;
     RECT  14.52 152.149 15.936 157.955 ;
     RECT  22.488 158.533 24 175.043 ;
     RECT  17.16 159.109 18.6 159.635 ;
     RECT  0.552 179.651 1.68 210.467 ;
     RECT  5.688 186.371 6.912 190.451 ;
     RECT  9.528 186.419 10.512 212.099 ;
     RECT  5.688 190.451 7.152 192.131 ;
     RECT  10.584 198.803 11.664 202.883 ;
     RECT  5.064 199.189 6.288 200.627 ;
     RECT  7.008 202.403 7.296 203.749 ;
     RECT  10.536 202.883 11.664 209.075 ;
     RECT  5.064 203.749 6.096 204.371 ;
     RECT  6.12 203.749 7.296 204.371 ;
     RECT  7.2 204.371 7.296 205.333 ;
     RECT  5.064 206.245 6.048 207.491 ;
     RECT  6.072 206.245 7.2 207.445 ;
     RECT  11.688 207.299 13.2 209.075 ;
     RECT  3.864 216.707 4.896 217.763 ;
     RECT  2.952 217.763 4.896 218.245 ;
     RECT  2.952 218.245 4.272 218.915 ;
     RECT  5.304 219.397 6.576 220.019 ;
     RECT  4.92 223.333 6.336 226.355 ;
     RECT  2.952 224.533 4.464 225.779 ;
     RECT  4.848 225.779 4.896 226.837 ;
     RECT  2.952 227.365 3.936 232.259 ;
     RECT  2.952 235.381 3.984 236.003 ;
  END
END dsfd_vm_static_fsr_b2
END LIBRARY
